VERSION 5.8 ;
BUSBITCHARS "[]" ;
DIVIDERCHAR "/" ;
UNITS
    DATABASE MICRONS 1000 ;
END UNITS

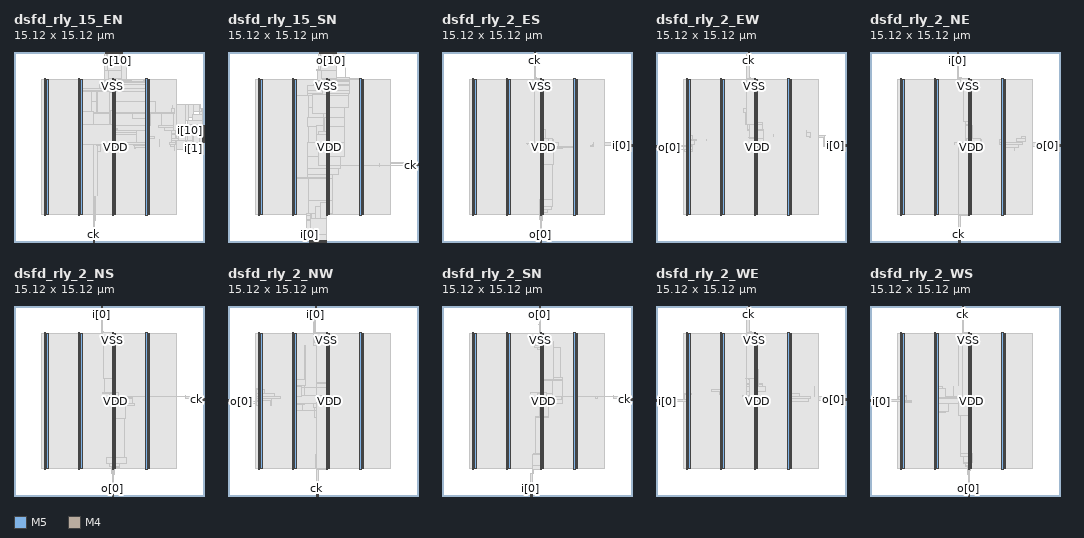
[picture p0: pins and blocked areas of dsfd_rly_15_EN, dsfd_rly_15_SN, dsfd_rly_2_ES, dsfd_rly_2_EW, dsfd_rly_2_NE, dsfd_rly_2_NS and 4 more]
MACRO dsfd_rly_15_EN
  FOREIGN dsfd_rly_15_EN 0 0 ;
  CLASS BLOCK ;
  SIZE 15.12 BY 15.12 ;
  PIN ck
    DIRECTION INPUT ;
    USE SIGNAL ;
    PORT
      LAYER M5 ;
        RECT  6.288 0 6.312 0.084 ;
    END
  END ck
  PIN i[0]
    DIRECTION INPUT ;
    USE SIGNAL ;
    PORT
      LAYER M4 ;
        RECT  15.036 7.92 15.12 7.944 ;
    END
  END i[0]
  PIN i[10]
    DIRECTION INPUT ;
    USE SIGNAL ;
    PORT
      LAYER M4 ;
        RECT  15.036 8.88 15.12 8.904 ;
    END
  END i[10]
  PIN i[11]
    DIRECTION INPUT ;
    USE SIGNAL ;
    PORT
      LAYER M4 ;
        RECT  15.036 8.976 15.12 9 ;
    END
  END i[11]
  PIN i[12]
    DIRECTION INPUT ;
    USE SIGNAL ;
    PORT
      LAYER M4 ;
        RECT  15.036 9.072 15.12 9.096 ;
    END
  END i[12]
  PIN i[13]
    DIRECTION INPUT ;
    USE SIGNAL ;
    PORT
      LAYER M4 ;
        RECT  15.036 9.168 15.12 9.192 ;
    END
  END i[13]
  PIN i[14]
    DIRECTION INPUT ;
    USE SIGNAL ;
    PORT
      LAYER M4 ;
        RECT  15.036 9.264 15.12 9.288 ;
    END
  END i[14]
  PIN i[1]
    DIRECTION INPUT ;
    USE SIGNAL ;
    PORT
      LAYER M4 ;
        RECT  15.036 8.016 15.12 8.04 ;
    END
  END i[1]
  PIN i[2]
    DIRECTION INPUT ;
    USE SIGNAL ;
    PORT
      LAYER M4 ;
        RECT  15.036 8.112 15.12 8.136 ;
    END
  END i[2]
  PIN i[3]
    DIRECTION INPUT ;
    USE SIGNAL ;
    PORT
      LAYER M4 ;
        RECT  15.036 8.208 15.12 8.232 ;
    END
  END i[3]
  PIN i[4]
    DIRECTION INPUT ;
    USE SIGNAL ;
    PORT
      LAYER M4 ;
        RECT  15.036 8.304 15.12 8.328 ;
    END
  END i[4]
  PIN i[5]
    DIRECTION INPUT ;
    USE SIGNAL ;
    PORT
      LAYER M4 ;
        RECT  15.036 8.4 15.12 8.424 ;
    END
  END i[5]
  PIN i[6]
    DIRECTION INPUT ;
    USE SIGNAL ;
    PORT
      LAYER M4 ;
        RECT  15.036 8.496 15.12 8.52 ;
    END
  END i[6]
  PIN i[7]
    DIRECTION INPUT ;
    USE SIGNAL ;
    PORT
      LAYER M4 ;
        RECT  15.036 8.592 15.12 8.616 ;
    END
  END i[7]
  PIN i[8]
    DIRECTION INPUT ;
    USE SIGNAL ;
    PORT
      LAYER M4 ;
        RECT  15.036 8.688 15.12 8.712 ;
    END
  END i[8]
  PIN i[9]
    DIRECTION INPUT ;
    USE SIGNAL ;
    PORT
      LAYER M4 ;
        RECT  15.036 8.784 15.12 8.808 ;
    END
  END i[9]
  PIN o[0]
    DIRECTION OUTPUT ;
    USE SIGNAL ;
    PORT
      LAYER M5 ;
        RECT  7.248 15.036 7.272 15.12 ;
    END
  END o[0]
  PIN o[10]
    DIRECTION OUTPUT ;
    USE SIGNAL ;
    PORT
      LAYER M5 ;
        RECT  8.208 15.036 8.232 15.12 ;
    END
  END o[10]
  PIN o[11]
    DIRECTION OUTPUT ;
    USE SIGNAL ;
    PORT
      LAYER M5 ;
        RECT  8.304 15.036 8.328 15.12 ;
    END
  END o[11]
  PIN o[12]
    DIRECTION OUTPUT ;
    USE SIGNAL ;
    PORT
      LAYER M5 ;
        RECT  8.4 15.036 8.424 15.12 ;
    END
  END o[12]
  PIN o[13]
    DIRECTION OUTPUT ;
    USE SIGNAL ;
    PORT
      LAYER M5 ;
        RECT  8.496 15.036 8.52 15.12 ;
    END
  END o[13]
  PIN o[14]
    DIRECTION OUTPUT ;
    USE SIGNAL ;
    PORT
      LAYER M5 ;
        RECT  8.592 15.036 8.616 15.12 ;
    END
  END o[14]
  PIN o[1]
    DIRECTION OUTPUT ;
    USE SIGNAL ;
    PORT
      LAYER M5 ;
        RECT  7.344 15.036 7.368 15.12 ;
    END
  END o[1]
  PIN o[2]
    DIRECTION OUTPUT ;
    USE SIGNAL ;
    PORT
      LAYER M5 ;
        RECT  7.44 15.036 7.464 15.12 ;
    END
  END o[2]
  PIN o[3]
    DIRECTION OUTPUT ;
    USE SIGNAL ;
    PORT
      LAYER M5 ;
        RECT  7.536 15.036 7.56 15.12 ;
    END
  END o[3]
  PIN o[4]
    DIRECTION OUTPUT ;
    USE SIGNAL ;
    PORT
      LAYER M5 ;
        RECT  7.632 15.036 7.656 15.12 ;
    END
  END o[4]
  PIN o[5]
    DIRECTION OUTPUT ;
    USE SIGNAL ;
    PORT
      LAYER M5 ;
        RECT  7.728 15.036 7.752 15.12 ;
    END
  END o[5]
  PIN o[6]
    DIRECTION OUTPUT ;
    USE SIGNAL ;
    PORT
      LAYER M5 ;
        RECT  7.824 15.036 7.848 15.12 ;
    END
  END o[6]
  PIN o[7]
    DIRECTION OUTPUT ;
    USE SIGNAL ;
    PORT
      LAYER M5 ;
        RECT  7.92 15.036 7.944 15.12 ;
    END
  END o[7]
  PIN o[8]
    DIRECTION OUTPUT ;
    USE SIGNAL ;
    PORT
      LAYER M5 ;
        RECT  8.016 15.036 8.04 15.12 ;
    END
  END o[8]
  PIN o[9]
    DIRECTION OUTPUT ;
    USE SIGNAL ;
    PORT
      LAYER M5 ;
        RECT  8.112 15.036 8.136 15.12 ;
    END
  END o[9]
  PIN rs
    DIRECTION INPUT ;
    USE SIGNAL ;
    PORT
      LAYER M5 ;
        RECT  6.384 0 6.408 0.084 ;
    END
  END rs
  PIN VDD
    DIRECTION INOUT ;
    USE POWER ;
    PORT
      LAYER M5 ;
        RECT  10.692 2.151 10.812 12.969 ;
        RECT  7.992 2.151 8.112 12.969 ;
        RECT  5.292 2.151 5.412 12.969 ;
        RECT  2.592 2.151 2.712 12.969 ;
    END
  END VDD
  PIN VSS
    DIRECTION INOUT ;
    USE GROUND ;
    PORT
      LAYER M5 ;
        RECT  10.5 2.137 10.62 12.983 ;
        RECT  7.8 2.137 7.92 12.983 ;
        RECT  5.1 2.137 5.22 12.983 ;
        RECT  2.4 2.137 2.52 12.983 ;
    END
  END VSS
  OBS
    LAYER RVTN ;
     RECT  2.16 2.16 12.96 2.295 ;
     RECT  2.16 2.565 12.96 2.835 ;
     RECT  2.16 3.105 12.96 3.375 ;
     RECT  2.16 3.645 12.96 3.915 ;
     RECT  2.16 4.185 12.96 4.455 ;
     RECT  2.16 4.725 12.96 4.995 ;
     RECT  2.16 5.265 12.96 5.535 ;
     RECT  2.16 5.805 12.96 6.075 ;
     RECT  2.16 6.345 12.96 6.615 ;
     RECT  2.16 6.885 12.96 7.155 ;
     RECT  2.16 7.425 12.96 7.695 ;
     RECT  2.16 7.965 12.96 8.235 ;
     RECT  2.16 8.505 12.96 8.775 ;
     RECT  2.16 9.045 12.96 9.315 ;
     RECT  2.16 9.585 12.96 9.855 ;
     RECT  2.16 10.125 12.96 10.395 ;
     RECT  2.16 10.665 12.96 10.935 ;
     RECT  2.16 11.205 12.96 11.475 ;
     RECT  2.16 11.745 12.96 12.015 ;
     RECT  2.16 12.285 12.96 12.555 ;
     RECT  2.16 12.825 12.96 12.96 ;
    LAYER RVTP ;
     RECT  2.16 2.295 12.96 2.565 ;
     RECT  2.16 2.835 12.96 3.105 ;
     RECT  2.16 3.375 12.96 3.645 ;
     RECT  2.16 3.915 12.96 4.185 ;
     RECT  2.16 4.455 12.96 4.725 ;
     RECT  2.16 4.995 12.96 5.265 ;
     RECT  2.16 5.535 12.96 5.805 ;
     RECT  2.16 6.075 12.96 6.345 ;
     RECT  2.16 6.615 12.96 6.885 ;
     RECT  2.16 7.155 12.96 7.425 ;
     RECT  2.16 7.695 12.96 7.965 ;
     RECT  2.16 8.235 12.96 8.505 ;
     RECT  2.16 8.775 12.96 9.045 ;
     RECT  2.16 9.315 12.96 9.585 ;
     RECT  2.16 9.855 12.96 10.125 ;
     RECT  2.16 10.395 12.96 10.665 ;
     RECT  2.16 10.935 12.96 11.205 ;
     RECT  2.16 11.475 12.96 11.745 ;
     RECT  2.16 12.015 12.96 12.285 ;
     RECT  2.16 12.555 12.96 12.825 ;
    LAYER M1 ;
     RECT  2.16 2.151 12.96 12.969 ;
    LAYER M2 ;
     RECT  2.16 2.151 12.96 12.969 ;
     RECT  12.96 7.398 13.667 10.926 ;
     RECT  13.667 9.63 13.847 10.926 ;
     RECT  13.667 7.398 14.243 8.802 ;
     RECT  14.243 7.398 14.279 7.956 ;
     RECT  13.847 9.9 14.279 10.926 ;
     RECT  14.279 7.938 14.315 7.956 ;
     RECT  14.279 10.368 14.819 10.926 ;
     RECT  14.819 10.368 14.963 10.656 ;
     RECT  14.963 10.368 15.035 10.386 ;
    LAYER M3 ;
     RECT  2.415 2.143 2.505 2.413 ;
     RECT  5.115 2.143 5.205 2.413 ;
     RECT  7.815 2.143 7.905 2.413 ;
     RECT  10.515 2.143 10.605 2.413 ;
     RECT  6.444 1.723 6.462 3.605 ;
     RECT  6.66 3.721 6.678 7.231 ;
     RECT  7.815 2.413 8.097 7.465 ;
     RECT  9.648 7.429 9.666 7.465 ;
     RECT  7.815 7.465 8.478 7.501 ;
     RECT  9.612 7.465 9.666 7.501 ;
     RECT  10.515 2.413 10.797 7.501 ;
     RECT  12.744 7.321 12.762 7.627 ;
     RECT  6.66 7.231 6.894 7.699 ;
     RECT  7.815 7.501 8.55 7.699 ;
     RECT  9.612 7.501 10.797 7.699 ;
     RECT  12.456 7.627 12.762 7.735 ;
     RECT  7.812 7.699 8.55 7.765 ;
     RECT  6.552 7.699 6.894 7.771 ;
     RECT  7.668 7.765 8.55 7.771 ;
     RECT  9.504 7.699 10.797 7.771 ;
     RECT  12.456 7.735 12.834 7.771 ;
     RECT  14.256 7.393 14.274 7.771 ;
     RECT  6.408 7.771 10.797 7.889 ;
     RECT  12.348 7.771 12.834 7.925 ;
     RECT  13.716 7.771 14.274 7.933 ;
     RECT  12.528 7.925 12.834 8.107 ;
     RECT  13.716 7.933 14.31 8.107 ;
     RECT  11.556 7.591 11.574 8.159 ;
     RECT  10.515 7.889 10.797 8.203 ;
     RECT  12.528 8.107 14.31 8.267 ;
     RECT  13.644 8.267 14.31 8.395 ;
     RECT  10.515 8.203 11.142 8.429 ;
     RECT  6.408 7.889 9.738 8.581 ;
     RECT  5.115 2.413 5.397 8.683 ;
     RECT  6.228 8.581 9.738 8.683 ;
     RECT  5.115 8.683 9.738 8.843 ;
     RECT  6.192 8.843 9.738 8.851 ;
     RECT  10.515 8.429 10.797 8.851 ;
     RECT  12.528 8.267 12.834 8.851 ;
     RECT  11.988 8.851 12.834 8.879 ;
     RECT  11.988 8.879 12.69 9.085 ;
     RECT  11.52 9.085 12.69 9.275 ;
     RECT  6.192 8.851 10.797 9.283 ;
     RECT  13.644 8.395 15.03 9.383 ;
     RECT  13.824 9.383 15.03 9.653 ;
     RECT  14.22 9.653 15.03 10.121 ;
     RECT  6.192 9.283 10.854 10.201 ;
     RECT  11.736 9.275 12.69 10.201 ;
     RECT  6.192 10.201 12.762 10.319 ;
     RECT  14.796 10.121 15.03 10.391 ;
     RECT  12.564 10.319 12.762 10.589 ;
     RECT  12.6 10.589 12.762 10.625 ;
     RECT  14.796 10.391 14.958 10.661 ;
     RECT  12.6 10.625 12.618 10.859 ;
     RECT  14.796 10.661 14.814 10.931 ;
     RECT  6.192 10.319 11.286 11.201 ;
     RECT  5.115 8.843 5.397 11.995 ;
     RECT  6.192 11.201 10.797 11.995 ;
     RECT  5.115 11.995 10.797 12.209 ;
     RECT  6.804 12.209 10.797 12.245 ;
     RECT  6.84 12.245 10.797 12.551 ;
     RECT  2.415 2.413 2.697 12.707 ;
     RECT  5.115 12.209 5.397 12.707 ;
     RECT  6.984 12.551 10.797 12.707 ;
     RECT  6.984 12.707 10.605 12.749 ;
     RECT  6.984 12.749 9.342 12.785 ;
     RECT  7.2 12.785 9.342 12.821 ;
     RECT  10.332 12.749 10.605 12.821 ;
     RECT  7.2 12.821 9.054 12.929 ;
     RECT  2.415 12.707 2.505 12.977 ;
     RECT  5.115 12.707 5.205 12.977 ;
     RECT  10.515 12.821 10.605 12.977 ;
     RECT  7.2 12.929 8.982 14.237 ;
     RECT  7.2 14.237 8.478 14.717 ;
     RECT  7.2 14.717 7.398 15.005 ;
     RECT  8.208 14.717 8.478 15.005 ;
    LAYER M4 ;
     RECT  2.408 2.148 2.512 12.972 ;
     RECT  2.512 2.418 2.704 12.702 ;
     RECT  5.108 2.148 5.212 12.972 ;
     RECT  5.212 2.418 5.404 12.702 ;
     RECT  5.404 8.688 6.397 8.712 ;
     RECT  6.373 1.728 6.473 1.752 ;
     RECT  5.404 10.32 6.565 10.344 ;
     RECT  5.404 12 6.565 12.024 ;
     RECT  6.565 10.32 6.611 12.024 ;
     RECT  6.397 7.776 6.853 8.712 ;
     RECT  7.297 13.632 7.475 13.656 ;
     RECT  6.853 7.776 7.585 9.336 ;
     RECT  6.611 10.32 7.585 11.976 ;
     RECT  7.189 14.976 7.765 15 ;
     RECT  7.585 7.776 7.808 11.976 ;
     RECT  7.685 13.056 7.808 13.128 ;
     RECT  7.808 2.148 7.912 13.128 ;
     RECT  7.912 2.418 7.985 13.128 ;
     RECT  7.985 2.418 8.104 13.08 ;
     RECT  8.104 11.184 8.165 11.208 ;
     RECT  8.104 8.976 8.237 9 ;
     RECT  8.104 12.288 8.317 13.08 ;
     RECT  8.317 13.008 8.453 13.08 ;
     RECT  7.765 14.688 8.489 15 ;
     RECT  8.453 13.008 8.561 13.032 ;
     RECT  8.104 7.92 8.597 7.944 ;
     RECT  8.581 14.208 8.993 14.232 ;
     RECT  9.133 10.224 9.421 10.248 ;
     RECT  9.421 9.792 10.508 10.248 ;
     RECT  10.508 2.148 10.612 12.972 ;
     RECT  10.612 2.418 10.804 12.702 ;
     RECT  12.589 8.592 13.057 8.616 ;
     RECT  13.057 8.112 13.633 8.616 ;
     RECT  13.633 8.112 13.813 9 ;
     RECT  13.813 8.112 14.209 9.096 ;
     RECT  14.209 8.016 14.245 9.192 ;
     RECT  14.245 7.92 14.785 9.192 ;
     RECT  14.785 7.92 15.084 9.288 ;
    LAYER M5 ;
     RECT  6.288 0.016 6.408 1.763 ;
     RECT  2.4 2.137 2.52 2.151 ;
     RECT  5.1 2.137 5.22 2.151 ;
     RECT  6.288 1.763 6.312 2.151 ;
     RECT  7.8 2.137 7.92 2.151 ;
     RECT  10.5 2.137 10.62 2.151 ;
     RECT  5.1 2.151 6.312 7.765 ;
     RECT  7.8 2.151 8.112 7.765 ;
     RECT  5.1 7.765 8.112 9.347 ;
     RECT  5.1 9.347 6.312 10.355 ;
     RECT  7.68 9.347 8.112 10.451 ;
     RECT  7.8 10.451 8.112 11.893 ;
     RECT  6.576 11.173 6.6 11.941 ;
     RECT  7.632 11.893 8.112 11.941 ;
     RECT  6.576 11.941 8.112 12.035 ;
     RECT  7.536 12.035 8.112 12.277 ;
     RECT  2.4 2.151 2.712 12.969 ;
     RECT  5.1 10.355 5.412 12.969 ;
     RECT  10.5 2.151 10.812 12.969 ;
     RECT  2.4 12.969 2.52 12.983 ;
     RECT  5.1 12.969 5.22 12.983 ;
     RECT  10.5 12.969 10.62 12.983 ;
     RECT  7.536 12.277 8.28 12.997 ;
     RECT  7.536 12.997 8.52 13.621 ;
     RECT  7.44 13.621 8.52 14.197 ;
     RECT  7.44 14.197 8.616 14.965 ;
     RECT  7.248 14.965 8.616 15.056 ;
  END
END dsfd_rly_15_EN

VERSION 5.8 ;
BUSBITCHARS "[]" ;
DIVIDERCHAR "/" ;
UNITS
    DATABASE MICRONS 1000 ;
END UNITS

MACRO dsfd_rly_15_SN
  FOREIGN dsfd_rly_15_SN 0 0 ;
  CLASS BLOCK ;
  SIZE 15.12 BY 15.12 ;
  PIN ck
    DIRECTION INPUT ;
    USE SIGNAL ;
    PORT
      LAYER M4 ;
        RECT  15.036 6.096 15.12 6.12 ;
    END
  END ck
  PIN i[0]
    DIRECTION INPUT ;
    USE SIGNAL ;
    PORT
      LAYER M5 ;
        RECT  6.48 0 6.504 0.084 ;
    END
  END i[0]
  PIN i[10]
    DIRECTION INPUT ;
    USE SIGNAL ;
    PORT
      LAYER M5 ;
        RECT  7.44 0 7.464 0.084 ;
    END
  END i[10]
  PIN i[11]
    DIRECTION INPUT ;
    USE SIGNAL ;
    PORT
      LAYER M5 ;
        RECT  7.536 0 7.56 0.084 ;
    END
  END i[11]
  PIN i[12]
    DIRECTION INPUT ;
    USE SIGNAL ;
    PORT
      LAYER M5 ;
        RECT  7.632 0 7.656 0.084 ;
    END
  END i[12]
  PIN i[13]
    DIRECTION INPUT ;
    USE SIGNAL ;
    PORT
      LAYER M5 ;
        RECT  7.728 0 7.752 0.084 ;
    END
  END i[13]
  PIN i[14]
    DIRECTION INPUT ;
    USE SIGNAL ;
    PORT
      LAYER M5 ;
        RECT  7.824 0 7.848 0.084 ;
    END
  END i[14]
  PIN i[1]
    DIRECTION INPUT ;
    USE SIGNAL ;
    PORT
      LAYER M5 ;
        RECT  6.576 0 6.6 0.084 ;
    END
  END i[1]
  PIN i[2]
    DIRECTION INPUT ;
    USE SIGNAL ;
    PORT
      LAYER M5 ;
        RECT  6.672 0 6.696 0.084 ;
    END
  END i[2]
  PIN i[3]
    DIRECTION INPUT ;
    USE SIGNAL ;
    PORT
      LAYER M5 ;
        RECT  6.768 0 6.792 0.084 ;
    END
  END i[3]
  PIN i[4]
    DIRECTION INPUT ;
    USE SIGNAL ;
    PORT
      LAYER M5 ;
        RECT  6.864 0 6.888 0.084 ;
    END
  END i[4]
  PIN i[5]
    DIRECTION INPUT ;
    USE SIGNAL ;
    PORT
      LAYER M5 ;
        RECT  6.96 0 6.984 0.084 ;
    END
  END i[5]
  PIN i[6]
    DIRECTION INPUT ;
    USE SIGNAL ;
    PORT
      LAYER M5 ;
        RECT  7.056 0 7.08 0.084 ;
    END
  END i[6]
  PIN i[7]
    DIRECTION INPUT ;
    USE SIGNAL ;
    PORT
      LAYER M5 ;
        RECT  7.152 0 7.176 0.084 ;
    END
  END i[7]
  PIN i[8]
    DIRECTION INPUT ;
    USE SIGNAL ;
    PORT
      LAYER M5 ;
        RECT  7.248 0 7.272 0.084 ;
    END
  END i[8]
  PIN i[9]
    DIRECTION INPUT ;
    USE SIGNAL ;
    PORT
      LAYER M5 ;
        RECT  7.344 0 7.368 0.084 ;
    END
  END i[9]
  PIN o[0]
    DIRECTION OUTPUT ;
    USE SIGNAL ;
    PORT
      LAYER M5 ;
        RECT  7.248 15.036 7.272 15.12 ;
    END
  END o[0]
  PIN o[10]
    DIRECTION OUTPUT ;
    USE SIGNAL ;
    PORT
      LAYER M5 ;
        RECT  8.208 15.036 8.232 15.12 ;
    END
  END o[10]
  PIN o[11]
    DIRECTION OUTPUT ;
    USE SIGNAL ;
    PORT
      LAYER M5 ;
        RECT  8.304 15.036 8.328 15.12 ;
    END
  END o[11]
  PIN o[12]
    DIRECTION OUTPUT ;
    USE SIGNAL ;
    PORT
      LAYER M5 ;
        RECT  8.4 15.036 8.424 15.12 ;
    END
  END o[12]
  PIN o[13]
    DIRECTION OUTPUT ;
    USE SIGNAL ;
    PORT
      LAYER M5 ;
        RECT  8.496 15.036 8.52 15.12 ;
    END
  END o[13]
  PIN o[14]
    DIRECTION OUTPUT ;
    USE SIGNAL ;
    PORT
      LAYER M5 ;
        RECT  8.592 15.036 8.616 15.12 ;
    END
  END o[14]
  PIN o[1]
    DIRECTION OUTPUT ;
    USE SIGNAL ;
    PORT
      LAYER M5 ;
        RECT  7.344 15.036 7.368 15.12 ;
    END
  END o[1]
  PIN o[2]
    DIRECTION OUTPUT ;
    USE SIGNAL ;
    PORT
      LAYER M5 ;
        RECT  7.44 15.036 7.464 15.12 ;
    END
  END o[2]
  PIN o[3]
    DIRECTION OUTPUT ;
    USE SIGNAL ;
    PORT
      LAYER M5 ;
        RECT  7.536 15.036 7.56 15.12 ;
    END
  END o[3]
  PIN o[4]
    DIRECTION OUTPUT ;
    USE SIGNAL ;
    PORT
      LAYER M5 ;
        RECT  7.632 15.036 7.656 15.12 ;
    END
  END o[4]
  PIN o[5]
    DIRECTION OUTPUT ;
    USE SIGNAL ;
    PORT
      LAYER M5 ;
        RECT  7.728 15.036 7.752 15.12 ;
    END
  END o[5]
  PIN o[6]
    DIRECTION OUTPUT ;
    USE SIGNAL ;
    PORT
      LAYER M5 ;
        RECT  7.824 15.036 7.848 15.12 ;
    END
  END o[6]
  PIN o[7]
    DIRECTION OUTPUT ;
    USE SIGNAL ;
    PORT
      LAYER M5 ;
        RECT  7.92 15.036 7.944 15.12 ;
    END
  END o[7]
  PIN o[8]
    DIRECTION OUTPUT ;
    USE SIGNAL ;
    PORT
      LAYER M5 ;
        RECT  8.016 15.036 8.04 15.12 ;
    END
  END o[8]
  PIN o[9]
    DIRECTION OUTPUT ;
    USE SIGNAL ;
    PORT
      LAYER M5 ;
        RECT  8.112 15.036 8.136 15.12 ;
    END
  END o[9]
  PIN rs
    DIRECTION INPUT ;
    USE SIGNAL ;
    PORT
      LAYER M4 ;
        RECT  15.036 6.192 15.12 6.216 ;
    END
  END rs
  PIN VDD
    DIRECTION INOUT ;
    USE POWER ;
    PORT
      LAYER M5 ;
        RECT  10.692 2.151 10.812 12.969 ;
        RECT  7.992 2.151 8.112 12.969 ;
        RECT  5.292 2.151 5.412 12.969 ;
        RECT  2.592 2.151 2.712 12.969 ;
    END
  END VDD
  PIN VSS
    DIRECTION INOUT ;
    USE GROUND ;
    PORT
      LAYER M5 ;
        RECT  10.5 2.137 10.62 12.983 ;
        RECT  7.8 2.137 7.92 12.983 ;
        RECT  5.1 2.137 5.22 12.983 ;
        RECT  2.4 2.137 2.52 12.983 ;
    END
  END VSS
  OBS
    LAYER RVTN ;
     RECT  2.16 2.16 12.96 2.295 ;
     RECT  2.16 2.565 12.96 2.835 ;
     RECT  2.16 3.105 12.96 3.375 ;
     RECT  2.16 3.645 12.96 3.915 ;
     RECT  2.16 4.185 12.96 4.455 ;
     RECT  2.16 4.725 12.96 4.995 ;
     RECT  2.16 5.265 12.96 5.535 ;
     RECT  2.16 5.805 12.96 6.075 ;
     RECT  2.16 6.345 12.96 6.615 ;
     RECT  2.16 6.885 12.96 7.155 ;
     RECT  2.16 7.425 12.96 7.695 ;
     RECT  2.16 7.965 12.96 8.235 ;
     RECT  2.16 8.505 12.96 8.775 ;
     RECT  2.16 9.045 12.96 9.315 ;
     RECT  2.16 9.585 12.96 9.855 ;
     RECT  2.16 10.125 12.96 10.395 ;
     RECT  2.16 10.665 12.96 10.935 ;
     RECT  2.16 11.205 12.96 11.475 ;
     RECT  2.16 11.745 12.96 12.015 ;
     RECT  2.16 12.285 12.96 12.555 ;
     RECT  2.16 12.825 12.96 12.96 ;
    LAYER RVTP ;
     RECT  2.16 2.295 12.96 2.565 ;
     RECT  2.16 2.835 12.96 3.105 ;
     RECT  2.16 3.375 12.96 3.645 ;
     RECT  2.16 3.915 12.96 4.185 ;
     RECT  2.16 4.455 12.96 4.725 ;
     RECT  2.16 4.995 12.96 5.265 ;
     RECT  2.16 5.535 12.96 5.805 ;
     RECT  2.16 6.075 12.96 6.345 ;
     RECT  2.16 6.615 12.96 6.885 ;
     RECT  2.16 7.155 12.96 7.425 ;
     RECT  2.16 7.695 12.96 7.965 ;
     RECT  2.16 8.235 12.96 8.505 ;
     RECT  2.16 8.775 12.96 9.045 ;
     RECT  2.16 9.315 12.96 9.585 ;
     RECT  2.16 9.855 12.96 10.125 ;
     RECT  2.16 10.395 12.96 10.665 ;
     RECT  2.16 10.935 12.96 11.205 ;
     RECT  2.16 11.475 12.96 11.745 ;
     RECT  2.16 12.015 12.96 12.285 ;
     RECT  2.16 12.555 12.96 12.825 ;
    LAYER M1 ;
     RECT  2.16 2.151 12.96 12.969 ;
    LAYER M2 ;
     RECT  2.16 2.151 12.96 12.969 ;
     RECT  12.96 6.282 14.243 6.3 ;
    LAYER M3 ;
     RECT  7.2 0.091 7.218 0.571 ;
     RECT  6.264 0.571 7.218 1.723 ;
     RECT  6.264 1.723 7.758 1.819 ;
     RECT  6.264 1.819 7.794 2.143 ;
     RECT  6.264 2.143 7.905 2.255 ;
     RECT  6.408 2.255 7.905 2.263 ;
     RECT  2.415 2.143 2.505 2.413 ;
     RECT  5.115 2.143 5.205 2.413 ;
     RECT  10.515 2.143 10.605 2.413 ;
     RECT  6.408 2.263 8.298 3.335 ;
     RECT  6.444 3.335 8.298 5.035 ;
     RECT  6.3 5.035 8.298 5.341 ;
     RECT  6.3 5.341 8.766 5.881 ;
     RECT  12.024 6.007 12.042 6.269 ;
     RECT  14.22 6.187 14.238 6.305 ;
     RECT  6.3 5.881 8.982 6.817 ;
     RECT  6.3 6.817 9.306 7.925 ;
     RECT  6.444 7.925 9.306 9.211 ;
     RECT  6.336 9.211 9.306 9.923 ;
     RECT  6.372 9.923 9.306 10.741 ;
     RECT  6.372 10.741 9.594 11.659 ;
     RECT  6.3 11.659 9.594 11.821 ;
     RECT  6.3 11.821 9.666 12.083 ;
     RECT  6.336 12.083 9.666 12.479 ;
     RECT  6.768 12.479 9.666 12.551 ;
     RECT  2.415 2.413 2.697 12.707 ;
     RECT  5.115 2.413 5.397 12.707 ;
     RECT  10.515 2.413 10.797 12.707 ;
     RECT  6.912 12.551 9.666 12.785 ;
     RECT  7.092 12.785 9.666 12.857 ;
     RECT  9.324 12.857 9.666 12.901 ;
     RECT  2.415 12.707 2.505 12.977 ;
     RECT  5.115 12.707 5.205 12.977 ;
     RECT  10.515 12.707 10.605 12.977 ;
     RECT  9.324 12.901 9.702 12.989 ;
     RECT  9.324 12.989 9.666 13.085 ;
     RECT  7.092 12.857 8.586 13.661 ;
     RECT  7.092 13.661 7.722 13.709 ;
     RECT  8.568 13.661 8.586 14.957 ;
     RECT  7.2 13.709 7.722 15.005 ;
     RECT  9.324 13.085 9.342 15.005 ;
    LAYER M4 ;
     RECT  2.408 2.148 2.512 12.972 ;
     RECT  2.512 2.418 2.704 12.702 ;
     RECT  5.108 2.148 5.212 12.972 ;
     RECT  5.212 2.418 5.404 12.702 ;
     RECT  6.397 2.256 6.649 2.28 ;
     RECT  5.404 11.664 6.755 11.688 ;
     RECT  6.709 10.224 6.797 10.248 ;
     RECT  6.649 1.728 6.973 2.28 ;
     RECT  6.253 0.576 6.995 0.6 ;
     RECT  7.009 9.216 7.045 9.24 ;
     RECT  7.189 6.096 7.225 6.12 ;
     RECT  7.004 7.344 7.225 7.368 ;
     RECT  6.973 1.728 7.333 2.856 ;
     RECT  7.081 13.68 7.379 13.704 ;
     RECT  7.189 0.096 7.475 0.12 ;
     RECT  7.189 14.976 7.525 15 ;
     RECT  7.045 8.544 7.621 9.24 ;
     RECT  7.333 1.728 7.804 3.144 ;
     RECT  7.804 1.824 7.808 3.144 ;
     RECT  5.404 5.088 7.808 5.112 ;
     RECT  7.225 6.096 7.808 7.368 ;
     RECT  7.621 8.544 7.808 9.912 ;
     RECT  7.525 11.232 7.808 11.448 ;
     RECT  7.405 13.056 7.808 13.656 ;
     RECT  7.808 1.824 7.859 13.656 ;
     RECT  7.859 2.148 7.912 13.656 ;
     RECT  7.525 14.736 7.955 15 ;
     RECT  7.912 2.418 8.104 13.656 ;
     RECT  8.104 12.816 8.345 13.656 ;
     RECT  8.345 12.816 8.489 13.608 ;
     RECT  8.489 12.816 8.561 13.08 ;
     RECT  7.955 14.928 8.597 15 ;
     RECT  8.597 14.976 9.353 15 ;
     RECT  8.561 12.96 9.677 13.08 ;
     RECT  9.677 12.96 9.713 12.984 ;
     RECT  8.104 6.096 10.508 6.12 ;
     RECT  9.713 12.96 10.508 12.972 ;
     RECT  10.508 2.148 10.612 12.972 ;
     RECT  10.612 2.418 10.804 12.702 ;
     RECT  10.804 6.096 14.209 6.12 ;
     RECT  14.209 6.096 15.084 6.216 ;
    LAYER M5 ;
     RECT  6.48 0.016 7.848 0.611 ;
     RECT  6.576 0.611 7.848 1.907 ;
     RECT  7.8 1.907 7.848 2.137 ;
     RECT  2.4 2.137 2.52 2.151 ;
     RECT  5.1 2.137 5.22 2.151 ;
     RECT  7.8 2.137 7.92 2.151 ;
     RECT  10.5 2.137 10.62 2.151 ;
     RECT  6.576 1.907 6.6 2.291 ;
     RECT  7.8 2.151 8.112 6.085 ;
     RECT  7.2 6.085 8.112 7.333 ;
     RECT  7.056 7.333 8.112 8.579 ;
     RECT  7.2 8.579 8.112 8.771 ;
     RECT  7.68 8.771 8.112 9.877 ;
     RECT  7.632 9.877 8.112 10.213 ;
     RECT  6.72 10.213 8.112 11.699 ;
     RECT  7.536 11.699 8.112 12.949 ;
     RECT  2.4 2.151 2.712 12.969 ;
     RECT  5.1 2.151 5.412 12.969 ;
     RECT  10.5 2.151 10.812 12.969 ;
     RECT  2.4 12.969 2.52 12.983 ;
     RECT  5.1 12.969 5.22 12.983 ;
     RECT  10.5 12.969 10.62 12.983 ;
     RECT  7.536 12.949 8.616 13.045 ;
     RECT  7.44 13.045 8.616 13.669 ;
     RECT  7.344 13.669 8.616 14.965 ;
     RECT  7.248 14.965 8.616 15.056 ;
  END
END dsfd_rly_15_SN

VERSION 5.8 ;
BUSBITCHARS "[]" ;
DIVIDERCHAR "/" ;
UNITS
    DATABASE MICRONS 1000 ;
END UNITS

MACRO dsfd_rly_2_ES
  FOREIGN dsfd_rly_2_ES 0 0 ;
  CLASS BLOCK ;
  SIZE 15.12 BY 15.12 ;
  PIN ck
    DIRECTION INPUT ;
    USE SIGNAL ;
    PORT
      LAYER M5 ;
        RECT  7.344 15.036 7.368 15.12 ;
    END
  END ck
  PIN i[0]
    DIRECTION INPUT ;
    USE SIGNAL ;
    PORT
      LAYER M4 ;
        RECT  15.036 7.632 15.12 7.656 ;
    END
  END i[0]
  PIN i[1]
    DIRECTION INPUT ;
    USE SIGNAL ;
    PORT
      LAYER M4 ;
        RECT  15.036 7.728 15.12 7.752 ;
    END
  END i[1]
  PIN o[0]
    DIRECTION OUTPUT ;
    USE SIGNAL ;
    PORT
      LAYER M5 ;
        RECT  7.824 0 7.848 0.084 ;
    END
  END o[0]
  PIN o[1]
    DIRECTION OUTPUT ;
    USE SIGNAL ;
    PORT
      LAYER M5 ;
        RECT  7.92 0 7.944 0.084 ;
    END
  END o[1]
  PIN rs
    DIRECTION INPUT ;
    USE SIGNAL ;
    PORT
      LAYER M5 ;
        RECT  7.44 15.036 7.464 15.12 ;
    END
  END rs
  PIN VDD
    DIRECTION INOUT ;
    USE POWER ;
    PORT
      LAYER M5 ;
        RECT  10.692 2.151 10.812 12.969 ;
        RECT  7.992 2.151 8.112 12.969 ;
        RECT  5.292 2.151 5.412 12.969 ;
        RECT  2.592 2.151 2.712 12.969 ;
    END
  END VDD
  PIN VSS
    DIRECTION INOUT ;
    USE GROUND ;
    PORT
      LAYER M5 ;
        RECT  10.5 2.137 10.62 12.983 ;
        RECT  7.8 2.137 7.92 12.983 ;
        RECT  5.1 2.137 5.22 12.983 ;
        RECT  2.4 2.137 2.52 12.983 ;
    END
  END VSS
  OBS
    LAYER RVTN ;
     RECT  2.16 2.16 12.96 2.295 ;
     RECT  2.16 2.565 12.96 2.835 ;
     RECT  2.16 3.105 12.96 3.375 ;
     RECT  2.16 3.645 12.96 3.915 ;
     RECT  2.16 4.185 12.96 4.455 ;
     RECT  2.16 4.725 12.96 4.995 ;
     RECT  2.16 5.265 12.96 5.535 ;
     RECT  2.16 5.805 12.96 6.075 ;
     RECT  2.16 6.345 12.96 6.615 ;
     RECT  2.16 6.885 12.96 7.155 ;
     RECT  2.16 7.425 12.96 7.695 ;
     RECT  2.16 7.965 12.96 8.235 ;
     RECT  2.16 8.505 12.96 8.775 ;
     RECT  2.16 9.045 12.96 9.315 ;
     RECT  2.16 9.585 12.96 9.855 ;
     RECT  2.16 10.125 12.96 10.395 ;
     RECT  2.16 10.665 12.96 10.935 ;
     RECT  2.16 11.205 12.96 11.475 ;
     RECT  2.16 11.745 12.96 12.015 ;
     RECT  2.16 12.285 12.96 12.555 ;
     RECT  2.16 12.825 12.96 12.96 ;
    LAYER RVTP ;
     RECT  2.16 2.295 12.96 2.565 ;
     RECT  2.16 2.835 12.96 3.105 ;
     RECT  2.16 3.375 12.96 3.645 ;
     RECT  2.16 3.915 12.96 4.185 ;
     RECT  2.16 4.455 12.96 4.725 ;
     RECT  2.16 4.995 12.96 5.265 ;
     RECT  2.16 5.535 12.96 5.805 ;
     RECT  2.16 6.075 12.96 6.345 ;
     RECT  2.16 6.615 12.96 6.885 ;
     RECT  2.16 7.155 12.96 7.425 ;
     RECT  2.16 7.695 12.96 7.965 ;
     RECT  2.16 8.235 12.96 8.505 ;
     RECT  2.16 8.775 12.96 9.045 ;
     RECT  2.16 9.315 12.96 9.585 ;
     RECT  2.16 9.855 12.96 10.125 ;
     RECT  2.16 10.395 12.96 10.665 ;
     RECT  2.16 10.935 12.96 11.205 ;
     RECT  2.16 11.475 12.96 11.745 ;
     RECT  2.16 12.015 12.96 12.285 ;
     RECT  2.16 12.555 12.96 12.825 ;
    LAYER M1 ;
     RECT  2.16 2.151 12.96 12.969 ;
    LAYER M2 ;
     RECT  2.16 2.151 12.96 12.969 ;
     RECT  12.96 7.668 13.667 7.956 ;
    LAYER M3 ;
     RECT  7.956 1.723 7.974 1.771 ;
     RECT  7.776 1.771 7.974 2.227 ;
     RECT  7.74 2.227 7.974 2.335 ;
     RECT  2.415 2.143 2.505 2.413 ;
     RECT  5.115 2.143 5.205 2.413 ;
     RECT  10.515 2.143 10.605 2.413 ;
     RECT  7.74 2.335 8.37 2.605 ;
     RECT  7.74 2.605 8.694 2.803 ;
     RECT  7.74 2.803 8.766 3.371 ;
     RECT  7.815 3.371 8.766 6.151 ;
     RECT  7.815 6.151 8.838 7.465 ;
     RECT  7.632 7.465 9.558 7.501 ;
     RECT  10.515 2.413 10.797 7.501 ;
     RECT  7.632 7.501 10.797 7.619 ;
     RECT  11.844 7.591 11.862 7.627 ;
     RECT  11.844 7.627 12.042 7.691 ;
     RECT  11.952 7.691 12.042 7.763 ;
     RECT  6.768 7.735 6.786 7.853 ;
     RECT  7.704 7.619 9.306 7.889 ;
     RECT  12.024 7.763 12.042 7.889 ;
     RECT  7.704 7.889 8.946 7.925 ;
     RECT  7.704 7.925 8.91 7.949 ;
     RECT  13.644 7.627 13.662 7.961 ;
     RECT  7.815 7.949 8.91 8.159 ;
     RECT  7.815 8.159 8.802 8.237 ;
     RECT  7.815 8.237 8.262 8.969 ;
     RECT  7.815 8.969 8.097 9.085 ;
     RECT  7.596 9.085 8.097 12.325 ;
     RECT  2.415 2.413 2.697 12.707 ;
     RECT  5.115 2.413 5.397 12.707 ;
     RECT  7.524 12.325 8.097 12.707 ;
     RECT  10.515 7.619 10.797 12.707 ;
     RECT  2.415 12.707 2.505 12.977 ;
     RECT  5.115 12.707 5.205 12.977 ;
     RECT  7.524 12.707 7.905 12.977 ;
     RECT  10.515 12.707 10.605 12.977 ;
     RECT  7.524 12.977 7.542 13.085 ;
    LAYER M4 ;
     RECT  2.408 2.148 2.512 12.972 ;
     RECT  2.512 2.418 2.704 12.702 ;
     RECT  5.108 2.148 5.212 12.972 ;
     RECT  5.212 2.418 5.404 12.702 ;
     RECT  6.757 7.824 7.333 7.848 ;
     RECT  7.429 13.056 7.553 13.08 ;
     RECT  7.333 7.824 7.669 7.944 ;
     RECT  7.765 1.776 7.808 1.8 ;
     RECT  7.669 7.824 7.808 8.232 ;
     RECT  7.808 1.776 7.813 12.972 ;
     RECT  7.813 1.728 7.912 12.972 ;
     RECT  7.912 1.728 7.985 12.702 ;
     RECT  7.985 2.418 8.104 12.702 ;
     RECT  8.104 7.728 8.453 8.232 ;
     RECT  8.453 7.92 8.813 8.232 ;
     RECT  8.813 7.92 8.921 7.944 ;
     RECT  10.508 2.148 10.612 12.972 ;
     RECT  10.612 2.418 10.804 12.702 ;
     RECT  13.633 7.632 15.084 7.752 ;
    LAYER M5 ;
     RECT  7.824 0.016 7.944 2.137 ;
     RECT  2.4 2.137 2.52 2.151 ;
     RECT  5.1 2.137 5.22 2.151 ;
     RECT  7.8 2.137 7.944 2.151 ;
     RECT  10.5 2.137 10.62 2.151 ;
     RECT  7.8 2.151 8.112 7.813 ;
     RECT  7.68 7.813 8.112 7.909 ;
     RECT  2.4 2.151 2.712 12.969 ;
     RECT  5.1 2.151 5.412 12.969 ;
     RECT  7.344 7.909 8.112 12.969 ;
     RECT  10.5 2.151 10.812 12.969 ;
     RECT  2.4 12.969 2.52 12.983 ;
     RECT  5.1 12.969 5.22 12.983 ;
     RECT  7.344 12.969 7.92 12.983 ;
     RECT  10.5 12.969 10.62 12.983 ;
     RECT  7.344 12.983 7.464 15.056 ;
  END
END dsfd_rly_2_ES

VERSION 5.8 ;
BUSBITCHARS "[]" ;
DIVIDERCHAR "/" ;
UNITS
    DATABASE MICRONS 1000 ;
END UNITS

MACRO dsfd_rly_2_EW
  FOREIGN dsfd_rly_2_EW 0 0 ;
  CLASS BLOCK ;
  SIZE 15.12 BY 15.12 ;
  PIN ck
    DIRECTION INPUT ;
    USE SIGNAL ;
    PORT
      LAYER M5 ;
        RECT  7.344 15.036 7.368 15.12 ;
    END
  END ck
  PIN i[0]
    DIRECTION INPUT ;
    USE SIGNAL ;
    PORT
      LAYER M4 ;
        RECT  15.036 7.632 15.12 7.656 ;
    END
  END i[0]
  PIN i[1]
    DIRECTION INPUT ;
    USE SIGNAL ;
    PORT
      LAYER M4 ;
        RECT  15.036 7.728 15.12 7.752 ;
    END
  END i[1]
  PIN o[0]
    DIRECTION OUTPUT ;
    USE SIGNAL ;
    PORT
      LAYER M4 ;
        RECT  0 7.536 0.084 7.56 ;
    END
  END o[0]
  PIN o[1]
    DIRECTION OUTPUT ;
    USE SIGNAL ;
    PORT
      LAYER M4 ;
        RECT  0 7.632 0.084 7.656 ;
    END
  END o[1]
  PIN rs
    DIRECTION INPUT ;
    USE SIGNAL ;
    PORT
      LAYER M5 ;
        RECT  7.44 15.036 7.464 15.12 ;
    END
  END rs
  PIN VDD
    DIRECTION INOUT ;
    USE POWER ;
    PORT
      LAYER M5 ;
        RECT  10.692 2.151 10.812 12.969 ;
        RECT  7.992 2.151 8.112 12.969 ;
        RECT  5.292 2.151 5.412 12.969 ;
        RECT  2.592 2.151 2.712 12.969 ;
    END
  END VDD
  PIN VSS
    DIRECTION INOUT ;
    USE GROUND ;
    PORT
      LAYER M5 ;
        RECT  10.5 2.137 10.62 12.983 ;
        RECT  7.8 2.137 7.92 12.983 ;
        RECT  5.1 2.137 5.22 12.983 ;
        RECT  2.4 2.137 2.52 12.983 ;
    END
  END VSS
  OBS
    LAYER RVTN ;
     RECT  2.16 2.16 12.96 2.295 ;
     RECT  2.16 2.565 12.96 2.835 ;
     RECT  2.16 3.105 12.96 3.375 ;
     RECT  2.16 3.645 12.96 3.915 ;
     RECT  2.16 4.185 12.96 4.455 ;
     RECT  2.16 4.725 12.96 4.995 ;
     RECT  2.16 5.265 12.96 5.535 ;
     RECT  2.16 5.805 12.96 6.075 ;
     RECT  2.16 6.345 12.96 6.615 ;
     RECT  2.16 6.885 12.96 7.155 ;
     RECT  2.16 7.425 12.96 7.695 ;
     RECT  2.16 7.965 12.96 8.235 ;
     RECT  2.16 8.505 12.96 8.775 ;
     RECT  2.16 9.045 12.96 9.315 ;
     RECT  2.16 9.585 12.96 9.855 ;
     RECT  2.16 10.125 12.96 10.395 ;
     RECT  2.16 10.665 12.96 10.935 ;
     RECT  2.16 11.205 12.96 11.475 ;
     RECT  2.16 11.745 12.96 12.015 ;
     RECT  2.16 12.285 12.96 12.555 ;
     RECT  2.16 12.825 12.96 12.96 ;
    LAYER RVTP ;
     RECT  2.16 2.295 12.96 2.565 ;
     RECT  2.16 2.835 12.96 3.105 ;
     RECT  2.16 3.375 12.96 3.645 ;
     RECT  2.16 3.915 12.96 4.185 ;
     RECT  2.16 4.455 12.96 4.725 ;
     RECT  2.16 4.995 12.96 5.265 ;
     RECT  2.16 5.535 12.96 5.805 ;
     RECT  2.16 6.075 12.96 6.345 ;
     RECT  2.16 6.615 12.96 6.885 ;
     RECT  2.16 7.155 12.96 7.425 ;
     RECT  2.16 7.695 12.96 7.965 ;
     RECT  2.16 8.235 12.96 8.505 ;
     RECT  2.16 8.775 12.96 9.045 ;
     RECT  2.16 9.315 12.96 9.585 ;
     RECT  2.16 9.855 12.96 10.125 ;
     RECT  2.16 10.395 12.96 10.665 ;
     RECT  2.16 10.935 12.96 11.205 ;
     RECT  2.16 11.475 12.96 11.745 ;
     RECT  2.16 12.015 12.96 12.285 ;
     RECT  2.16 12.555 12.96 12.825 ;
    LAYER M1 ;
     RECT  2.16 2.151 12.96 12.969 ;
    LAYER M2 ;
     RECT  0.103 7.326 2.16 7.344 ;
     RECT  2.16 2.151 12.96 12.969 ;
     RECT  12.96 8.28 13.379 8.496 ;
     RECT  13.379 8.478 13.451 8.496 ;
    LAYER M3 ;
     RECT  2.415 2.143 2.505 2.413 ;
     RECT  5.115 2.143 5.205 2.413 ;
     RECT  7.815 2.143 7.905 2.413 ;
     RECT  10.515 2.143 10.605 2.413 ;
     RECT  2.415 2.413 2.697 7.195 ;
     RECT  2.415 7.195 2.898 7.231 ;
     RECT  2.304 7.231 2.898 7.385 ;
     RECT  0.108 7.321 0.126 7.531 ;
     RECT  0.108 7.531 0.342 7.661 ;
     RECT  13.356 7.627 13.374 7.723 ;
     RECT  2.415 7.385 2.898 7.735 ;
     RECT  2.415 7.735 2.934 7.771 ;
     RECT  7.815 2.413 8.097 7.897 ;
     RECT  2.415 7.771 3.042 8.041 ;
     RECT  2.415 8.041 3.186 8.159 ;
     RECT  3.996 8.041 4.014 8.159 ;
     RECT  7.815 7.897 8.55 8.275 ;
     RECT  13.356 7.723 13.446 8.303 ;
     RECT  12.24 8.311 12.258 8.401 ;
     RECT  2.415 8.159 2.934 8.501 ;
     RECT  13.428 8.303 13.446 8.501 ;
     RECT  9.324 8.401 9.342 8.537 ;
     RECT  11.952 8.401 12.258 8.735 ;
     RECT  11.952 8.735 11.97 8.843 ;
     RECT  7.416 8.275 8.55 8.851 ;
     RECT  7.272 8.851 8.55 8.969 ;
     RECT  7.272 8.969 8.442 9.349 ;
     RECT  7.2 9.349 8.442 9.509 ;
     RECT  7.2 9.509 8.097 9.517 ;
     RECT  7.164 9.517 8.097 10.267 ;
     RECT  6.984 10.267 8.097 10.625 ;
     RECT  2.415 8.501 2.697 12.707 ;
     RECT  5.115 2.413 5.397 12.707 ;
     RECT  7.632 10.625 8.097 12.707 ;
     RECT  10.515 2.413 10.797 12.707 ;
     RECT  7.632 12.707 7.905 12.865 ;
     RECT  2.415 12.707 2.505 12.977 ;
     RECT  5.115 12.707 5.205 12.977 ;
     RECT  7.524 12.865 7.905 12.977 ;
     RECT  10.515 12.707 10.605 12.977 ;
     RECT  7.524 12.977 7.542 13.085 ;
    LAYER M4 ;
     RECT  0.06 7.536 0.353 7.656 ;
     RECT  0.353 7.632 2.408 7.656 ;
     RECT  2.408 2.148 2.512 12.972 ;
     RECT  2.512 2.418 2.704 12.702 ;
     RECT  2.704 7.632 2.873 7.656 ;
     RECT  5.108 2.148 5.212 12.972 ;
     RECT  5.212 2.418 5.404 12.702 ;
     RECT  6.973 10.272 7.148 10.296 ;
     RECT  7.189 14.976 7.379 15 ;
     RECT  7.429 13.056 7.553 13.08 ;
     RECT  7.388 8.304 7.808 8.328 ;
     RECT  7.148 9.36 7.808 10.296 ;
     RECT  7.808 2.148 7.912 12.972 ;
     RECT  7.912 2.418 8.104 12.702 ;
     RECT  10.508 2.148 10.612 12.972 ;
     RECT  10.612 2.418 10.804 12.702 ;
     RECT  13.345 7.632 13.417 7.656 ;
     RECT  13.417 7.632 15.084 7.752 ;
    LAYER M5 ;
     RECT  2.4 2.137 2.52 2.151 ;
     RECT  5.1 2.137 5.22 2.151 ;
     RECT  7.8 2.137 7.92 2.151 ;
     RECT  10.5 2.137 10.62 2.151 ;
     RECT  7.8 2.151 8.112 8.293 ;
     RECT  7.44 8.293 8.112 9.349 ;
     RECT  2.4 2.151 2.712 12.969 ;
     RECT  5.1 2.151 5.412 12.969 ;
     RECT  7.2 9.349 8.112 12.969 ;
     RECT  10.5 2.151 10.812 12.969 ;
     RECT  2.4 12.969 2.52 12.983 ;
     RECT  5.1 12.969 5.22 12.983 ;
     RECT  7.2 12.969 7.92 12.983 ;
     RECT  10.5 12.969 10.62 12.983 ;
     RECT  7.2 12.983 7.464 15.011 ;
     RECT  7.344 15.011 7.464 15.056 ;
  END
END dsfd_rly_2_EW

VERSION 5.8 ;
BUSBITCHARS "[]" ;
DIVIDERCHAR "/" ;
UNITS
    DATABASE MICRONS 1000 ;
END UNITS

MACRO dsfd_rly_2_NE
  FOREIGN dsfd_rly_2_NE 0 0 ;
  CLASS BLOCK ;
  SIZE 15.12 BY 15.12 ;
  PIN ck
    DIRECTION INPUT ;
    USE SIGNAL ;
    PORT
      LAYER M5 ;
        RECT  7.056 0 7.08 0.084 ;
    END
  END ck
  PIN i[0]
    DIRECTION INPUT ;
    USE SIGNAL ;
    PORT
      LAYER M5 ;
        RECT  6.96 15.036 6.984 15.12 ;
    END
  END i[0]
  PIN i[1]
    DIRECTION INPUT ;
    USE SIGNAL ;
    PORT
      LAYER M5 ;
        RECT  7.056 15.036 7.08 15.12 ;
    END
  END i[1]
  PIN o[0]
    DIRECTION OUTPUT ;
    USE SIGNAL ;
    PORT
      LAYER M4 ;
        RECT  15.036 7.632 15.12 7.656 ;
    END
  END o[0]
  PIN o[1]
    DIRECTION OUTPUT ;
    USE SIGNAL ;
    PORT
      LAYER M4 ;
        RECT  15.036 7.728 15.12 7.752 ;
    END
  END o[1]
  PIN rs
    DIRECTION INPUT ;
    USE SIGNAL ;
    PORT
      LAYER M5 ;
        RECT  7.152 0 7.176 0.084 ;
    END
  END rs
  PIN VDD
    DIRECTION INOUT ;
    USE POWER ;
    PORT
      LAYER M5 ;
        RECT  10.692 2.151 10.812 12.969 ;
        RECT  7.992 2.151 8.112 12.969 ;
        RECT  5.292 2.151 5.412 12.969 ;
        RECT  2.592 2.151 2.712 12.969 ;
    END
  END VDD
  PIN VSS
    DIRECTION INOUT ;
    USE GROUND ;
    PORT
      LAYER M5 ;
        RECT  10.5 2.137 10.62 12.983 ;
        RECT  7.8 2.137 7.92 12.983 ;
        RECT  5.1 2.137 5.22 12.983 ;
        RECT  2.4 2.137 2.52 12.983 ;
    END
  END VSS
  OBS
    LAYER RVTN ;
     RECT  2.16 2.16 12.96 2.295 ;
     RECT  2.16 2.565 12.96 2.835 ;
     RECT  2.16 3.105 12.96 3.375 ;
     RECT  2.16 3.645 12.96 3.915 ;
     RECT  2.16 4.185 12.96 4.455 ;
     RECT  2.16 4.725 12.96 4.995 ;
     RECT  2.16 5.265 12.96 5.535 ;
     RECT  2.16 5.805 12.96 6.075 ;
     RECT  2.16 6.345 12.96 6.615 ;
     RECT  2.16 6.885 12.96 7.155 ;
     RECT  2.16 7.425 12.96 7.695 ;
     RECT  2.16 7.965 12.96 8.235 ;
     RECT  2.16 8.505 12.96 8.775 ;
     RECT  2.16 9.045 12.96 9.315 ;
     RECT  2.16 9.585 12.96 9.855 ;
     RECT  2.16 10.125 12.96 10.395 ;
     RECT  2.16 10.665 12.96 10.935 ;
     RECT  2.16 11.205 12.96 11.475 ;
     RECT  2.16 11.745 12.96 12.015 ;
     RECT  2.16 12.285 12.96 12.555 ;
     RECT  2.16 12.825 12.96 12.96 ;
    LAYER RVTP ;
     RECT  2.16 2.295 12.96 2.565 ;
     RECT  2.16 2.835 12.96 3.105 ;
     RECT  2.16 3.375 12.96 3.645 ;
     RECT  2.16 3.915 12.96 4.185 ;
     RECT  2.16 4.455 12.96 4.725 ;
     RECT  2.16 4.995 12.96 5.265 ;
     RECT  2.16 5.535 12.96 5.805 ;
     RECT  2.16 6.075 12.96 6.345 ;
     RECT  2.16 6.615 12.96 6.885 ;
     RECT  2.16 7.155 12.96 7.425 ;
     RECT  2.16 7.695 12.96 7.965 ;
     RECT  2.16 8.235 12.96 8.505 ;
     RECT  2.16 8.775 12.96 9.045 ;
     RECT  2.16 9.315 12.96 9.585 ;
     RECT  2.16 9.855 12.96 10.125 ;
     RECT  2.16 10.395 12.96 10.665 ;
     RECT  2.16 10.935 12.96 11.205 ;
     RECT  2.16 11.475 12.96 11.745 ;
     RECT  2.16 12.015 12.96 12.285 ;
     RECT  2.16 12.555 12.96 12.825 ;
    LAYER M1 ;
     RECT  2.16 2.151 12.96 12.969 ;
    LAYER M2 ;
     RECT  2.16 2.151 12.96 12.969 ;
     RECT  12.96 7.596 13.667 7.884 ;
    LAYER M3 ;
     RECT  7.164 1.723 7.182 2.143 ;
     RECT  2.415 2.143 2.505 2.413 ;
     RECT  5.115 2.143 5.205 2.413 ;
     RECT  7.164 2.143 7.905 2.413 ;
     RECT  10.515 2.143 10.605 2.413 ;
     RECT  7.164 2.413 8.097 3.335 ;
     RECT  7.236 3.335 8.097 6.305 ;
     RECT  7.344 6.305 8.097 7.321 ;
     RECT  7.344 7.321 8.37 7.385 ;
     RECT  7.632 7.385 8.37 7.465 ;
     RECT  10.515 2.413 10.797 7.501 ;
     RECT  11.52 7.321 11.538 7.501 ;
     RECT  7.632 7.465 8.406 7.627 ;
     RECT  10.515 7.501 11.826 7.735 ;
     RECT  10.515 7.735 12.15 7.771 ;
     RECT  10.296 7.771 12.15 7.889 ;
     RECT  13.644 7.591 13.662 7.889 ;
     RECT  7.632 7.627 8.838 7.915 ;
     RECT  6.732 7.735 6.75 7.949 ;
     RECT  11.628 7.889 12.15 8.005 ;
     RECT  7.632 7.915 8.91 8.159 ;
     RECT  10.296 7.889 10.797 8.159 ;
     RECT  11.628 8.005 12.366 8.231 ;
     RECT  7.632 8.159 8.802 8.237 ;
     RECT  12.024 8.231 12.366 8.429 ;
     RECT  7.632 8.237 8.19 9.239 ;
     RECT  7.632 9.239 8.097 9.355 ;
     RECT  7.596 9.355 8.097 9.625 ;
     RECT  7.416 9.625 8.097 12.325 ;
     RECT  7.272 12.325 8.097 12.523 ;
     RECT  2.415 2.413 2.697 12.707 ;
     RECT  5.115 2.413 5.397 12.707 ;
     RECT  7.2 12.523 8.097 12.707 ;
     RECT  10.515 8.159 10.797 12.707 ;
     RECT  2.415 12.707 2.505 12.977 ;
     RECT  5.115 12.707 5.205 12.977 ;
     RECT  7.2 12.707 7.905 12.977 ;
     RECT  10.515 12.707 10.605 12.977 ;
     RECT  7.2 12.977 7.29 13.037 ;
     RECT  7.272 13.037 7.29 13.085 ;
    LAYER M4 ;
     RECT  2.408 2.148 2.512 12.972 ;
     RECT  2.512 2.418 2.704 12.702 ;
     RECT  5.108 2.148 5.212 12.972 ;
     RECT  5.212 2.418 5.404 12.702 ;
     RECT  6.721 7.92 7.045 7.944 ;
     RECT  6.949 13.056 7.045 13.08 ;
     RECT  7.109 1.728 7.193 1.752 ;
     RECT  7.045 13.008 7.301 13.08 ;
     RECT  7.045 7.44 7.669 7.944 ;
     RECT  7.669 7.44 7.808 8.232 ;
     RECT  7.808 2.148 7.912 12.972 ;
     RECT  7.912 2.418 8.104 12.702 ;
     RECT  8.104 7.92 8.813 8.232 ;
     RECT  8.813 7.92 8.921 7.944 ;
     RECT  10.508 2.148 10.612 12.972 ;
     RECT  10.612 2.418 10.804 12.702 ;
     RECT  13.633 7.632 15.084 7.752 ;
    LAYER M5 ;
     RECT  7.056 0.016 7.176 2.137 ;
     RECT  2.4 2.137 2.52 2.151 ;
     RECT  5.1 2.137 5.22 2.151 ;
     RECT  7.056 2.137 7.92 2.151 ;
     RECT  10.5 2.137 10.62 2.151 ;
     RECT  7.056 2.151 8.112 7.475 ;
     RECT  7.68 7.475 8.112 8.243 ;
     RECT  2.4 2.151 2.712 12.969 ;
     RECT  5.1 2.151 5.412 12.969 ;
     RECT  7.8 8.243 8.112 12.969 ;
     RECT  10.5 2.151 10.812 12.969 ;
     RECT  2.4 12.969 2.52 12.983 ;
     RECT  5.1 12.969 5.22 12.983 ;
     RECT  7.8 12.969 7.92 12.983 ;
     RECT  10.5 12.969 10.62 12.983 ;
     RECT  7.056 12.997 7.08 13.045 ;
     RECT  6.96 13.045 7.08 15.056 ;
  END
END dsfd_rly_2_NE

VERSION 5.8 ;
BUSBITCHARS "[]" ;
DIVIDERCHAR "/" ;
UNITS
    DATABASE MICRONS 1000 ;
END UNITS

MACRO dsfd_rly_2_NS
  FOREIGN dsfd_rly_2_NS 0 0 ;
  CLASS BLOCK ;
  SIZE 15.12 BY 15.12 ;
  PIN ck
    DIRECTION INPUT ;
    USE SIGNAL ;
    PORT
      LAYER M4 ;
        RECT  15.036 7.632 15.12 7.656 ;
    END
  END ck
  PIN i[0]
    DIRECTION INPUT ;
    USE SIGNAL ;
    PORT
      LAYER M5 ;
        RECT  6.96 15.036 6.984 15.12 ;
    END
  END i[0]
  PIN i[1]
    DIRECTION INPUT ;
    USE SIGNAL ;
    PORT
      LAYER M5 ;
        RECT  7.056 15.036 7.08 15.12 ;
    END
  END i[1]
  PIN o[0]
    DIRECTION OUTPUT ;
    USE SIGNAL ;
    PORT
      LAYER M5 ;
        RECT  7.824 0 7.848 0.084 ;
    END
  END o[0]
  PIN o[1]
    DIRECTION OUTPUT ;
    USE SIGNAL ;
    PORT
      LAYER M5 ;
        RECT  7.92 0 7.944 0.084 ;
    END
  END o[1]
  PIN rs
    DIRECTION INPUT ;
    USE SIGNAL ;
    PORT
      LAYER M4 ;
        RECT  15.036 7.728 15.12 7.752 ;
    END
  END rs
  PIN VDD
    DIRECTION INOUT ;
    USE POWER ;
    PORT
      LAYER M5 ;
        RECT  10.692 2.151 10.812 12.969 ;
        RECT  7.992 2.151 8.112 12.969 ;
        RECT  5.292 2.151 5.412 12.969 ;
        RECT  2.592 2.151 2.712 12.969 ;
    END
  END VDD
  PIN VSS
    DIRECTION INOUT ;
    USE GROUND ;
    PORT
      LAYER M5 ;
        RECT  10.5 2.137 10.62 12.983 ;
        RECT  7.8 2.137 7.92 12.983 ;
        RECT  5.1 2.137 5.22 12.983 ;
        RECT  2.4 2.137 2.52 12.983 ;
    END
  END VSS
  OBS
    LAYER RVTN ;
     RECT  2.16 2.16 12.96 2.295 ;
     RECT  2.16 2.565 12.96 2.835 ;
     RECT  2.16 3.105 12.96 3.375 ;
     RECT  2.16 3.645 12.96 3.915 ;
     RECT  2.16 4.185 12.96 4.455 ;
     RECT  2.16 4.725 12.96 4.995 ;
     RECT  2.16 5.265 12.96 5.535 ;
     RECT  2.16 5.805 12.96 6.075 ;
     RECT  2.16 6.345 12.96 6.615 ;
     RECT  2.16 6.885 12.96 7.155 ;
     RECT  2.16 7.425 12.96 7.695 ;
     RECT  2.16 7.965 12.96 8.235 ;
     RECT  2.16 8.505 12.96 8.775 ;
     RECT  2.16 9.045 12.96 9.315 ;
     RECT  2.16 9.585 12.96 9.855 ;
     RECT  2.16 10.125 12.96 10.395 ;
     RECT  2.16 10.665 12.96 10.935 ;
     RECT  2.16 11.205 12.96 11.475 ;
     RECT  2.16 11.745 12.96 12.015 ;
     RECT  2.16 12.285 12.96 12.555 ;
     RECT  2.16 12.825 12.96 12.96 ;
    LAYER RVTP ;
     RECT  2.16 2.295 12.96 2.565 ;
     RECT  2.16 2.835 12.96 3.105 ;
     RECT  2.16 3.375 12.96 3.645 ;
     RECT  2.16 3.915 12.96 4.185 ;
     RECT  2.16 4.455 12.96 4.725 ;
     RECT  2.16 4.995 12.96 5.265 ;
     RECT  2.16 5.535 12.96 5.805 ;
     RECT  2.16 6.075 12.96 6.345 ;
     RECT  2.16 6.615 12.96 6.885 ;
     RECT  2.16 7.155 12.96 7.425 ;
     RECT  2.16 7.695 12.96 7.965 ;
     RECT  2.16 8.235 12.96 8.505 ;
     RECT  2.16 8.775 12.96 9.045 ;
     RECT  2.16 9.315 12.96 9.585 ;
     RECT  2.16 9.855 12.96 10.125 ;
     RECT  2.16 10.395 12.96 10.665 ;
     RECT  2.16 10.935 12.96 11.205 ;
     RECT  2.16 11.475 12.96 11.745 ;
     RECT  2.16 12.015 12.96 12.285 ;
     RECT  2.16 12.555 12.96 12.825 ;
    LAYER M1 ;
     RECT  2.16 2.151 12.96 12.969 ;
    LAYER M2 ;
     RECT  2.16 2.151 12.96 12.969 ;
     RECT  12.96 7.938 13.667 7.956 ;
    LAYER M3 ;
     RECT  7.956 1.723 7.974 1.771 ;
     RECT  7.776 1.771 7.974 2.263 ;
     RECT  7.776 2.263 8.37 2.335 ;
     RECT  2.415 2.143 2.505 2.413 ;
     RECT  5.115 2.143 5.205 2.413 ;
     RECT  10.515 2.143 10.605 2.413 ;
     RECT  7.632 2.335 8.37 2.605 ;
     RECT  7.38 2.605 8.982 3.029 ;
     RECT  7.815 3.029 8.802 6.151 ;
     RECT  7.815 6.151 8.91 7.231 ;
     RECT  7.815 7.231 9.594 7.349 ;
     RECT  7.815 7.349 9.45 7.357 ;
     RECT  7.668 7.357 9.45 7.735 ;
     RECT  7.596 7.735 9.45 7.799 ;
     RECT  9.432 7.799 9.45 7.889 ;
     RECT  15.012 7.627 15.03 7.949 ;
     RECT  7.596 7.799 8.55 7.961 ;
     RECT  13.644 7.723 13.662 7.961 ;
     RECT  7.596 7.961 8.097 8.167 ;
     RECT  7.056 8.167 8.097 8.237 ;
     RECT  7.236 8.237 8.097 9.355 ;
     RECT  7.092 9.355 8.097 12.325 ;
     RECT  2.415 2.413 2.697 12.707 ;
     RECT  5.115 2.413 5.397 12.707 ;
     RECT  7.056 12.325 8.097 12.707 ;
     RECT  10.515 2.413 10.797 12.707 ;
     RECT  2.415 12.707 2.505 12.977 ;
     RECT  5.115 12.707 5.205 12.977 ;
     RECT  7.056 12.707 7.905 12.977 ;
     RECT  10.515 12.707 10.605 12.977 ;
     RECT  7.056 12.977 7.146 13.037 ;
     RECT  7.056 13.037 7.074 13.085 ;
    LAYER M4 ;
     RECT  2.408 2.148 2.512 12.972 ;
     RECT  2.512 2.418 2.704 12.702 ;
     RECT  5.108 2.148 5.212 12.972 ;
     RECT  5.212 2.418 5.404 12.702 ;
     RECT  6.949 13.056 7.045 13.08 ;
     RECT  7.045 13.008 7.085 13.08 ;
     RECT  7.085 13.008 7.157 13.032 ;
     RECT  7.765 1.776 7.808 1.8 ;
     RECT  7.045 8.208 7.808 8.232 ;
     RECT  7.808 1.776 7.901 12.972 ;
     RECT  7.901 1.728 7.912 12.972 ;
     RECT  7.912 1.728 7.985 12.702 ;
     RECT  7.985 2.418 8.104 12.702 ;
     RECT  8.104 7.824 8.291 8.232 ;
     RECT  8.291 7.824 8.317 7.944 ;
     RECT  8.317 7.92 10.508 7.944 ;
     RECT  10.508 2.148 10.612 12.972 ;
     RECT  10.612 2.418 10.804 12.702 ;
     RECT  10.804 7.92 13.633 7.944 ;
     RECT  13.633 7.728 15.001 7.944 ;
     RECT  15.001 7.632 15.041 7.944 ;
     RECT  15.041 7.632 15.084 7.752 ;
    LAYER M5 ;
     RECT  7.824 0.016 7.944 2.137 ;
     RECT  2.4 2.137 2.52 2.151 ;
     RECT  5.1 2.137 5.22 2.151 ;
     RECT  7.8 2.137 7.944 2.151 ;
     RECT  10.5 2.137 10.62 2.151 ;
     RECT  7.8 2.151 8.112 7.813 ;
     RECT  7.8 7.813 8.28 8.243 ;
     RECT  2.4 2.151 2.712 12.969 ;
     RECT  5.1 2.151 5.412 12.969 ;
     RECT  7.8 8.243 8.112 12.969 ;
     RECT  10.5 2.151 10.812 12.969 ;
     RECT  2.4 12.969 2.52 12.983 ;
     RECT  5.1 12.969 5.22 12.983 ;
     RECT  7.8 12.969 7.92 12.983 ;
     RECT  10.5 12.969 10.62 12.983 ;
     RECT  7.056 12.997 7.08 13.045 ;
     RECT  6.96 13.045 7.08 15.056 ;
  END
END dsfd_rly_2_NS

VERSION 5.8 ;
BUSBITCHARS "[]" ;
DIVIDERCHAR "/" ;
UNITS
    DATABASE MICRONS 1000 ;
END UNITS

MACRO dsfd_rly_2_NW
  FOREIGN dsfd_rly_2_NW 0 0 ;
  CLASS BLOCK ;
  SIZE 15.12 BY 15.12 ;
  PIN ck
    DIRECTION INPUT ;
    USE SIGNAL ;
    PORT
      LAYER M5 ;
        RECT  7.056 0 7.08 0.084 ;
    END
  END ck
  PIN i[0]
    DIRECTION INPUT ;
    USE SIGNAL ;
    PORT
      LAYER M5 ;
        RECT  6.96 15.036 6.984 15.12 ;
    END
  END i[0]
  PIN i[1]
    DIRECTION INPUT ;
    USE SIGNAL ;
    PORT
      LAYER M5 ;
        RECT  7.056 15.036 7.08 15.12 ;
    END
  END i[1]
  PIN o[0]
    DIRECTION OUTPUT ;
    USE SIGNAL ;
    PORT
      LAYER M4 ;
        RECT  0 7.536 0.084 7.56 ;
    END
  END o[0]
  PIN o[1]
    DIRECTION OUTPUT ;
    USE SIGNAL ;
    PORT
      LAYER M4 ;
        RECT  0 7.632 0.084 7.656 ;
    END
  END o[1]
  PIN rs
    DIRECTION INPUT ;
    USE SIGNAL ;
    PORT
      LAYER M5 ;
        RECT  7.152 0 7.176 0.084 ;
    END
  END rs
  PIN VDD
    DIRECTION INOUT ;
    USE POWER ;
    PORT
      LAYER M5 ;
        RECT  10.692 2.151 10.812 12.969 ;
        RECT  7.992 2.151 8.112 12.969 ;
        RECT  5.292 2.151 5.412 12.969 ;
        RECT  2.592 2.151 2.712 12.969 ;
    END
  END VDD
  PIN VSS
    DIRECTION INOUT ;
    USE GROUND ;
    PORT
      LAYER M5 ;
        RECT  10.5 2.137 10.62 12.983 ;
        RECT  7.8 2.137 7.92 12.983 ;
        RECT  5.1 2.137 5.22 12.983 ;
        RECT  2.4 2.137 2.52 12.983 ;
    END
  END VSS
  OBS
    LAYER RVTN ;
     RECT  2.16 2.16 12.96 2.295 ;
     RECT  2.16 2.565 12.96 2.835 ;
     RECT  2.16 3.105 12.96 3.375 ;
     RECT  2.16 3.645 12.96 3.915 ;
     RECT  2.16 4.185 12.96 4.455 ;
     RECT  2.16 4.725 12.96 4.995 ;
     RECT  2.16 5.265 12.96 5.535 ;
     RECT  2.16 5.805 12.96 6.075 ;
     RECT  2.16 6.345 12.96 6.615 ;
     RECT  2.16 6.885 12.96 7.155 ;
     RECT  2.16 7.425 12.96 7.695 ;
     RECT  2.16 7.965 12.96 8.235 ;
     RECT  2.16 8.505 12.96 8.775 ;
     RECT  2.16 9.045 12.96 9.315 ;
     RECT  2.16 9.585 12.96 9.855 ;
     RECT  2.16 10.125 12.96 10.395 ;
     RECT  2.16 10.665 12.96 10.935 ;
     RECT  2.16 11.205 12.96 11.475 ;
     RECT  2.16 11.745 12.96 12.015 ;
     RECT  2.16 12.285 12.96 12.555 ;
     RECT  2.16 12.825 12.96 12.96 ;
    LAYER RVTP ;
     RECT  2.16 2.295 12.96 2.565 ;
     RECT  2.16 2.835 12.96 3.105 ;
     RECT  2.16 3.375 12.96 3.645 ;
     RECT  2.16 3.915 12.96 4.185 ;
     RECT  2.16 4.455 12.96 4.725 ;
     RECT  2.16 4.995 12.96 5.265 ;
     RECT  2.16 5.535 12.96 5.805 ;
     RECT  2.16 6.075 12.96 6.345 ;
     RECT  2.16 6.615 12.96 6.885 ;
     RECT  2.16 7.155 12.96 7.425 ;
     RECT  2.16 7.695 12.96 7.965 ;
     RECT  2.16 8.235 12.96 8.505 ;
     RECT  2.16 8.775 12.96 9.045 ;
     RECT  2.16 9.315 12.96 9.585 ;
     RECT  2.16 9.855 12.96 10.125 ;
     RECT  2.16 10.395 12.96 10.665 ;
     RECT  2.16 10.935 12.96 11.205 ;
     RECT  2.16 11.475 12.96 11.745 ;
     RECT  2.16 12.015 12.96 12.285 ;
     RECT  2.16 12.555 12.96 12.825 ;
    LAYER M1 ;
     RECT  2.16 2.151 12.96 12.969 ;
    LAYER M2 ;
     RECT  0.103 7.326 2.16 7.344 ;
     RECT  2.16 2.151 12.96 12.969 ;
    LAYER M3 ;
     RECT  2.415 2.143 2.505 2.413 ;
     RECT  5.115 2.143 5.205 2.413 ;
     RECT  7.815 2.143 7.905 2.413 ;
     RECT  10.515 2.143 10.605 2.413 ;
     RECT  6.984 2.251 7.002 3.335 ;
     RECT  7.815 2.413 8.097 3.451 ;
     RECT  7.128 3.451 8.097 6.241 ;
     RECT  5.115 2.413 5.397 6.811 ;
     RECT  6.912 6.241 8.097 7.051 ;
     RECT  2.415 2.413 2.697 7.231 ;
     RECT  5.115 6.811 5.958 7.321 ;
     RECT  5.115 7.321 6.102 7.357 ;
     RECT  6.84 7.051 8.097 7.357 ;
     RECT  2.304 7.231 2.697 7.591 ;
     RECT  3.42 7.195 3.438 7.591 ;
     RECT  0.108 7.321 0.126 7.661 ;
     RECT  2.304 7.591 3.438 7.771 ;
     RECT  2.304 7.771 4.158 7.889 ;
     RECT  5.115 7.357 8.097 7.961 ;
     RECT  2.304 7.889 3.69 8.159 ;
     RECT  2.304 8.159 2.898 8.501 ;
     RECT  2.304 8.501 2.697 8.537 ;
     RECT  5.115 7.961 6.102 8.806 ;
     RECT  7.02 7.961 8.097 8.969 ;
     RECT  7.056 8.969 8.097 9.041 ;
     RECT  5.115 8.806 6.138 9.239 ;
     RECT  6.12 9.239 6.138 11.939 ;
     RECT  7.056 9.041 7.074 11.947 ;
     RECT  6.84 11.947 7.074 12.209 ;
     RECT  6.84 12.209 6.894 12.557 ;
     RECT  2.415 8.537 2.697 12.707 ;
     RECT  5.115 9.239 5.397 12.707 ;
     RECT  7.815 9.041 8.097 12.707 ;
     RECT  10.515 2.413 10.797 12.707 ;
     RECT  2.415 12.707 2.505 12.977 ;
     RECT  5.115 12.707 5.205 12.977 ;
     RECT  7.815 12.707 7.905 12.977 ;
     RECT  10.515 12.707 10.605 12.977 ;
     RECT  6.84 12.557 6.858 14.285 ;
    LAYER M4 ;
     RECT  0.06 7.536 0.137 7.656 ;
     RECT  0.137 7.536 2.408 7.56 ;
     RECT  2.408 2.148 2.512 12.972 ;
     RECT  2.512 2.418 2.704 12.702 ;
     RECT  5.108 2.148 5.212 12.972 ;
     RECT  5.212 2.418 5.404 12.702 ;
     RECT  5.404 7.968 5.843 8.664 ;
     RECT  5.404 6.816 7.037 6.84 ;
     RECT  6.829 14.256 7.091 14.28 ;
     RECT  7.037 6.816 7.333 7.464 ;
     RECT  6.973 2.256 7.808 2.28 ;
     RECT  7.333 6.576 7.808 7.464 ;
     RECT  5.843 8.64 7.808 8.664 ;
     RECT  6.865 12.528 7.808 12.552 ;
     RECT  7.808 2.148 7.912 12.972 ;
     RECT  7.912 2.418 8.104 12.702 ;
     RECT  10.508 2.148 10.612 12.972 ;
     RECT  10.612 2.418 10.804 12.702 ;
    LAYER M5 ;
     RECT  7.056 0.016 7.176 2.137 ;
     RECT  2.4 2.137 2.52 2.151 ;
     RECT  5.1 2.137 5.22 2.151 ;
     RECT  7.056 2.137 7.92 2.151 ;
     RECT  10.5 2.137 10.62 2.151 ;
     RECT  7.056 2.151 8.112 7.475 ;
     RECT  5.1 2.151 5.412 7.957 ;
     RECT  5.1 7.957 5.832 8.675 ;
     RECT  7.8 7.475 8.112 12.517 ;
     RECT  2.4 2.151 2.712 12.969 ;
     RECT  5.1 8.675 5.412 12.969 ;
     RECT  6.96 12.517 8.112 12.969 ;
     RECT  10.5 2.151 10.812 12.969 ;
     RECT  2.4 12.969 2.52 12.983 ;
     RECT  5.1 12.969 5.22 12.983 ;
     RECT  6.96 12.969 7.92 12.983 ;
     RECT  10.5 12.969 10.62 12.983 ;
     RECT  6.96 12.983 6.984 14.245 ;
     RECT  6.96 14.245 7.08 15.056 ;
  END
END dsfd_rly_2_NW

VERSION 5.8 ;
BUSBITCHARS "[]" ;
DIVIDERCHAR "/" ;
UNITS
    DATABASE MICRONS 1000 ;
END UNITS

MACRO dsfd_rly_2_SN
  FOREIGN dsfd_rly_2_SN 0 0 ;
  CLASS BLOCK ;
  SIZE 15.12 BY 15.12 ;
  PIN ck
    DIRECTION INPUT ;
    USE SIGNAL ;
    PORT
      LAYER M4 ;
        RECT  15.036 7.632 15.12 7.656 ;
    END
  END ck
  PIN i[0]
    DIRECTION INPUT ;
    USE SIGNAL ;
    PORT
      LAYER M5 ;
        RECT  7.056 0 7.08 0.084 ;
    END
  END i[0]
  PIN i[1]
    DIRECTION INPUT ;
    USE SIGNAL ;
    PORT
      LAYER M5 ;
        RECT  7.152 0 7.176 0.084 ;
    END
  END i[1]
  PIN o[0]
    DIRECTION OUTPUT ;
    USE SIGNAL ;
    PORT
      LAYER M5 ;
        RECT  7.728 15.036 7.752 15.12 ;
    END
  END o[0]
  PIN o[1]
    DIRECTION OUTPUT ;
    USE SIGNAL ;
    PORT
      LAYER M5 ;
        RECT  7.824 15.036 7.848 15.12 ;
    END
  END o[1]
  PIN rs
    DIRECTION INPUT ;
    USE SIGNAL ;
    PORT
      LAYER M4 ;
        RECT  15.036 7.728 15.12 7.752 ;
    END
  END rs
  PIN VDD
    DIRECTION INOUT ;
    USE POWER ;
    PORT
      LAYER M5 ;
        RECT  10.692 2.151 10.812 12.969 ;
        RECT  7.992 2.151 8.112 12.969 ;
        RECT  5.292 2.151 5.412 12.969 ;
        RECT  2.592 2.151 2.712 12.969 ;
    END
  END VDD
  PIN VSS
    DIRECTION INOUT ;
    USE GROUND ;
    PORT
      LAYER M5 ;
        RECT  10.5 2.137 10.62 12.983 ;
        RECT  7.8 2.137 7.92 12.983 ;
        RECT  5.1 2.137 5.22 12.983 ;
        RECT  2.4 2.137 2.52 12.983 ;
    END
  END VSS
  OBS
    LAYER RVTN ;
     RECT  2.16 2.16 12.96 2.295 ;
     RECT  2.16 2.565 12.96 2.835 ;
     RECT  2.16 3.105 12.96 3.375 ;
     RECT  2.16 3.645 12.96 3.915 ;
     RECT  2.16 4.185 12.96 4.455 ;
     RECT  2.16 4.725 12.96 4.995 ;
     RECT  2.16 5.265 12.96 5.535 ;
     RECT  2.16 5.805 12.96 6.075 ;
     RECT  2.16 6.345 12.96 6.615 ;
     RECT  2.16 6.885 12.96 7.155 ;
     RECT  2.16 7.425 12.96 7.695 ;
     RECT  2.16 7.965 12.96 8.235 ;
     RECT  2.16 8.505 12.96 8.775 ;
     RECT  2.16 9.045 12.96 9.315 ;
     RECT  2.16 9.585 12.96 9.855 ;
     RECT  2.16 10.125 12.96 10.395 ;
     RECT  2.16 10.665 12.96 10.935 ;
     RECT  2.16 11.205 12.96 11.475 ;
     RECT  2.16 11.745 12.96 12.015 ;
     RECT  2.16 12.285 12.96 12.555 ;
     RECT  2.16 12.825 12.96 12.96 ;
    LAYER RVTP ;
     RECT  2.16 2.295 12.96 2.565 ;
     RECT  2.16 2.835 12.96 3.105 ;
     RECT  2.16 3.375 12.96 3.645 ;
     RECT  2.16 3.915 12.96 4.185 ;
     RECT  2.16 4.455 12.96 4.725 ;
     RECT  2.16 4.995 12.96 5.265 ;
     RECT  2.16 5.535 12.96 5.805 ;
     RECT  2.16 6.075 12.96 6.345 ;
     RECT  2.16 6.615 12.96 6.885 ;
     RECT  2.16 7.155 12.96 7.425 ;
     RECT  2.16 7.695 12.96 7.965 ;
     RECT  2.16 8.235 12.96 8.505 ;
     RECT  2.16 8.775 12.96 9.045 ;
     RECT  2.16 9.315 12.96 9.585 ;
     RECT  2.16 9.855 12.96 10.125 ;
     RECT  2.16 10.395 12.96 10.665 ;
     RECT  2.16 10.935 12.96 11.205 ;
     RECT  2.16 11.475 12.96 11.745 ;
     RECT  2.16 12.015 12.96 12.285 ;
     RECT  2.16 12.555 12.96 12.825 ;
    LAYER M1 ;
     RECT  2.16 2.151 12.96 12.969 ;
    LAYER M2 ;
     RECT  2.16 2.151 12.96 12.969 ;
     RECT  12.96 7.938 13.667 7.956 ;
    LAYER M3 ;
     RECT  7.2 1.723 7.218 1.771 ;
     RECT  7.2 1.771 7.29 2.143 ;
     RECT  2.415 2.143 2.505 2.413 ;
     RECT  5.115 2.143 5.205 2.413 ;
     RECT  7.2 2.143 7.905 2.413 ;
     RECT  10.515 2.143 10.605 2.413 ;
     RECT  7.2 2.413 8.097 3.335 ;
     RECT  7.272 3.335 8.097 3.371 ;
     RECT  7.416 3.371 8.097 6.241 ;
     RECT  7.416 6.241 8.478 6.305 ;
     RECT  7.74 6.305 8.478 7.195 ;
     RECT  7.74 7.195 8.55 7.357 ;
     RECT  7.74 7.357 9.594 7.655 ;
     RECT  7.74 7.655 8.802 7.735 ;
     RECT  9.54 7.655 9.594 7.889 ;
     RECT  12.204 7.771 12.366 7.889 ;
     RECT  12.204 7.889 12.222 7.925 ;
     RECT  15.012 7.627 15.03 7.949 ;
     RECT  13.644 7.723 13.662 7.961 ;
     RECT  7.596 7.735 8.802 8.159 ;
     RECT  7.056 8.167 7.074 8.237 ;
     RECT  7.815 8.159 8.802 9.211 ;
     RECT  9.576 7.889 9.594 9.211 ;
     RECT  7.815 9.211 9.594 9.239 ;
     RECT  8.856 9.239 9.594 9.419 ;
     RECT  7.815 9.239 8.097 11.641 ;
     RECT  7.596 11.641 8.097 11.785 ;
     RECT  7.416 11.785 8.097 11.821 ;
     RECT  8.856 9.419 9.414 11.849 ;
     RECT  7.38 11.821 8.097 11.939 ;
     RECT  8.856 11.849 8.874 12.281 ;
     RECT  7.416 11.939 8.097 12.361 ;
     RECT  7.416 12.361 8.37 12.479 ;
     RECT  7.488 12.479 8.37 12.515 ;
     RECT  7.596 12.515 8.37 12.551 ;
     RECT  2.415 2.413 2.697 12.707 ;
     RECT  5.115 2.413 5.397 12.707 ;
     RECT  7.596 12.551 8.097 12.707 ;
     RECT  10.515 2.413 10.797 12.707 ;
     RECT  7.596 12.707 7.905 12.785 ;
     RECT  2.415 12.707 2.505 12.977 ;
     RECT  5.115 12.707 5.205 12.977 ;
     RECT  7.74 12.785 7.905 12.977 ;
     RECT  10.515 12.707 10.605 12.977 ;
     RECT  7.74 12.977 7.794 13.661 ;
     RECT  7.74 13.661 7.758 13.757 ;
    LAYER M4 ;
     RECT  2.408 2.148 2.512 12.972 ;
     RECT  2.512 2.418 2.704 12.702 ;
     RECT  5.108 2.148 5.212 12.972 ;
     RECT  5.212 2.418 5.404 12.702 ;
     RECT  7.045 1.728 7.141 1.752 ;
     RECT  7.141 1.728 7.229 1.8 ;
     RECT  7.229 1.776 7.301 1.8 ;
     RECT  7.717 13.632 7.729 13.656 ;
     RECT  7.045 8.208 7.808 8.232 ;
     RECT  7.729 13.632 7.808 13.752 ;
     RECT  7.808 2.148 7.859 13.752 ;
     RECT  7.859 2.148 7.912 12.972 ;
     RECT  7.912 2.418 8.104 12.702 ;
     RECT  8.104 7.824 8.291 8.232 ;
     RECT  8.291 7.824 8.317 7.944 ;
     RECT  8.317 7.92 10.508 7.944 ;
     RECT  10.508 2.148 10.612 12.972 ;
     RECT  10.612 2.418 10.804 12.702 ;
     RECT  10.804 7.92 13.633 7.944 ;
     RECT  13.633 7.728 15.001 7.944 ;
     RECT  15.001 7.632 15.041 7.944 ;
     RECT  15.041 7.632 15.084 7.752 ;
    LAYER M5 ;
     RECT  7.056 0.016 7.176 1.763 ;
     RECT  7.152 1.763 7.176 1.811 ;
     RECT  2.4 2.137 2.52 2.151 ;
     RECT  5.1 2.137 5.22 2.151 ;
     RECT  7.8 2.137 7.92 2.151 ;
     RECT  10.5 2.137 10.62 2.151 ;
     RECT  7.8 2.151 8.112 7.813 ;
     RECT  7.8 7.813 8.28 8.243 ;
     RECT  2.4 2.151 2.712 12.969 ;
     RECT  5.1 2.151 5.412 12.969 ;
     RECT  7.8 8.243 8.112 12.969 ;
     RECT  10.5 2.151 10.812 12.969 ;
     RECT  2.4 12.969 2.52 12.983 ;
     RECT  5.1 12.969 5.22 12.983 ;
     RECT  7.8 12.969 7.92 12.983 ;
     RECT  10.5 12.969 10.62 12.983 ;
     RECT  7.8 12.983 7.848 13.621 ;
     RECT  7.728 13.621 7.848 15.056 ;
  END
END dsfd_rly_2_SN

VERSION 5.8 ;
BUSBITCHARS "[]" ;
DIVIDERCHAR "/" ;
UNITS
    DATABASE MICRONS 1000 ;
END UNITS

MACRO dsfd_rly_2_WE
  FOREIGN dsfd_rly_2_WE 0 0 ;
  CLASS BLOCK ;
  SIZE 15.12 BY 15.12 ;
  PIN ck
    DIRECTION INPUT ;
    USE SIGNAL ;
    PORT
      LAYER M5 ;
        RECT  7.344 15.036 7.368 15.12 ;
    END
  END ck
  PIN i[0]
    DIRECTION INPUT ;
    USE SIGNAL ;
    PORT
      LAYER M4 ;
        RECT  0 7.536 0.084 7.56 ;
    END
  END i[0]
  PIN i[1]
    DIRECTION INPUT ;
    USE SIGNAL ;
    PORT
      LAYER M4 ;
        RECT  0 7.632 0.084 7.656 ;
    END
  END i[1]
  PIN o[0]
    DIRECTION OUTPUT ;
    USE SIGNAL ;
    PORT
      LAYER M4 ;
        RECT  15.036 7.632 15.12 7.656 ;
    END
  END o[0]
  PIN o[1]
    DIRECTION OUTPUT ;
    USE SIGNAL ;
    PORT
      LAYER M4 ;
        RECT  15.036 7.728 15.12 7.752 ;
    END
  END o[1]
  PIN rs
    DIRECTION INPUT ;
    USE SIGNAL ;
    PORT
      LAYER M5 ;
        RECT  7.44 15.036 7.464 15.12 ;
    END
  END rs
  PIN VDD
    DIRECTION INOUT ;
    USE POWER ;
    PORT
      LAYER M5 ;
        RECT  10.692 2.151 10.812 12.969 ;
        RECT  7.992 2.151 8.112 12.969 ;
        RECT  5.292 2.151 5.412 12.969 ;
        RECT  2.592 2.151 2.712 12.969 ;
    END
  END VDD
  PIN VSS
    DIRECTION INOUT ;
    USE GROUND ;
    PORT
      LAYER M5 ;
        RECT  10.5 2.137 10.62 12.983 ;
        RECT  7.8 2.137 7.92 12.983 ;
        RECT  5.1 2.137 5.22 12.983 ;
        RECT  2.4 2.137 2.52 12.983 ;
    END
  END VSS
  OBS
    LAYER RVTN ;
     RECT  2.16 2.16 12.96 2.295 ;
     RECT  2.16 2.565 12.96 2.835 ;
     RECT  2.16 3.105 12.96 3.375 ;
     RECT  2.16 3.645 12.96 3.915 ;
     RECT  2.16 4.185 12.96 4.455 ;
     RECT  2.16 4.725 12.96 4.995 ;
     RECT  2.16 5.265 12.96 5.535 ;
     RECT  2.16 5.805 12.96 6.075 ;
     RECT  2.16 6.345 12.96 6.615 ;
     RECT  2.16 6.885 12.96 7.155 ;
     RECT  2.16 7.425 12.96 7.695 ;
     RECT  2.16 7.965 12.96 8.235 ;
     RECT  2.16 8.505 12.96 8.775 ;
     RECT  2.16 9.045 12.96 9.315 ;
     RECT  2.16 9.585 12.96 9.855 ;
     RECT  2.16 10.125 12.96 10.395 ;
     RECT  2.16 10.665 12.96 10.935 ;
     RECT  2.16 11.205 12.96 11.475 ;
     RECT  2.16 11.745 12.96 12.015 ;
     RECT  2.16 12.285 12.96 12.555 ;
     RECT  2.16 12.825 12.96 12.96 ;
    LAYER RVTP ;
     RECT  2.16 2.295 12.96 2.565 ;
     RECT  2.16 2.835 12.96 3.105 ;
     RECT  2.16 3.375 12.96 3.645 ;
     RECT  2.16 3.915 12.96 4.185 ;
     RECT  2.16 4.455 12.96 4.725 ;
     RECT  2.16 4.995 12.96 5.265 ;
     RECT  2.16 5.535 12.96 5.805 ;
     RECT  2.16 6.075 12.96 6.345 ;
     RECT  2.16 6.615 12.96 6.885 ;
     RECT  2.16 7.155 12.96 7.425 ;
     RECT  2.16 7.695 12.96 7.965 ;
     RECT  2.16 8.235 12.96 8.505 ;
     RECT  2.16 8.775 12.96 9.045 ;
     RECT  2.16 9.315 12.96 9.585 ;
     RECT  2.16 9.855 12.96 10.125 ;
     RECT  2.16 10.395 12.96 10.665 ;
     RECT  2.16 10.935 12.96 11.205 ;
     RECT  2.16 11.475 12.96 11.745 ;
     RECT  2.16 12.015 12.96 12.285 ;
     RECT  2.16 12.555 12.96 12.825 ;
    LAYER M1 ;
     RECT  2.16 2.151 12.96 12.969 ;
    LAYER M2 ;
     RECT  2.16 2.151 12.96 12.969 ;
     RECT  12.96 7.596 13.667 7.884 ;
     RECT  13.667 7.866 14.243 7.884 ;
    LAYER M3 ;
     RECT  2.415 2.143 2.505 2.413 ;
     RECT  5.115 2.143 5.205 2.413 ;
     RECT  7.815 2.143 7.905 2.413 ;
     RECT  10.515 2.143 10.605 2.413 ;
     RECT  10.515 2.413 10.797 7.501 ;
     RECT  2.415 2.413 2.697 7.531 ;
     RECT  13.644 7.591 13.662 7.661 ;
     RECT  10.515 7.501 12.114 7.735 ;
     RECT  10.515 7.735 12.258 7.889 ;
     RECT  14.22 7.723 14.238 7.889 ;
     RECT  6.876 7.915 6.894 7.933 ;
     RECT  7.815 2.413 8.097 7.933 ;
     RECT  6.876 7.933 8.097 7.961 ;
     RECT  2.304 7.531 2.697 8.041 ;
     RECT  5.115 2.413 5.397 8.041 ;
     RECT  2.304 8.041 2.79 8.159 ;
     RECT  10.515 7.889 11.394 8.159 ;
     RECT  2.304 8.159 2.697 8.195 ;
     RECT  5.04 8.041 5.397 8.311 ;
     RECT  7.164 7.961 8.097 8.311 ;
     RECT  4.392 8.311 5.397 8.465 ;
     RECT  7.164 8.311 8.694 8.699 ;
     RECT  12.6 7.933 12.618 8.699 ;
     RECT  7.164 8.699 8.514 8.843 ;
     RECT  7.2 8.843 8.514 8.969 ;
     RECT  7.2 8.969 8.154 9.389 ;
     RECT  7.272 9.389 8.154 10.049 ;
     RECT  7.272 10.049 8.097 10.229 ;
     RECT  7.815 10.229 8.097 10.975 ;
     RECT  2.415 8.195 2.697 12.707 ;
     RECT  5.115 8.465 5.397 12.707 ;
     RECT  7.704 10.975 8.097 12.707 ;
     RECT  10.515 8.159 10.797 12.707 ;
     RECT  7.704 12.707 7.905 12.865 ;
     RECT  2.415 12.707 2.505 12.977 ;
     RECT  5.115 12.707 5.205 12.977 ;
     RECT  7.596 12.865 7.905 12.977 ;
     RECT  10.515 12.707 10.605 12.977 ;
     RECT  7.596 12.977 7.614 13.085 ;
    LAYER M4 ;
     RECT  0.06 7.536 2.408 7.656 ;
     RECT  2.408 2.148 2.512 12.972 ;
     RECT  2.512 2.418 2.704 12.702 ;
     RECT  5.108 2.148 5.212 12.972 ;
     RECT  5.212 2.418 5.404 12.702 ;
     RECT  7.189 14.976 7.379 15 ;
     RECT  7.148 9.36 7.388 9.384 ;
     RECT  7.429 13.056 7.625 13.08 ;
     RECT  6.865 7.92 7.808 7.944 ;
     RECT  7.388 9.264 7.808 9.384 ;
     RECT  7.808 2.148 7.912 12.972 ;
     RECT  7.912 2.418 8.104 12.702 ;
     RECT  8.104 8.784 8.165 8.808 ;
     RECT  10.508 2.148 10.612 12.972 ;
     RECT  10.612 2.418 10.804 12.702 ;
     RECT  13.633 7.632 14.209 7.656 ;
     RECT  14.209 7.632 15.084 7.752 ;
    LAYER M5 ;
     RECT  2.4 2.137 2.52 2.151 ;
     RECT  5.1 2.137 5.22 2.151 ;
     RECT  7.8 2.137 7.92 2.151 ;
     RECT  10.5 2.137 10.62 2.151 ;
     RECT  7.8 2.151 8.112 7.909 ;
     RECT  7.44 7.909 8.112 9.349 ;
     RECT  2.4 2.151 2.712 12.969 ;
     RECT  5.1 2.151 5.412 12.969 ;
     RECT  7.2 9.349 8.112 12.969 ;
     RECT  10.5 2.151 10.812 12.969 ;
     RECT  2.4 12.969 2.52 12.983 ;
     RECT  5.1 12.969 5.22 12.983 ;
     RECT  7.2 12.969 7.92 12.983 ;
     RECT  10.5 12.969 10.62 12.983 ;
     RECT  7.2 12.983 7.464 15.011 ;
     RECT  7.344 15.011 7.464 15.056 ;
  END
END dsfd_rly_2_WE

VERSION 5.8 ;
BUSBITCHARS "[]" ;
DIVIDERCHAR "/" ;
UNITS
    DATABASE MICRONS 1000 ;
END UNITS

MACRO dsfd_rly_2_WS
  FOREIGN dsfd_rly_2_WS 0 0 ;
  CLASS BLOCK ;
  SIZE 15.12 BY 15.12 ;
  PIN ck
    DIRECTION INPUT ;
    USE SIGNAL ;
    PORT
      LAYER M5 ;
        RECT  7.344 15.036 7.368 15.12 ;
    END
  END ck
  PIN i[0]
    DIRECTION INPUT ;
    USE SIGNAL ;
    PORT
      LAYER M4 ;
        RECT  0 7.536 0.084 7.56 ;
    END
  END i[0]
  PIN i[1]
    DIRECTION INPUT ;
    USE SIGNAL ;
    PORT
      LAYER M4 ;
        RECT  0 7.632 0.084 7.656 ;
    END
  END i[1]
  PIN o[0]
    DIRECTION OUTPUT ;
    USE SIGNAL ;
    PORT
      LAYER M5 ;
        RECT  7.824 0 7.848 0.084 ;
    END
  END o[0]
  PIN o[1]
    DIRECTION OUTPUT ;
    USE SIGNAL ;
    PORT
      LAYER M5 ;
        RECT  7.92 0 7.944 0.084 ;
    END
  END o[1]
  PIN rs
    DIRECTION INPUT ;
    USE SIGNAL ;
    PORT
      LAYER M5 ;
        RECT  7.44 15.036 7.464 15.12 ;
    END
  END rs
  PIN VDD
    DIRECTION INOUT ;
    USE POWER ;
    PORT
      LAYER M5 ;
        RECT  10.692 2.151 10.812 12.969 ;
        RECT  7.992 2.151 8.112 12.969 ;
        RECT  5.292 2.151 5.412 12.969 ;
        RECT  2.592 2.151 2.712 12.969 ;
    END
  END VDD
  PIN VSS
    DIRECTION INOUT ;
    USE GROUND ;
    PORT
      LAYER M5 ;
        RECT  10.5 2.137 10.62 12.983 ;
        RECT  7.8 2.137 7.92 12.983 ;
        RECT  5.1 2.137 5.22 12.983 ;
        RECT  2.4 2.137 2.52 12.983 ;
    END
  END VSS
  OBS
    LAYER RVTN ;
     RECT  2.16 2.16 12.96 2.295 ;
     RECT  2.16 2.565 12.96 2.835 ;
     RECT  2.16 3.105 12.96 3.375 ;
     RECT  2.16 3.645 12.96 3.915 ;
     RECT  2.16 4.185 12.96 4.455 ;
     RECT  2.16 4.725 12.96 4.995 ;
     RECT  2.16 5.265 12.96 5.535 ;
     RECT  2.16 5.805 12.96 6.075 ;
     RECT  2.16 6.345 12.96 6.615 ;
     RECT  2.16 6.885 12.96 7.155 ;
     RECT  2.16 7.425 12.96 7.695 ;
     RECT  2.16 7.965 12.96 8.235 ;
     RECT  2.16 8.505 12.96 8.775 ;
     RECT  2.16 9.045 12.96 9.315 ;
     RECT  2.16 9.585 12.96 9.855 ;
     RECT  2.16 10.125 12.96 10.395 ;
     RECT  2.16 10.665 12.96 10.935 ;
     RECT  2.16 11.205 12.96 11.475 ;
     RECT  2.16 11.745 12.96 12.015 ;
     RECT  2.16 12.285 12.96 12.555 ;
     RECT  2.16 12.825 12.96 12.96 ;
    LAYER RVTP ;
     RECT  2.16 2.295 12.96 2.565 ;
     RECT  2.16 2.835 12.96 3.105 ;
     RECT  2.16 3.375 12.96 3.645 ;
     RECT  2.16 3.915 12.96 4.185 ;
     RECT  2.16 4.455 12.96 4.725 ;
     RECT  2.16 4.995 12.96 5.265 ;
     RECT  2.16 5.535 12.96 5.805 ;
     RECT  2.16 6.075 12.96 6.345 ;
     RECT  2.16 6.615 12.96 6.885 ;
     RECT  2.16 7.155 12.96 7.425 ;
     RECT  2.16 7.695 12.96 7.965 ;
     RECT  2.16 8.235 12.96 8.505 ;
     RECT  2.16 8.775 12.96 9.045 ;
     RECT  2.16 9.315 12.96 9.585 ;
     RECT  2.16 9.855 12.96 10.125 ;
     RECT  2.16 10.395 12.96 10.665 ;
     RECT  2.16 10.935 12.96 11.205 ;
     RECT  2.16 11.475 12.96 11.745 ;
     RECT  2.16 12.015 12.96 12.285 ;
     RECT  2.16 12.555 12.96 12.825 ;
    LAYER M1 ;
     RECT  2.16 2.151 12.96 12.969 ;
    LAYER M2 ;
     RECT  2.16 2.151 12.96 12.969 ;
    LAYER M3 ;
     RECT  7.776 1.723 7.794 2.011 ;
     RECT  7.776 2.011 8.01 2.335 ;
     RECT  2.415 2.143 2.505 2.413 ;
     RECT  5.115 2.143 5.205 2.413 ;
     RECT  7.632 2.335 8.01 2.413 ;
     RECT  10.515 2.143 10.605 2.413 ;
     RECT  7.632 2.413 8.097 2.605 ;
     RECT  7.416 2.605 8.097 2.641 ;
     RECT  7.416 2.641 8.154 3.181 ;
     RECT  7.164 3.181 8.154 3.371 ;
     RECT  7.164 3.371 8.097 6.421 ;
     RECT  5.115 2.413 5.397 6.655 ;
     RECT  5.115 6.655 6.03 6.691 ;
     RECT  7.056 6.421 8.097 7.349 ;
     RECT  5.115 6.691 6.282 7.357 ;
     RECT  7.056 7.349 7.074 7.357 ;
     RECT  2.415 2.413 2.697 7.465 ;
     RECT  2.415 7.465 3.33 7.531 ;
     RECT  2.304 7.531 3.33 7.619 ;
     RECT  5.115 7.357 7.074 7.889 ;
     RECT  5.115 7.889 6.678 7.901 ;
     RECT  2.304 7.619 2.934 7.925 ;
     RECT  6.48 7.901 6.678 7.925 ;
     RECT  2.415 7.925 2.934 7.961 ;
     RECT  5.115 7.901 5.742 8.699 ;
     RECT  6.624 7.925 6.678 8.699 ;
     RECT  5.115 8.699 5.49 8.735 ;
     RECT  7.056 8.815 7.074 11.939 ;
     RECT  7.815 7.349 8.097 12.055 ;
     RECT  2.415 7.961 2.697 12.707 ;
     RECT  5.115 8.735 5.397 12.707 ;
     RECT  7.416 12.055 8.097 12.707 ;
     RECT  10.515 2.413 10.797 12.707 ;
     RECT  2.415 12.707 2.505 12.977 ;
     RECT  5.115 12.707 5.205 12.977 ;
     RECT  7.416 12.707 7.905 12.977 ;
     RECT  10.515 12.707 10.605 12.977 ;
     RECT  7.416 12.977 7.434 15.005 ;
    LAYER M4 ;
     RECT  0.06 7.536 2.408 7.656 ;
     RECT  2.408 2.148 2.512 12.972 ;
     RECT  2.512 2.418 2.704 12.702 ;
     RECT  5.108 2.148 5.212 12.972 ;
     RECT  5.212 2.418 5.404 12.702 ;
     RECT  5.404 7.776 6.035 8.568 ;
     RECT  6.035 7.776 6.076 7.896 ;
     RECT  7.405 14.976 7.489 15 ;
     RECT  7.765 1.728 7.808 1.752 ;
     RECT  6.076 7.776 7.808 7.8 ;
     RECT  7.808 1.728 7.859 12.972 ;
     RECT  7.859 2.016 7.912 12.972 ;
     RECT  7.912 2.016 8.021 12.702 ;
     RECT  8.021 2.418 8.104 12.702 ;
     RECT  10.508 2.148 10.612 12.972 ;
     RECT  10.612 2.418 10.804 12.702 ;
    LAYER M5 ;
     RECT  7.824 0.016 7.944 2.137 ;
     RECT  2.4 2.137 2.52 2.151 ;
     RECT  5.1 2.137 5.22 2.151 ;
     RECT  7.8 2.137 7.944 2.151 ;
     RECT  10.5 2.137 10.62 2.151 ;
     RECT  7.8 2.151 8.112 7.765 ;
     RECT  5.1 2.151 5.412 7.861 ;
     RECT  5.1 7.861 6.024 8.579 ;
     RECT  2.4 2.151 2.712 12.969 ;
     RECT  5.1 8.579 5.412 12.969 ;
     RECT  7.344 7.765 8.112 12.969 ;
     RECT  10.5 2.151 10.812 12.969 ;
     RECT  2.4 12.969 2.52 12.983 ;
     RECT  5.1 12.969 5.22 12.983 ;
     RECT  7.344 12.969 7.92 12.983 ;
     RECT  10.5 12.969 10.62 12.983 ;
     RECT  7.344 12.983 7.368 14.965 ;
     RECT  7.344 14.965 7.464 15.056 ;
  END
END dsfd_rly_2_WS

VERSION 5.8 ;
BUSBITCHARS "[]" ;
DIVIDERCHAR "/" ;
UNITS
    DATABASE MICRONS 1000 ;
END UNITS

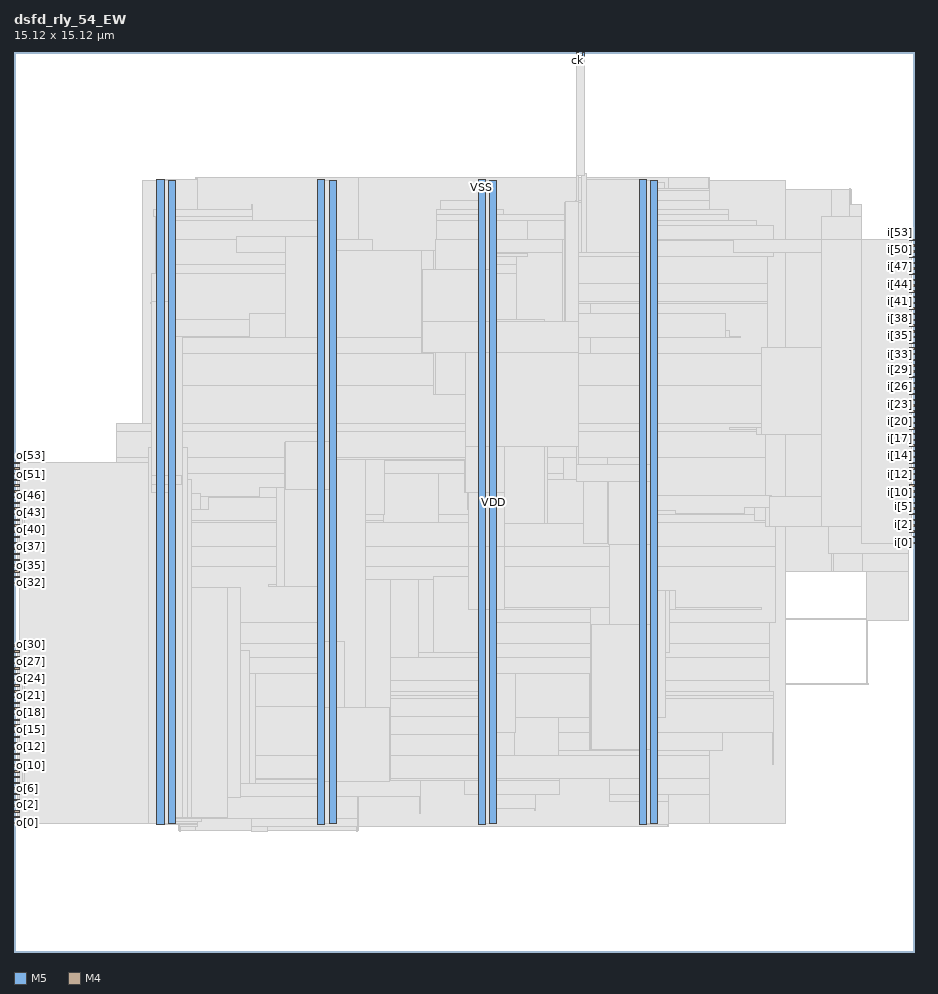
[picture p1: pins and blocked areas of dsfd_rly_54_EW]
MACRO dsfd_rly_54_EW
  FOREIGN dsfd_rly_54_EW 0 0 ;
  CLASS BLOCK ;
  SIZE 15.12 BY 15.12 ;
  PIN ck
    DIRECTION INPUT ;
    USE SIGNAL ;
    PORT
      LAYER M5 ;
        RECT  9.456 15.036 9.48 15.12 ;
    END
  END ck
  PIN i[0]
    DIRECTION INPUT ;
    USE SIGNAL ;
    PORT
      LAYER M4 ;
        RECT  15.036 6.864 15.12 6.888 ;
    END
  END i[0]
  PIN i[10]
    DIRECTION INPUT ;
    USE SIGNAL ;
    PORT
      LAYER M4 ;
        RECT  15.036 7.824 15.12 7.848 ;
    END
  END i[10]
  PIN i[11]
    DIRECTION INPUT ;
    USE SIGNAL ;
    PORT
      LAYER M4 ;
        RECT  15.036 7.92 15.12 7.944 ;
    END
  END i[11]
  PIN i[12]
    DIRECTION INPUT ;
    USE SIGNAL ;
    PORT
      LAYER M4 ;
        RECT  15.036 8.016 15.12 8.04 ;
    END
  END i[12]
  PIN i[13]
    DIRECTION INPUT ;
    USE SIGNAL ;
    PORT
      LAYER M4 ;
        RECT  15.036 8.112 15.12 8.136 ;
    END
  END i[13]
  PIN i[14]
    DIRECTION INPUT ;
    USE SIGNAL ;
    PORT
      LAYER M4 ;
        RECT  15.036 8.208 15.12 8.232 ;
    END
  END i[14]
  PIN i[15]
    DIRECTION INPUT ;
    USE SIGNAL ;
    PORT
      LAYER M4 ;
        RECT  15.036 8.304 15.12 8.328 ;
    END
  END i[15]
  PIN i[16]
    DIRECTION INPUT ;
    USE SIGNAL ;
    PORT
      LAYER M4 ;
        RECT  15.036 8.4 15.12 8.424 ;
    END
  END i[16]
  PIN i[17]
    DIRECTION INPUT ;
    USE SIGNAL ;
    PORT
      LAYER M4 ;
        RECT  15.036 8.496 15.12 8.52 ;
    END
  END i[17]
  PIN i[18]
    DIRECTION INPUT ;
    USE SIGNAL ;
    PORT
      LAYER M4 ;
        RECT  15.036 8.592 15.12 8.616 ;
    END
  END i[18]
  PIN i[19]
    DIRECTION INPUT ;
    USE SIGNAL ;
    PORT
      LAYER M4 ;
        RECT  15.036 8.688 15.12 8.712 ;
    END
  END i[19]
  PIN i[1]
    DIRECTION INPUT ;
    USE SIGNAL ;
    PORT
      LAYER M4 ;
        RECT  15.036 6.96 15.12 6.984 ;
    END
  END i[1]
  PIN i[20]
    DIRECTION INPUT ;
    USE SIGNAL ;
    PORT
      LAYER M4 ;
        RECT  15.036 8.784 15.12 8.808 ;
    END
  END i[20]
  PIN i[21]
    DIRECTION INPUT ;
    USE SIGNAL ;
    PORT
      LAYER M4 ;
        RECT  15.036 8.88 15.12 8.904 ;
    END
  END i[21]
  PIN i[22]
    DIRECTION INPUT ;
    USE SIGNAL ;
    PORT
      LAYER M4 ;
        RECT  15.036 8.976 15.12 9 ;
    END
  END i[22]
  PIN i[23]
    DIRECTION INPUT ;
    USE SIGNAL ;
    PORT
      LAYER M4 ;
        RECT  15.036 9.072 15.12 9.096 ;
    END
  END i[23]
  PIN i[24]
    DIRECTION INPUT ;
    USE SIGNAL ;
    PORT
      LAYER M4 ;
        RECT  15.036 9.168 15.12 9.192 ;
    END
  END i[24]
  PIN i[25]
    DIRECTION INPUT ;
    USE SIGNAL ;
    PORT
      LAYER M4 ;
        RECT  15.036 9.264 15.12 9.288 ;
    END
  END i[25]
  PIN i[26]
    DIRECTION INPUT ;
    USE SIGNAL ;
    PORT
      LAYER M4 ;
        RECT  15.036 9.36 15.12 9.384 ;
    END
  END i[26]
  PIN i[27]
    DIRECTION INPUT ;
    USE SIGNAL ;
    PORT
      LAYER M4 ;
        RECT  15.036 9.456 15.12 9.48 ;
    END
  END i[27]
  PIN i[28]
    DIRECTION INPUT ;
    USE SIGNAL ;
    PORT
      LAYER M4 ;
        RECT  15.036 9.552 15.12 9.576 ;
    END
  END i[28]
  PIN i[29]
    DIRECTION INPUT ;
    USE SIGNAL ;
    PORT
      LAYER M4 ;
        RECT  15.036 9.648 15.12 9.672 ;
    END
  END i[29]
  PIN i[2]
    DIRECTION INPUT ;
    USE SIGNAL ;
    PORT
      LAYER M4 ;
        RECT  15.036 7.056 15.12 7.08 ;
    END
  END i[2]
  PIN i[30]
    DIRECTION INPUT ;
    USE SIGNAL ;
    PORT
      LAYER M4 ;
        RECT  15.036 9.744 15.12 9.768 ;
    END
  END i[30]
  PIN i[31]
    DIRECTION INPUT ;
    USE SIGNAL ;
    PORT
      LAYER M4 ;
        RECT  15.036 9.84 15.12 9.864 ;
    END
  END i[31]
  PIN i[32]
    DIRECTION INPUT ;
    USE SIGNAL ;
    PORT
      LAYER M4 ;
        RECT  15.036 9.936 15.12 9.96 ;
    END
  END i[32]
  PIN i[33]
    DIRECTION INPUT ;
    USE SIGNAL ;
    PORT
      LAYER M4 ;
        RECT  15.036 10.032 15.12 10.056 ;
    END
  END i[33]
  PIN i[34]
    DIRECTION INPUT ;
    USE SIGNAL ;
    PORT
      LAYER M4 ;
        RECT  15.036 10.128 15.12 10.152 ;
    END
  END i[34]
  PIN i[35]
    DIRECTION INPUT ;
    USE SIGNAL ;
    PORT
      LAYER M4 ;
        RECT  15.036 10.224 15.12 10.248 ;
    END
  END i[35]
  PIN i[36]
    DIRECTION INPUT ;
    USE SIGNAL ;
    PORT
      LAYER M4 ;
        RECT  15.036 10.32 15.12 10.344 ;
    END
  END i[36]
  PIN i[37]
    DIRECTION INPUT ;
    USE SIGNAL ;
    PORT
      LAYER M4 ;
        RECT  15.036 10.416 15.12 10.44 ;
    END
  END i[37]
  PIN i[38]
    DIRECTION INPUT ;
    USE SIGNAL ;
    PORT
      LAYER M4 ;
        RECT  15.036 10.512 15.12 10.536 ;
    END
  END i[38]
  PIN i[39]
    DIRECTION INPUT ;
    USE SIGNAL ;
    PORT
      LAYER M4 ;
        RECT  15.036 10.608 15.12 10.632 ;
    END
  END i[39]
  PIN i[3]
    DIRECTION INPUT ;
    USE SIGNAL ;
    PORT
      LAYER M4 ;
        RECT  15.036 7.152 15.12 7.176 ;
    END
  END i[3]
  PIN i[40]
    DIRECTION INPUT ;
    USE SIGNAL ;
    PORT
      LAYER M4 ;
        RECT  15.036 10.704 15.12 10.728 ;
    END
  END i[40]
  PIN i[41]
    DIRECTION INPUT ;
    USE SIGNAL ;
    PORT
      LAYER M4 ;
        RECT  15.036 10.8 15.12 10.824 ;
    END
  END i[41]
  PIN i[42]
    DIRECTION INPUT ;
    USE SIGNAL ;
    PORT
      LAYER M4 ;
        RECT  15.036 10.896 15.12 10.92 ;
    END
  END i[42]
  PIN i[43]
    DIRECTION INPUT ;
    USE SIGNAL ;
    PORT
      LAYER M4 ;
        RECT  15.036 10.992 15.12 11.016 ;
    END
  END i[43]
  PIN i[44]
    DIRECTION INPUT ;
    USE SIGNAL ;
    PORT
      LAYER M4 ;
        RECT  15.036 11.088 15.12 11.112 ;
    END
  END i[44]
  PIN i[45]
    DIRECTION INPUT ;
    USE SIGNAL ;
    PORT
      LAYER M4 ;
        RECT  15.036 11.184 15.12 11.208 ;
    END
  END i[45]
  PIN i[46]
    DIRECTION INPUT ;
    USE SIGNAL ;
    PORT
      LAYER M4 ;
        RECT  15.036 11.28 15.12 11.304 ;
    END
  END i[46]
  PIN i[47]
    DIRECTION INPUT ;
    USE SIGNAL ;
    PORT
      LAYER M4 ;
        RECT  15.036 11.376 15.12 11.4 ;
    END
  END i[47]
  PIN i[48]
    DIRECTION INPUT ;
    USE SIGNAL ;
    PORT
      LAYER M4 ;
        RECT  15.036 11.472 15.12 11.496 ;
    END
  END i[48]
  PIN i[49]
    DIRECTION INPUT ;
    USE SIGNAL ;
    PORT
      LAYER M4 ;
        RECT  15.036 11.568 15.12 11.592 ;
    END
  END i[49]
  PIN i[4]
    DIRECTION INPUT ;
    USE SIGNAL ;
    PORT
      LAYER M4 ;
        RECT  15.036 7.248 15.12 7.272 ;
    END
  END i[4]
  PIN i[50]
    DIRECTION INPUT ;
    USE SIGNAL ;
    PORT
      LAYER M4 ;
        RECT  15.036 11.664 15.12 11.688 ;
    END
  END i[50]
  PIN i[51]
    DIRECTION INPUT ;
    USE SIGNAL ;
    PORT
      LAYER M4 ;
        RECT  15.036 11.76 15.12 11.784 ;
    END
  END i[51]
  PIN i[52]
    DIRECTION INPUT ;
    USE SIGNAL ;
    PORT
      LAYER M4 ;
        RECT  15.036 11.856 15.12 11.88 ;
    END
  END i[52]
  PIN i[53]
    DIRECTION INPUT ;
    USE SIGNAL ;
    PORT
      LAYER M4 ;
        RECT  15.036 11.952 15.12 11.976 ;
    END
  END i[53]
  PIN i[5]
    DIRECTION INPUT ;
    USE SIGNAL ;
    PORT
      LAYER M4 ;
        RECT  15.036 7.344 15.12 7.368 ;
    END
  END i[5]
  PIN i[6]
    DIRECTION INPUT ;
    USE SIGNAL ;
    PORT
      LAYER M4 ;
        RECT  15.036 7.44 15.12 7.464 ;
    END
  END i[6]
  PIN i[7]
    DIRECTION INPUT ;
    USE SIGNAL ;
    PORT
      LAYER M4 ;
        RECT  15.036 7.536 15.12 7.56 ;
    END
  END i[7]
  PIN i[8]
    DIRECTION INPUT ;
    USE SIGNAL ;
    PORT
      LAYER M4 ;
        RECT  15.036 7.632 15.12 7.656 ;
    END
  END i[8]
  PIN i[9]
    DIRECTION INPUT ;
    USE SIGNAL ;
    PORT
      LAYER M4 ;
        RECT  15.036 7.728 15.12 7.752 ;
    END
  END i[9]
  PIN o[0]
    DIRECTION OUTPUT ;
    USE SIGNAL ;
    PORT
      LAYER M4 ;
        RECT  0 2.16 0.084 2.184 ;
    END
  END o[0]
  PIN o[10]
    DIRECTION OUTPUT ;
    USE SIGNAL ;
    PORT
      LAYER M4 ;
        RECT  0 3.12 0.084 3.144 ;
    END
  END o[10]
  PIN o[11]
    DIRECTION OUTPUT ;
    USE SIGNAL ;
    PORT
      LAYER M4 ;
        RECT  0 3.216 0.084 3.24 ;
    END
  END o[11]
  PIN o[12]
    DIRECTION OUTPUT ;
    USE SIGNAL ;
    PORT
      LAYER M4 ;
        RECT  0 3.312 0.084 3.336 ;
    END
  END o[12]
  PIN o[13]
    DIRECTION OUTPUT ;
    USE SIGNAL ;
    PORT
      LAYER M4 ;
        RECT  0 3.408 0.084 3.432 ;
    END
  END o[13]
  PIN o[14]
    DIRECTION OUTPUT ;
    USE SIGNAL ;
    PORT
      LAYER M4 ;
        RECT  0 3.504 0.084 3.528 ;
    END
  END o[14]
  PIN o[15]
    DIRECTION OUTPUT ;
    USE SIGNAL ;
    PORT
      LAYER M4 ;
        RECT  0 3.6 0.084 3.624 ;
    END
  END o[15]
  PIN o[16]
    DIRECTION OUTPUT ;
    USE SIGNAL ;
    PORT
      LAYER M4 ;
        RECT  0 3.696 0.084 3.72 ;
    END
  END o[16]
  PIN o[17]
    DIRECTION OUTPUT ;
    USE SIGNAL ;
    PORT
      LAYER M4 ;
        RECT  0 3.792 0.084 3.816 ;
    END
  END o[17]
  PIN o[18]
    DIRECTION OUTPUT ;
    USE SIGNAL ;
    PORT
      LAYER M4 ;
        RECT  0 3.888 0.084 3.912 ;
    END
  END o[18]
  PIN o[19]
    DIRECTION OUTPUT ;
    USE SIGNAL ;
    PORT
      LAYER M4 ;
        RECT  0 3.984 0.084 4.008 ;
    END
  END o[19]
  PIN o[1]
    DIRECTION OUTPUT ;
    USE SIGNAL ;
    PORT
      LAYER M4 ;
        RECT  0 2.256 0.084 2.28 ;
    END
  END o[1]
  PIN o[20]
    DIRECTION OUTPUT ;
    USE SIGNAL ;
    PORT
      LAYER M4 ;
        RECT  0 4.08 0.084 4.104 ;
    END
  END o[20]
  PIN o[21]
    DIRECTION OUTPUT ;
    USE SIGNAL ;
    PORT
      LAYER M4 ;
        RECT  0 4.176 0.084 4.2 ;
    END
  END o[21]
  PIN o[22]
    DIRECTION OUTPUT ;
    USE SIGNAL ;
    PORT
      LAYER M4 ;
        RECT  0 4.272 0.084 4.296 ;
    END
  END o[22]
  PIN o[23]
    DIRECTION OUTPUT ;
    USE SIGNAL ;
    PORT
      LAYER M4 ;
        RECT  0 4.368 0.084 4.392 ;
    END
  END o[23]
  PIN o[24]
    DIRECTION OUTPUT ;
    USE SIGNAL ;
    PORT
      LAYER M4 ;
        RECT  0 4.464 0.084 4.488 ;
    END
  END o[24]
  PIN o[25]
    DIRECTION OUTPUT ;
    USE SIGNAL ;
    PORT
      LAYER M4 ;
        RECT  0 4.56 0.084 4.584 ;
    END
  END o[25]
  PIN o[26]
    DIRECTION OUTPUT ;
    USE SIGNAL ;
    PORT
      LAYER M4 ;
        RECT  0 4.656 0.084 4.68 ;
    END
  END o[26]
  PIN o[27]
    DIRECTION OUTPUT ;
    USE SIGNAL ;
    PORT
      LAYER M4 ;
        RECT  0 4.752 0.084 4.776 ;
    END
  END o[27]
  PIN o[28]
    DIRECTION OUTPUT ;
    USE SIGNAL ;
    PORT
      LAYER M4 ;
        RECT  0 4.848 0.084 4.872 ;
    END
  END o[28]
  PIN o[29]
    DIRECTION OUTPUT ;
    USE SIGNAL ;
    PORT
      LAYER M4 ;
        RECT  0 4.944 0.084 4.968 ;
    END
  END o[29]
  PIN o[2]
    DIRECTION OUTPUT ;
    USE SIGNAL ;
    PORT
      LAYER M4 ;
        RECT  0 2.352 0.084 2.376 ;
    END
  END o[2]
  PIN o[30]
    DIRECTION OUTPUT ;
    USE SIGNAL ;
    PORT
      LAYER M4 ;
        RECT  0 5.04 0.084 5.064 ;
    END
  END o[30]
  PIN o[31]
    DIRECTION OUTPUT ;
    USE SIGNAL ;
    PORT
      LAYER M4 ;
        RECT  0 5.136 0.084 5.16 ;
    END
  END o[31]
  PIN o[32]
    DIRECTION OUTPUT ;
    USE SIGNAL ;
    PORT
      LAYER M4 ;
        RECT  0 6.192 0.084 6.216 ;
    END
  END o[32]
  PIN o[33]
    DIRECTION OUTPUT ;
    USE SIGNAL ;
    PORT
      LAYER M4 ;
        RECT  0 6.288 0.084 6.312 ;
    END
  END o[33]
  PIN o[34]
    DIRECTION OUTPUT ;
    USE SIGNAL ;
    PORT
      LAYER M4 ;
        RECT  0 6.384 0.084 6.408 ;
    END
  END o[34]
  PIN o[35]
    DIRECTION OUTPUT ;
    USE SIGNAL ;
    PORT
      LAYER M4 ;
        RECT  0 6.48 0.084 6.504 ;
    END
  END o[35]
  PIN o[36]
    DIRECTION OUTPUT ;
    USE SIGNAL ;
    PORT
      LAYER M4 ;
        RECT  0 6.576 0.084 6.6 ;
    END
  END o[36]
  PIN o[37]
    DIRECTION OUTPUT ;
    USE SIGNAL ;
    PORT
      LAYER M4 ;
        RECT  0 6.672 0.084 6.696 ;
    END
  END o[37]
  PIN o[38]
    DIRECTION OUTPUT ;
    USE SIGNAL ;
    PORT
      LAYER M4 ;
        RECT  0 6.768 0.084 6.792 ;
    END
  END o[38]
  PIN o[39]
    DIRECTION OUTPUT ;
    USE SIGNAL ;
    PORT
      LAYER M4 ;
        RECT  0 6.864 0.084 6.888 ;
    END
  END o[39]
  PIN o[3]
    DIRECTION OUTPUT ;
    USE SIGNAL ;
    PORT
      LAYER M4 ;
        RECT  0 2.448 0.084 2.472 ;
    END
  END o[3]
  PIN o[40]
    DIRECTION OUTPUT ;
    USE SIGNAL ;
    PORT
      LAYER M4 ;
        RECT  0 6.96 0.084 6.984 ;
    END
  END o[40]
  PIN o[41]
    DIRECTION OUTPUT ;
    USE SIGNAL ;
    PORT
      LAYER M4 ;
        RECT  0 7.056 0.084 7.08 ;
    END
  END o[41]
  PIN o[42]
    DIRECTION OUTPUT ;
    USE SIGNAL ;
    PORT
      LAYER M4 ;
        RECT  0 7.152 0.084 7.176 ;
    END
  END o[42]
  PIN o[43]
    DIRECTION OUTPUT ;
    USE SIGNAL ;
    PORT
      LAYER M4 ;
        RECT  0 7.248 0.084 7.272 ;
    END
  END o[43]
  PIN o[44]
    DIRECTION OUTPUT ;
    USE SIGNAL ;
    PORT
      LAYER M4 ;
        RECT  0 7.344 0.084 7.368 ;
    END
  END o[44]
  PIN o[45]
    DIRECTION OUTPUT ;
    USE SIGNAL ;
    PORT
      LAYER M4 ;
        RECT  0 7.44 0.084 7.464 ;
    END
  END o[45]
  PIN o[46]
    DIRECTION OUTPUT ;
    USE SIGNAL ;
    PORT
      LAYER M4 ;
        RECT  0 7.536 0.084 7.56 ;
    END
  END o[46]
  PIN o[47]
    DIRECTION OUTPUT ;
    USE SIGNAL ;
    PORT
      LAYER M4 ;
        RECT  0 7.632 0.084 7.656 ;
    END
  END o[47]
  PIN o[48]
    DIRECTION OUTPUT ;
    USE SIGNAL ;
    PORT
      LAYER M4 ;
        RECT  0 7.728 0.084 7.752 ;
    END
  END o[48]
  PIN o[49]
    DIRECTION OUTPUT ;
    USE SIGNAL ;
    PORT
      LAYER M4 ;
        RECT  0 7.824 0.084 7.848 ;
    END
  END o[49]
  PIN o[4]
    DIRECTION OUTPUT ;
    USE SIGNAL ;
    PORT
      LAYER M4 ;
        RECT  0 2.544 0.084 2.568 ;
    END
  END o[4]
  PIN o[50]
    DIRECTION OUTPUT ;
    USE SIGNAL ;
    PORT
      LAYER M4 ;
        RECT  0 7.92 0.084 7.944 ;
    END
  END o[50]
  PIN o[51]
    DIRECTION OUTPUT ;
    USE SIGNAL ;
    PORT
      LAYER M4 ;
        RECT  0 8.016 0.084 8.04 ;
    END
  END o[51]
  PIN o[52]
    DIRECTION OUTPUT ;
    USE SIGNAL ;
    PORT
      LAYER M4 ;
        RECT  0 8.112 0.084 8.136 ;
    END
  END o[52]
  PIN o[53]
    DIRECTION OUTPUT ;
    USE SIGNAL ;
    PORT
      LAYER M4 ;
        RECT  0 8.208 0.084 8.232 ;
    END
  END o[53]
  PIN o[5]
    DIRECTION OUTPUT ;
    USE SIGNAL ;
    PORT
      LAYER M4 ;
        RECT  0 2.64 0.084 2.664 ;
    END
  END o[5]
  PIN o[6]
    DIRECTION OUTPUT ;
    USE SIGNAL ;
    PORT
      LAYER M4 ;
        RECT  0 2.736 0.084 2.76 ;
    END
  END o[6]
  PIN o[7]
    DIRECTION OUTPUT ;
    USE SIGNAL ;
    PORT
      LAYER M4 ;
        RECT  0 2.832 0.084 2.856 ;
    END
  END o[7]
  PIN o[8]
    DIRECTION OUTPUT ;
    USE SIGNAL ;
    PORT
      LAYER M4 ;
        RECT  0 2.928 0.084 2.952 ;
    END
  END o[8]
  PIN o[9]
    DIRECTION OUTPUT ;
    USE SIGNAL ;
    PORT
      LAYER M4 ;
        RECT  0 3.024 0.084 3.048 ;
    END
  END o[9]
  PIN rs
    DIRECTION INPUT ;
    USE SIGNAL ;
    PORT
      LAYER M5 ;
        RECT  9.552 15.036 9.576 15.12 ;
    END
  END rs
  PIN VDD
    DIRECTION INOUT ;
    USE POWER ;
    PORT
      LAYER M5 ;
        RECT  10.692 2.151 10.812 12.969 ;
        RECT  7.992 2.151 8.112 12.969 ;
        RECT  5.292 2.151 5.412 12.969 ;
        RECT  2.592 2.151 2.712 12.969 ;
    END
  END VDD
  PIN VSS
    DIRECTION INOUT ;
    USE GROUND ;
    PORT
      LAYER M5 ;
        RECT  10.5 2.137 10.62 12.983 ;
        RECT  7.8 2.137 7.92 12.983 ;
        RECT  5.1 2.137 5.22 12.983 ;
        RECT  2.4 2.137 2.52 12.983 ;
    END
  END VSS
  OBS
    LAYER RVTN ;
     RECT  2.16 2.16 12.96 2.295 ;
     RECT  2.16 2.565 12.96 2.835 ;
     RECT  2.16 3.105 12.96 3.375 ;
     RECT  2.16 3.645 12.96 3.915 ;
     RECT  2.16 4.185 12.96 4.455 ;
     RECT  2.16 4.725 12.96 4.995 ;
     RECT  2.16 5.265 12.96 5.535 ;
     RECT  2.16 5.805 12.96 6.075 ;
     RECT  2.16 6.345 12.96 6.615 ;
     RECT  2.16 6.885 12.96 7.155 ;
     RECT  2.16 7.425 12.96 7.695 ;
     RECT  2.16 7.965 12.96 8.235 ;
     RECT  2.16 8.505 12.96 8.775 ;
     RECT  2.16 9.045 12.96 9.315 ;
     RECT  2.16 9.585 12.96 9.855 ;
     RECT  2.16 10.125 12.96 10.395 ;
     RECT  2.16 10.665 12.96 10.935 ;
     RECT  2.16 11.205 12.96 11.475 ;
     RECT  2.16 11.745 12.96 12.015 ;
     RECT  2.16 12.285 12.96 12.555 ;
     RECT  2.16 12.825 12.96 12.96 ;
    LAYER RVTP ;
     RECT  2.16 2.295 12.96 2.565 ;
     RECT  2.16 2.835 12.96 3.105 ;
     RECT  2.16 3.375 12.96 3.645 ;
     RECT  2.16 3.915 12.96 4.185 ;
     RECT  2.16 4.455 12.96 4.725 ;
     RECT  2.16 4.995 12.96 5.265 ;
     RECT  2.16 5.535 12.96 5.805 ;
     RECT  2.16 6.075 12.96 6.345 ;
     RECT  2.16 6.615 12.96 6.885 ;
     RECT  2.16 7.155 12.96 7.425 ;
     RECT  2.16 7.695 12.96 7.965 ;
     RECT  2.16 8.235 12.96 8.505 ;
     RECT  2.16 8.775 12.96 9.045 ;
     RECT  2.16 9.315 12.96 9.585 ;
     RECT  2.16 9.855 12.96 10.125 ;
     RECT  2.16 10.395 12.96 10.665 ;
     RECT  2.16 10.935 12.96 11.205 ;
     RECT  2.16 11.475 12.96 11.745 ;
     RECT  2.16 12.015 12.96 12.285 ;
     RECT  2.16 12.555 12.96 12.825 ;
    LAYER M1 ;
     RECT  2.16 2.151 12.96 12.969 ;
    LAYER M2 ;
     RECT  0.103 3.888 0.203 3.906 ;
     RECT  0.211 5.04 0.347 5.058 ;
     RECT  0.103 7.866 2.16 7.884 ;
     RECT  1.723 8.856 2.16 8.874 ;
     RECT  2.16 2.151 2.767 12.969 ;
     RECT  2.767 2.034 3.055 12.969 ;
     RECT  3.055 2.034 5.783 13.014 ;
     RECT  5.783 2.106 11.003 13.014 ;
     RECT  11.003 2.151 11.687 13.014 ;
     RECT  11.687 2.151 12.96 12.969 ;
     RECT  12.96 6.39 13.739 12.816 ;
     RECT  13.739 6.39 13.775 7.794 ;
     RECT  13.739 9.09 14.063 12.816 ;
     RECT  14.063 9.09 14.171 12.546 ;
     RECT  14.171 9.09 14.243 10.998 ;
     RECT  14.171 11.79 14.243 12.546 ;
     RECT  13.775 6.39 14.279 7.722 ;
     RECT  14.243 9.09 14.279 9.108 ;
     RECT  14.243 10.98 14.279 10.998 ;
     RECT  14.243 11.79 14.279 11.808 ;
     RECT  14.279 6.822 14.315 6.984 ;
     RECT  12.96 4.5 14.351 4.518 ;
     RECT  14.315 6.966 14.387 6.984 ;
     RECT  12.96 5.58 15.035 5.598 ;
     RECT  14.243 9.936 15.035 9.954 ;
    LAYER M3 ;
     RECT  2.772 2.029 2.79 2.101 ;
     RECT  3.996 2.029 4.266 2.101 ;
     RECT  5.76 2.029 5.778 2.101 ;
     RECT  2.772 2.101 3.078 2.143 ;
     RECT  10.98 2.101 10.998 2.143 ;
     RECT  2.415 2.143 3.078 2.155 ;
     RECT  2.304 2.155 3.078 2.191 ;
     RECT  2.304 2.191 3.15 2.251 ;
     RECT  3.996 2.101 5.778 2.251 ;
     RECT  7.815 2.143 7.905 2.413 ;
     RECT  8.748 2.371 8.766 2.413 ;
     RECT  10.515 2.143 10.998 2.533 ;
     RECT  2.304 2.251 5.778 2.605 ;
     RECT  6.804 2.335 6.822 2.605 ;
     RECT  7.815 2.413 8.766 2.641 ;
     RECT  10.008 2.533 10.998 2.641 ;
     RECT  2.304 2.605 6.822 2.875 ;
     RECT  7.56 2.641 9.162 2.875 ;
     RECT  2.304 2.875 9.162 2.911 ;
     RECT  10.008 2.641 11.682 2.911 ;
     RECT  0.144 2.587 0.162 2.923 ;
     RECT  2.304 2.911 11.682 3.299 ;
     RECT  9.144 3.299 11.682 3.379 ;
     RECT  0.144 2.923 0.342 3.629 ;
     RECT  9.144 3.379 11.898 3.685 ;
     RECT  12.744 3.145 12.762 3.685 ;
     RECT  0.144 3.629 0.198 3.868 ;
     RECT  0.108 3.868 0.198 4.109 ;
     RECT  2.304 3.299 8.406 4.261 ;
     RECT  9.144 3.685 12.762 4.261 ;
     RECT  2.268 4.261 12.762 4.301 ;
     RECT  0.144 4.109 0.198 4.363 ;
     RECT  2.304 4.301 12.762 4.379 ;
     RECT  2.304 4.379 12.69 4.559 ;
     RECT  2.34 4.559 12.69 4.955 ;
     RECT  0.144 4.363 0.342 5.069 ;
     RECT  2.376 4.955 12.69 5.189 ;
     RECT  0.108 5.131 0.126 5.261 ;
     RECT  2.415 5.189 12.69 5.539 ;
     RECT  14.328 4.495 14.346 5.575 ;
     RECT  0.108 6.091 0.126 6.221 ;
     RECT  14.328 5.575 15.03 6.385 ;
     RECT  2.415 5.539 12.798 6.475 ;
     RECT  14.256 6.385 15.03 6.691 ;
     RECT  0.144 6.619 0.162 6.797 ;
     RECT  2.304 6.475 12.798 6.817 ;
     RECT  0.324 7.051 0.342 7.181 ;
     RECT  2.232 6.817 12.798 7.223 ;
     RECT  2.232 7.223 6.21 7.243 ;
     RECT  7.128 7.223 12.798 7.349 ;
     RECT  13.68 6.691 15.03 7.565 ;
     RECT  9.972 7.349 12.726 7.661 ;
     RECT  13.68 7.565 14.382 7.757 ;
     RECT  13.68 7.757 14.274 7.915 ;
     RECT  1.728 7.243 6.21 8.041 ;
     RECT  7.128 7.349 9.234 8.041 ;
     RECT  0.108 7.861 0.126 8.141 ;
     RECT  13.608 7.915 14.274 8.203 ;
     RECT  13.572 8.203 14.274 8.303 ;
     RECT  1.728 8.041 9.234 8.311 ;
     RECT  9.972 7.661 12.618 8.311 ;
     RECT  1.728 8.311 12.618 8.743 ;
     RECT  1.728 8.743 12.762 8.879 ;
     RECT  13.644 8.303 14.274 9.197 ;
     RECT  13.644 9.197 14.238 9.259 ;
     RECT  2.304 8.879 12.762 9.509 ;
     RECT  15.012 9.931 15.03 9.968 ;
     RECT  2.304 9.509 12.654 10.049 ;
     RECT  2.304 10.049 8.91 10.625 ;
     RECT  13.608 9.259 14.238 10.699 ;
     RECT  13.572 10.699 14.238 10.795 ;
     RECT  9.684 10.049 12.654 10.891 ;
     RECT  9.252 10.891 12.654 10.931 ;
     RECT  13.572 10.795 14.274 11.003 ;
     RECT  9.396 10.931 12.654 11.237 ;
     RECT  2.304 10.625 8.442 11.399 ;
     RECT  2.376 11.399 8.442 11.543 ;
     RECT  6.984 11.543 8.442 11.677 ;
     RECT  9.432 11.237 12.654 11.677 ;
     RECT  6.984 11.677 8.622 11.741 ;
     RECT  13.572 11.003 14.238 11.785 ;
     RECT  13.572 11.785 14.274 11.885 ;
     RECT  2.376 11.543 6.03 11.975 ;
     RECT  9.432 11.677 12.762 12.209 ;
     RECT  2.376 11.975 5.397 12.281 ;
     RECT  9.432 12.209 12.474 12.281 ;
     RECT  7.092 11.741 8.622 12.289 ;
     RECT  9.432 12.281 12.006 12.289 ;
     RECT  13.572 11.885 14.238 12.353 ;
     RECT  2.376 12.281 4.014 12.361 ;
     RECT  7.092 12.289 12.006 12.389 ;
     RECT  2.34 12.361 4.014 12.479 ;
     RECT  7.092 12.389 8.226 12.479 ;
     RECT  9.432 12.389 12.006 12.479 ;
     RECT  3.996 12.479 4.014 12.551 ;
     RECT  14.04 12.353 14.238 12.551 ;
     RECT  7.164 12.479 8.097 12.623 ;
     RECT  9.432 12.479 11.682 12.623 ;
     RECT  5.115 12.281 5.397 12.707 ;
     RECT  7.815 12.623 8.097 12.707 ;
     RECT  9.54 12.623 9.666 12.749 ;
     RECT  10.404 12.623 11.682 12.785 ;
     RECT  10.515 12.785 11.682 12.821 ;
     RECT  14.04 12.551 14.058 12.821 ;
     RECT  10.515 12.821 10.926 12.929 ;
     RECT  2.415 12.479 3.078 12.977 ;
     RECT  5.115 12.707 5.205 12.977 ;
     RECT  7.815 12.707 7.905 12.977 ;
     RECT  10.515 12.929 10.605 12.977 ;
     RECT  3.06 12.977 3.078 13.019 ;
     RECT  11.664 12.821 11.682 13.019 ;
     RECT  9.54 12.749 9.558 13.085 ;
    LAYER M4 ;
     RECT  0.06 2.16 0.097 5.16 ;
     RECT  0.06 6.192 0.097 8.232 ;
     RECT  0.097 2.16 2.257 8.232 ;
     RECT  2.257 2.16 2.408 8.472 ;
     RECT  2.293 10.896 2.408 10.92 ;
     RECT  2.408 2.148 2.512 12.972 ;
     RECT  2.512 2.256 2.704 12.702 ;
     RECT  2.704 2.256 2.837 10.344 ;
     RECT  2.837 2.256 2.909 8.472 ;
     RECT  2.909 2.256 2.981 7.944 ;
     RECT  2.981 7.44 3.125 7.704 ;
     RECT  3.125 7.44 3.269 7.656 ;
     RECT  2.981 2.256 3.593 6.12 ;
     RECT  3.593 2.592 3.809 6.12 ;
     RECT  2.837 10.32 3.949 10.344 ;
     RECT  3.809 2.832 3.953 5.064 ;
     RECT  3.953 2.832 4.061 4.68 ;
     RECT  3.269 7.632 4.129 7.656 ;
     RECT  4.273 6.144 4.417 6.168 ;
     RECT  4.129 7.632 4.417 7.8 ;
     RECT  4.417 6.144 4.549 7.8 ;
     RECT  3.949 10.32 4.561 10.728 ;
     RECT  3.733 11.76 4.561 12.024 ;
     RECT  4.061 2.832 5.108 2.904 ;
     RECT  4.061 4.128 5.108 4.68 ;
     RECT  4.549 6.144 5.108 8.568 ;
     RECT  4.561 10.32 5.108 12.024 ;
     RECT  5.108 2.148 5.212 12.972 ;
     RECT  5.212 2.418 5.404 12.702 ;
     RECT  5.404 2.88 5.897 8.28 ;
     RECT  5.897 7.344 6.221 8.28 ;
     RECT  5.897 2.88 6.323 6.264 ;
     RECT  6.323 2.88 6.329 3.96 ;
     RECT  6.323 4.944 6.797 6.264 ;
     RECT  5.404 10.32 6.853 11.784 ;
     RECT  6.797 5.04 7.045 6.264 ;
     RECT  6.853 10.08 7.045 11.784 ;
     RECT  7.045 9.36 7.081 11.784 ;
     RECT  6.221 8.256 7.573 8.28 ;
     RECT  7.573 7.728 7.621 8.28 ;
     RECT  6.329 3.648 7.808 3.96 ;
     RECT  7.045 5.04 7.808 6.312 ;
     RECT  7.621 7.44 7.808 8.28 ;
     RECT  7.081 9.36 7.808 11.976 ;
     RECT  7.808 2.148 7.912 12.972 ;
     RECT  7.912 2.418 8.104 12.702 ;
     RECT  8.104 5.76 8.237 10.584 ;
     RECT  8.237 6.816 8.243 10.584 ;
     RECT  8.104 3.696 8.417 4.68 ;
     RECT  8.243 7.2 8.915 10.584 ;
     RECT  8.915 7.2 8.957 8.52 ;
     RECT  8.915 9.648 8.993 10.584 ;
     RECT  8.993 9.888 9.212 10.584 ;
     RECT  8.104 11.76 9.212 11.976 ;
     RECT  9.212 9.888 9.253 11.976 ;
     RECT  9.253 9.888 9.281 12.6 ;
     RECT  9.281 10.32 9.299 12.6 ;
     RECT  9.299 11.76 9.529 12.6 ;
     RECT  8.957 7.2 9.565 7.944 ;
     RECT  9.529 11.76 9.613 13.08 ;
     RECT  8.417 3.936 9.673 4.68 ;
     RECT  9.673 3.408 9.685 4.68 ;
     RECT  8.237 5.76 9.685 5.784 ;
     RECT  9.565 6.864 9.973 7.944 ;
     RECT  9.685 3.408 9.997 5.784 ;
     RECT  9.973 6.864 9.997 8.184 ;
     RECT  9.997 3.408 10.508 8.184 ;
     RECT  9.299 10.32 10.508 10.728 ;
     RECT  9.613 11.76 10.508 12.972 ;
     RECT  10.508 2.148 10.612 12.972 ;
     RECT  10.612 2.418 10.804 12.702 ;
     RECT  10.804 3.936 10.937 6.072 ;
     RECT  10.937 5.04 11.009 6.072 ;
     RECT  11.009 5.76 11.117 6.072 ;
     RECT  10.804 7.344 11.117 7.416 ;
     RECT  10.804 10.32 11.945 10.728 ;
     RECT  11.945 10.32 12.017 10.44 ;
     RECT  10.804 11.952 12.085 11.976 ;
     RECT  12.017 10.32 12.197 10.344 ;
     RECT  11.117 7.344 12.265 7.368 ;
     RECT  12.265 7.344 12.445 7.464 ;
     RECT  12.013 8.784 12.481 8.808 ;
     RECT  12.481 8.688 12.553 8.808 ;
     RECT  11.117 5.76 12.557 5.784 ;
     RECT  12.445 7.248 12.625 7.464 ;
     RECT  12.625 7.152 12.697 7.464 ;
     RECT  12.697 7.152 13.561 7.656 ;
     RECT  12.553 8.688 13.561 10.152 ;
     RECT  12.085 11.76 13.561 11.976 ;
     RECT  13.561 7.152 14.245 11.976 ;
     RECT  14.245 6.864 15.084 11.976 ;
    LAYER M5 ;
     RECT  2.4 2.137 2.52 2.151 ;
     RECT  5.1 2.137 5.22 2.151 ;
     RECT  7.8 2.137 7.92 2.151 ;
     RECT  10.5 2.137 10.62 2.151 ;
     RECT  5.1 2.151 5.412 2.869 ;
     RECT  0.144 2.869 0.168 3.059 ;
     RECT  10.5 2.151 10.812 3.397 ;
     RECT  5.1 2.869 6.312 4.115 ;
     RECT  0.144 4.213 0.168 4.499 ;
     RECT  5.1 4.115 5.544 5.219 ;
     RECT  9.696 3.397 10.812 5.507 ;
     RECT  7.8 2.151 8.112 5.749 ;
     RECT  7.632 5.749 8.112 6.805 ;
     RECT  10.5 5.507 10.812 6.853 ;
     RECT  0.144 7.141 0.168 7.427 ;
     RECT  2.4 2.151 2.712 7.717 ;
     RECT  7.632 6.805 8.232 7.717 ;
     RECT  5.1 5.219 5.412 7.765 ;
     RECT  2.304 7.717 2.712 7.861 ;
     RECT  9.984 6.853 10.812 7.909 ;
     RECT  2.304 7.861 2.808 8.003 ;
     RECT  9.456 7.909 10.812 8.195 ;
     RECT  7.584 7.717 8.232 8.485 ;
     RECT  9.456 8.195 9.48 8.485 ;
     RECT  4.56 7.765 5.412 8.579 ;
     RECT  7.584 8.485 9.48 10.069 ;
     RECT  6.864 10.069 9.48 10.595 ;
     RECT  2.304 8.003 2.712 10.931 ;
     RECT  6.864 10.595 8.112 11.459 ;
     RECT  9.264 10.595 9.48 12.611 ;
     RECT  2.4 10.931 2.712 12.969 ;
     RECT  5.1 8.579 5.412 12.969 ;
     RECT  7.8 11.459 8.112 12.969 ;
     RECT  10.5 8.195 10.812 12.969 ;
     RECT  2.4 12.969 2.52 12.983 ;
     RECT  5.1 12.969 5.22 12.983 ;
     RECT  7.8 12.969 7.92 12.983 ;
     RECT  10.5 12.969 10.62 12.983 ;
     RECT  9.456 12.611 9.48 13.045 ;
     RECT  9.456 13.045 9.576 15.056 ;
  END
END dsfd_rly_54_EW

VERSION 5.8 ;
BUSBITCHARS "[]" ;
DIVIDERCHAR "/" ;
UNITS
    DATABASE MICRONS 1000 ;
END UNITS

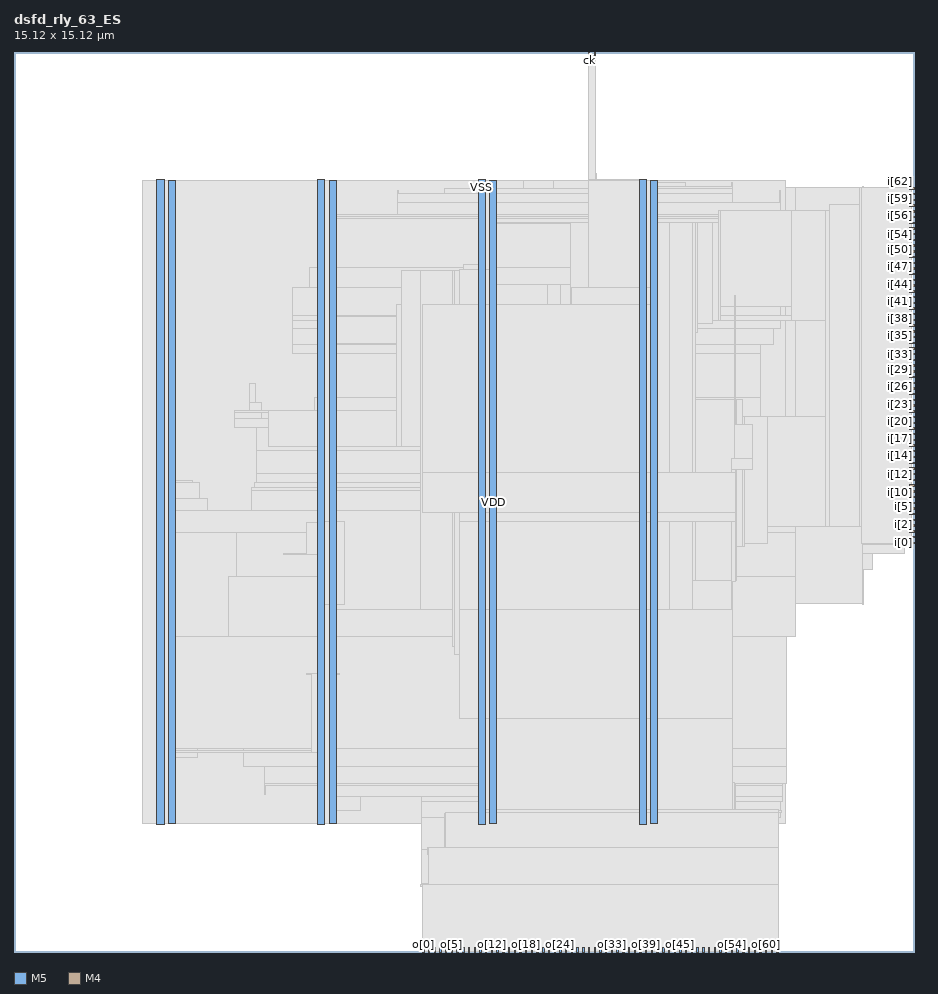
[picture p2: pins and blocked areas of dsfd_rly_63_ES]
MACRO dsfd_rly_63_ES
  FOREIGN dsfd_rly_63_ES 0 0 ;
  CLASS BLOCK ;
  SIZE 15.12 BY 15.12 ;
  PIN ck
    DIRECTION INPUT ;
    USE SIGNAL ;
    PORT
      LAYER M5 ;
        RECT  9.648 15.036 9.672 15.12 ;
    END
  END ck
  PIN i[0]
    DIRECTION INPUT ;
    USE SIGNAL ;
    PORT
      LAYER M4 ;
        RECT  15.036 6.864 15.12 6.888 ;
    END
  END i[0]
  PIN i[10]
    DIRECTION INPUT ;
    USE SIGNAL ;
    PORT
      LAYER M4 ;
        RECT  15.036 7.824 15.12 7.848 ;
    END
  END i[10]
  PIN i[11]
    DIRECTION INPUT ;
    USE SIGNAL ;
    PORT
      LAYER M4 ;
        RECT  15.036 7.92 15.12 7.944 ;
    END
  END i[11]
  PIN i[12]
    DIRECTION INPUT ;
    USE SIGNAL ;
    PORT
      LAYER M4 ;
        RECT  15.036 8.016 15.12 8.04 ;
    END
  END i[12]
  PIN i[13]
    DIRECTION INPUT ;
    USE SIGNAL ;
    PORT
      LAYER M4 ;
        RECT  15.036 8.112 15.12 8.136 ;
    END
  END i[13]
  PIN i[14]
    DIRECTION INPUT ;
    USE SIGNAL ;
    PORT
      LAYER M4 ;
        RECT  15.036 8.208 15.12 8.232 ;
    END
  END i[14]
  PIN i[15]
    DIRECTION INPUT ;
    USE SIGNAL ;
    PORT
      LAYER M4 ;
        RECT  15.036 8.304 15.12 8.328 ;
    END
  END i[15]
  PIN i[16]
    DIRECTION INPUT ;
    USE SIGNAL ;
    PORT
      LAYER M4 ;
        RECT  15.036 8.4 15.12 8.424 ;
    END
  END i[16]
  PIN i[17]
    DIRECTION INPUT ;
    USE SIGNAL ;
    PORT
      LAYER M4 ;
        RECT  15.036 8.496 15.12 8.52 ;
    END
  END i[17]
  PIN i[18]
    DIRECTION INPUT ;
    USE SIGNAL ;
    PORT
      LAYER M4 ;
        RECT  15.036 8.592 15.12 8.616 ;
    END
  END i[18]
  PIN i[19]
    DIRECTION INPUT ;
    USE SIGNAL ;
    PORT
      LAYER M4 ;
        RECT  15.036 8.688 15.12 8.712 ;
    END
  END i[19]
  PIN i[1]
    DIRECTION INPUT ;
    USE SIGNAL ;
    PORT
      LAYER M4 ;
        RECT  15.036 6.96 15.12 6.984 ;
    END
  END i[1]
  PIN i[20]
    DIRECTION INPUT ;
    USE SIGNAL ;
    PORT
      LAYER M4 ;
        RECT  15.036 8.784 15.12 8.808 ;
    END
  END i[20]
  PIN i[21]
    DIRECTION INPUT ;
    USE SIGNAL ;
    PORT
      LAYER M4 ;
        RECT  15.036 8.88 15.12 8.904 ;
    END
  END i[21]
  PIN i[22]
    DIRECTION INPUT ;
    USE SIGNAL ;
    PORT
      LAYER M4 ;
        RECT  15.036 8.976 15.12 9 ;
    END
  END i[22]
  PIN i[23]
    DIRECTION INPUT ;
    USE SIGNAL ;
    PORT
      LAYER M4 ;
        RECT  15.036 9.072 15.12 9.096 ;
    END
  END i[23]
  PIN i[24]
    DIRECTION INPUT ;
    USE SIGNAL ;
    PORT
      LAYER M4 ;
        RECT  15.036 9.168 15.12 9.192 ;
    END
  END i[24]
  PIN i[25]
    DIRECTION INPUT ;
    USE SIGNAL ;
    PORT
      LAYER M4 ;
        RECT  15.036 9.264 15.12 9.288 ;
    END
  END i[25]
  PIN i[26]
    DIRECTION INPUT ;
    USE SIGNAL ;
    PORT
      LAYER M4 ;
        RECT  15.036 9.36 15.12 9.384 ;
    END
  END i[26]
  PIN i[27]
    DIRECTION INPUT ;
    USE SIGNAL ;
    PORT
      LAYER M4 ;
        RECT  15.036 9.456 15.12 9.48 ;
    END
  END i[27]
  PIN i[28]
    DIRECTION INPUT ;
    USE SIGNAL ;
    PORT
      LAYER M4 ;
        RECT  15.036 9.552 15.12 9.576 ;
    END
  END i[28]
  PIN i[29]
    DIRECTION INPUT ;
    USE SIGNAL ;
    PORT
      LAYER M4 ;
        RECT  15.036 9.648 15.12 9.672 ;
    END
  END i[29]
  PIN i[2]
    DIRECTION INPUT ;
    USE SIGNAL ;
    PORT
      LAYER M4 ;
        RECT  15.036 7.056 15.12 7.08 ;
    END
  END i[2]
  PIN i[30]
    DIRECTION INPUT ;
    USE SIGNAL ;
    PORT
      LAYER M4 ;
        RECT  15.036 9.744 15.12 9.768 ;
    END
  END i[30]
  PIN i[31]
    DIRECTION INPUT ;
    USE SIGNAL ;
    PORT
      LAYER M4 ;
        RECT  15.036 9.84 15.12 9.864 ;
    END
  END i[31]
  PIN i[32]
    DIRECTION INPUT ;
    USE SIGNAL ;
    PORT
      LAYER M4 ;
        RECT  15.036 9.936 15.12 9.96 ;
    END
  END i[32]
  PIN i[33]
    DIRECTION INPUT ;
    USE SIGNAL ;
    PORT
      LAYER M4 ;
        RECT  15.036 10.032 15.12 10.056 ;
    END
  END i[33]
  PIN i[34]
    DIRECTION INPUT ;
    USE SIGNAL ;
    PORT
      LAYER M4 ;
        RECT  15.036 10.128 15.12 10.152 ;
    END
  END i[34]
  PIN i[35]
    DIRECTION INPUT ;
    USE SIGNAL ;
    PORT
      LAYER M4 ;
        RECT  15.036 10.224 15.12 10.248 ;
    END
  END i[35]
  PIN i[36]
    DIRECTION INPUT ;
    USE SIGNAL ;
    PORT
      LAYER M4 ;
        RECT  15.036 10.32 15.12 10.344 ;
    END
  END i[36]
  PIN i[37]
    DIRECTION INPUT ;
    USE SIGNAL ;
    PORT
      LAYER M4 ;
        RECT  15.036 10.416 15.12 10.44 ;
    END
  END i[37]
  PIN i[38]
    DIRECTION INPUT ;
    USE SIGNAL ;
    PORT
      LAYER M4 ;
        RECT  15.036 10.512 15.12 10.536 ;
    END
  END i[38]
  PIN i[39]
    DIRECTION INPUT ;
    USE SIGNAL ;
    PORT
      LAYER M4 ;
        RECT  15.036 10.608 15.12 10.632 ;
    END
  END i[39]
  PIN i[3]
    DIRECTION INPUT ;
    USE SIGNAL ;
    PORT
      LAYER M4 ;
        RECT  15.036 7.152 15.12 7.176 ;
    END
  END i[3]
  PIN i[40]
    DIRECTION INPUT ;
    USE SIGNAL ;
    PORT
      LAYER M4 ;
        RECT  15.036 10.704 15.12 10.728 ;
    END
  END i[40]
  PIN i[41]
    DIRECTION INPUT ;
    USE SIGNAL ;
    PORT
      LAYER M4 ;
        RECT  15.036 10.8 15.12 10.824 ;
    END
  END i[41]
  PIN i[42]
    DIRECTION INPUT ;
    USE SIGNAL ;
    PORT
      LAYER M4 ;
        RECT  15.036 10.896 15.12 10.92 ;
    END
  END i[42]
  PIN i[43]
    DIRECTION INPUT ;
    USE SIGNAL ;
    PORT
      LAYER M4 ;
        RECT  15.036 10.992 15.12 11.016 ;
    END
  END i[43]
  PIN i[44]
    DIRECTION INPUT ;
    USE SIGNAL ;
    PORT
      LAYER M4 ;
        RECT  15.036 11.088 15.12 11.112 ;
    END
  END i[44]
  PIN i[45]
    DIRECTION INPUT ;
    USE SIGNAL ;
    PORT
      LAYER M4 ;
        RECT  15.036 11.184 15.12 11.208 ;
    END
  END i[45]
  PIN i[46]
    DIRECTION INPUT ;
    USE SIGNAL ;
    PORT
      LAYER M4 ;
        RECT  15.036 11.28 15.12 11.304 ;
    END
  END i[46]
  PIN i[47]
    DIRECTION INPUT ;
    USE SIGNAL ;
    PORT
      LAYER M4 ;
        RECT  15.036 11.376 15.12 11.4 ;
    END
  END i[47]
  PIN i[48]
    DIRECTION INPUT ;
    USE SIGNAL ;
    PORT
      LAYER M4 ;
        RECT  15.036 11.472 15.12 11.496 ;
    END
  END i[48]
  PIN i[49]
    DIRECTION INPUT ;
    USE SIGNAL ;
    PORT
      LAYER M4 ;
        RECT  15.036 11.568 15.12 11.592 ;
    END
  END i[49]
  PIN i[4]
    DIRECTION INPUT ;
    USE SIGNAL ;
    PORT
      LAYER M4 ;
        RECT  15.036 7.248 15.12 7.272 ;
    END
  END i[4]
  PIN i[50]
    DIRECTION INPUT ;
    USE SIGNAL ;
    PORT
      LAYER M4 ;
        RECT  15.036 11.664 15.12 11.688 ;
    END
  END i[50]
  PIN i[51]
    DIRECTION INPUT ;
    USE SIGNAL ;
    PORT
      LAYER M4 ;
        RECT  15.036 11.76 15.12 11.784 ;
    END
  END i[51]
  PIN i[52]
    DIRECTION INPUT ;
    USE SIGNAL ;
    PORT
      LAYER M4 ;
        RECT  15.036 11.856 15.12 11.88 ;
    END
  END i[52]
  PIN i[53]
    DIRECTION INPUT ;
    USE SIGNAL ;
    PORT
      LAYER M4 ;
        RECT  15.036 11.952 15.12 11.976 ;
    END
  END i[53]
  PIN i[54]
    DIRECTION INPUT ;
    USE SIGNAL ;
    PORT
      LAYER M4 ;
        RECT  15.036 12.048 15.12 12.072 ;
    END
  END i[54]
  PIN i[55]
    DIRECTION INPUT ;
    USE SIGNAL ;
    PORT
      LAYER M4 ;
        RECT  15.036 12.144 15.12 12.168 ;
    END
  END i[55]
  PIN i[56]
    DIRECTION INPUT ;
    USE SIGNAL ;
    PORT
      LAYER M4 ;
        RECT  15.036 12.24 15.12 12.264 ;
    END
  END i[56]
  PIN i[57]
    DIRECTION INPUT ;
    USE SIGNAL ;
    PORT
      LAYER M4 ;
        RECT  15.036 12.336 15.12 12.36 ;
    END
  END i[57]
  PIN i[58]
    DIRECTION INPUT ;
    USE SIGNAL ;
    PORT
      LAYER M4 ;
        RECT  15.036 12.432 15.12 12.456 ;
    END
  END i[58]
  PIN i[59]
    DIRECTION INPUT ;
    USE SIGNAL ;
    PORT
      LAYER M4 ;
        RECT  15.036 12.528 15.12 12.552 ;
    END
  END i[59]
  PIN i[5]
    DIRECTION INPUT ;
    USE SIGNAL ;
    PORT
      LAYER M4 ;
        RECT  15.036 7.344 15.12 7.368 ;
    END
  END i[5]
  PIN i[60]
    DIRECTION INPUT ;
    USE SIGNAL ;
    PORT
      LAYER M4 ;
        RECT  15.036 12.624 15.12 12.648 ;
    END
  END i[60]
  PIN i[61]
    DIRECTION INPUT ;
    USE SIGNAL ;
    PORT
      LAYER M4 ;
        RECT  15.036 12.72 15.12 12.744 ;
    END
  END i[61]
  PIN i[62]
    DIRECTION INPUT ;
    USE SIGNAL ;
    PORT
      LAYER M4 ;
        RECT  15.036 12.816 15.12 12.84 ;
    END
  END i[62]
  PIN i[6]
    DIRECTION INPUT ;
    USE SIGNAL ;
    PORT
      LAYER M4 ;
        RECT  15.036 7.44 15.12 7.464 ;
    END
  END i[6]
  PIN i[7]
    DIRECTION INPUT ;
    USE SIGNAL ;
    PORT
      LAYER M4 ;
        RECT  15.036 7.536 15.12 7.56 ;
    END
  END i[7]
  PIN i[8]
    DIRECTION INPUT ;
    USE SIGNAL ;
    PORT
      LAYER M4 ;
        RECT  15.036 7.632 15.12 7.656 ;
    END
  END i[8]
  PIN i[9]
    DIRECTION INPUT ;
    USE SIGNAL ;
    PORT
      LAYER M4 ;
        RECT  15.036 7.728 15.12 7.752 ;
    END
  END i[9]
  PIN o[0]
    DIRECTION OUTPUT ;
    USE SIGNAL ;
    PORT
      LAYER M5 ;
        RECT  6.864 0 6.888 0.084 ;
    END
  END o[0]
  PIN o[10]
    DIRECTION OUTPUT ;
    USE SIGNAL ;
    PORT
      LAYER M5 ;
        RECT  7.824 0 7.848 0.084 ;
    END
  END o[10]
  PIN o[11]
    DIRECTION OUTPUT ;
    USE SIGNAL ;
    PORT
      LAYER M5 ;
        RECT  7.92 0 7.944 0.084 ;
    END
  END o[11]
  PIN o[12]
    DIRECTION OUTPUT ;
    USE SIGNAL ;
    PORT
      LAYER M5 ;
        RECT  8.016 0 8.04 0.084 ;
    END
  END o[12]
  PIN o[13]
    DIRECTION OUTPUT ;
    USE SIGNAL ;
    PORT
      LAYER M5 ;
        RECT  8.112 0 8.136 0.084 ;
    END
  END o[13]
  PIN o[14]
    DIRECTION OUTPUT ;
    USE SIGNAL ;
    PORT
      LAYER M5 ;
        RECT  8.208 0 8.232 0.084 ;
    END
  END o[14]
  PIN o[15]
    DIRECTION OUTPUT ;
    USE SIGNAL ;
    PORT
      LAYER M5 ;
        RECT  8.304 0 8.328 0.084 ;
    END
  END o[15]
  PIN o[16]
    DIRECTION OUTPUT ;
    USE SIGNAL ;
    PORT
      LAYER M5 ;
        RECT  8.4 0 8.424 0.084 ;
    END
  END o[16]
  PIN o[17]
    DIRECTION OUTPUT ;
    USE SIGNAL ;
    PORT
      LAYER M5 ;
        RECT  8.496 0 8.52 0.084 ;
    END
  END o[17]
  PIN o[18]
    DIRECTION OUTPUT ;
    USE SIGNAL ;
    PORT
      LAYER M5 ;
        RECT  8.592 0 8.616 0.084 ;
    END
  END o[18]
  PIN o[19]
    DIRECTION OUTPUT ;
    USE SIGNAL ;
    PORT
      LAYER M5 ;
        RECT  8.688 0 8.712 0.084 ;
    END
  END o[19]
  PIN o[1]
    DIRECTION OUTPUT ;
    USE SIGNAL ;
    PORT
      LAYER M5 ;
        RECT  6.96 0 6.984 0.084 ;
    END
  END o[1]
  PIN o[20]
    DIRECTION OUTPUT ;
    USE SIGNAL ;
    PORT
      LAYER M5 ;
        RECT  8.784 0 8.808 0.084 ;
    END
  END o[20]
  PIN o[21]
    DIRECTION OUTPUT ;
    USE SIGNAL ;
    PORT
      LAYER M5 ;
        RECT  8.88 0 8.904 0.084 ;
    END
  END o[21]
  PIN o[22]
    DIRECTION OUTPUT ;
    USE SIGNAL ;
    PORT
      LAYER M5 ;
        RECT  8.976 0 9 0.084 ;
    END
  END o[22]
  PIN o[23]
    DIRECTION OUTPUT ;
    USE SIGNAL ;
    PORT
      LAYER M5 ;
        RECT  9.072 0 9.096 0.084 ;
    END
  END o[23]
  PIN o[24]
    DIRECTION OUTPUT ;
    USE SIGNAL ;
    PORT
      LAYER M5 ;
        RECT  9.168 0 9.192 0.084 ;
    END
  END o[24]
  PIN o[25]
    DIRECTION OUTPUT ;
    USE SIGNAL ;
    PORT
      LAYER M5 ;
        RECT  9.264 0 9.288 0.084 ;
    END
  END o[25]
  PIN o[26]
    DIRECTION OUTPUT ;
    USE SIGNAL ;
    PORT
      LAYER M5 ;
        RECT  9.36 0 9.384 0.084 ;
    END
  END o[26]
  PIN o[27]
    DIRECTION OUTPUT ;
    USE SIGNAL ;
    PORT
      LAYER M5 ;
        RECT  9.456 0 9.48 0.084 ;
    END
  END o[27]
  PIN o[28]
    DIRECTION OUTPUT ;
    USE SIGNAL ;
    PORT
      LAYER M5 ;
        RECT  9.552 0 9.576 0.084 ;
    END
  END o[28]
  PIN o[29]
    DIRECTION OUTPUT ;
    USE SIGNAL ;
    PORT
      LAYER M5 ;
        RECT  9.648 0 9.672 0.084 ;
    END
  END o[29]
  PIN o[2]
    DIRECTION OUTPUT ;
    USE SIGNAL ;
    PORT
      LAYER M5 ;
        RECT  7.056 0 7.08 0.084 ;
    END
  END o[2]
  PIN o[30]
    DIRECTION OUTPUT ;
    USE SIGNAL ;
    PORT
      LAYER M5 ;
        RECT  9.744 0 9.768 0.084 ;
    END
  END o[30]
  PIN o[31]
    DIRECTION OUTPUT ;
    USE SIGNAL ;
    PORT
      LAYER M5 ;
        RECT  9.84 0 9.864 0.084 ;
    END
  END o[31]
  PIN o[32]
    DIRECTION OUTPUT ;
    USE SIGNAL ;
    PORT
      LAYER M5 ;
        RECT  9.936 0 9.96 0.084 ;
    END
  END o[32]
  PIN o[33]
    DIRECTION OUTPUT ;
    USE SIGNAL ;
    PORT
      LAYER M5 ;
        RECT  10.032 0 10.056 0.084 ;
    END
  END o[33]
  PIN o[34]
    DIRECTION OUTPUT ;
    USE SIGNAL ;
    PORT
      LAYER M5 ;
        RECT  10.128 0 10.152 0.084 ;
    END
  END o[34]
  PIN o[35]
    DIRECTION OUTPUT ;
    USE SIGNAL ;
    PORT
      LAYER M5 ;
        RECT  10.224 0 10.248 0.084 ;
    END
  END o[35]
  PIN o[36]
    DIRECTION OUTPUT ;
    USE SIGNAL ;
    PORT
      LAYER M5 ;
        RECT  10.32 0 10.344 0.084 ;
    END
  END o[36]
  PIN o[37]
    DIRECTION OUTPUT ;
    USE SIGNAL ;
    PORT
      LAYER M5 ;
        RECT  10.416 0 10.44 0.084 ;
    END
  END o[37]
  PIN o[38]
    DIRECTION OUTPUT ;
    USE SIGNAL ;
    PORT
      LAYER M5 ;
        RECT  10.512 0 10.536 0.084 ;
    END
  END o[38]
  PIN o[39]
    DIRECTION OUTPUT ;
    USE SIGNAL ;
    PORT
      LAYER M5 ;
        RECT  10.608 0 10.632 0.084 ;
    END
  END o[39]
  PIN o[3]
    DIRECTION OUTPUT ;
    USE SIGNAL ;
    PORT
      LAYER M5 ;
        RECT  7.152 0 7.176 0.084 ;
    END
  END o[3]
  PIN o[40]
    DIRECTION OUTPUT ;
    USE SIGNAL ;
    PORT
      LAYER M5 ;
        RECT  10.704 0 10.728 0.084 ;
    END
  END o[40]
  PIN o[41]
    DIRECTION OUTPUT ;
    USE SIGNAL ;
    PORT
      LAYER M5 ;
        RECT  10.8 0 10.824 0.084 ;
    END
  END o[41]
  PIN o[42]
    DIRECTION OUTPUT ;
    USE SIGNAL ;
    PORT
      LAYER M5 ;
        RECT  10.896 0 10.92 0.084 ;
    END
  END o[42]
  PIN o[43]
    DIRECTION OUTPUT ;
    USE SIGNAL ;
    PORT
      LAYER M5 ;
        RECT  10.992 0 11.016 0.084 ;
    END
  END o[43]
  PIN o[44]
    DIRECTION OUTPUT ;
    USE SIGNAL ;
    PORT
      LAYER M5 ;
        RECT  11.088 0 11.112 0.084 ;
    END
  END o[44]
  PIN o[45]
    DIRECTION OUTPUT ;
    USE SIGNAL ;
    PORT
      LAYER M5 ;
        RECT  11.184 0 11.208 0.084 ;
    END
  END o[45]
  PIN o[46]
    DIRECTION OUTPUT ;
    USE SIGNAL ;
    PORT
      LAYER M5 ;
        RECT  11.28 0 11.304 0.084 ;
    END
  END o[46]
  PIN o[47]
    DIRECTION OUTPUT ;
    USE SIGNAL ;
    PORT
      LAYER M5 ;
        RECT  11.376 0 11.4 0.084 ;
    END
  END o[47]
  PIN o[48]
    DIRECTION OUTPUT ;
    USE SIGNAL ;
    PORT
      LAYER M5 ;
        RECT  11.472 0 11.496 0.084 ;
    END
  END o[48]
  PIN o[49]
    DIRECTION OUTPUT ;
    USE SIGNAL ;
    PORT
      LAYER M5 ;
        RECT  11.568 0 11.592 0.084 ;
    END
  END o[49]
  PIN o[4]
    DIRECTION OUTPUT ;
    USE SIGNAL ;
    PORT
      LAYER M5 ;
        RECT  7.248 0 7.272 0.084 ;
    END
  END o[4]
  PIN o[50]
    DIRECTION OUTPUT ;
    USE SIGNAL ;
    PORT
      LAYER M5 ;
        RECT  11.664 0 11.688 0.084 ;
    END
  END o[50]
  PIN o[51]
    DIRECTION OUTPUT ;
    USE SIGNAL ;
    PORT
      LAYER M5 ;
        RECT  11.76 0 11.784 0.084 ;
    END
  END o[51]
  PIN o[52]
    DIRECTION OUTPUT ;
    USE SIGNAL ;
    PORT
      LAYER M5 ;
        RECT  11.856 0 11.88 0.084 ;
    END
  END o[52]
  PIN o[53]
    DIRECTION OUTPUT ;
    USE SIGNAL ;
    PORT
      LAYER M5 ;
        RECT  11.952 0 11.976 0.084 ;
    END
  END o[53]
  PIN o[54]
    DIRECTION OUTPUT ;
    USE SIGNAL ;
    PORT
      LAYER M5 ;
        RECT  12.048 0 12.072 0.084 ;
    END
  END o[54]
  PIN o[55]
    DIRECTION OUTPUT ;
    USE SIGNAL ;
    PORT
      LAYER M5 ;
        RECT  12.144 0 12.168 0.084 ;
    END
  END o[55]
  PIN o[56]
    DIRECTION OUTPUT ;
    USE SIGNAL ;
    PORT
      LAYER M5 ;
        RECT  12.24 0 12.264 0.084 ;
    END
  END o[56]
  PIN o[57]
    DIRECTION OUTPUT ;
    USE SIGNAL ;
    PORT
      LAYER M5 ;
        RECT  12.336 0 12.36 0.084 ;
    END
  END o[57]
  PIN o[58]
    DIRECTION OUTPUT ;
    USE SIGNAL ;
    PORT
      LAYER M5 ;
        RECT  12.432 0 12.456 0.084 ;
    END
  END o[58]
  PIN o[59]
    DIRECTION OUTPUT ;
    USE SIGNAL ;
    PORT
      LAYER M5 ;
        RECT  12.528 0 12.552 0.084 ;
    END
  END o[59]
  PIN o[5]
    DIRECTION OUTPUT ;
    USE SIGNAL ;
    PORT
      LAYER M5 ;
        RECT  7.344 0 7.368 0.084 ;
    END
  END o[5]
  PIN o[60]
    DIRECTION OUTPUT ;
    USE SIGNAL ;
    PORT
      LAYER M5 ;
        RECT  12.624 0 12.648 0.084 ;
    END
  END o[60]
  PIN o[61]
    DIRECTION OUTPUT ;
    USE SIGNAL ;
    PORT
      LAYER M5 ;
        RECT  12.72 0 12.744 0.084 ;
    END
  END o[61]
  PIN o[62]
    DIRECTION OUTPUT ;
    USE SIGNAL ;
    PORT
      LAYER M5 ;
        RECT  12.816 0 12.84 0.084 ;
    END
  END o[62]
  PIN o[6]
    DIRECTION OUTPUT ;
    USE SIGNAL ;
    PORT
      LAYER M5 ;
        RECT  7.44 0 7.464 0.084 ;
    END
  END o[6]
  PIN o[7]
    DIRECTION OUTPUT ;
    USE SIGNAL ;
    PORT
      LAYER M5 ;
        RECT  7.536 0 7.56 0.084 ;
    END
  END o[7]
  PIN o[8]
    DIRECTION OUTPUT ;
    USE SIGNAL ;
    PORT
      LAYER M5 ;
        RECT  7.632 0 7.656 0.084 ;
    END
  END o[8]
  PIN o[9]
    DIRECTION OUTPUT ;
    USE SIGNAL ;
    PORT
      LAYER M5 ;
        RECT  7.728 0 7.752 0.084 ;
    END
  END o[9]
  PIN rs
    DIRECTION INPUT ;
    USE SIGNAL ;
    PORT
      LAYER M5 ;
        RECT  9.744 15.036 9.768 15.12 ;
    END
  END rs
  PIN VDD
    DIRECTION INOUT ;
    USE POWER ;
    PORT
      LAYER M5 ;
        RECT  10.692 2.151 10.812 12.969 ;
        RECT  7.992 2.151 8.112 12.969 ;
        RECT  5.292 2.151 5.412 12.969 ;
        RECT  2.592 2.151 2.712 12.969 ;
    END
  END VDD
  PIN VSS
    DIRECTION INOUT ;
    USE GROUND ;
    PORT
      LAYER M5 ;
        RECT  10.5 2.137 10.62 12.983 ;
        RECT  7.8 2.137 7.92 12.983 ;
        RECT  5.1 2.137 5.22 12.983 ;
        RECT  2.4 2.137 2.52 12.983 ;
    END
  END VSS
  OBS
    LAYER RVTN ;
     RECT  2.16 2.16 12.96 2.295 ;
     RECT  2.16 2.565 12.96 2.835 ;
     RECT  2.16 3.105 12.96 3.375 ;
     RECT  2.16 3.645 12.96 3.915 ;
     RECT  2.16 4.185 12.96 4.455 ;
     RECT  2.16 4.725 12.96 4.995 ;
     RECT  2.16 5.265 12.96 5.535 ;
     RECT  2.16 5.805 12.96 6.075 ;
     RECT  2.16 6.345 12.96 6.615 ;
     RECT  2.16 6.885 12.96 7.155 ;
     RECT  2.16 7.425 12.96 7.695 ;
     RECT  2.16 7.965 12.96 8.235 ;
     RECT  2.16 8.505 12.96 8.775 ;
     RECT  2.16 9.045 12.96 9.315 ;
     RECT  2.16 9.585 12.96 9.855 ;
     RECT  2.16 10.125 12.96 10.395 ;
     RECT  2.16 10.665 12.96 10.935 ;
     RECT  2.16 11.205 12.96 11.475 ;
     RECT  2.16 11.745 12.96 12.015 ;
     RECT  2.16 12.285 12.96 12.555 ;
     RECT  2.16 12.825 12.96 12.96 ;
    LAYER RVTP ;
     RECT  2.16 2.295 12.96 2.565 ;
     RECT  2.16 2.835 12.96 3.105 ;
     RECT  2.16 3.375 12.96 3.645 ;
     RECT  2.16 3.915 12.96 4.185 ;
     RECT  2.16 4.455 12.96 4.725 ;
     RECT  2.16 4.995 12.96 5.265 ;
     RECT  2.16 5.535 12.96 5.805 ;
     RECT  2.16 6.075 12.96 6.345 ;
     RECT  2.16 6.615 12.96 6.885 ;
     RECT  2.16 7.155 12.96 7.425 ;
     RECT  2.16 7.695 12.96 7.965 ;
     RECT  2.16 8.235 12.96 8.505 ;
     RECT  2.16 8.775 12.96 9.045 ;
     RECT  2.16 9.315 12.96 9.585 ;
     RECT  2.16 9.855 12.96 10.125 ;
     RECT  2.16 10.395 12.96 10.665 ;
     RECT  2.16 10.935 12.96 11.205 ;
     RECT  2.16 11.475 12.96 11.745 ;
     RECT  2.16 12.015 12.96 12.285 ;
     RECT  2.16 12.555 12.96 12.825 ;
    LAYER M1 ;
     RECT  2.16 2.151 12.96 12.969 ;
    LAYER M2 ;
     RECT  2.16 2.151 8.563 12.969 ;
     RECT  8.563 2.106 9.059 12.969 ;
     RECT  9.059 2.151 12.96 12.969 ;
     RECT  12.96 2.844 12.983 2.862 ;
     RECT  12.96 5.31 13.127 12.852 ;
     RECT  13.127 5.85 14.279 12.852 ;
     RECT  14.279 6.426 14.315 12.546 ;
     RECT  14.315 6.426 14.351 8.874 ;
     RECT  14.315 9.63 14.351 12.348 ;
     RECT  14.351 9.63 14.387 9.918 ;
     RECT  14.351 6.426 14.423 8.838 ;
     RECT  14.423 6.696 14.459 8.838 ;
     RECT  14.459 6.696 14.963 6.876 ;
     RECT  14.387 9.864 14.963 9.918 ;
     RECT  14.459 8.046 14.999 8.064 ;
     RECT  14.963 9.864 14.999 9.882 ;
     RECT  14.351 10.98 14.999 12.348 ;
     RECT  14.963 6.858 15.035 6.876 ;
     RECT  14.459 8.82 15.035 8.838 ;
     RECT  14.999 10.98 15.035 10.998 ;
     RECT  14.999 12.33 15.035 12.348 ;
    LAYER M3 ;
     RECT  8.82 0.091 8.838 0.139 ;
     RECT  12.168 0.091 12.654 0.187 ;
     RECT  7.668 0.091 7.686 0.523 ;
     RECT  7.128 0.523 7.686 1.099 ;
     RECT  6.84 1.099 7.686 1.147 ;
     RECT  8.82 0.139 8.91 1.147 ;
     RECT  12.132 0.187 12.654 1.675 ;
     RECT  6.84 1.147 8.91 1.723 ;
     RECT  10.656 0.091 11.106 1.723 ;
     RECT  12.06 1.675 12.654 1.723 ;
     RECT  6.84 1.723 12.654 2.263 ;
     RECT  5.115 2.143 5.205 2.371 ;
     RECT  2.415 2.143 2.505 2.413 ;
     RECT  6.84 2.263 12.87 2.533 ;
     RECT  5.115 2.371 5.814 2.605 ;
     RECT  6.84 2.533 12.906 2.605 ;
     RECT  4.212 2.641 4.23 2.803 ;
     RECT  5.115 2.605 12.906 2.803 ;
     RECT  4.212 2.803 12.906 2.839 ;
     RECT  4.212 2.839 12.978 3.109 ;
     RECT  2.415 2.413 2.697 3.271 ;
     RECT  2.415 3.271 3.078 3.415 ;
     RECT  3.852 3.109 12.978 3.415 ;
     RECT  2.415 3.415 12.978 5.297 ;
     RECT  3.6 5.297 12.978 5.305 ;
     RECT  3.6 5.305 13.122 6.305 ;
     RECT  14.256 5.845 14.274 6.421 ;
     RECT  14.256 6.421 14.418 6.691 ;
     RECT  14.256 6.691 14.958 6.853 ;
     RECT  2.415 5.297 2.697 7.051 ;
     RECT  3.744 6.305 13.122 7.051 ;
     RECT  2.415 7.051 13.122 7.421 ;
     RECT  2.415 7.421 3.258 7.619 ;
     RECT  3.996 7.421 13.122 7.757 ;
     RECT  3.996 7.757 12.762 7.799 ;
     RECT  2.415 7.619 3.114 7.889 ;
     RECT  4.032 7.799 12.762 7.889 ;
     RECT  2.415 7.889 3.006 7.925 ;
     RECT  4.068 7.889 12.762 8.033 ;
     RECT  14.256 6.853 15.03 8.239 ;
     RECT  4.068 8.033 12.618 8.429 ;
     RECT  4.068 8.429 12.582 8.815 ;
     RECT  14.184 8.239 15.03 8.843 ;
     RECT  3.708 8.815 12.582 8.969 ;
     RECT  3.708 8.969 4.158 9.101 ;
     RECT  3.96 9.101 4.158 9.239 ;
     RECT  5.04 8.969 12.546 9.311 ;
     RECT  14.184 8.843 14.994 9.355 ;
     RECT  3.96 9.239 4.05 9.545 ;
     RECT  13.68 9.355 14.994 9.835 ;
     RECT  13.644 9.835 14.994 9.931 ;
     RECT  5.115 9.311 12.546 10.057 ;
     RECT  4.68 10.057 12.546 10.201 ;
     RECT  4.68 10.201 12.762 10.471 ;
     RECT  4.68 10.471 12.87 10.603 ;
     RECT  13.644 9.931 15.03 10.603 ;
     RECT  4.68 10.603 15.03 10.697 ;
     RECT  4.68 10.697 12.87 11.165 ;
     RECT  4.968 11.165 12.87 11.507 ;
     RECT  13.644 10.697 15.03 11.515 ;
     RECT  5.115 11.507 12.87 12.331 ;
     RECT  13.608 11.515 15.03 12.331 ;
     RECT  5.115 12.331 15.03 12.353 ;
     RECT  5.115 12.353 14.994 12.389 ;
     RECT  13.716 12.389 14.994 12.557 ;
     RECT  6.444 12.389 12.87 12.587 ;
     RECT  14.22 12.557 14.994 12.653 ;
     RECT  2.415 7.925 2.697 12.707 ;
     RECT  5.115 12.389 5.397 12.707 ;
     RECT  6.444 12.587 12.078 12.749 ;
     RECT  14.22 12.653 14.31 12.749 ;
     RECT  6.444 12.749 6.462 12.785 ;
     RECT  12.852 12.587 12.87 12.785 ;
     RECT  7.236 12.749 12.078 12.821 ;
     RECT  14.22 12.749 14.274 12.845 ;
     RECT  9.648 12.821 12.078 12.857 ;
     RECT  14.256 12.845 14.274 12.857 ;
     RECT  9.648 12.857 9.774 12.893 ;
     RECT  10.515 12.857 11.286 12.929 ;
     RECT  12.06 12.857 12.078 12.929 ;
     RECT  2.415 12.707 2.505 12.977 ;
     RECT  5.115 12.707 5.205 12.977 ;
     RECT  7.815 12.821 7.905 12.977 ;
     RECT  10.515 12.929 10.605 12.977 ;
     RECT  9.756 12.893 9.774 13.085 ;
    LAYER M4 ;
     RECT  2.408 2.148 2.512 12.972 ;
     RECT  2.512 2.418 2.704 12.702 ;
     RECT  3.697 9.072 4.273 9.096 ;
     RECT  4.525 6.672 4.921 6.696 ;
     RECT  2.704 3.36 4.993 3.384 ;
     RECT  4.921 4.656 4.993 4.68 ;
     RECT  4.993 3.36 5.108 4.68 ;
     RECT  4.921 6.672 5.108 7.224 ;
     RECT  4.273 8.496 5.108 9.096 ;
     RECT  5.108 2.148 5.212 12.972 ;
     RECT  5.212 2.418 5.404 12.702 ;
     RECT  5.404 4.656 5.465 4.68 ;
     RECT  5.404 8.496 6.433 9.096 ;
     RECT  5.404 10.224 6.433 10.68 ;
     RECT  6.433 8.496 6.505 10.872 ;
     RECT  5.404 5.76 6.829 7.416 ;
     RECT  6.505 8.496 6.829 11.448 ;
     RECT  6.829 1.104 6.913 1.128 ;
     RECT  6.949 1.632 7.091 1.752 ;
     RECT  7.1 0.528 7.187 0.552 ;
     RECT  7.091 1.68 7.225 1.752 ;
     RECT  6.829 5.76 7.369 11.448 ;
     RECT  7.369 5.136 7.405 11.448 ;
     RECT  7.405 4.992 7.549 11.448 ;
     RECT  7.225 1.68 7.808 2.328 ;
     RECT  7.477 3.936 7.808 3.96 ;
     RECT  7.549 4.992 7.808 11.544 ;
     RECT  7.808 1.68 7.912 12.972 ;
     RECT  7.912 1.68 8.104 12.702 ;
     RECT  8.104 1.68 8.189 2.856 ;
     RECT  8.189 1.152 8.273 2.856 ;
     RECT  7.429 0.096 8.849 0.168 ;
     RECT  8.849 0.144 8.921 0.168 ;
     RECT  8.104 5.328 8.957 11.208 ;
     RECT  8.104 3.936 9.097 4.296 ;
     RECT  8.273 1.728 9.157 2.856 ;
     RECT  8.957 5.424 9.173 11.208 ;
     RECT  9.173 5.52 9.349 11.208 ;
     RECT  8.104 12.24 9.349 12.264 ;
     RECT  9.349 5.52 9.701 12.264 ;
     RECT  9.701 5.52 9.785 13.08 ;
     RECT  9.097 3.888 10.249 4.296 ;
     RECT  9.785 5.52 10.249 12.972 ;
     RECT  10.213 0.096 10.309 0.12 ;
     RECT  9.157 1.728 10.309 2.904 ;
     RECT  10.249 3.888 10.309 12.972 ;
     RECT  10.309 1.728 10.612 12.972 ;
     RECT  10.612 1.728 10.804 12.702 ;
     RECT  10.804 5.568 11.009 12.264 ;
     RECT  10.804 3.408 11.333 4.296 ;
     RECT  11.009 5.712 11.405 12.264 ;
     RECT  11.405 6.24 11.441 12.264 ;
     RECT  11.441 10.416 11.477 12.264 ;
     RECT  11.333 3.408 11.729 3.432 ;
     RECT  11.477 10.56 11.729 12.264 ;
     RECT  11.729 10.608 11.833 12.264 ;
     RECT  11.833 10.608 11.873 12.456 ;
     RECT  10.804 1.728 11.941 2.328 ;
     RECT  10.309 0.096 12.037 0.168 ;
     RECT  11.941 1.728 12.049 2.856 ;
     RECT  12.049 1.68 12.097 2.856 ;
     RECT  12.097 1.68 12.125 2.808 ;
     RECT  11.441 6.24 12.131 9.288 ;
     RECT  12.037 0.096 12.161 0.216 ;
     RECT  12.125 1.68 12.188 2.376 ;
     RECT  12.131 6.816 12.233 9.288 ;
     RECT  12.233 6.816 12.269 9 ;
     RECT  12.188 1.104 12.275 2.376 ;
     RECT  12.275 1.152 12.377 2.376 ;
     RECT  12.377 1.344 12.629 2.376 ;
     RECT  12.161 0.096 12.665 0.12 ;
     RECT  12.269 6.864 12.665 9 ;
     RECT  12.629 2.304 12.773 2.376 ;
     RECT  12.773 2.352 12.889 2.376 ;
     RECT  11.873 10.848 13.057 12.456 ;
     RECT  12.665 7.152 13.633 9 ;
     RECT  13.057 10.608 13.633 12.456 ;
     RECT  13.633 7.152 13.705 12.456 ;
     RECT  13.705 7.152 14.209 12.552 ;
     RECT  14.209 7.152 14.245 12.84 ;
     RECT  14.245 6.864 15.084 12.84 ;
    LAYER M5 ;
     RECT  6.864 0.016 12.84 1.139 ;
     RECT  6.96 1.139 12.84 1.763 ;
     RECT  2.4 2.137 2.52 2.151 ;
     RECT  5.1 2.137 5.22 2.151 ;
     RECT  7.248 1.763 12.84 2.339 ;
     RECT  7.8 2.339 12.84 2.387 ;
     RECT  7.8 2.387 12.072 3.925 ;
     RECT  7.488 3.925 12.072 5.747 ;
     RECT  5.1 2.151 5.412 5.845 ;
     RECT  12.048 5.747 12.072 6.229 ;
     RECT  5.1 5.845 5.544 7.235 ;
     RECT  7.488 5.747 10.812 7.237 ;
     RECT  12.048 6.229 12.12 7.237 ;
     RECT  7.488 7.237 12.12 7.381 ;
     RECT  6.864 7.381 12.12 8.051 ;
     RECT  12.048 8.051 12.12 8.101 ;
     RECT  12.048 8.101 12.408 8.291 ;
     RECT  12.096 8.291 12.408 8.867 ;
     RECT  6.864 8.051 10.812 10.883 ;
     RECT  12.096 8.867 12.12 11.027 ;
     RECT  9.36 10.883 10.812 11.171 ;
     RECT  7.488 10.883 8.112 11.459 ;
     RECT  2.4 2.151 2.712 12.969 ;
     RECT  5.1 7.235 5.412 12.969 ;
     RECT  7.8 11.459 8.112 12.969 ;
     RECT  9.648 11.171 10.812 12.969 ;
     RECT  2.4 12.969 2.52 12.983 ;
     RECT  5.1 12.969 5.22 12.983 ;
     RECT  7.8 12.969 7.92 12.983 ;
     RECT  9.648 12.969 10.62 12.983 ;
     RECT  9.648 12.983 9.768 15.056 ;
  END
END dsfd_rly_63_ES

VERSION 5.8 ;
BUSBITCHARS "[]" ;
DIVIDERCHAR "/" ;
UNITS
    DATABASE MICRONS 1000 ;
END UNITS

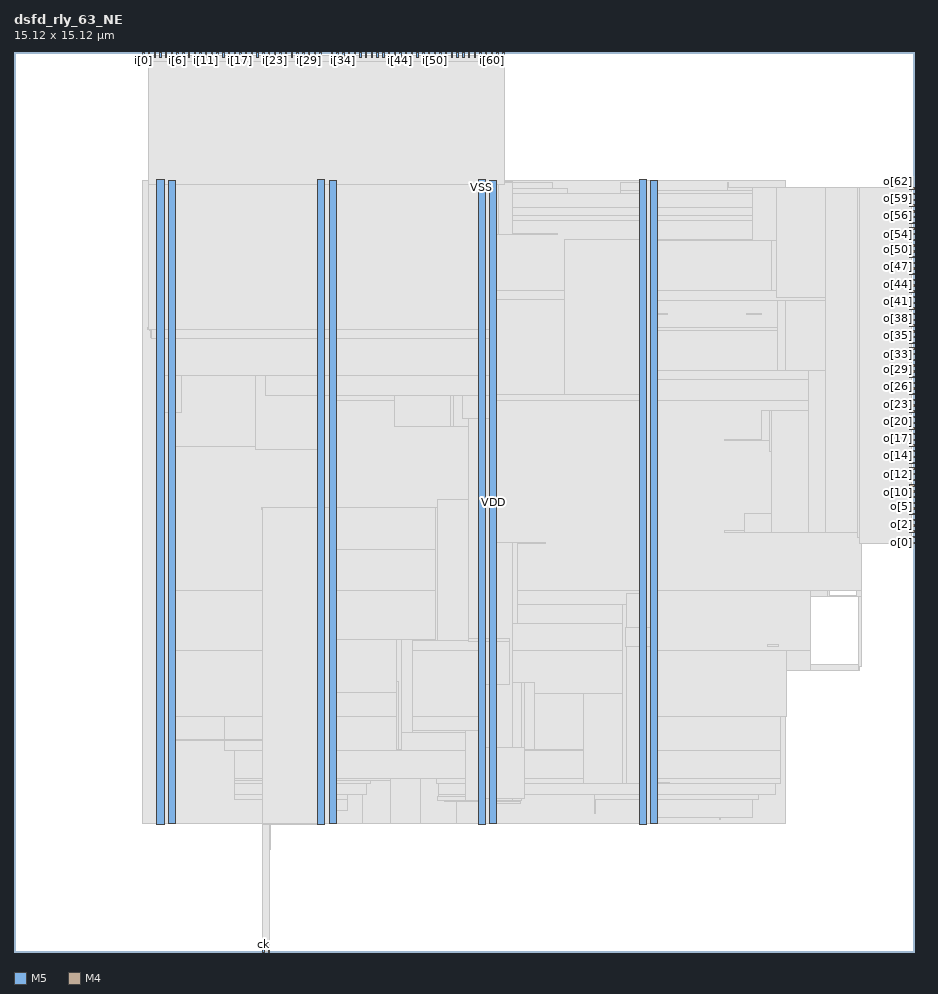
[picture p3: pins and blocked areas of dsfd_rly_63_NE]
MACRO dsfd_rly_63_NE
  FOREIGN dsfd_rly_63_NE 0 0 ;
  CLASS BLOCK ;
  SIZE 15.12 BY 15.12 ;
  PIN ck
    DIRECTION INPUT ;
    USE SIGNAL ;
    PORT
      LAYER M5 ;
        RECT  4.176 0 4.2 0.084 ;
    END
  END ck
  PIN i[0]
    DIRECTION INPUT ;
    USE SIGNAL ;
    PORT
      LAYER M5 ;
        RECT  2.16 15.036 2.184 15.12 ;
    END
  END i[0]
  PIN i[10]
    DIRECTION INPUT ;
    USE SIGNAL ;
    PORT
      LAYER M5 ;
        RECT  3.12 15.036 3.144 15.12 ;
    END
  END i[10]
  PIN i[11]
    DIRECTION INPUT ;
    USE SIGNAL ;
    PORT
      LAYER M5 ;
        RECT  3.216 15.036 3.24 15.12 ;
    END
  END i[11]
  PIN i[12]
    DIRECTION INPUT ;
    USE SIGNAL ;
    PORT
      LAYER M5 ;
        RECT  3.312 15.036 3.336 15.12 ;
    END
  END i[12]
  PIN i[13]
    DIRECTION INPUT ;
    USE SIGNAL ;
    PORT
      LAYER M5 ;
        RECT  3.408 15.036 3.432 15.12 ;
    END
  END i[13]
  PIN i[14]
    DIRECTION INPUT ;
    USE SIGNAL ;
    PORT
      LAYER M5 ;
        RECT  3.504 15.036 3.528 15.12 ;
    END
  END i[14]
  PIN i[15]
    DIRECTION INPUT ;
    USE SIGNAL ;
    PORT
      LAYER M5 ;
        RECT  3.6 15.036 3.624 15.12 ;
    END
  END i[15]
  PIN i[16]
    DIRECTION INPUT ;
    USE SIGNAL ;
    PORT
      LAYER M5 ;
        RECT  3.696 15.036 3.72 15.12 ;
    END
  END i[16]
  PIN i[17]
    DIRECTION INPUT ;
    USE SIGNAL ;
    PORT
      LAYER M5 ;
        RECT  3.792 15.036 3.816 15.12 ;
    END
  END i[17]
  PIN i[18]
    DIRECTION INPUT ;
    USE SIGNAL ;
    PORT
      LAYER M5 ;
        RECT  3.888 15.036 3.912 15.12 ;
    END
  END i[18]
  PIN i[19]
    DIRECTION INPUT ;
    USE SIGNAL ;
    PORT
      LAYER M5 ;
        RECT  3.984 15.036 4.008 15.12 ;
    END
  END i[19]
  PIN i[1]
    DIRECTION INPUT ;
    USE SIGNAL ;
    PORT
      LAYER M5 ;
        RECT  2.256 15.036 2.28 15.12 ;
    END
  END i[1]
  PIN i[20]
    DIRECTION INPUT ;
    USE SIGNAL ;
    PORT
      LAYER M5 ;
        RECT  4.08 15.036 4.104 15.12 ;
    END
  END i[20]
  PIN i[21]
    DIRECTION INPUT ;
    USE SIGNAL ;
    PORT
      LAYER M5 ;
        RECT  4.176 15.036 4.2 15.12 ;
    END
  END i[21]
  PIN i[22]
    DIRECTION INPUT ;
    USE SIGNAL ;
    PORT
      LAYER M5 ;
        RECT  4.272 15.036 4.296 15.12 ;
    END
  END i[22]
  PIN i[23]
    DIRECTION INPUT ;
    USE SIGNAL ;
    PORT
      LAYER M5 ;
        RECT  4.368 15.036 4.392 15.12 ;
    END
  END i[23]
  PIN i[24]
    DIRECTION INPUT ;
    USE SIGNAL ;
    PORT
      LAYER M5 ;
        RECT  4.464 15.036 4.488 15.12 ;
    END
  END i[24]
  PIN i[25]
    DIRECTION INPUT ;
    USE SIGNAL ;
    PORT
      LAYER M5 ;
        RECT  4.56 15.036 4.584 15.12 ;
    END
  END i[25]
  PIN i[26]
    DIRECTION INPUT ;
    USE SIGNAL ;
    PORT
      LAYER M5 ;
        RECT  4.656 15.036 4.68 15.12 ;
    END
  END i[26]
  PIN i[27]
    DIRECTION INPUT ;
    USE SIGNAL ;
    PORT
      LAYER M5 ;
        RECT  4.752 15.036 4.776 15.12 ;
    END
  END i[27]
  PIN i[28]
    DIRECTION INPUT ;
    USE SIGNAL ;
    PORT
      LAYER M5 ;
        RECT  4.848 15.036 4.872 15.12 ;
    END
  END i[28]
  PIN i[29]
    DIRECTION INPUT ;
    USE SIGNAL ;
    PORT
      LAYER M5 ;
        RECT  4.944 15.036 4.968 15.12 ;
    END
  END i[29]
  PIN i[2]
    DIRECTION INPUT ;
    USE SIGNAL ;
    PORT
      LAYER M5 ;
        RECT  2.352 15.036 2.376 15.12 ;
    END
  END i[2]
  PIN i[30]
    DIRECTION INPUT ;
    USE SIGNAL ;
    PORT
      LAYER M5 ;
        RECT  5.04 15.036 5.064 15.12 ;
    END
  END i[30]
  PIN i[31]
    DIRECTION INPUT ;
    USE SIGNAL ;
    PORT
      LAYER M5 ;
        RECT  5.136 15.036 5.16 15.12 ;
    END
  END i[31]
  PIN i[32]
    DIRECTION INPUT ;
    USE SIGNAL ;
    PORT
      LAYER M5 ;
        RECT  5.328 15.036 5.352 15.12 ;
    END
  END i[32]
  PIN i[33]
    DIRECTION INPUT ;
    USE SIGNAL ;
    PORT
      LAYER M5 ;
        RECT  5.424 15.036 5.448 15.12 ;
    END
  END i[33]
  PIN i[34]
    DIRECTION INPUT ;
    USE SIGNAL ;
    PORT
      LAYER M5 ;
        RECT  5.52 15.036 5.544 15.12 ;
    END
  END i[34]
  PIN i[35]
    DIRECTION INPUT ;
    USE SIGNAL ;
    PORT
      LAYER M5 ;
        RECT  5.616 15.036 5.64 15.12 ;
    END
  END i[35]
  PIN i[36]
    DIRECTION INPUT ;
    USE SIGNAL ;
    PORT
      LAYER M5 ;
        RECT  5.712 15.036 5.736 15.12 ;
    END
  END i[36]
  PIN i[37]
    DIRECTION INPUT ;
    USE SIGNAL ;
    PORT
      LAYER M5 ;
        RECT  5.808 15.036 5.832 15.12 ;
    END
  END i[37]
  PIN i[38]
    DIRECTION INPUT ;
    USE SIGNAL ;
    PORT
      LAYER M5 ;
        RECT  5.904 15.036 5.928 15.12 ;
    END
  END i[38]
  PIN i[39]
    DIRECTION INPUT ;
    USE SIGNAL ;
    PORT
      LAYER M5 ;
        RECT  6 15.036 6.024 15.12 ;
    END
  END i[39]
  PIN i[3]
    DIRECTION INPUT ;
    USE SIGNAL ;
    PORT
      LAYER M5 ;
        RECT  2.448 15.036 2.472 15.12 ;
    END
  END i[3]
  PIN i[40]
    DIRECTION INPUT ;
    USE SIGNAL ;
    PORT
      LAYER M5 ;
        RECT  6.096 15.036 6.12 15.12 ;
    END
  END i[40]
  PIN i[41]
    DIRECTION INPUT ;
    USE SIGNAL ;
    PORT
      LAYER M5 ;
        RECT  6.192 15.036 6.216 15.12 ;
    END
  END i[41]
  PIN i[42]
    DIRECTION INPUT ;
    USE SIGNAL ;
    PORT
      LAYER M5 ;
        RECT  6.288 15.036 6.312 15.12 ;
    END
  END i[42]
  PIN i[43]
    DIRECTION INPUT ;
    USE SIGNAL ;
    PORT
      LAYER M5 ;
        RECT  6.384 15.036 6.408 15.12 ;
    END
  END i[43]
  PIN i[44]
    DIRECTION INPUT ;
    USE SIGNAL ;
    PORT
      LAYER M5 ;
        RECT  6.48 15.036 6.504 15.12 ;
    END
  END i[44]
  PIN i[45]
    DIRECTION INPUT ;
    USE SIGNAL ;
    PORT
      LAYER M5 ;
        RECT  6.576 15.036 6.6 15.12 ;
    END
  END i[45]
  PIN i[46]
    DIRECTION INPUT ;
    USE SIGNAL ;
    PORT
      LAYER M5 ;
        RECT  6.672 15.036 6.696 15.12 ;
    END
  END i[46]
  PIN i[47]
    DIRECTION INPUT ;
    USE SIGNAL ;
    PORT
      LAYER M5 ;
        RECT  6.768 15.036 6.792 15.12 ;
    END
  END i[47]
  PIN i[48]
    DIRECTION INPUT ;
    USE SIGNAL ;
    PORT
      LAYER M5 ;
        RECT  6.864 15.036 6.888 15.12 ;
    END
  END i[48]
  PIN i[49]
    DIRECTION INPUT ;
    USE SIGNAL ;
    PORT
      LAYER M5 ;
        RECT  6.96 15.036 6.984 15.12 ;
    END
  END i[49]
  PIN i[4]
    DIRECTION INPUT ;
    USE SIGNAL ;
    PORT
      LAYER M5 ;
        RECT  2.544 15.036 2.568 15.12 ;
    END
  END i[4]
  PIN i[50]
    DIRECTION INPUT ;
    USE SIGNAL ;
    PORT
      LAYER M5 ;
        RECT  7.056 15.036 7.08 15.12 ;
    END
  END i[50]
  PIN i[51]
    DIRECTION INPUT ;
    USE SIGNAL ;
    PORT
      LAYER M5 ;
        RECT  7.152 15.036 7.176 15.12 ;
    END
  END i[51]
  PIN i[52]
    DIRECTION INPUT ;
    USE SIGNAL ;
    PORT
      LAYER M5 ;
        RECT  7.248 15.036 7.272 15.12 ;
    END
  END i[52]
  PIN i[53]
    DIRECTION INPUT ;
    USE SIGNAL ;
    PORT
      LAYER M5 ;
        RECT  7.344 15.036 7.368 15.12 ;
    END
  END i[53]
  PIN i[54]
    DIRECTION INPUT ;
    USE SIGNAL ;
    PORT
      LAYER M5 ;
        RECT  7.44 15.036 7.464 15.12 ;
    END
  END i[54]
  PIN i[55]
    DIRECTION INPUT ;
    USE SIGNAL ;
    PORT
      LAYER M5 ;
        RECT  7.536 15.036 7.56 15.12 ;
    END
  END i[55]
  PIN i[56]
    DIRECTION INPUT ;
    USE SIGNAL ;
    PORT
      LAYER M5 ;
        RECT  7.632 15.036 7.656 15.12 ;
    END
  END i[56]
  PIN i[57]
    DIRECTION INPUT ;
    USE SIGNAL ;
    PORT
      LAYER M5 ;
        RECT  7.728 15.036 7.752 15.12 ;
    END
  END i[57]
  PIN i[58]
    DIRECTION INPUT ;
    USE SIGNAL ;
    PORT
      LAYER M5 ;
        RECT  7.824 15.036 7.848 15.12 ;
    END
  END i[58]
  PIN i[59]
    DIRECTION INPUT ;
    USE SIGNAL ;
    PORT
      LAYER M5 ;
        RECT  7.92 15.036 7.944 15.12 ;
    END
  END i[59]
  PIN i[5]
    DIRECTION INPUT ;
    USE SIGNAL ;
    PORT
      LAYER M5 ;
        RECT  2.64 15.036 2.664 15.12 ;
    END
  END i[5]
  PIN i[60]
    DIRECTION INPUT ;
    USE SIGNAL ;
    PORT
      LAYER M5 ;
        RECT  8.016 15.036 8.04 15.12 ;
    END
  END i[60]
  PIN i[61]
    DIRECTION INPUT ;
    USE SIGNAL ;
    PORT
      LAYER M5 ;
        RECT  8.112 15.036 8.136 15.12 ;
    END
  END i[61]
  PIN i[62]
    DIRECTION INPUT ;
    USE SIGNAL ;
    PORT
      LAYER M5 ;
        RECT  8.208 15.036 8.232 15.12 ;
    END
  END i[62]
  PIN i[6]
    DIRECTION INPUT ;
    USE SIGNAL ;
    PORT
      LAYER M5 ;
        RECT  2.736 15.036 2.76 15.12 ;
    END
  END i[6]
  PIN i[7]
    DIRECTION INPUT ;
    USE SIGNAL ;
    PORT
      LAYER M5 ;
        RECT  2.832 15.036 2.856 15.12 ;
    END
  END i[7]
  PIN i[8]
    DIRECTION INPUT ;
    USE SIGNAL ;
    PORT
      LAYER M5 ;
        RECT  2.928 15.036 2.952 15.12 ;
    END
  END i[8]
  PIN i[9]
    DIRECTION INPUT ;
    USE SIGNAL ;
    PORT
      LAYER M5 ;
        RECT  3.024 15.036 3.048 15.12 ;
    END
  END i[9]
  PIN o[0]
    DIRECTION OUTPUT ;
    USE SIGNAL ;
    PORT
      LAYER M4 ;
        RECT  15.036 6.864 15.12 6.888 ;
    END
  END o[0]
  PIN o[10]
    DIRECTION OUTPUT ;
    USE SIGNAL ;
    PORT
      LAYER M4 ;
        RECT  15.036 7.824 15.12 7.848 ;
    END
  END o[10]
  PIN o[11]
    DIRECTION OUTPUT ;
    USE SIGNAL ;
    PORT
      LAYER M4 ;
        RECT  15.036 7.92 15.12 7.944 ;
    END
  END o[11]
  PIN o[12]
    DIRECTION OUTPUT ;
    USE SIGNAL ;
    PORT
      LAYER M4 ;
        RECT  15.036 8.016 15.12 8.04 ;
    END
  END o[12]
  PIN o[13]
    DIRECTION OUTPUT ;
    USE SIGNAL ;
    PORT
      LAYER M4 ;
        RECT  15.036 8.112 15.12 8.136 ;
    END
  END o[13]
  PIN o[14]
    DIRECTION OUTPUT ;
    USE SIGNAL ;
    PORT
      LAYER M4 ;
        RECT  15.036 8.208 15.12 8.232 ;
    END
  END o[14]
  PIN o[15]
    DIRECTION OUTPUT ;
    USE SIGNAL ;
    PORT
      LAYER M4 ;
        RECT  15.036 8.304 15.12 8.328 ;
    END
  END o[15]
  PIN o[16]
    DIRECTION OUTPUT ;
    USE SIGNAL ;
    PORT
      LAYER M4 ;
        RECT  15.036 8.4 15.12 8.424 ;
    END
  END o[16]
  PIN o[17]
    DIRECTION OUTPUT ;
    USE SIGNAL ;
    PORT
      LAYER M4 ;
        RECT  15.036 8.496 15.12 8.52 ;
    END
  END o[17]
  PIN o[18]
    DIRECTION OUTPUT ;
    USE SIGNAL ;
    PORT
      LAYER M4 ;
        RECT  15.036 8.592 15.12 8.616 ;
    END
  END o[18]
  PIN o[19]
    DIRECTION OUTPUT ;
    USE SIGNAL ;
    PORT
      LAYER M4 ;
        RECT  15.036 8.688 15.12 8.712 ;
    END
  END o[19]
  PIN o[1]
    DIRECTION OUTPUT ;
    USE SIGNAL ;
    PORT
      LAYER M4 ;
        RECT  15.036 6.96 15.12 6.984 ;
    END
  END o[1]
  PIN o[20]
    DIRECTION OUTPUT ;
    USE SIGNAL ;
    PORT
      LAYER M4 ;
        RECT  15.036 8.784 15.12 8.808 ;
    END
  END o[20]
  PIN o[21]
    DIRECTION OUTPUT ;
    USE SIGNAL ;
    PORT
      LAYER M4 ;
        RECT  15.036 8.88 15.12 8.904 ;
    END
  END o[21]
  PIN o[22]
    DIRECTION OUTPUT ;
    USE SIGNAL ;
    PORT
      LAYER M4 ;
        RECT  15.036 8.976 15.12 9 ;
    END
  END o[22]
  PIN o[23]
    DIRECTION OUTPUT ;
    USE SIGNAL ;
    PORT
      LAYER M4 ;
        RECT  15.036 9.072 15.12 9.096 ;
    END
  END o[23]
  PIN o[24]
    DIRECTION OUTPUT ;
    USE SIGNAL ;
    PORT
      LAYER M4 ;
        RECT  15.036 9.168 15.12 9.192 ;
    END
  END o[24]
  PIN o[25]
    DIRECTION OUTPUT ;
    USE SIGNAL ;
    PORT
      LAYER M4 ;
        RECT  15.036 9.264 15.12 9.288 ;
    END
  END o[25]
  PIN o[26]
    DIRECTION OUTPUT ;
    USE SIGNAL ;
    PORT
      LAYER M4 ;
        RECT  15.036 9.36 15.12 9.384 ;
    END
  END o[26]
  PIN o[27]
    DIRECTION OUTPUT ;
    USE SIGNAL ;
    PORT
      LAYER M4 ;
        RECT  15.036 9.456 15.12 9.48 ;
    END
  END o[27]
  PIN o[28]
    DIRECTION OUTPUT ;
    USE SIGNAL ;
    PORT
      LAYER M4 ;
        RECT  15.036 9.552 15.12 9.576 ;
    END
  END o[28]
  PIN o[29]
    DIRECTION OUTPUT ;
    USE SIGNAL ;
    PORT
      LAYER M4 ;
        RECT  15.036 9.648 15.12 9.672 ;
    END
  END o[29]
  PIN o[2]
    DIRECTION OUTPUT ;
    USE SIGNAL ;
    PORT
      LAYER M4 ;
        RECT  15.036 7.056 15.12 7.08 ;
    END
  END o[2]
  PIN o[30]
    DIRECTION OUTPUT ;
    USE SIGNAL ;
    PORT
      LAYER M4 ;
        RECT  15.036 9.744 15.12 9.768 ;
    END
  END o[30]
  PIN o[31]
    DIRECTION OUTPUT ;
    USE SIGNAL ;
    PORT
      LAYER M4 ;
        RECT  15.036 9.84 15.12 9.864 ;
    END
  END o[31]
  PIN o[32]
    DIRECTION OUTPUT ;
    USE SIGNAL ;
    PORT
      LAYER M4 ;
        RECT  15.036 9.936 15.12 9.96 ;
    END
  END o[32]
  PIN o[33]
    DIRECTION OUTPUT ;
    USE SIGNAL ;
    PORT
      LAYER M4 ;
        RECT  15.036 10.032 15.12 10.056 ;
    END
  END o[33]
  PIN o[34]
    DIRECTION OUTPUT ;
    USE SIGNAL ;
    PORT
      LAYER M4 ;
        RECT  15.036 10.128 15.12 10.152 ;
    END
  END o[34]
  PIN o[35]
    DIRECTION OUTPUT ;
    USE SIGNAL ;
    PORT
      LAYER M4 ;
        RECT  15.036 10.224 15.12 10.248 ;
    END
  END o[35]
  PIN o[36]
    DIRECTION OUTPUT ;
    USE SIGNAL ;
    PORT
      LAYER M4 ;
        RECT  15.036 10.32 15.12 10.344 ;
    END
  END o[36]
  PIN o[37]
    DIRECTION OUTPUT ;
    USE SIGNAL ;
    PORT
      LAYER M4 ;
        RECT  15.036 10.416 15.12 10.44 ;
    END
  END o[37]
  PIN o[38]
    DIRECTION OUTPUT ;
    USE SIGNAL ;
    PORT
      LAYER M4 ;
        RECT  15.036 10.512 15.12 10.536 ;
    END
  END o[38]
  PIN o[39]
    DIRECTION OUTPUT ;
    USE SIGNAL ;
    PORT
      LAYER M4 ;
        RECT  15.036 10.608 15.12 10.632 ;
    END
  END o[39]
  PIN o[3]
    DIRECTION OUTPUT ;
    USE SIGNAL ;
    PORT
      LAYER M4 ;
        RECT  15.036 7.152 15.12 7.176 ;
    END
  END o[3]
  PIN o[40]
    DIRECTION OUTPUT ;
    USE SIGNAL ;
    PORT
      LAYER M4 ;
        RECT  15.036 10.704 15.12 10.728 ;
    END
  END o[40]
  PIN o[41]
    DIRECTION OUTPUT ;
    USE SIGNAL ;
    PORT
      LAYER M4 ;
        RECT  15.036 10.8 15.12 10.824 ;
    END
  END o[41]
  PIN o[42]
    DIRECTION OUTPUT ;
    USE SIGNAL ;
    PORT
      LAYER M4 ;
        RECT  15.036 10.896 15.12 10.92 ;
    END
  END o[42]
  PIN o[43]
    DIRECTION OUTPUT ;
    USE SIGNAL ;
    PORT
      LAYER M4 ;
        RECT  15.036 10.992 15.12 11.016 ;
    END
  END o[43]
  PIN o[44]
    DIRECTION OUTPUT ;
    USE SIGNAL ;
    PORT
      LAYER M4 ;
        RECT  15.036 11.088 15.12 11.112 ;
    END
  END o[44]
  PIN o[45]
    DIRECTION OUTPUT ;
    USE SIGNAL ;
    PORT
      LAYER M4 ;
        RECT  15.036 11.184 15.12 11.208 ;
    END
  END o[45]
  PIN o[46]
    DIRECTION OUTPUT ;
    USE SIGNAL ;
    PORT
      LAYER M4 ;
        RECT  15.036 11.28 15.12 11.304 ;
    END
  END o[46]
  PIN o[47]
    DIRECTION OUTPUT ;
    USE SIGNAL ;
    PORT
      LAYER M4 ;
        RECT  15.036 11.376 15.12 11.4 ;
    END
  END o[47]
  PIN o[48]
    DIRECTION OUTPUT ;
    USE SIGNAL ;
    PORT
      LAYER M4 ;
        RECT  15.036 11.472 15.12 11.496 ;
    END
  END o[48]
  PIN o[49]
    DIRECTION OUTPUT ;
    USE SIGNAL ;
    PORT
      LAYER M4 ;
        RECT  15.036 11.568 15.12 11.592 ;
    END
  END o[49]
  PIN o[4]
    DIRECTION OUTPUT ;
    USE SIGNAL ;
    PORT
      LAYER M4 ;
        RECT  15.036 7.248 15.12 7.272 ;
    END
  END o[4]
  PIN o[50]
    DIRECTION OUTPUT ;
    USE SIGNAL ;
    PORT
      LAYER M4 ;
        RECT  15.036 11.664 15.12 11.688 ;
    END
  END o[50]
  PIN o[51]
    DIRECTION OUTPUT ;
    USE SIGNAL ;
    PORT
      LAYER M4 ;
        RECT  15.036 11.76 15.12 11.784 ;
    END
  END o[51]
  PIN o[52]
    DIRECTION OUTPUT ;
    USE SIGNAL ;
    PORT
      LAYER M4 ;
        RECT  15.036 11.856 15.12 11.88 ;
    END
  END o[52]
  PIN o[53]
    DIRECTION OUTPUT ;
    USE SIGNAL ;
    PORT
      LAYER M4 ;
        RECT  15.036 11.952 15.12 11.976 ;
    END
  END o[53]
  PIN o[54]
    DIRECTION OUTPUT ;
    USE SIGNAL ;
    PORT
      LAYER M4 ;
        RECT  15.036 12.048 15.12 12.072 ;
    END
  END o[54]
  PIN o[55]
    DIRECTION OUTPUT ;
    USE SIGNAL ;
    PORT
      LAYER M4 ;
        RECT  15.036 12.144 15.12 12.168 ;
    END
  END o[55]
  PIN o[56]
    DIRECTION OUTPUT ;
    USE SIGNAL ;
    PORT
      LAYER M4 ;
        RECT  15.036 12.24 15.12 12.264 ;
    END
  END o[56]
  PIN o[57]
    DIRECTION OUTPUT ;
    USE SIGNAL ;
    PORT
      LAYER M4 ;
        RECT  15.036 12.336 15.12 12.36 ;
    END
  END o[57]
  PIN o[58]
    DIRECTION OUTPUT ;
    USE SIGNAL ;
    PORT
      LAYER M4 ;
        RECT  15.036 12.432 15.12 12.456 ;
    END
  END o[58]
  PIN o[59]
    DIRECTION OUTPUT ;
    USE SIGNAL ;
    PORT
      LAYER M4 ;
        RECT  15.036 12.528 15.12 12.552 ;
    END
  END o[59]
  PIN o[5]
    DIRECTION OUTPUT ;
    USE SIGNAL ;
    PORT
      LAYER M4 ;
        RECT  15.036 7.344 15.12 7.368 ;
    END
  END o[5]
  PIN o[60]
    DIRECTION OUTPUT ;
    USE SIGNAL ;
    PORT
      LAYER M4 ;
        RECT  15.036 12.624 15.12 12.648 ;
    END
  END o[60]
  PIN o[61]
    DIRECTION OUTPUT ;
    USE SIGNAL ;
    PORT
      LAYER M4 ;
        RECT  15.036 12.72 15.12 12.744 ;
    END
  END o[61]
  PIN o[62]
    DIRECTION OUTPUT ;
    USE SIGNAL ;
    PORT
      LAYER M4 ;
        RECT  15.036 12.816 15.12 12.84 ;
    END
  END o[62]
  PIN o[6]
    DIRECTION OUTPUT ;
    USE SIGNAL ;
    PORT
      LAYER M4 ;
        RECT  15.036 7.44 15.12 7.464 ;
    END
  END o[6]
  PIN o[7]
    DIRECTION OUTPUT ;
    USE SIGNAL ;
    PORT
      LAYER M4 ;
        RECT  15.036 7.536 15.12 7.56 ;
    END
  END o[7]
  PIN o[8]
    DIRECTION OUTPUT ;
    USE SIGNAL ;
    PORT
      LAYER M4 ;
        RECT  15.036 7.632 15.12 7.656 ;
    END
  END o[8]
  PIN o[9]
    DIRECTION OUTPUT ;
    USE SIGNAL ;
    PORT
      LAYER M4 ;
        RECT  15.036 7.728 15.12 7.752 ;
    END
  END o[9]
  PIN rs
    DIRECTION INPUT ;
    USE SIGNAL ;
    PORT
      LAYER M5 ;
        RECT  4.272 0 4.296 0.084 ;
    END
  END rs
  PIN VDD
    DIRECTION INOUT ;
    USE POWER ;
    PORT
      LAYER M5 ;
        RECT  10.692 2.151 10.812 12.969 ;
        RECT  7.992 2.151 8.112 12.969 ;
        RECT  5.292 2.151 5.412 12.969 ;
        RECT  2.592 2.151 2.712 12.969 ;
    END
  END VDD
  PIN VSS
    DIRECTION INOUT ;
    USE GROUND ;
    PORT
      LAYER M5 ;
        RECT  10.5 2.137 10.62 12.983 ;
        RECT  7.8 2.137 7.92 12.983 ;
        RECT  5.1 2.137 5.22 12.983 ;
        RECT  2.4 2.137 2.52 12.983 ;
    END
  END VSS
  OBS
    LAYER RVTN ;
     RECT  2.16 2.16 12.96 2.295 ;
     RECT  2.16 2.565 12.96 2.835 ;
     RECT  2.16 3.105 12.96 3.375 ;
     RECT  2.16 3.645 12.96 3.915 ;
     RECT  2.16 4.185 12.96 4.455 ;
     RECT  2.16 4.725 12.96 4.995 ;
     RECT  2.16 5.265 12.96 5.535 ;
     RECT  2.16 5.805 12.96 6.075 ;
     RECT  2.16 6.345 12.96 6.615 ;
     RECT  2.16 6.885 12.96 7.155 ;
     RECT  2.16 7.425 12.96 7.695 ;
     RECT  2.16 7.965 12.96 8.235 ;
     RECT  2.16 8.505 12.96 8.775 ;
     RECT  2.16 9.045 12.96 9.315 ;
     RECT  2.16 9.585 12.96 9.855 ;
     RECT  2.16 10.125 12.96 10.395 ;
     RECT  2.16 10.665 12.96 10.935 ;
     RECT  2.16 11.205 12.96 11.475 ;
     RECT  2.16 11.745 12.96 12.015 ;
     RECT  2.16 12.285 12.96 12.555 ;
     RECT  2.16 12.825 12.96 12.96 ;
    LAYER RVTP ;
     RECT  2.16 2.295 12.96 2.565 ;
     RECT  2.16 2.835 12.96 3.105 ;
     RECT  2.16 3.375 12.96 3.645 ;
     RECT  2.16 3.915 12.96 4.185 ;
     RECT  2.16 4.455 12.96 4.725 ;
     RECT  2.16 4.995 12.96 5.265 ;
     RECT  2.16 5.535 12.96 5.805 ;
     RECT  2.16 6.075 12.96 6.345 ;
     RECT  2.16 6.615 12.96 6.885 ;
     RECT  2.16 7.155 12.96 7.425 ;
     RECT  2.16 7.695 12.96 7.965 ;
     RECT  2.16 8.235 12.96 8.505 ;
     RECT  2.16 8.775 12.96 9.045 ;
     RECT  2.16 9.315 12.96 9.585 ;
     RECT  2.16 9.855 12.96 10.125 ;
     RECT  2.16 10.395 12.96 10.665 ;
     RECT  2.16 10.935 12.96 11.205 ;
     RECT  2.16 11.475 12.96 11.745 ;
     RECT  2.16 12.015 12.96 12.285 ;
     RECT  2.16 12.555 12.96 12.825 ;
    LAYER M1 ;
     RECT  2.16 2.151 12.96 12.969 ;
    LAYER M2 ;
     RECT  2.16 2.151 5.863 12.969 ;
     RECT  5.863 2.151 6.331 13.014 ;
     RECT  6.331 2.151 6.827 13.05 ;
     RECT  6.827 2.151 7.439 13.014 ;
     RECT  7.439 2.151 12.96 12.969 ;
     RECT  12.96 3.96 12.983 3.978 ;
     RECT  12.96 4.734 13.379 5.094 ;
     RECT  12.96 5.976 13.667 12.744 ;
     RECT  13.667 5.976 13.703 6.102 ;
     RECT  13.703 5.976 14.171 5.994 ;
     RECT  13.379 4.734 14.207 4.824 ;
     RECT  13.667 7.281 14.207 12.744 ;
     RECT  14.207 4.806 14.243 4.824 ;
     RECT  14.207 7.281 14.243 9.882 ;
     RECT  14.207 10.791 14.243 12.744 ;
     RECT  14.243 9.09 14.279 9.882 ;
     RECT  14.243 7.398 15.035 7.416 ;
     RECT  14.279 9.09 15.035 9.684 ;
     RECT  14.243 10.872 15.035 10.89 ;
     RECT  14.243 12.456 15.035 12.474 ;
    LAYER M3 ;
     RECT  10.515 2.143 10.605 2.263 ;
     RECT  11.844 2.227 11.862 2.263 ;
     RECT  4.284 1.723 4.302 2.299 ;
     RECT  4.284 2.299 4.338 2.335 ;
     RECT  5.115 2.143 5.205 2.335 ;
     RECT  4.284 2.335 5.205 2.371 ;
     RECT  2.415 2.143 2.505 2.413 ;
     RECT  7.815 2.143 7.905 2.413 ;
     RECT  7.815 2.413 8.097 2.497 ;
     RECT  7.815 2.497 8.514 2.533 ;
     RECT  7.236 2.533 8.514 2.539 ;
     RECT  4.284 2.371 5.598 2.569 ;
     RECT  9.756 2.335 9.774 2.569 ;
     RECT  10.515 2.263 12.402 2.569 ;
     RECT  3.708 2.569 5.598 2.641 ;
     RECT  7.128 2.539 8.514 2.641 ;
     RECT  9.756 2.569 12.51 2.641 ;
     RECT  3.708 2.641 5.922 2.839 ;
     RECT  7.128 2.641 12.798 2.839 ;
     RECT  3.708 2.839 5.994 2.875 ;
     RECT  3.708 2.875 6.318 2.911 ;
     RECT  7.092 2.839 12.87 2.911 ;
     RECT  3.708 2.911 12.87 3.379 ;
     RECT  2.415 2.413 2.697 3.955 ;
     RECT  3.528 3.379 12.87 3.955 ;
     RECT  14.184 4.729 14.202 4.801 ;
     RECT  2.415 3.955 12.978 5.071 ;
     RECT  14.184 4.801 14.238 5.971 ;
     RECT  2.415 5.071 13.374 6.079 ;
     RECT  14.148 5.971 14.238 6.079 ;
     RECT  15.012 7.393 15.03 8.045 ;
     RECT  2.415 6.079 14.238 9.259 ;
     RECT  2.415 9.259 14.274 9.625 ;
     RECT  15.012 9.085 15.03 9.625 ;
     RECT  2.415 9.625 15.03 9.773 ;
     RECT  2.415 9.773 12.834 10.435 ;
     RECT  2.268 10.435 12.834 10.493 ;
     RECT  2.415 10.493 12.834 10.939 ;
     RECT  13.644 9.773 15.03 10.939 ;
     RECT  2.415 10.939 15.03 11.117 ;
     RECT  13.536 11.117 15.03 11.405 ;
     RECT  13.608 11.405 15.03 11.501 ;
     RECT  2.415 11.117 12.726 12.289 ;
     RECT  13.608 11.501 14.238 12.289 ;
     RECT  2.415 12.289 14.238 12.365 ;
     RECT  13.644 12.365 14.238 12.389 ;
     RECT  2.415 12.365 12.618 12.515 ;
     RECT  2.415 12.515 12.438 12.749 ;
     RECT  14.22 12.389 14.238 12.749 ;
     RECT  15.012 11.501 15.03 12.749 ;
     RECT  10.188 12.749 12.438 12.785 ;
     RECT  2.415 12.749 9.306 12.821 ;
     RECT  11.988 12.785 12.438 12.845 ;
     RECT  2.415 12.821 9.054 12.929 ;
     RECT  10.188 12.785 10.71 12.929 ;
     RECT  11.988 12.845 12.006 12.929 ;
     RECT  2.415 12.929 8.37 12.941 ;
     RECT  2.415 12.941 8.082 12.977 ;
     RECT  10.515 12.929 10.605 12.977 ;
     RECT  2.844 12.977 8.082 13.055 ;
     RECT  2.844 13.055 6.318 13.085 ;
     RECT  7.416 13.055 8.082 13.085 ;
     RECT  2.844 13.085 3.474 13.133 ;
     RECT  7.416 13.085 7.974 13.133 ;
     RECT  4.464 13.085 6.318 13.181 ;
     RECT  7.416 13.133 7.794 13.181 ;
     RECT  7.776 13.181 7.794 13.709 ;
     RECT  6.12 13.181 6.318 14.285 ;
     RECT  6.3 14.285 6.318 14.333 ;
     RECT  2.916 13.133 3.438 14.731 ;
     RECT  2.736 14.731 3.438 14.909 ;
     RECT  2.916 14.909 3.15 14.957 ;
     RECT  3.132 14.957 3.15 15.005 ;
     RECT  4.464 13.181 4.482 15.005 ;
    LAYER M4 ;
     RECT  2.245 10.464 2.293 10.488 ;
     RECT  2.149 14.976 2.293 15 ;
     RECT  2.293 10.32 2.408 10.488 ;
     RECT  2.408 2.148 2.512 12.972 ;
     RECT  2.512 2.418 2.533 12.972 ;
     RECT  2.293 14.832 2.629 15 ;
     RECT  2.533 2.418 2.704 13.128 ;
     RECT  2.629 14.64 2.867 15 ;
     RECT  2.867 14.88 3.161 15 ;
     RECT  3.161 14.88 3.449 14.952 ;
     RECT  2.704 12.528 3.485 13.128 ;
     RECT  3.485 12.528 3.949 13.08 ;
     RECT  2.704 8.496 4.057 10.824 ;
     RECT  3.449 14.928 4.259 14.952 ;
     RECT  4.229 1.728 4.313 1.752 ;
     RECT  4.453 14.976 4.595 15 ;
     RECT  3.949 12.336 4.705 13.08 ;
     RECT  4.705 12.288 5.029 13.08 ;
     RECT  5.029 12.24 5.093 13.128 ;
     RECT  2.704 3.552 5.108 3.576 ;
     RECT  4.417 6.144 5.108 6.168 ;
     RECT  4.165 7.44 5.108 7.464 ;
     RECT  4.057 8.448 5.108 10.824 ;
     RECT  5.093 12.24 5.108 13.176 ;
     RECT  5.108 2.148 5.212 13.176 ;
     RECT  5.212 2.418 5.404 13.176 ;
     RECT  5.404 9.36 5.557 13.176 ;
     RECT  5.557 9.36 5.795 13.224 ;
     RECT  5.795 9.36 6.149 12.936 ;
     RECT  6.109 14.256 6.289 14.28 ;
     RECT  6.149 9.36 6.397 10.824 ;
     RECT  5.404 4.368 6.421 5.256 ;
     RECT  6.289 14.256 6.469 14.328 ;
     RECT  6.421 3.408 6.508 5.256 ;
     RECT  6.469 14.16 6.611 14.328 ;
     RECT  6.508 3.696 6.689 5.256 ;
     RECT  6.689 5.232 7.081 5.256 ;
     RECT  5.404 6.768 7.081 7.464 ;
     RECT  7.081 5.232 7.117 7.464 ;
     RECT  6.397 8.832 7.333 10.824 ;
     RECT  7.333 8.832 7.388 10.968 ;
     RECT  6.149 12.48 7.388 12.936 ;
     RECT  6.611 14.304 7.571 14.328 ;
     RECT  7.117 2.544 7.585 2.616 ;
     RECT  6.689 3.696 7.585 3.72 ;
     RECT  7.388 12.48 7.765 13.176 ;
     RECT  7.585 2.544 7.808 3.72 ;
     RECT  7.117 5.232 7.808 7.608 ;
     RECT  7.388 8.832 7.808 11.16 ;
     RECT  7.765 12.48 7.808 13.704 ;
     RECT  7.808 2.148 7.912 13.704 ;
     RECT  7.912 2.418 8.051 13.704 ;
     RECT  8.051 2.418 8.104 13.08 ;
     RECT  8.104 12.048 8.147 13.08 ;
     RECT  8.104 2.544 8.381 6.888 ;
     RECT  8.147 12.048 8.381 12.936 ;
     RECT  8.381 5.52 8.453 6.888 ;
     RECT  8.381 2.544 8.525 4.536 ;
     RECT  8.525 2.592 8.579 4.536 ;
     RECT  8.579 3.408 8.741 4.536 ;
     RECT  8.453 6.864 8.921 6.888 ;
     RECT  8.381 12.048 9.137 12.072 ;
     RECT  8.104 9.36 9.241 10.968 ;
     RECT  8.741 3.408 9.565 4.344 ;
     RECT  9.565 2.832 10.22 4.344 ;
     RECT  8.453 5.52 10.22 5.832 ;
     RECT  10.22 2.832 10.285 5.832 ;
     RECT  10.285 2.832 10.508 6.024 ;
     RECT  9.241 9.36 10.508 11.976 ;
     RECT  10.508 2.148 10.612 12.972 ;
     RECT  10.612 2.418 10.804 12.702 ;
     RECT  10.804 10.704 10.973 10.728 ;
     RECT  10.804 2.832 11.009 2.856 ;
     RECT  11.941 7.056 12.265 7.08 ;
     RECT  10.804 11.952 12.409 11.976 ;
     RECT  11.941 8.592 12.553 8.616 ;
     RECT  12.301 10.704 12.557 10.728 ;
     RECT  12.553 8.592 12.697 9.096 ;
     RECT  12.265 7.056 12.733 7.368 ;
     RECT  12.697 8.4 12.733 9.096 ;
     RECT  12.409 11.952 12.805 12.84 ;
     RECT  12.661 5.136 12.845 5.16 ;
     RECT  12.733 7.056 13.345 9.096 ;
     RECT  13.345 7.056 13.633 9.768 ;
     RECT  12.805 10.992 13.633 12.84 ;
     RECT  13.633 7.056 14.173 12.84 ;
     RECT  14.173 6.96 14.209 12.84 ;
     RECT  14.209 6.864 15.084 12.84 ;
    LAYER M5 ;
     RECT  4.176 0.016 4.296 2.137 ;
     RECT  2.4 2.137 2.52 2.151 ;
     RECT  4.176 2.137 5.22 2.151 ;
     RECT  7.8 2.137 7.92 2.151 ;
     RECT  10.5 2.137 10.62 2.151 ;
     RECT  7.8 2.151 8.112 2.581 ;
     RECT  7.8 2.581 8.568 3.443 ;
     RECT  7.8 3.443 8.112 4.501 ;
     RECT  6.432 3.397 6.456 4.547 ;
     RECT  10.5 2.151 10.812 5.125 ;
     RECT  7.8 4.501 8.328 5.221 ;
     RECT  7.632 5.221 8.328 5.267 ;
     RECT  10.272 5.125 10.812 5.459 ;
     RECT  4.176 2.151 5.412 7.475 ;
     RECT  7.632 5.267 8.112 8.965 ;
     RECT  2.4 2.151 2.712 9.061 ;
     RECT  5.1 7.475 5.412 9.349 ;
     RECT  7.536 8.965 8.112 9.349 ;
     RECT  2.4 9.061 2.808 9.685 ;
     RECT  4.224 9.349 8.112 9.685 ;
     RECT  2.4 9.685 8.112 10.309 ;
     RECT  2.304 10.309 8.112 10.453 ;
     RECT  2.256 10.453 8.112 12.901 ;
     RECT  10.5 5.459 10.812 12.969 ;
     RECT  10.5 12.969 10.62 12.983 ;
     RECT  2.256 12.901 8.232 14.965 ;
     RECT  2.16 14.965 8.232 15.056 ;
  END
END dsfd_rly_63_NE

VERSION 5.8 ;
BUSBITCHARS "[]" ;
DIVIDERCHAR "/" ;
UNITS
    DATABASE MICRONS 1000 ;
END UNITS

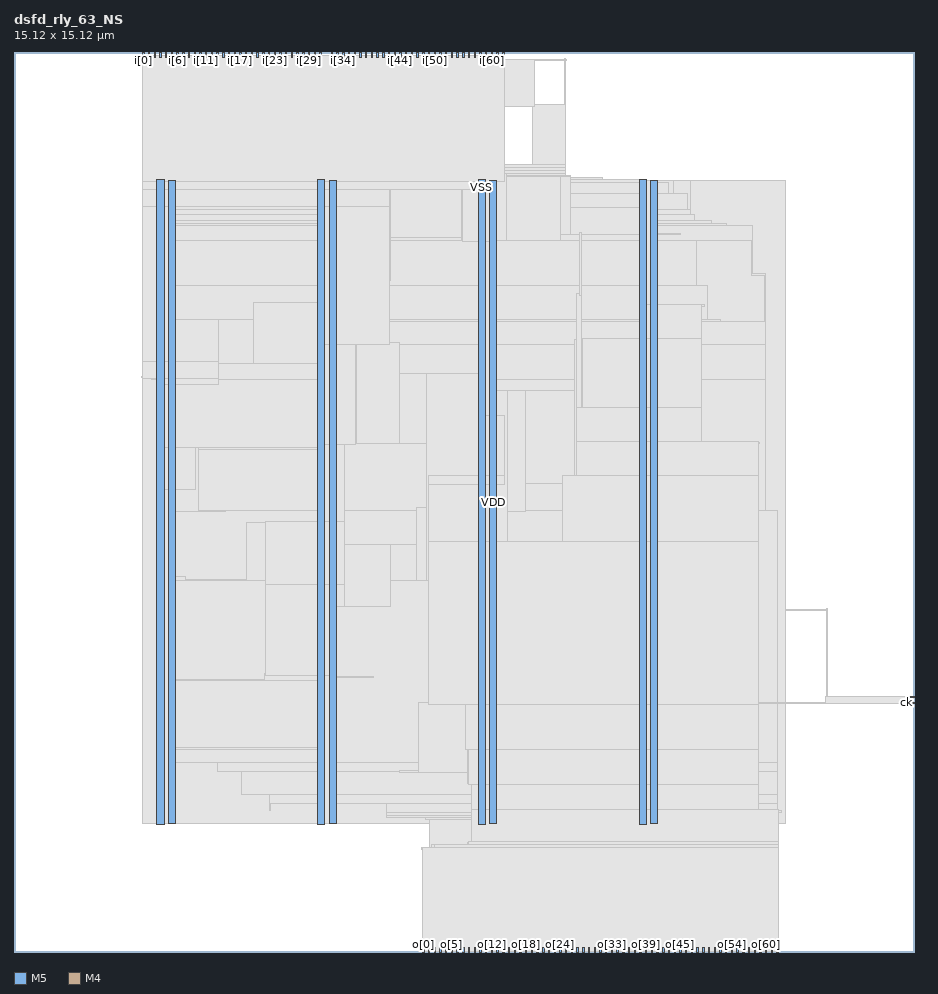
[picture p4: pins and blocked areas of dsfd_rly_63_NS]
MACRO dsfd_rly_63_NS
  FOREIGN dsfd_rly_63_NS 0 0 ;
  CLASS BLOCK ;
  SIZE 15.12 BY 15.12 ;
  PIN ck
    DIRECTION INPUT ;
    USE SIGNAL ;
    PORT
      LAYER M4 ;
        RECT  15.036 4.176 15.12 4.2 ;
    END
  END ck
  PIN i[0]
    DIRECTION INPUT ;
    USE SIGNAL ;
    PORT
      LAYER M5 ;
        RECT  2.16 15.036 2.184 15.12 ;
    END
  END i[0]
  PIN i[10]
    DIRECTION INPUT ;
    USE SIGNAL ;
    PORT
      LAYER M5 ;
        RECT  3.12 15.036 3.144 15.12 ;
    END
  END i[10]
  PIN i[11]
    DIRECTION INPUT ;
    USE SIGNAL ;
    PORT
      LAYER M5 ;
        RECT  3.216 15.036 3.24 15.12 ;
    END
  END i[11]
  PIN i[12]
    DIRECTION INPUT ;
    USE SIGNAL ;
    PORT
      LAYER M5 ;
        RECT  3.312 15.036 3.336 15.12 ;
    END
  END i[12]
  PIN i[13]
    DIRECTION INPUT ;
    USE SIGNAL ;
    PORT
      LAYER M5 ;
        RECT  3.408 15.036 3.432 15.12 ;
    END
  END i[13]
  PIN i[14]
    DIRECTION INPUT ;
    USE SIGNAL ;
    PORT
      LAYER M5 ;
        RECT  3.504 15.036 3.528 15.12 ;
    END
  END i[14]
  PIN i[15]
    DIRECTION INPUT ;
    USE SIGNAL ;
    PORT
      LAYER M5 ;
        RECT  3.6 15.036 3.624 15.12 ;
    END
  END i[15]
  PIN i[16]
    DIRECTION INPUT ;
    USE SIGNAL ;
    PORT
      LAYER M5 ;
        RECT  3.696 15.036 3.72 15.12 ;
    END
  END i[16]
  PIN i[17]
    DIRECTION INPUT ;
    USE SIGNAL ;
    PORT
      LAYER M5 ;
        RECT  3.792 15.036 3.816 15.12 ;
    END
  END i[17]
  PIN i[18]
    DIRECTION INPUT ;
    USE SIGNAL ;
    PORT
      LAYER M5 ;
        RECT  3.888 15.036 3.912 15.12 ;
    END
  END i[18]
  PIN i[19]
    DIRECTION INPUT ;
    USE SIGNAL ;
    PORT
      LAYER M5 ;
        RECT  3.984 15.036 4.008 15.12 ;
    END
  END i[19]
  PIN i[1]
    DIRECTION INPUT ;
    USE SIGNAL ;
    PORT
      LAYER M5 ;
        RECT  2.256 15.036 2.28 15.12 ;
    END
  END i[1]
  PIN i[20]
    DIRECTION INPUT ;
    USE SIGNAL ;
    PORT
      LAYER M5 ;
        RECT  4.08 15.036 4.104 15.12 ;
    END
  END i[20]
  PIN i[21]
    DIRECTION INPUT ;
    USE SIGNAL ;
    PORT
      LAYER M5 ;
        RECT  4.176 15.036 4.2 15.12 ;
    END
  END i[21]
  PIN i[22]
    DIRECTION INPUT ;
    USE SIGNAL ;
    PORT
      LAYER M5 ;
        RECT  4.272 15.036 4.296 15.12 ;
    END
  END i[22]
  PIN i[23]
    DIRECTION INPUT ;
    USE SIGNAL ;
    PORT
      LAYER M5 ;
        RECT  4.368 15.036 4.392 15.12 ;
    END
  END i[23]
  PIN i[24]
    DIRECTION INPUT ;
    USE SIGNAL ;
    PORT
      LAYER M5 ;
        RECT  4.464 15.036 4.488 15.12 ;
    END
  END i[24]
  PIN i[25]
    DIRECTION INPUT ;
    USE SIGNAL ;
    PORT
      LAYER M5 ;
        RECT  4.56 15.036 4.584 15.12 ;
    END
  END i[25]
  PIN i[26]
    DIRECTION INPUT ;
    USE SIGNAL ;
    PORT
      LAYER M5 ;
        RECT  4.656 15.036 4.68 15.12 ;
    END
  END i[26]
  PIN i[27]
    DIRECTION INPUT ;
    USE SIGNAL ;
    PORT
      LAYER M5 ;
        RECT  4.752 15.036 4.776 15.12 ;
    END
  END i[27]
  PIN i[28]
    DIRECTION INPUT ;
    USE SIGNAL ;
    PORT
      LAYER M5 ;
        RECT  4.848 15.036 4.872 15.12 ;
    END
  END i[28]
  PIN i[29]
    DIRECTION INPUT ;
    USE SIGNAL ;
    PORT
      LAYER M5 ;
        RECT  4.944 15.036 4.968 15.12 ;
    END
  END i[29]
  PIN i[2]
    DIRECTION INPUT ;
    USE SIGNAL ;
    PORT
      LAYER M5 ;
        RECT  2.352 15.036 2.376 15.12 ;
    END
  END i[2]
  PIN i[30]
    DIRECTION INPUT ;
    USE SIGNAL ;
    PORT
      LAYER M5 ;
        RECT  5.04 15.036 5.064 15.12 ;
    END
  END i[30]
  PIN i[31]
    DIRECTION INPUT ;
    USE SIGNAL ;
    PORT
      LAYER M5 ;
        RECT  5.136 15.036 5.16 15.12 ;
    END
  END i[31]
  PIN i[32]
    DIRECTION INPUT ;
    USE SIGNAL ;
    PORT
      LAYER M5 ;
        RECT  5.328 15.036 5.352 15.12 ;
    END
  END i[32]
  PIN i[33]
    DIRECTION INPUT ;
    USE SIGNAL ;
    PORT
      LAYER M5 ;
        RECT  5.424 15.036 5.448 15.12 ;
    END
  END i[33]
  PIN i[34]
    DIRECTION INPUT ;
    USE SIGNAL ;
    PORT
      LAYER M5 ;
        RECT  5.52 15.036 5.544 15.12 ;
    END
  END i[34]
  PIN i[35]
    DIRECTION INPUT ;
    USE SIGNAL ;
    PORT
      LAYER M5 ;
        RECT  5.616 15.036 5.64 15.12 ;
    END
  END i[35]
  PIN i[36]
    DIRECTION INPUT ;
    USE SIGNAL ;
    PORT
      LAYER M5 ;
        RECT  5.712 15.036 5.736 15.12 ;
    END
  END i[36]
  PIN i[37]
    DIRECTION INPUT ;
    USE SIGNAL ;
    PORT
      LAYER M5 ;
        RECT  5.808 15.036 5.832 15.12 ;
    END
  END i[37]
  PIN i[38]
    DIRECTION INPUT ;
    USE SIGNAL ;
    PORT
      LAYER M5 ;
        RECT  5.904 15.036 5.928 15.12 ;
    END
  END i[38]
  PIN i[39]
    DIRECTION INPUT ;
    USE SIGNAL ;
    PORT
      LAYER M5 ;
        RECT  6 15.036 6.024 15.12 ;
    END
  END i[39]
  PIN i[3]
    DIRECTION INPUT ;
    USE SIGNAL ;
    PORT
      LAYER M5 ;
        RECT  2.448 15.036 2.472 15.12 ;
    END
  END i[3]
  PIN i[40]
    DIRECTION INPUT ;
    USE SIGNAL ;
    PORT
      LAYER M5 ;
        RECT  6.096 15.036 6.12 15.12 ;
    END
  END i[40]
  PIN i[41]
    DIRECTION INPUT ;
    USE SIGNAL ;
    PORT
      LAYER M5 ;
        RECT  6.192 15.036 6.216 15.12 ;
    END
  END i[41]
  PIN i[42]
    DIRECTION INPUT ;
    USE SIGNAL ;
    PORT
      LAYER M5 ;
        RECT  6.288 15.036 6.312 15.12 ;
    END
  END i[42]
  PIN i[43]
    DIRECTION INPUT ;
    USE SIGNAL ;
    PORT
      LAYER M5 ;
        RECT  6.384 15.036 6.408 15.12 ;
    END
  END i[43]
  PIN i[44]
    DIRECTION INPUT ;
    USE SIGNAL ;
    PORT
      LAYER M5 ;
        RECT  6.48 15.036 6.504 15.12 ;
    END
  END i[44]
  PIN i[45]
    DIRECTION INPUT ;
    USE SIGNAL ;
    PORT
      LAYER M5 ;
        RECT  6.576 15.036 6.6 15.12 ;
    END
  END i[45]
  PIN i[46]
    DIRECTION INPUT ;
    USE SIGNAL ;
    PORT
      LAYER M5 ;
        RECT  6.672 15.036 6.696 15.12 ;
    END
  END i[46]
  PIN i[47]
    DIRECTION INPUT ;
    USE SIGNAL ;
    PORT
      LAYER M5 ;
        RECT  6.768 15.036 6.792 15.12 ;
    END
  END i[47]
  PIN i[48]
    DIRECTION INPUT ;
    USE SIGNAL ;
    PORT
      LAYER M5 ;
        RECT  6.864 15.036 6.888 15.12 ;
    END
  END i[48]
  PIN i[49]
    DIRECTION INPUT ;
    USE SIGNAL ;
    PORT
      LAYER M5 ;
        RECT  6.96 15.036 6.984 15.12 ;
    END
  END i[49]
  PIN i[4]
    DIRECTION INPUT ;
    USE SIGNAL ;
    PORT
      LAYER M5 ;
        RECT  2.544 15.036 2.568 15.12 ;
    END
  END i[4]
  PIN i[50]
    DIRECTION INPUT ;
    USE SIGNAL ;
    PORT
      LAYER M5 ;
        RECT  7.056 15.036 7.08 15.12 ;
    END
  END i[50]
  PIN i[51]
    DIRECTION INPUT ;
    USE SIGNAL ;
    PORT
      LAYER M5 ;
        RECT  7.152 15.036 7.176 15.12 ;
    END
  END i[51]
  PIN i[52]
    DIRECTION INPUT ;
    USE SIGNAL ;
    PORT
      LAYER M5 ;
        RECT  7.248 15.036 7.272 15.12 ;
    END
  END i[52]
  PIN i[53]
    DIRECTION INPUT ;
    USE SIGNAL ;
    PORT
      LAYER M5 ;
        RECT  7.344 15.036 7.368 15.12 ;
    END
  END i[53]
  PIN i[54]
    DIRECTION INPUT ;
    USE SIGNAL ;
    PORT
      LAYER M5 ;
        RECT  7.44 15.036 7.464 15.12 ;
    END
  END i[54]
  PIN i[55]
    DIRECTION INPUT ;
    USE SIGNAL ;
    PORT
      LAYER M5 ;
        RECT  7.536 15.036 7.56 15.12 ;
    END
  END i[55]
  PIN i[56]
    DIRECTION INPUT ;
    USE SIGNAL ;
    PORT
      LAYER M5 ;
        RECT  7.632 15.036 7.656 15.12 ;
    END
  END i[56]
  PIN i[57]
    DIRECTION INPUT ;
    USE SIGNAL ;
    PORT
      LAYER M5 ;
        RECT  7.728 15.036 7.752 15.12 ;
    END
  END i[57]
  PIN i[58]
    DIRECTION INPUT ;
    USE SIGNAL ;
    PORT
      LAYER M5 ;
        RECT  7.824 15.036 7.848 15.12 ;
    END
  END i[58]
  PIN i[59]
    DIRECTION INPUT ;
    USE SIGNAL ;
    PORT
      LAYER M5 ;
        RECT  7.92 15.036 7.944 15.12 ;
    END
  END i[59]
  PIN i[5]
    DIRECTION INPUT ;
    USE SIGNAL ;
    PORT
      LAYER M5 ;
        RECT  2.64 15.036 2.664 15.12 ;
    END
  END i[5]
  PIN i[60]
    DIRECTION INPUT ;
    USE SIGNAL ;
    PORT
      LAYER M5 ;
        RECT  8.016 15.036 8.04 15.12 ;
    END
  END i[60]
  PIN i[61]
    DIRECTION INPUT ;
    USE SIGNAL ;
    PORT
      LAYER M5 ;
        RECT  8.112 15.036 8.136 15.12 ;
    END
  END i[61]
  PIN i[62]
    DIRECTION INPUT ;
    USE SIGNAL ;
    PORT
      LAYER M5 ;
        RECT  8.208 15.036 8.232 15.12 ;
    END
  END i[62]
  PIN i[6]
    DIRECTION INPUT ;
    USE SIGNAL ;
    PORT
      LAYER M5 ;
        RECT  2.736 15.036 2.76 15.12 ;
    END
  END i[6]
  PIN i[7]
    DIRECTION INPUT ;
    USE SIGNAL ;
    PORT
      LAYER M5 ;
        RECT  2.832 15.036 2.856 15.12 ;
    END
  END i[7]
  PIN i[8]
    DIRECTION INPUT ;
    USE SIGNAL ;
    PORT
      LAYER M5 ;
        RECT  2.928 15.036 2.952 15.12 ;
    END
  END i[8]
  PIN i[9]
    DIRECTION INPUT ;
    USE SIGNAL ;
    PORT
      LAYER M5 ;
        RECT  3.024 15.036 3.048 15.12 ;
    END
  END i[9]
  PIN o[0]
    DIRECTION OUTPUT ;
    USE SIGNAL ;
    PORT
      LAYER M5 ;
        RECT  6.864 0 6.888 0.084 ;
    END
  END o[0]
  PIN o[10]
    DIRECTION OUTPUT ;
    USE SIGNAL ;
    PORT
      LAYER M5 ;
        RECT  7.824 0 7.848 0.084 ;
    END
  END o[10]
  PIN o[11]
    DIRECTION OUTPUT ;
    USE SIGNAL ;
    PORT
      LAYER M5 ;
        RECT  7.92 0 7.944 0.084 ;
    END
  END o[11]
  PIN o[12]
    DIRECTION OUTPUT ;
    USE SIGNAL ;
    PORT
      LAYER M5 ;
        RECT  8.016 0 8.04 0.084 ;
    END
  END o[12]
  PIN o[13]
    DIRECTION OUTPUT ;
    USE SIGNAL ;
    PORT
      LAYER M5 ;
        RECT  8.112 0 8.136 0.084 ;
    END
  END o[13]
  PIN o[14]
    DIRECTION OUTPUT ;
    USE SIGNAL ;
    PORT
      LAYER M5 ;
        RECT  8.208 0 8.232 0.084 ;
    END
  END o[14]
  PIN o[15]
    DIRECTION OUTPUT ;
    USE SIGNAL ;
    PORT
      LAYER M5 ;
        RECT  8.304 0 8.328 0.084 ;
    END
  END o[15]
  PIN o[16]
    DIRECTION OUTPUT ;
    USE SIGNAL ;
    PORT
      LAYER M5 ;
        RECT  8.4 0 8.424 0.084 ;
    END
  END o[16]
  PIN o[17]
    DIRECTION OUTPUT ;
    USE SIGNAL ;
    PORT
      LAYER M5 ;
        RECT  8.496 0 8.52 0.084 ;
    END
  END o[17]
  PIN o[18]
    DIRECTION OUTPUT ;
    USE SIGNAL ;
    PORT
      LAYER M5 ;
        RECT  8.592 0 8.616 0.084 ;
    END
  END o[18]
  PIN o[19]
    DIRECTION OUTPUT ;
    USE SIGNAL ;
    PORT
      LAYER M5 ;
        RECT  8.688 0 8.712 0.084 ;
    END
  END o[19]
  PIN o[1]
    DIRECTION OUTPUT ;
    USE SIGNAL ;
    PORT
      LAYER M5 ;
        RECT  6.96 0 6.984 0.084 ;
    END
  END o[1]
  PIN o[20]
    DIRECTION OUTPUT ;
    USE SIGNAL ;
    PORT
      LAYER M5 ;
        RECT  8.784 0 8.808 0.084 ;
    END
  END o[20]
  PIN o[21]
    DIRECTION OUTPUT ;
    USE SIGNAL ;
    PORT
      LAYER M5 ;
        RECT  8.88 0 8.904 0.084 ;
    END
  END o[21]
  PIN o[22]
    DIRECTION OUTPUT ;
    USE SIGNAL ;
    PORT
      LAYER M5 ;
        RECT  8.976 0 9 0.084 ;
    END
  END o[22]
  PIN o[23]
    DIRECTION OUTPUT ;
    USE SIGNAL ;
    PORT
      LAYER M5 ;
        RECT  9.072 0 9.096 0.084 ;
    END
  END o[23]
  PIN o[24]
    DIRECTION OUTPUT ;
    USE SIGNAL ;
    PORT
      LAYER M5 ;
        RECT  9.168 0 9.192 0.084 ;
    END
  END o[24]
  PIN o[25]
    DIRECTION OUTPUT ;
    USE SIGNAL ;
    PORT
      LAYER M5 ;
        RECT  9.264 0 9.288 0.084 ;
    END
  END o[25]
  PIN o[26]
    DIRECTION OUTPUT ;
    USE SIGNAL ;
    PORT
      LAYER M5 ;
        RECT  9.36 0 9.384 0.084 ;
    END
  END o[26]
  PIN o[27]
    DIRECTION OUTPUT ;
    USE SIGNAL ;
    PORT
      LAYER M5 ;
        RECT  9.456 0 9.48 0.084 ;
    END
  END o[27]
  PIN o[28]
    DIRECTION OUTPUT ;
    USE SIGNAL ;
    PORT
      LAYER M5 ;
        RECT  9.552 0 9.576 0.084 ;
    END
  END o[28]
  PIN o[29]
    DIRECTION OUTPUT ;
    USE SIGNAL ;
    PORT
      LAYER M5 ;
        RECT  9.648 0 9.672 0.084 ;
    END
  END o[29]
  PIN o[2]
    DIRECTION OUTPUT ;
    USE SIGNAL ;
    PORT
      LAYER M5 ;
        RECT  7.056 0 7.08 0.084 ;
    END
  END o[2]
  PIN o[30]
    DIRECTION OUTPUT ;
    USE SIGNAL ;
    PORT
      LAYER M5 ;
        RECT  9.744 0 9.768 0.084 ;
    END
  END o[30]
  PIN o[31]
    DIRECTION OUTPUT ;
    USE SIGNAL ;
    PORT
      LAYER M5 ;
        RECT  9.84 0 9.864 0.084 ;
    END
  END o[31]
  PIN o[32]
    DIRECTION OUTPUT ;
    USE SIGNAL ;
    PORT
      LAYER M5 ;
        RECT  9.936 0 9.96 0.084 ;
    END
  END o[32]
  PIN o[33]
    DIRECTION OUTPUT ;
    USE SIGNAL ;
    PORT
      LAYER M5 ;
        RECT  10.032 0 10.056 0.084 ;
    END
  END o[33]
  PIN o[34]
    DIRECTION OUTPUT ;
    USE SIGNAL ;
    PORT
      LAYER M5 ;
        RECT  10.128 0 10.152 0.084 ;
    END
  END o[34]
  PIN o[35]
    DIRECTION OUTPUT ;
    USE SIGNAL ;
    PORT
      LAYER M5 ;
        RECT  10.224 0 10.248 0.084 ;
    END
  END o[35]
  PIN o[36]
    DIRECTION OUTPUT ;
    USE SIGNAL ;
    PORT
      LAYER M5 ;
        RECT  10.32 0 10.344 0.084 ;
    END
  END o[36]
  PIN o[37]
    DIRECTION OUTPUT ;
    USE SIGNAL ;
    PORT
      LAYER M5 ;
        RECT  10.416 0 10.44 0.084 ;
    END
  END o[37]
  PIN o[38]
    DIRECTION OUTPUT ;
    USE SIGNAL ;
    PORT
      LAYER M5 ;
        RECT  10.512 0 10.536 0.084 ;
    END
  END o[38]
  PIN o[39]
    DIRECTION OUTPUT ;
    USE SIGNAL ;
    PORT
      LAYER M5 ;
        RECT  10.608 0 10.632 0.084 ;
    END
  END o[39]
  PIN o[3]
    DIRECTION OUTPUT ;
    USE SIGNAL ;
    PORT
      LAYER M5 ;
        RECT  7.152 0 7.176 0.084 ;
    END
  END o[3]
  PIN o[40]
    DIRECTION OUTPUT ;
    USE SIGNAL ;
    PORT
      LAYER M5 ;
        RECT  10.704 0 10.728 0.084 ;
    END
  END o[40]
  PIN o[41]
    DIRECTION OUTPUT ;
    USE SIGNAL ;
    PORT
      LAYER M5 ;
        RECT  10.8 0 10.824 0.084 ;
    END
  END o[41]
  PIN o[42]
    DIRECTION OUTPUT ;
    USE SIGNAL ;
    PORT
      LAYER M5 ;
        RECT  10.896 0 10.92 0.084 ;
    END
  END o[42]
  PIN o[43]
    DIRECTION OUTPUT ;
    USE SIGNAL ;
    PORT
      LAYER M5 ;
        RECT  10.992 0 11.016 0.084 ;
    END
  END o[43]
  PIN o[44]
    DIRECTION OUTPUT ;
    USE SIGNAL ;
    PORT
      LAYER M5 ;
        RECT  11.088 0 11.112 0.084 ;
    END
  END o[44]
  PIN o[45]
    DIRECTION OUTPUT ;
    USE SIGNAL ;
    PORT
      LAYER M5 ;
        RECT  11.184 0 11.208 0.084 ;
    END
  END o[45]
  PIN o[46]
    DIRECTION OUTPUT ;
    USE SIGNAL ;
    PORT
      LAYER M5 ;
        RECT  11.28 0 11.304 0.084 ;
    END
  END o[46]
  PIN o[47]
    DIRECTION OUTPUT ;
    USE SIGNAL ;
    PORT
      LAYER M5 ;
        RECT  11.376 0 11.4 0.084 ;
    END
  END o[47]
  PIN o[48]
    DIRECTION OUTPUT ;
    USE SIGNAL ;
    PORT
      LAYER M5 ;
        RECT  11.472 0 11.496 0.084 ;
    END
  END o[48]
  PIN o[49]
    DIRECTION OUTPUT ;
    USE SIGNAL ;
    PORT
      LAYER M5 ;
        RECT  11.568 0 11.592 0.084 ;
    END
  END o[49]
  PIN o[4]
    DIRECTION OUTPUT ;
    USE SIGNAL ;
    PORT
      LAYER M5 ;
        RECT  7.248 0 7.272 0.084 ;
    END
  END o[4]
  PIN o[50]
    DIRECTION OUTPUT ;
    USE SIGNAL ;
    PORT
      LAYER M5 ;
        RECT  11.664 0 11.688 0.084 ;
    END
  END o[50]
  PIN o[51]
    DIRECTION OUTPUT ;
    USE SIGNAL ;
    PORT
      LAYER M5 ;
        RECT  11.76 0 11.784 0.084 ;
    END
  END o[51]
  PIN o[52]
    DIRECTION OUTPUT ;
    USE SIGNAL ;
    PORT
      LAYER M5 ;
        RECT  11.856 0 11.88 0.084 ;
    END
  END o[52]
  PIN o[53]
    DIRECTION OUTPUT ;
    USE SIGNAL ;
    PORT
      LAYER M5 ;
        RECT  11.952 0 11.976 0.084 ;
    END
  END o[53]
  PIN o[54]
    DIRECTION OUTPUT ;
    USE SIGNAL ;
    PORT
      LAYER M5 ;
        RECT  12.048 0 12.072 0.084 ;
    END
  END o[54]
  PIN o[55]
    DIRECTION OUTPUT ;
    USE SIGNAL ;
    PORT
      LAYER M5 ;
        RECT  12.144 0 12.168 0.084 ;
    END
  END o[55]
  PIN o[56]
    DIRECTION OUTPUT ;
    USE SIGNAL ;
    PORT
      LAYER M5 ;
        RECT  12.24 0 12.264 0.084 ;
    END
  END o[56]
  PIN o[57]
    DIRECTION OUTPUT ;
    USE SIGNAL ;
    PORT
      LAYER M5 ;
        RECT  12.336 0 12.36 0.084 ;
    END
  END o[57]
  PIN o[58]
    DIRECTION OUTPUT ;
    USE SIGNAL ;
    PORT
      LAYER M5 ;
        RECT  12.432 0 12.456 0.084 ;
    END
  END o[58]
  PIN o[59]
    DIRECTION OUTPUT ;
    USE SIGNAL ;
    PORT
      LAYER M5 ;
        RECT  12.528 0 12.552 0.084 ;
    END
  END o[59]
  PIN o[5]
    DIRECTION OUTPUT ;
    USE SIGNAL ;
    PORT
      LAYER M5 ;
        RECT  7.344 0 7.368 0.084 ;
    END
  END o[5]
  PIN o[60]
    DIRECTION OUTPUT ;
    USE SIGNAL ;
    PORT
      LAYER M5 ;
        RECT  12.624 0 12.648 0.084 ;
    END
  END o[60]
  PIN o[61]
    DIRECTION OUTPUT ;
    USE SIGNAL ;
    PORT
      LAYER M5 ;
        RECT  12.72 0 12.744 0.084 ;
    END
  END o[61]
  PIN o[62]
    DIRECTION OUTPUT ;
    USE SIGNAL ;
    PORT
      LAYER M5 ;
        RECT  12.816 0 12.84 0.084 ;
    END
  END o[62]
  PIN o[6]
    DIRECTION OUTPUT ;
    USE SIGNAL ;
    PORT
      LAYER M5 ;
        RECT  7.44 0 7.464 0.084 ;
    END
  END o[6]
  PIN o[7]
    DIRECTION OUTPUT ;
    USE SIGNAL ;
    PORT
      LAYER M5 ;
        RECT  7.536 0 7.56 0.084 ;
    END
  END o[7]
  PIN o[8]
    DIRECTION OUTPUT ;
    USE SIGNAL ;
    PORT
      LAYER M5 ;
        RECT  7.632 0 7.656 0.084 ;
    END
  END o[8]
  PIN o[9]
    DIRECTION OUTPUT ;
    USE SIGNAL ;
    PORT
      LAYER M5 ;
        RECT  7.728 0 7.752 0.084 ;
    END
  END o[9]
  PIN rs
    DIRECTION INPUT ;
    USE SIGNAL ;
    PORT
      LAYER M4 ;
        RECT  15.036 4.272 15.12 4.296 ;
    END
  END rs
  PIN VDD
    DIRECTION INOUT ;
    USE POWER ;
    PORT
      LAYER M5 ;
        RECT  10.692 2.151 10.812 12.969 ;
        RECT  7.992 2.151 8.112 12.969 ;
        RECT  5.292 2.151 5.412 12.969 ;
        RECT  2.592 2.151 2.712 12.969 ;
    END
  END VDD
  PIN VSS
    DIRECTION INOUT ;
    USE GROUND ;
    PORT
      LAYER M5 ;
        RECT  10.5 2.137 10.62 12.983 ;
        RECT  7.8 2.137 7.92 12.983 ;
        RECT  5.1 2.137 5.22 12.983 ;
        RECT  2.4 2.137 2.52 12.983 ;
    END
  END VSS
  OBS
    LAYER RVTN ;
     RECT  2.16 2.16 12.96 2.295 ;
     RECT  2.16 2.565 12.96 2.835 ;
     RECT  2.16 3.105 12.96 3.375 ;
     RECT  2.16 3.645 12.96 3.915 ;
     RECT  2.16 4.185 12.96 4.455 ;
     RECT  2.16 4.725 12.96 4.995 ;
     RECT  2.16 5.265 12.96 5.535 ;
     RECT  2.16 5.805 12.96 6.075 ;
     RECT  2.16 6.345 12.96 6.615 ;
     RECT  2.16 6.885 12.96 7.155 ;
     RECT  2.16 7.425 12.96 7.695 ;
     RECT  2.16 7.965 12.96 8.235 ;
     RECT  2.16 8.505 12.96 8.775 ;
     RECT  2.16 9.045 12.96 9.315 ;
     RECT  2.16 9.585 12.96 9.855 ;
     RECT  2.16 10.125 12.96 10.395 ;
     RECT  2.16 10.665 12.96 10.935 ;
     RECT  2.16 11.205 12.96 11.475 ;
     RECT  2.16 11.745 12.96 12.015 ;
     RECT  2.16 12.285 12.96 12.555 ;
     RECT  2.16 12.825 12.96 12.96 ;
    LAYER RVTP ;
     RECT  2.16 2.295 12.96 2.565 ;
     RECT  2.16 2.835 12.96 3.105 ;
     RECT  2.16 3.375 12.96 3.645 ;
     RECT  2.16 3.915 12.96 4.185 ;
     RECT  2.16 4.455 12.96 4.725 ;
     RECT  2.16 4.995 12.96 5.265 ;
     RECT  2.16 5.535 12.96 5.805 ;
     RECT  2.16 6.075 12.96 6.345 ;
     RECT  2.16 6.615 12.96 6.885 ;
     RECT  2.16 7.155 12.96 7.425 ;
     RECT  2.16 7.695 12.96 7.965 ;
     RECT  2.16 8.235 12.96 8.505 ;
     RECT  2.16 8.775 12.96 9.045 ;
     RECT  2.16 9.315 12.96 9.585 ;
     RECT  2.16 9.855 12.96 10.125 ;
     RECT  2.16 10.395 12.96 10.665 ;
     RECT  2.16 10.935 12.96 11.205 ;
     RECT  2.16 11.475 12.96 11.745 ;
     RECT  2.16 12.015 12.96 12.285 ;
     RECT  2.16 12.555 12.96 12.825 ;
    LAYER M1 ;
     RECT  2.16 2.151 12.96 12.969 ;
    LAYER M2 ;
     RECT  2.16 2.151 8.959 12.969 ;
     RECT  8.959 2.151 9.887 13.014 ;
     RECT  9.887 2.151 11.083 12.969 ;
     RECT  11.083 2.106 11.363 12.969 ;
     RECT  11.363 2.151 12.96 12.969 ;
     RECT  12.96 5.742 13.667 5.76 ;
    LAYER M3 ;
     RECT  8.136 0.091 8.154 0.139 ;
     RECT  9.144 0.091 9.162 0.139 ;
     RECT  12.06 0.091 12.474 0.139 ;
     RECT  8.136 0.139 9.162 0.235 ;
     RECT  6.984 0.091 7.002 0.475 ;
     RECT  7.74 0.235 9.162 0.475 ;
     RECT  6.984 0.475 9.162 0.523 ;
     RECT  10.332 0.427 10.35 0.523 ;
     RECT  10.332 0.523 10.494 0.571 ;
     RECT  10.332 0.571 10.962 0.619 ;
     RECT  10.332 0.619 11.07 1.099 ;
     RECT  12.06 0.139 12.726 1.099 ;
     RECT  6.984 0.523 9.45 1.147 ;
     RECT  10.332 1.099 12.726 1.147 ;
     RECT  6.984 1.147 12.726 2.227 ;
     RECT  6.912 2.227 12.726 2.263 ;
     RECT  6.264 2.263 12.726 2.299 ;
     RECT  6.264 2.299 12.762 2.347 ;
     RECT  2.415 2.143 2.505 2.413 ;
     RECT  5.115 2.143 5.205 2.413 ;
     RECT  4.284 2.371 4.302 2.497 ;
     RECT  5.115 2.413 5.397 2.497 ;
     RECT  6.264 2.347 12.834 2.497 ;
     RECT  4.284 2.497 12.834 2.641 ;
     RECT  3.816 2.641 12.834 3.037 ;
     RECT  2.415 2.413 2.697 3.181 ;
     RECT  3.42 3.037 12.834 3.181 ;
     RECT  13.644 4.267 13.662 5.765 ;
     RECT  2.415 3.181 12.834 7.421 ;
     RECT  2.415 7.421 12.618 9.625 ;
     RECT  2.304 9.625 12.618 10.205 ;
     RECT  2.34 10.205 12.618 10.589 ;
     RECT  2.34 10.589 11.862 10.625 ;
     RECT  2.34 10.625 11.646 11.201 ;
     RECT  12.6 10.589 12.618 11.371 ;
     RECT  12.384 11.371 12.618 11.399 ;
     RECT  2.34 11.201 11.466 11.947 ;
     RECT  12.384 11.399 12.402 11.947 ;
     RECT  2.34 11.947 12.402 12.209 ;
     RECT  2.34 12.209 11.97 12.245 ;
     RECT  2.34 12.245 11.718 12.281 ;
     RECT  2.34 12.281 11.43 12.389 ;
     RECT  2.34 12.389 11.358 12.479 ;
     RECT  2.34 12.479 11.322 12.749 ;
     RECT  2.34 12.749 10.998 12.929 ;
     RECT  2.34 12.929 10.605 12.977 ;
     RECT  2.34 12.977 9.882 13.019 ;
     RECT  2.34 13.019 9.342 13.037 ;
     RECT  2.34 13.037 9.27 13.085 ;
     RECT  2.34 13.085 3.078 13.133 ;
     RECT  5.076 13.085 5.454 13.133 ;
     RECT  7.74 13.085 9.27 13.133 ;
     RECT  5.256 13.133 5.274 13.181 ;
     RECT  7.956 13.133 9.27 13.181 ;
     RECT  2.376 13.133 3.078 13.229 ;
     RECT  8.064 13.181 9.27 13.229 ;
     RECT  8.712 13.229 9.27 14.237 ;
     RECT  3.06 13.229 3.078 15.005 ;
     RECT  9.252 14.237 9.27 15.005 ;
    LAYER M4 ;
     RECT  2.149 9.648 2.245 9.672 ;
     RECT  2.3 13.104 2.365 13.128 ;
     RECT  2.245 9.648 2.408 10.2 ;
     RECT  2.365 13.104 2.408 13.224 ;
     RECT  2.408 2.148 2.512 13.224 ;
     RECT  2.512 2.418 2.579 13.224 ;
     RECT  2.579 2.418 2.585 13.128 ;
     RECT  2.585 2.418 2.704 13.08 ;
     RECT  2.704 6.24 2.873 6.312 ;
     RECT  2.629 14.976 3.089 15 ;
     RECT  2.704 7.392 3.1 8.472 ;
     RECT  2.704 9.552 3.443 10.632 ;
     RECT  3.1 7.392 3.557 7.416 ;
     RECT  2.873 6.24 3.913 6.264 ;
     RECT  3.443 9.888 4.021 10.632 ;
     RECT  2.704 4.56 4.213 4.584 ;
     RECT  2.704 12.528 5.021 13.08 ;
     RECT  5.021 12.528 5.104 13.128 ;
     RECT  2.704 3.408 5.108 3.432 ;
     RECT  4.213 4.56 5.108 4.68 ;
     RECT  3.913 6.24 5.108 7.224 ;
     RECT  3.1 8.448 5.108 8.472 ;
     RECT  4.021 9.888 5.108 10.92 ;
     RECT  5.104 12.528 5.108 13.176 ;
     RECT  5.108 2.148 5.212 13.176 ;
     RECT  5.212 2.418 5.285 13.176 ;
     RECT  5.285 2.418 5.404 13.128 ;
     RECT  5.404 8.544 5.465 13.128 ;
     RECT  5.404 5.808 5.555 7.224 ;
     RECT  5.465 8.544 5.753 13.08 ;
     RECT  5.404 4.608 6.041 4.632 ;
     RECT  5.753 11.28 6.323 13.08 ;
     RECT  5.555 5.808 6.329 6.84 ;
     RECT  5.753 8.544 6.473 10.248 ;
     RECT  6.329 6.24 6.757 6.84 ;
     RECT  6.469 3.024 6.793 3.048 ;
     RECT  6.757 6.24 6.937 7.464 ;
     RECT  6.473 8.544 6.937 9.72 ;
     RECT  6.853 1.728 7.009 1.752 ;
     RECT  6.929 0.096 7.013 0.12 ;
     RECT  7.081 0.144 7.379 0.552 ;
     RECT  6.323 12 7.525 13.08 ;
     RECT  7.009 1.728 7.621 1.8 ;
     RECT  6.793 3.024 7.621 4.2 ;
     RECT  7.525 11.952 7.685 13.08 ;
     RECT  7.621 1.728 7.765 1.848 ;
     RECT  7.379 0.144 7.769 0.264 ;
     RECT  7.765 1.68 7.808 1.848 ;
     RECT  7.621 2.832 7.808 4.2 ;
     RECT  6.937 6.24 7.808 9.72 ;
     RECT  7.685 11.952 7.808 13.128 ;
     RECT  7.808 1.68 7.813 13.128 ;
     RECT  7.813 1.68 7.859 13.176 ;
     RECT  7.859 1.728 7.984 13.176 ;
     RECT  7.769 0.144 8.005 0.168 ;
     RECT  7.984 1.728 8.093 13.224 ;
     RECT  7.237 14.208 8.101 14.232 ;
     RECT  8.093 1.728 8.104 13.08 ;
     RECT  8.104 11.952 8.273 13.08 ;
     RECT  8.104 6.096 8.291 9.432 ;
     RECT  8.291 7.392 8.597 9.432 ;
     RECT  8.101 14.208 8.741 15 ;
     RECT  8.005 0.096 9.173 0.168 ;
     RECT  8.273 11.952 9.173 13.032 ;
     RECT  8.104 1.728 9.233 3.048 ;
     RECT  8.104 4.176 9.233 4.2 ;
     RECT  8.741 14.976 9.281 15 ;
     RECT  9.173 12.048 9.353 13.032 ;
     RECT  8.597 7.872 9.421 9.432 ;
     RECT  9.421 7.872 9.452 10.296 ;
     RECT  9.452 7.872 9.539 11.064 ;
     RECT  9.421 0.528 9.829 0.552 ;
     RECT  9.233 1.728 9.829 4.2 ;
     RECT  8.291 6.096 9.925 6.408 ;
     RECT  9.925 6.096 10.021 6.888 ;
     RECT  9.539 7.872 10.021 10.296 ;
     RECT  10.021 6.096 10.268 10.296 ;
     RECT  9.829 0.528 10.277 4.2 ;
     RECT  10.277 0.432 10.309 4.2 ;
     RECT  10.268 6.048 10.309 10.296 ;
     RECT  10.309 0.432 10.361 10.296 ;
     RECT  10.361 0.528 10.508 10.296 ;
     RECT  9.353 12.048 10.508 12.504 ;
     RECT  10.508 0.528 10.612 12.972 ;
     RECT  10.612 0.528 10.643 12.702 ;
     RECT  10.643 0.576 10.804 12.702 ;
     RECT  10.804 0.576 11.081 1.8 ;
     RECT  10.804 10.32 11.081 10.872 ;
     RECT  10.804 6.864 11.117 8.184 ;
     RECT  11.117 7.728 11.189 8.184 ;
     RECT  10.804 12.048 11.189 12.072 ;
     RECT  10.804 5.664 11.557 5.688 ;
     RECT  11.081 10.848 11.593 10.872 ;
     RECT  10.804 2.784 11.665 4.2 ;
     RECT  11.081 1.104 11.699 1.8 ;
     RECT  11.189 7.728 11.765 7.992 ;
     RECT  11.765 7.968 11.801 7.992 ;
     RECT  11.699 1.68 11.941 1.8 ;
     RECT  11.845 0.096 12.133 0.12 ;
     RECT  11.665 2.88 12.269 4.2 ;
     RECT  12.133 0.096 12.485 0.168 ;
     RECT  12.269 2.88 12.515 3.192 ;
     RECT  12.437 8.544 12.521 8.568 ;
     RECT  11.941 1.68 12.629 1.848 ;
     RECT  12.629 1.728 12.689 1.848 ;
     RECT  12.689 1.728 12.701 2.376 ;
     RECT  12.485 0.144 12.737 0.168 ;
     RECT  12.701 2.304 12.773 2.376 ;
     RECT  12.773 2.352 12.889 2.376 ;
     RECT  12.269 4.176 13.633 4.2 ;
     RECT  13.633 4.176 15.084 4.296 ;
    LAYER M5 ;
     RECT  6.864 0.016 12.84 1.763 ;
     RECT  7.056 1.763 12.84 1.811 ;
     RECT  7.632 1.811 12.84 1.859 ;
     RECT  2.4 2.137 2.52 2.151 ;
     RECT  5.1 2.137 5.22 2.151 ;
     RECT  7.68 1.859 12.84 2.387 ;
     RECT  7.68 2.387 12.504 2.821 ;
     RECT  7.632 2.821 12.504 3.397 ;
     RECT  7.584 3.397 12.504 4.165 ;
     RECT  5.1 2.151 5.412 4.645 ;
     RECT  4.224 4.645 5.412 6.181 ;
     RECT  6.96 4.165 12.504 6.899 ;
     RECT  4.224 6.181 5.544 7.235 ;
     RECT  2.4 2.151 2.712 7.765 ;
     RECT  6.96 6.899 8.112 7.861 ;
     RECT  6.96 7.861 8.232 8.003 ;
     RECT  9.216 6.899 12.504 8.003 ;
     RECT  2.4 7.765 3.048 8.483 ;
     RECT  5.1 7.235 5.544 8.533 ;
     RECT  9.456 8.003 12.504 8.579 ;
     RECT  7.8 8.003 8.232 9.011 ;
     RECT  9.456 8.579 11.544 9.155 ;
     RECT  2.4 8.483 2.712 9.541 ;
     RECT  2.4 9.541 3.432 9.637 ;
     RECT  2.16 9.637 3.432 9.923 ;
     RECT  5.1 8.533 5.736 10.213 ;
     RECT  9.552 9.155 11.544 10.307 ;
     RECT  10.5 10.307 11.544 10.883 ;
     RECT  7.8 9.011 8.112 11.941 ;
     RECT  9.504 11.029 9.528 12.083 ;
     RECT  2.16 9.923 2.712 12.517 ;
     RECT  5.1 10.213 6.312 12.517 ;
     RECT  2.16 12.517 6.312 12.805 ;
     RECT  7.536 11.941 8.112 12.805 ;
     RECT  2.16 12.805 8.112 12.949 ;
     RECT  10.5 10.883 10.812 12.969 ;
     RECT  10.5 12.969 10.62 12.983 ;
     RECT  2.16 12.949 8.232 15.056 ;
  END
END dsfd_rly_63_NS

VERSION 5.8 ;
BUSBITCHARS "[]" ;
DIVIDERCHAR "/" ;
UNITS
    DATABASE MICRONS 1000 ;
END UNITS

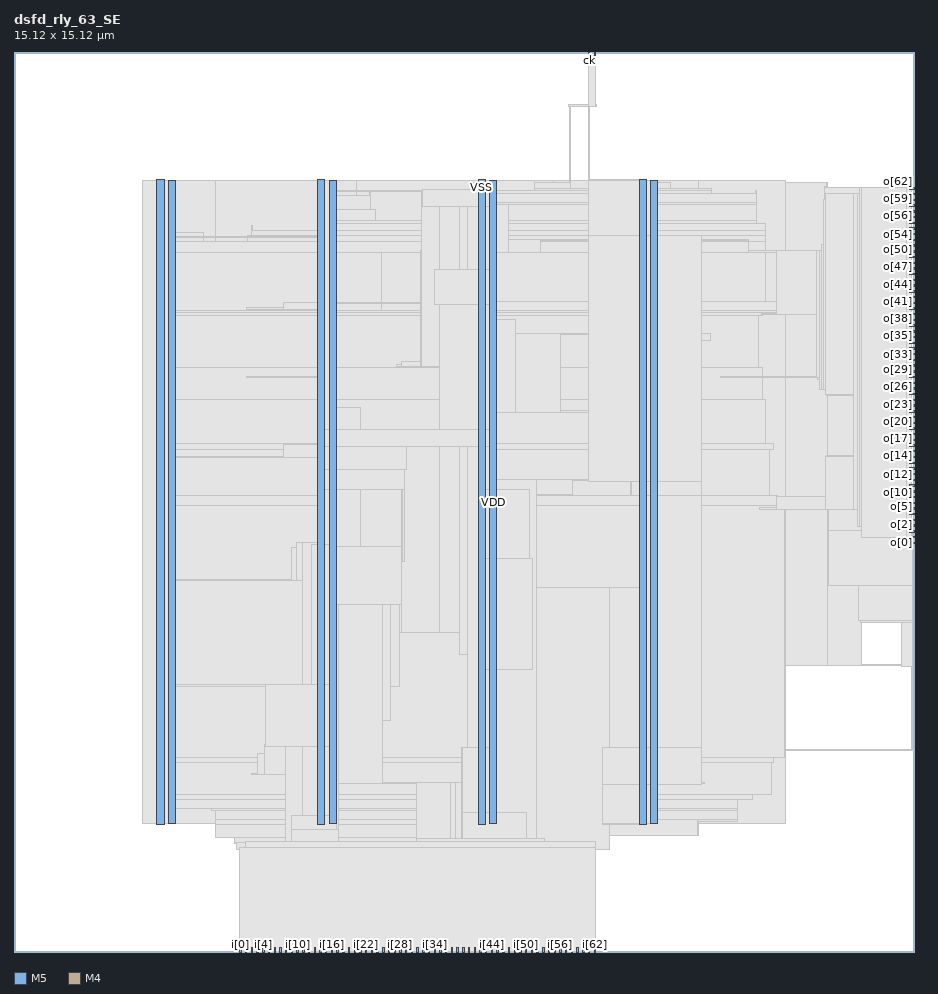
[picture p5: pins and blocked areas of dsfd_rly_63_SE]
MACRO dsfd_rly_63_SE
  FOREIGN dsfd_rly_63_SE 0 0 ;
  CLASS BLOCK ;
  SIZE 15.12 BY 15.12 ;
  PIN ck
    DIRECTION INPUT ;
    USE SIGNAL ;
    PORT
      LAYER M5 ;
        RECT  9.648 15.036 9.672 15.12 ;
    END
  END ck
  PIN i[0]
    DIRECTION INPUT ;
    USE SIGNAL ;
    PORT
      LAYER M5 ;
        RECT  3.792 0 3.816 0.084 ;
    END
  END i[0]
  PIN i[10]
    DIRECTION INPUT ;
    USE SIGNAL ;
    PORT
      LAYER M5 ;
        RECT  4.752 0 4.776 0.084 ;
    END
  END i[10]
  PIN i[11]
    DIRECTION INPUT ;
    USE SIGNAL ;
    PORT
      LAYER M5 ;
        RECT  4.848 0 4.872 0.084 ;
    END
  END i[11]
  PIN i[12]
    DIRECTION INPUT ;
    USE SIGNAL ;
    PORT
      LAYER M5 ;
        RECT  4.944 0 4.968 0.084 ;
    END
  END i[12]
  PIN i[13]
    DIRECTION INPUT ;
    USE SIGNAL ;
    PORT
      LAYER M5 ;
        RECT  5.04 0 5.064 0.084 ;
    END
  END i[13]
  PIN i[14]
    DIRECTION INPUT ;
    USE SIGNAL ;
    PORT
      LAYER M5 ;
        RECT  5.136 0 5.16 0.084 ;
    END
  END i[14]
  PIN i[15]
    DIRECTION INPUT ;
    USE SIGNAL ;
    PORT
      LAYER M5 ;
        RECT  5.232 0 5.256 0.084 ;
    END
  END i[15]
  PIN i[16]
    DIRECTION INPUT ;
    USE SIGNAL ;
    PORT
      LAYER M5 ;
        RECT  5.328 0 5.352 0.084 ;
    END
  END i[16]
  PIN i[17]
    DIRECTION INPUT ;
    USE SIGNAL ;
    PORT
      LAYER M5 ;
        RECT  5.424 0 5.448 0.084 ;
    END
  END i[17]
  PIN i[18]
    DIRECTION INPUT ;
    USE SIGNAL ;
    PORT
      LAYER M5 ;
        RECT  5.52 0 5.544 0.084 ;
    END
  END i[18]
  PIN i[19]
    DIRECTION INPUT ;
    USE SIGNAL ;
    PORT
      LAYER M5 ;
        RECT  5.616 0 5.64 0.084 ;
    END
  END i[19]
  PIN i[1]
    DIRECTION INPUT ;
    USE SIGNAL ;
    PORT
      LAYER M5 ;
        RECT  3.888 0 3.912 0.084 ;
    END
  END i[1]
  PIN i[20]
    DIRECTION INPUT ;
    USE SIGNAL ;
    PORT
      LAYER M5 ;
        RECT  5.712 0 5.736 0.084 ;
    END
  END i[20]
  PIN i[21]
    DIRECTION INPUT ;
    USE SIGNAL ;
    PORT
      LAYER M5 ;
        RECT  5.808 0 5.832 0.084 ;
    END
  END i[21]
  PIN i[22]
    DIRECTION INPUT ;
    USE SIGNAL ;
    PORT
      LAYER M5 ;
        RECT  5.904 0 5.928 0.084 ;
    END
  END i[22]
  PIN i[23]
    DIRECTION INPUT ;
    USE SIGNAL ;
    PORT
      LAYER M5 ;
        RECT  6 0 6.024 0.084 ;
    END
  END i[23]
  PIN i[24]
    DIRECTION INPUT ;
    USE SIGNAL ;
    PORT
      LAYER M5 ;
        RECT  6.096 0 6.12 0.084 ;
    END
  END i[24]
  PIN i[25]
    DIRECTION INPUT ;
    USE SIGNAL ;
    PORT
      LAYER M5 ;
        RECT  6.192 0 6.216 0.084 ;
    END
  END i[25]
  PIN i[26]
    DIRECTION INPUT ;
    USE SIGNAL ;
    PORT
      LAYER M5 ;
        RECT  6.288 0 6.312 0.084 ;
    END
  END i[26]
  PIN i[27]
    DIRECTION INPUT ;
    USE SIGNAL ;
    PORT
      LAYER M5 ;
        RECT  6.384 0 6.408 0.084 ;
    END
  END i[27]
  PIN i[28]
    DIRECTION INPUT ;
    USE SIGNAL ;
    PORT
      LAYER M5 ;
        RECT  6.48 0 6.504 0.084 ;
    END
  END i[28]
  PIN i[29]
    DIRECTION INPUT ;
    USE SIGNAL ;
    PORT
      LAYER M5 ;
        RECT  6.576 0 6.6 0.084 ;
    END
  END i[29]
  PIN i[2]
    DIRECTION INPUT ;
    USE SIGNAL ;
    PORT
      LAYER M5 ;
        RECT  3.984 0 4.008 0.084 ;
    END
  END i[2]
  PIN i[30]
    DIRECTION INPUT ;
    USE SIGNAL ;
    PORT
      LAYER M5 ;
        RECT  6.672 0 6.696 0.084 ;
    END
  END i[30]
  PIN i[31]
    DIRECTION INPUT ;
    USE SIGNAL ;
    PORT
      LAYER M5 ;
        RECT  6.768 0 6.792 0.084 ;
    END
  END i[31]
  PIN i[32]
    DIRECTION INPUT ;
    USE SIGNAL ;
    PORT
      LAYER M5 ;
        RECT  6.864 0 6.888 0.084 ;
    END
  END i[32]
  PIN i[33]
    DIRECTION INPUT ;
    USE SIGNAL ;
    PORT
      LAYER M5 ;
        RECT  6.96 0 6.984 0.084 ;
    END
  END i[33]
  PIN i[34]
    DIRECTION INPUT ;
    USE SIGNAL ;
    PORT
      LAYER M5 ;
        RECT  7.056 0 7.08 0.084 ;
    END
  END i[34]
  PIN i[35]
    DIRECTION INPUT ;
    USE SIGNAL ;
    PORT
      LAYER M5 ;
        RECT  7.152 0 7.176 0.084 ;
    END
  END i[35]
  PIN i[36]
    DIRECTION INPUT ;
    USE SIGNAL ;
    PORT
      LAYER M5 ;
        RECT  7.248 0 7.272 0.084 ;
    END
  END i[36]
  PIN i[37]
    DIRECTION INPUT ;
    USE SIGNAL ;
    PORT
      LAYER M5 ;
        RECT  7.344 0 7.368 0.084 ;
    END
  END i[37]
  PIN i[38]
    DIRECTION INPUT ;
    USE SIGNAL ;
    PORT
      LAYER M5 ;
        RECT  7.44 0 7.464 0.084 ;
    END
  END i[38]
  PIN i[39]
    DIRECTION INPUT ;
    USE SIGNAL ;
    PORT
      LAYER M5 ;
        RECT  7.536 0 7.56 0.084 ;
    END
  END i[39]
  PIN i[3]
    DIRECTION INPUT ;
    USE SIGNAL ;
    PORT
      LAYER M5 ;
        RECT  4.08 0 4.104 0.084 ;
    END
  END i[3]
  PIN i[40]
    DIRECTION INPUT ;
    USE SIGNAL ;
    PORT
      LAYER M5 ;
        RECT  7.632 0 7.656 0.084 ;
    END
  END i[40]
  PIN i[41]
    DIRECTION INPUT ;
    USE SIGNAL ;
    PORT
      LAYER M5 ;
        RECT  7.728 0 7.752 0.084 ;
    END
  END i[41]
  PIN i[42]
    DIRECTION INPUT ;
    USE SIGNAL ;
    PORT
      LAYER M5 ;
        RECT  7.824 0 7.848 0.084 ;
    END
  END i[42]
  PIN i[43]
    DIRECTION INPUT ;
    USE SIGNAL ;
    PORT
      LAYER M5 ;
        RECT  7.92 0 7.944 0.084 ;
    END
  END i[43]
  PIN i[44]
    DIRECTION INPUT ;
    USE SIGNAL ;
    PORT
      LAYER M5 ;
        RECT  8.016 0 8.04 0.084 ;
    END
  END i[44]
  PIN i[45]
    DIRECTION INPUT ;
    USE SIGNAL ;
    PORT
      LAYER M5 ;
        RECT  8.112 0 8.136 0.084 ;
    END
  END i[45]
  PIN i[46]
    DIRECTION INPUT ;
    USE SIGNAL ;
    PORT
      LAYER M5 ;
        RECT  8.208 0 8.232 0.084 ;
    END
  END i[46]
  PIN i[47]
    DIRECTION INPUT ;
    USE SIGNAL ;
    PORT
      LAYER M5 ;
        RECT  8.304 0 8.328 0.084 ;
    END
  END i[47]
  PIN i[48]
    DIRECTION INPUT ;
    USE SIGNAL ;
    PORT
      LAYER M5 ;
        RECT  8.4 0 8.424 0.084 ;
    END
  END i[48]
  PIN i[49]
    DIRECTION INPUT ;
    USE SIGNAL ;
    PORT
      LAYER M5 ;
        RECT  8.496 0 8.52 0.084 ;
    END
  END i[49]
  PIN i[4]
    DIRECTION INPUT ;
    USE SIGNAL ;
    PORT
      LAYER M5 ;
        RECT  4.176 0 4.2 0.084 ;
    END
  END i[4]
  PIN i[50]
    DIRECTION INPUT ;
    USE SIGNAL ;
    PORT
      LAYER M5 ;
        RECT  8.592 0 8.616 0.084 ;
    END
  END i[50]
  PIN i[51]
    DIRECTION INPUT ;
    USE SIGNAL ;
    PORT
      LAYER M5 ;
        RECT  8.688 0 8.712 0.084 ;
    END
  END i[51]
  PIN i[52]
    DIRECTION INPUT ;
    USE SIGNAL ;
    PORT
      LAYER M5 ;
        RECT  8.784 0 8.808 0.084 ;
    END
  END i[52]
  PIN i[53]
    DIRECTION INPUT ;
    USE SIGNAL ;
    PORT
      LAYER M5 ;
        RECT  8.88 0 8.904 0.084 ;
    END
  END i[53]
  PIN i[54]
    DIRECTION INPUT ;
    USE SIGNAL ;
    PORT
      LAYER M5 ;
        RECT  8.976 0 9 0.084 ;
    END
  END i[54]
  PIN i[55]
    DIRECTION INPUT ;
    USE SIGNAL ;
    PORT
      LAYER M5 ;
        RECT  9.072 0 9.096 0.084 ;
    END
  END i[55]
  PIN i[56]
    DIRECTION INPUT ;
    USE SIGNAL ;
    PORT
      LAYER M5 ;
        RECT  9.168 0 9.192 0.084 ;
    END
  END i[56]
  PIN i[57]
    DIRECTION INPUT ;
    USE SIGNAL ;
    PORT
      LAYER M5 ;
        RECT  9.264 0 9.288 0.084 ;
    END
  END i[57]
  PIN i[58]
    DIRECTION INPUT ;
    USE SIGNAL ;
    PORT
      LAYER M5 ;
        RECT  9.36 0 9.384 0.084 ;
    END
  END i[58]
  PIN i[59]
    DIRECTION INPUT ;
    USE SIGNAL ;
    PORT
      LAYER M5 ;
        RECT  9.456 0 9.48 0.084 ;
    END
  END i[59]
  PIN i[5]
    DIRECTION INPUT ;
    USE SIGNAL ;
    PORT
      LAYER M5 ;
        RECT  4.272 0 4.296 0.084 ;
    END
  END i[5]
  PIN i[60]
    DIRECTION INPUT ;
    USE SIGNAL ;
    PORT
      LAYER M5 ;
        RECT  9.552 0 9.576 0.084 ;
    END
  END i[60]
  PIN i[61]
    DIRECTION INPUT ;
    USE SIGNAL ;
    PORT
      LAYER M5 ;
        RECT  9.648 0 9.672 0.084 ;
    END
  END i[61]
  PIN i[62]
    DIRECTION INPUT ;
    USE SIGNAL ;
    PORT
      LAYER M5 ;
        RECT  9.744 0 9.768 0.084 ;
    END
  END i[62]
  PIN i[6]
    DIRECTION INPUT ;
    USE SIGNAL ;
    PORT
      LAYER M5 ;
        RECT  4.368 0 4.392 0.084 ;
    END
  END i[6]
  PIN i[7]
    DIRECTION INPUT ;
    USE SIGNAL ;
    PORT
      LAYER M5 ;
        RECT  4.464 0 4.488 0.084 ;
    END
  END i[7]
  PIN i[8]
    DIRECTION INPUT ;
    USE SIGNAL ;
    PORT
      LAYER M5 ;
        RECT  4.56 0 4.584 0.084 ;
    END
  END i[8]
  PIN i[9]
    DIRECTION INPUT ;
    USE SIGNAL ;
    PORT
      LAYER M5 ;
        RECT  4.656 0 4.68 0.084 ;
    END
  END i[9]
  PIN o[0]
    DIRECTION OUTPUT ;
    USE SIGNAL ;
    PORT
      LAYER M4 ;
        RECT  15.036 6.864 15.12 6.888 ;
    END
  END o[0]
  PIN o[10]
    DIRECTION OUTPUT ;
    USE SIGNAL ;
    PORT
      LAYER M4 ;
        RECT  15.036 7.824 15.12 7.848 ;
    END
  END o[10]
  PIN o[11]
    DIRECTION OUTPUT ;
    USE SIGNAL ;
    PORT
      LAYER M4 ;
        RECT  15.036 7.92 15.12 7.944 ;
    END
  END o[11]
  PIN o[12]
    DIRECTION OUTPUT ;
    USE SIGNAL ;
    PORT
      LAYER M4 ;
        RECT  15.036 8.016 15.12 8.04 ;
    END
  END o[12]
  PIN o[13]
    DIRECTION OUTPUT ;
    USE SIGNAL ;
    PORT
      LAYER M4 ;
        RECT  15.036 8.112 15.12 8.136 ;
    END
  END o[13]
  PIN o[14]
    DIRECTION OUTPUT ;
    USE SIGNAL ;
    PORT
      LAYER M4 ;
        RECT  15.036 8.208 15.12 8.232 ;
    END
  END o[14]
  PIN o[15]
    DIRECTION OUTPUT ;
    USE SIGNAL ;
    PORT
      LAYER M4 ;
        RECT  15.036 8.304 15.12 8.328 ;
    END
  END o[15]
  PIN o[16]
    DIRECTION OUTPUT ;
    USE SIGNAL ;
    PORT
      LAYER M4 ;
        RECT  15.036 8.4 15.12 8.424 ;
    END
  END o[16]
  PIN o[17]
    DIRECTION OUTPUT ;
    USE SIGNAL ;
    PORT
      LAYER M4 ;
        RECT  15.036 8.496 15.12 8.52 ;
    END
  END o[17]
  PIN o[18]
    DIRECTION OUTPUT ;
    USE SIGNAL ;
    PORT
      LAYER M4 ;
        RECT  15.036 8.592 15.12 8.616 ;
    END
  END o[18]
  PIN o[19]
    DIRECTION OUTPUT ;
    USE SIGNAL ;
    PORT
      LAYER M4 ;
        RECT  15.036 8.688 15.12 8.712 ;
    END
  END o[19]
  PIN o[1]
    DIRECTION OUTPUT ;
    USE SIGNAL ;
    PORT
      LAYER M4 ;
        RECT  15.036 6.96 15.12 6.984 ;
    END
  END o[1]
  PIN o[20]
    DIRECTION OUTPUT ;
    USE SIGNAL ;
    PORT
      LAYER M4 ;
        RECT  15.036 8.784 15.12 8.808 ;
    END
  END o[20]
  PIN o[21]
    DIRECTION OUTPUT ;
    USE SIGNAL ;
    PORT
      LAYER M4 ;
        RECT  15.036 8.88 15.12 8.904 ;
    END
  END o[21]
  PIN o[22]
    DIRECTION OUTPUT ;
    USE SIGNAL ;
    PORT
      LAYER M4 ;
        RECT  15.036 8.976 15.12 9 ;
    END
  END o[22]
  PIN o[23]
    DIRECTION OUTPUT ;
    USE SIGNAL ;
    PORT
      LAYER M4 ;
        RECT  15.036 9.072 15.12 9.096 ;
    END
  END o[23]
  PIN o[24]
    DIRECTION OUTPUT ;
    USE SIGNAL ;
    PORT
      LAYER M4 ;
        RECT  15.036 9.168 15.12 9.192 ;
    END
  END o[24]
  PIN o[25]
    DIRECTION OUTPUT ;
    USE SIGNAL ;
    PORT
      LAYER M4 ;
        RECT  15.036 9.264 15.12 9.288 ;
    END
  END o[25]
  PIN o[26]
    DIRECTION OUTPUT ;
    USE SIGNAL ;
    PORT
      LAYER M4 ;
        RECT  15.036 9.36 15.12 9.384 ;
    END
  END o[26]
  PIN o[27]
    DIRECTION OUTPUT ;
    USE SIGNAL ;
    PORT
      LAYER M4 ;
        RECT  15.036 9.456 15.12 9.48 ;
    END
  END o[27]
  PIN o[28]
    DIRECTION OUTPUT ;
    USE SIGNAL ;
    PORT
      LAYER M4 ;
        RECT  15.036 9.552 15.12 9.576 ;
    END
  END o[28]
  PIN o[29]
    DIRECTION OUTPUT ;
    USE SIGNAL ;
    PORT
      LAYER M4 ;
        RECT  15.036 9.648 15.12 9.672 ;
    END
  END o[29]
  PIN o[2]
    DIRECTION OUTPUT ;
    USE SIGNAL ;
    PORT
      LAYER M4 ;
        RECT  15.036 7.056 15.12 7.08 ;
    END
  END o[2]
  PIN o[30]
    DIRECTION OUTPUT ;
    USE SIGNAL ;
    PORT
      LAYER M4 ;
        RECT  15.036 9.744 15.12 9.768 ;
    END
  END o[30]
  PIN o[31]
    DIRECTION OUTPUT ;
    USE SIGNAL ;
    PORT
      LAYER M4 ;
        RECT  15.036 9.84 15.12 9.864 ;
    END
  END o[31]
  PIN o[32]
    DIRECTION OUTPUT ;
    USE SIGNAL ;
    PORT
      LAYER M4 ;
        RECT  15.036 9.936 15.12 9.96 ;
    END
  END o[32]
  PIN o[33]
    DIRECTION OUTPUT ;
    USE SIGNAL ;
    PORT
      LAYER M4 ;
        RECT  15.036 10.032 15.12 10.056 ;
    END
  END o[33]
  PIN o[34]
    DIRECTION OUTPUT ;
    USE SIGNAL ;
    PORT
      LAYER M4 ;
        RECT  15.036 10.128 15.12 10.152 ;
    END
  END o[34]
  PIN o[35]
    DIRECTION OUTPUT ;
    USE SIGNAL ;
    PORT
      LAYER M4 ;
        RECT  15.036 10.224 15.12 10.248 ;
    END
  END o[35]
  PIN o[36]
    DIRECTION OUTPUT ;
    USE SIGNAL ;
    PORT
      LAYER M4 ;
        RECT  15.036 10.32 15.12 10.344 ;
    END
  END o[36]
  PIN o[37]
    DIRECTION OUTPUT ;
    USE SIGNAL ;
    PORT
      LAYER M4 ;
        RECT  15.036 10.416 15.12 10.44 ;
    END
  END o[37]
  PIN o[38]
    DIRECTION OUTPUT ;
    USE SIGNAL ;
    PORT
      LAYER M4 ;
        RECT  15.036 10.512 15.12 10.536 ;
    END
  END o[38]
  PIN o[39]
    DIRECTION OUTPUT ;
    USE SIGNAL ;
    PORT
      LAYER M4 ;
        RECT  15.036 10.608 15.12 10.632 ;
    END
  END o[39]
  PIN o[3]
    DIRECTION OUTPUT ;
    USE SIGNAL ;
    PORT
      LAYER M4 ;
        RECT  15.036 7.152 15.12 7.176 ;
    END
  END o[3]
  PIN o[40]
    DIRECTION OUTPUT ;
    USE SIGNAL ;
    PORT
      LAYER M4 ;
        RECT  15.036 10.704 15.12 10.728 ;
    END
  END o[40]
  PIN o[41]
    DIRECTION OUTPUT ;
    USE SIGNAL ;
    PORT
      LAYER M4 ;
        RECT  15.036 10.8 15.12 10.824 ;
    END
  END o[41]
  PIN o[42]
    DIRECTION OUTPUT ;
    USE SIGNAL ;
    PORT
      LAYER M4 ;
        RECT  15.036 10.896 15.12 10.92 ;
    END
  END o[42]
  PIN o[43]
    DIRECTION OUTPUT ;
    USE SIGNAL ;
    PORT
      LAYER M4 ;
        RECT  15.036 10.992 15.12 11.016 ;
    END
  END o[43]
  PIN o[44]
    DIRECTION OUTPUT ;
    USE SIGNAL ;
    PORT
      LAYER M4 ;
        RECT  15.036 11.088 15.12 11.112 ;
    END
  END o[44]
  PIN o[45]
    DIRECTION OUTPUT ;
    USE SIGNAL ;
    PORT
      LAYER M4 ;
        RECT  15.036 11.184 15.12 11.208 ;
    END
  END o[45]
  PIN o[46]
    DIRECTION OUTPUT ;
    USE SIGNAL ;
    PORT
      LAYER M4 ;
        RECT  15.036 11.28 15.12 11.304 ;
    END
  END o[46]
  PIN o[47]
    DIRECTION OUTPUT ;
    USE SIGNAL ;
    PORT
      LAYER M4 ;
        RECT  15.036 11.376 15.12 11.4 ;
    END
  END o[47]
  PIN o[48]
    DIRECTION OUTPUT ;
    USE SIGNAL ;
    PORT
      LAYER M4 ;
        RECT  15.036 11.472 15.12 11.496 ;
    END
  END o[48]
  PIN o[49]
    DIRECTION OUTPUT ;
    USE SIGNAL ;
    PORT
      LAYER M4 ;
        RECT  15.036 11.568 15.12 11.592 ;
    END
  END o[49]
  PIN o[4]
    DIRECTION OUTPUT ;
    USE SIGNAL ;
    PORT
      LAYER M4 ;
        RECT  15.036 7.248 15.12 7.272 ;
    END
  END o[4]
  PIN o[50]
    DIRECTION OUTPUT ;
    USE SIGNAL ;
    PORT
      LAYER M4 ;
        RECT  15.036 11.664 15.12 11.688 ;
    END
  END o[50]
  PIN o[51]
    DIRECTION OUTPUT ;
    USE SIGNAL ;
    PORT
      LAYER M4 ;
        RECT  15.036 11.76 15.12 11.784 ;
    END
  END o[51]
  PIN o[52]
    DIRECTION OUTPUT ;
    USE SIGNAL ;
    PORT
      LAYER M4 ;
        RECT  15.036 11.856 15.12 11.88 ;
    END
  END o[52]
  PIN o[53]
    DIRECTION OUTPUT ;
    USE SIGNAL ;
    PORT
      LAYER M4 ;
        RECT  15.036 11.952 15.12 11.976 ;
    END
  END o[53]
  PIN o[54]
    DIRECTION OUTPUT ;
    USE SIGNAL ;
    PORT
      LAYER M4 ;
        RECT  15.036 12.048 15.12 12.072 ;
    END
  END o[54]
  PIN o[55]
    DIRECTION OUTPUT ;
    USE SIGNAL ;
    PORT
      LAYER M4 ;
        RECT  15.036 12.144 15.12 12.168 ;
    END
  END o[55]
  PIN o[56]
    DIRECTION OUTPUT ;
    USE SIGNAL ;
    PORT
      LAYER M4 ;
        RECT  15.036 12.24 15.12 12.264 ;
    END
  END o[56]
  PIN o[57]
    DIRECTION OUTPUT ;
    USE SIGNAL ;
    PORT
      LAYER M4 ;
        RECT  15.036 12.336 15.12 12.36 ;
    END
  END o[57]
  PIN o[58]
    DIRECTION OUTPUT ;
    USE SIGNAL ;
    PORT
      LAYER M4 ;
        RECT  15.036 12.432 15.12 12.456 ;
    END
  END o[58]
  PIN o[59]
    DIRECTION OUTPUT ;
    USE SIGNAL ;
    PORT
      LAYER M4 ;
        RECT  15.036 12.528 15.12 12.552 ;
    END
  END o[59]
  PIN o[5]
    DIRECTION OUTPUT ;
    USE SIGNAL ;
    PORT
      LAYER M4 ;
        RECT  15.036 7.344 15.12 7.368 ;
    END
  END o[5]
  PIN o[60]
    DIRECTION OUTPUT ;
    USE SIGNAL ;
    PORT
      LAYER M4 ;
        RECT  15.036 12.624 15.12 12.648 ;
    END
  END o[60]
  PIN o[61]
    DIRECTION OUTPUT ;
    USE SIGNAL ;
    PORT
      LAYER M4 ;
        RECT  15.036 12.72 15.12 12.744 ;
    END
  END o[61]
  PIN o[62]
    DIRECTION OUTPUT ;
    USE SIGNAL ;
    PORT
      LAYER M4 ;
        RECT  15.036 12.816 15.12 12.84 ;
    END
  END o[62]
  PIN o[6]
    DIRECTION OUTPUT ;
    USE SIGNAL ;
    PORT
      LAYER M4 ;
        RECT  15.036 7.44 15.12 7.464 ;
    END
  END o[6]
  PIN o[7]
    DIRECTION OUTPUT ;
    USE SIGNAL ;
    PORT
      LAYER M4 ;
        RECT  15.036 7.536 15.12 7.56 ;
    END
  END o[7]
  PIN o[8]
    DIRECTION OUTPUT ;
    USE SIGNAL ;
    PORT
      LAYER M4 ;
        RECT  15.036 7.632 15.12 7.656 ;
    END
  END o[8]
  PIN o[9]
    DIRECTION OUTPUT ;
    USE SIGNAL ;
    PORT
      LAYER M4 ;
        RECT  15.036 7.728 15.12 7.752 ;
    END
  END o[9]
  PIN rs
    DIRECTION INPUT ;
    USE SIGNAL ;
    PORT
      LAYER M5 ;
        RECT  9.744 15.036 9.768 15.12 ;
    END
  END rs
  PIN VDD
    DIRECTION INOUT ;
    USE POWER ;
    PORT
      LAYER M5 ;
        RECT  10.692 2.151 10.812 12.969 ;
        RECT  7.992 2.151 8.112 12.969 ;
        RECT  5.292 2.151 5.412 12.969 ;
        RECT  2.592 2.151 2.712 12.969 ;
    END
  END VDD
  PIN VSS
    DIRECTION INOUT ;
    USE GROUND ;
    PORT
      LAYER M5 ;
        RECT  10.5 2.137 10.62 12.983 ;
        RECT  7.8 2.137 7.92 12.983 ;
        RECT  5.1 2.137 5.22 12.983 ;
        RECT  2.4 2.137 2.52 12.983 ;
    END
  END VSS
  OBS
    LAYER RVTN ;
     RECT  2.16 2.16 12.96 2.295 ;
     RECT  2.16 2.565 12.96 2.835 ;
     RECT  2.16 3.105 12.96 3.375 ;
     RECT  2.16 3.645 12.96 3.915 ;
     RECT  2.16 4.185 12.96 4.455 ;
     RECT  2.16 4.725 12.96 4.995 ;
     RECT  2.16 5.265 12.96 5.535 ;
     RECT  2.16 5.805 12.96 6.075 ;
     RECT  2.16 6.345 12.96 6.615 ;
     RECT  2.16 6.885 12.96 7.155 ;
     RECT  2.16 7.425 12.96 7.695 ;
     RECT  2.16 7.965 12.96 8.235 ;
     RECT  2.16 8.505 12.96 8.775 ;
     RECT  2.16 9.045 12.96 9.315 ;
     RECT  2.16 9.585 12.96 9.855 ;
     RECT  2.16 10.125 12.96 10.395 ;
     RECT  2.16 10.665 12.96 10.935 ;
     RECT  2.16 11.205 12.96 11.475 ;
     RECT  2.16 11.745 12.96 12.015 ;
     RECT  2.16 12.285 12.96 12.555 ;
     RECT  2.16 12.825 12.96 12.96 ;
    LAYER RVTP ;
     RECT  2.16 2.295 12.96 2.565 ;
     RECT  2.16 2.835 12.96 3.105 ;
     RECT  2.16 3.375 12.96 3.645 ;
     RECT  2.16 3.915 12.96 4.185 ;
     RECT  2.16 4.455 12.96 4.725 ;
     RECT  2.16 4.995 12.96 5.265 ;
     RECT  2.16 5.535 12.96 5.805 ;
     RECT  2.16 6.075 12.96 6.345 ;
     RECT  2.16 6.615 12.96 6.885 ;
     RECT  2.16 7.155 12.96 7.425 ;
     RECT  2.16 7.695 12.96 7.965 ;
     RECT  2.16 8.235 12.96 8.505 ;
     RECT  2.16 8.775 12.96 9.045 ;
     RECT  2.16 9.315 12.96 9.585 ;
     RECT  2.16 9.855 12.96 10.125 ;
     RECT  2.16 10.395 12.96 10.665 ;
     RECT  2.16 10.935 12.96 11.205 ;
     RECT  2.16 11.475 12.96 11.745 ;
     RECT  2.16 12.015 12.96 12.285 ;
     RECT  2.16 12.555 12.96 12.825 ;
    LAYER M1 ;
     RECT  2.16 2.151 12.96 12.969 ;
    LAYER M2 ;
     RECT  2.16 2.151 3.379 12.969 ;
     RECT  3.379 1.926 5.323 12.969 ;
     RECT  5.323 1.881 5.755 12.969 ;
     RECT  5.755 1.836 9.059 12.969 ;
     RECT  9.059 1.962 11.507 12.969 ;
     RECT  11.507 2.151 12.96 12.969 ;
     RECT  12.96 4.806 13.667 12.924 ;
     RECT  13.667 4.806 14.243 12.78 ;
     RECT  14.243 10.944 14.279 10.962 ;
     RECT  14.243 5.616 14.315 8.262 ;
     RECT  14.243 4.806 14.927 4.824 ;
     RECT  14.315 6.66 14.963 8.262 ;
     RECT  14.963 6.696 14.971 8.262 ;
     RECT  14.315 5.616 15.035 5.634 ;
     RECT  14.971 6.696 15.035 8.334 ;
     RECT  14.243 11.952 15.035 12.654 ;
     RECT  15.035 6.696 15.071 7.074 ;
     RECT  15.035 8.316 15.071 8.334 ;
     RECT  12.96 3.384 15.107 3.402 ;
     RECT  15.071 7.056 15.107 7.074 ;
    LAYER M3 ;
     RECT  8.352 0.091 8.37 0.139 ;
     RECT  4.356 0.091 4.374 0.523 ;
     RECT  3.96 0.523 4.374 0.571 ;
     RECT  7.416 0.091 7.434 0.571 ;
     RECT  8.208 0.139 8.37 0.571 ;
     RECT  8.208 0.571 9.45 0.619 ;
     RECT  5.724 0.571 5.742 1.675 ;
     RECT  3.96 0.571 4.662 1.723 ;
     RECT  5.436 1.675 5.742 1.723 ;
     RECT  7.236 0.571 7.434 1.723 ;
     RECT  8.208 0.619 9.558 1.723 ;
     RECT  3.744 1.723 9.99 1.819 ;
     RECT  3.708 1.819 9.99 1.921 ;
     RECT  3.384 1.921 9.99 2.143 ;
     RECT  11.484 1.957 11.502 2.191 ;
     RECT  3.384 2.143 10.605 2.227 ;
     RECT  11.484 2.191 12.15 2.227 ;
     RECT  3.384 2.227 12.15 2.371 ;
     RECT  2.415 2.143 2.505 2.413 ;
     RECT  3.312 2.371 12.15 2.413 ;
     RECT  2.415 2.413 12.15 2.569 ;
     RECT  2.415 2.569 12.402 2.641 ;
     RECT  2.415 2.641 12.726 3.181 ;
     RECT  2.415 3.181 12.762 3.271 ;
     RECT  15.084 3.379 15.102 4.801 ;
     RECT  14.904 4.801 15.102 5.539 ;
     RECT  14.22 5.539 15.102 5.575 ;
     RECT  14.184 5.575 15.102 6.151 ;
     RECT  13.68 6.151 15.102 7.079 ;
     RECT  2.415 3.271 12.942 7.493 ;
     RECT  2.415 7.493 12.834 7.661 ;
     RECT  13.68 7.079 15.066 8.299 ;
     RECT  13.644 8.299 15.066 8.339 ;
     RECT  2.415 7.661 12.69 8.437 ;
     RECT  2.415 8.437 12.762 8.537 ;
     RECT  14.112 8.339 15.03 9.005 ;
     RECT  2.415 8.537 12.618 9.275 ;
     RECT  14.112 9.005 14.994 9.355 ;
     RECT  13.644 9.355 14.994 9.451 ;
     RECT  13.536 9.451 14.994 9.625 ;
     RECT  13.5 9.625 14.994 9.773 ;
     RECT  2.415 9.275 12.582 9.815 ;
     RECT  13.5 9.773 14.31 9.965 ;
     RECT  13.5 9.965 14.238 10.541 ;
     RECT  2.415 9.815 12.51 10.699 ;
     RECT  2.415 10.699 12.582 10.741 ;
     RECT  2.415 10.741 12.834 10.769 ;
     RECT  6.912 10.769 12.834 10.925 ;
     RECT  13.608 10.541 14.238 10.939 ;
     RECT  2.415 10.769 6.174 11.755 ;
     RECT  6.912 10.925 12.618 11.755 ;
     RECT  13.608 10.939 14.274 11.776 ;
     RECT  13.572 11.776 14.274 11.885 ;
     RECT  2.415 11.755 12.618 11.939 ;
     RECT  3.924 11.939 12.618 12.029 ;
     RECT  2.415 11.939 3.186 12.083 ;
     RECT  3.996 12.029 12.618 12.119 ;
     RECT  3.996 12.119 4.014 12.209 ;
     RECT  5.115 12.119 12.618 12.245 ;
     RECT  5.115 12.245 12.474 12.281 ;
     RECT  13.608 11.885 14.274 12.365 ;
     RECT  5.115 12.281 6.066 12.479 ;
     RECT  6.876 12.281 12.474 12.557 ;
     RECT  7.668 12.557 12.474 12.587 ;
     RECT  15.012 11.947 15.03 12.659 ;
     RECT  2.415 12.083 2.697 12.707 ;
     RECT  5.115 12.479 5.994 12.707 ;
     RECT  6.876 12.557 6.894 12.749 ;
     RECT  7.704 12.587 12.474 12.749 ;
     RECT  7.704 12.749 11.718 12.785 ;
     RECT  12.456 12.749 12.474 12.785 ;
     RECT  5.976 12.707 5.994 12.797 ;
     RECT  8.748 12.785 11.718 12.821 ;
     RECT  13.608 12.365 14.238 12.845 ;
     RECT  13.608 12.845 13.662 12.857 ;
     RECT  7.704 12.785 7.905 12.929 ;
     RECT  8.748 12.821 9.342 12.929 ;
     RECT  10.515 12.821 11.034 12.929 ;
     RECT  13.644 12.857 13.662 12.929 ;
     RECT  2.415 12.707 2.505 12.977 ;
     RECT  5.115 12.707 5.205 12.977 ;
     RECT  7.815 12.929 7.905 12.977 ;
     RECT  10.515 12.929 10.605 12.977 ;
     RECT  9.324 12.929 9.342 14.237 ;
    LAYER M4 ;
     RECT  2.408 2.148 2.512 12.972 ;
     RECT  2.512 2.418 2.704 12.702 ;
     RECT  3.697 1.824 3.733 1.848 ;
     RECT  3.949 0.528 4.057 0.552 ;
     RECT  3.985 2.976 4.093 3 ;
     RECT  4.093 2.976 4.213 3.336 ;
     RECT  4.057 0.528 4.345 0.6 ;
     RECT  2.704 8.304 4.525 8.328 ;
     RECT  3.913 10.8 4.525 10.824 ;
     RECT  3.733 1.728 4.561 1.848 ;
     RECT  4.213 2.976 4.561 3.48 ;
     RECT  2.704 6.24 4.669 6.264 ;
     RECT  4.669 6.24 4.741 6.792 ;
     RECT  4.561 1.728 4.849 3.48 ;
     RECT  2.704 4.464 4.849 4.488 ;
     RECT  4.741 6.24 4.849 6.888 ;
     RECT  4.345 0.096 4.883 0.6 ;
     RECT  4.849 1.728 5.108 6.888 ;
     RECT  4.525 8.304 5.108 8.52 ;
     RECT  3.913 9.648 5.108 9.672 ;
     RECT  4.525 10.8 5.108 10.92 ;
     RECT  2.704 12 5.108 12.024 ;
     RECT  5.108 1.728 5.212 12.972 ;
     RECT  5.212 1.728 5.317 12.792 ;
     RECT  5.317 1.68 5.404 12.792 ;
     RECT  5.404 1.68 5.459 5.832 ;
     RECT  5.459 1.68 5.465 1.848 ;
     RECT  4.883 0.576 5.753 0.6 ;
     RECT  5.404 6.816 5.825 9.144 ;
     RECT  5.459 2.832 6.185 5.832 ;
     RECT  6.185 3.888 6.329 5.832 ;
     RECT  6.329 4.464 6.473 5.832 ;
     RECT  6.433 9.84 6.505 9.864 ;
     RECT  6.473 5.376 6.517 5.832 ;
     RECT  5.825 6.816 6.517 8.76 ;
     RECT  5.465 1.728 6.757 1.848 ;
     RECT  6.185 2.832 6.757 2.856 ;
     RECT  6.505 9.84 6.829 9.912 ;
     RECT  5.404 10.896 6.829 10.92 ;
     RECT  6.829 9.84 6.853 11.784 ;
     RECT  5.404 12.768 6.853 12.792 ;
     RECT  6.517 5.376 7.141 8.76 ;
     RECT  6.853 9.84 7.141 12.792 ;
     RECT  7.225 0.576 7.309 0.6 ;
     RECT  6.757 1.728 7.333 2.856 ;
     RECT  7.333 1.152 7.417 2.856 ;
     RECT  7.141 5.376 7.477 12.792 ;
     RECT  7.417 1.728 7.525 2.856 ;
     RECT  7.525 1.728 7.621 3.432 ;
     RECT  7.477 4.992 7.621 12.792 ;
     RECT  7.621 1.728 7.808 12.792 ;
     RECT  7.808 1.728 7.912 12.972 ;
     RECT  7.912 1.728 8.104 12.702 ;
     RECT  8.104 11.76 8.309 12.552 ;
     RECT  7.405 0.096 8.381 0.168 ;
     RECT  8.104 9.072 8.417 10.632 ;
     RECT  8.104 1.728 8.777 7.944 ;
     RECT  8.309 11.76 8.849 11.976 ;
     RECT  8.417 9.072 9.173 10.392 ;
     RECT  8.777 7.68 9.389 7.944 ;
     RECT  8.485 0.576 9.505 0.648 ;
     RECT  9.505 0.624 9.613 0.648 ;
     RECT  9.313 14.208 9.779 14.232 ;
     RECT  8.777 1.728 10.001 6.12 ;
     RECT  9.173 10.368 10.22 10.392 ;
     RECT  10.22 10.128 10.261 10.392 ;
     RECT  9.389 7.92 10.357 7.944 ;
     RECT  9.173 9.072 10.357 9.096 ;
     RECT  10.001 2.148 10.508 6.12 ;
     RECT  10.357 7.68 10.508 7.944 ;
     RECT  10.357 9.024 10.508 9.096 ;
     RECT  10.261 10.128 10.508 10.728 ;
     RECT  8.849 11.952 10.508 11.976 ;
     RECT  10.508 2.148 10.612 12.972 ;
     RECT  10.612 2.418 10.804 12.702 ;
     RECT  10.804 9.024 10.829 10.392 ;
     RECT  10.829 9.792 10.901 10.392 ;
     RECT  10.804 2.832 10.937 2.904 ;
     RECT  10.804 11.952 11.555 12.024 ;
     RECT  10.937 2.832 11.593 2.856 ;
     RECT  10.901 10.272 11.693 10.392 ;
     RECT  11.555 11.952 12.337 11.976 ;
     RECT  12.337 11.76 12.341 11.976 ;
     RECT  12.517 7.44 12.805 7.464 ;
     RECT  12.553 10.704 12.805 10.728 ;
     RECT  12.341 11.76 12.805 11.784 ;
     RECT  11.869 9.648 13.489 9.672 ;
     RECT  12.805 10.704 13.489 11.784 ;
     RECT  13.489 9.648 13.525 11.784 ;
     RECT  13.525 9.456 13.561 11.784 ;
     RECT  13.561 9.456 13.597 11.88 ;
     RECT  12.805 7.44 13.633 7.656 ;
     RECT  13.597 9.456 13.633 12.648 ;
     RECT  13.633 7.44 14.101 8.328 ;
     RECT  13.633 9.36 14.101 12.744 ;
     RECT  14.101 7.44 14.173 12.744 ;
     RECT  14.173 7.152 14.209 12.744 ;
     RECT  14.209 7.152 14.245 12.84 ;
     RECT  14.245 6.96 15.001 12.84 ;
     RECT  15.001 6.864 15.084 12.84 ;
    LAYER M5 ;
     RECT  3.792 0.016 9.768 1.763 ;
     RECT  3.888 1.763 9.768 1.859 ;
     RECT  6.768 1.859 8.904 1.907 ;
     RECT  4.656 1.859 5.448 2.051 ;
     RECT  2.4 2.137 2.52 2.151 ;
     RECT  9.888 2.137 10.62 2.151 ;
     RECT  4.656 2.051 5.412 2.291 ;
     RECT  7.536 1.907 8.616 2.339 ;
     RECT  9.888 2.151 10.812 2.821 ;
     RECT  7.536 2.339 8.112 3.443 ;
     RECT  9.888 2.821 11.544 3.443 ;
     RECT  5.1 2.291 5.412 3.445 ;
     RECT  4.224 3.445 5.412 4.499 ;
     RECT  7.8 3.443 8.112 4.741 ;
     RECT  7.8 4.741 8.712 6.611 ;
     RECT  4.992 4.499 5.412 6.851 ;
     RECT  10.5 3.443 11.544 7.669 ;
     RECT  7.8 6.611 8.664 7.763 ;
     RECT  5.1 6.851 5.412 7.765 ;
     RECT  6.528 6.565 6.552 7.765 ;
     RECT  10.368 7.669 11.544 7.909 ;
     RECT  5.1 7.765 6.552 8.101 ;
     RECT  5.1 8.101 6.6 8.485 ;
     RECT  7.8 7.763 8.112 8.485 ;
     RECT  5.1 8.485 8.112 8.771 ;
     RECT  7.152 8.771 8.112 10.885 ;
     RECT  7.056 10.885 8.112 11.459 ;
     RECT  9.648 7.909 11.544 12.035 ;
     RECT  7.8 11.459 8.112 12.517 ;
     RECT  6.864 12.517 8.112 12.803 ;
     RECT  2.4 2.151 2.712 12.969 ;
     RECT  5.1 8.771 5.412 12.969 ;
     RECT  7.8 12.803 8.112 12.969 ;
     RECT  9.648 12.035 10.812 12.969 ;
     RECT  2.4 12.969 2.52 12.983 ;
     RECT  5.1 12.969 5.22 12.983 ;
     RECT  7.8 12.969 7.92 12.983 ;
     RECT  9.648 12.969 10.62 12.983 ;
     RECT  9.648 12.983 9.672 14.197 ;
     RECT  9.648 14.197 9.768 15.056 ;
  END
END dsfd_rly_63_SE

VERSION 5.8 ;
BUSBITCHARS "[]" ;
DIVIDERCHAR "/" ;
UNITS
    DATABASE MICRONS 1000 ;
END UNITS

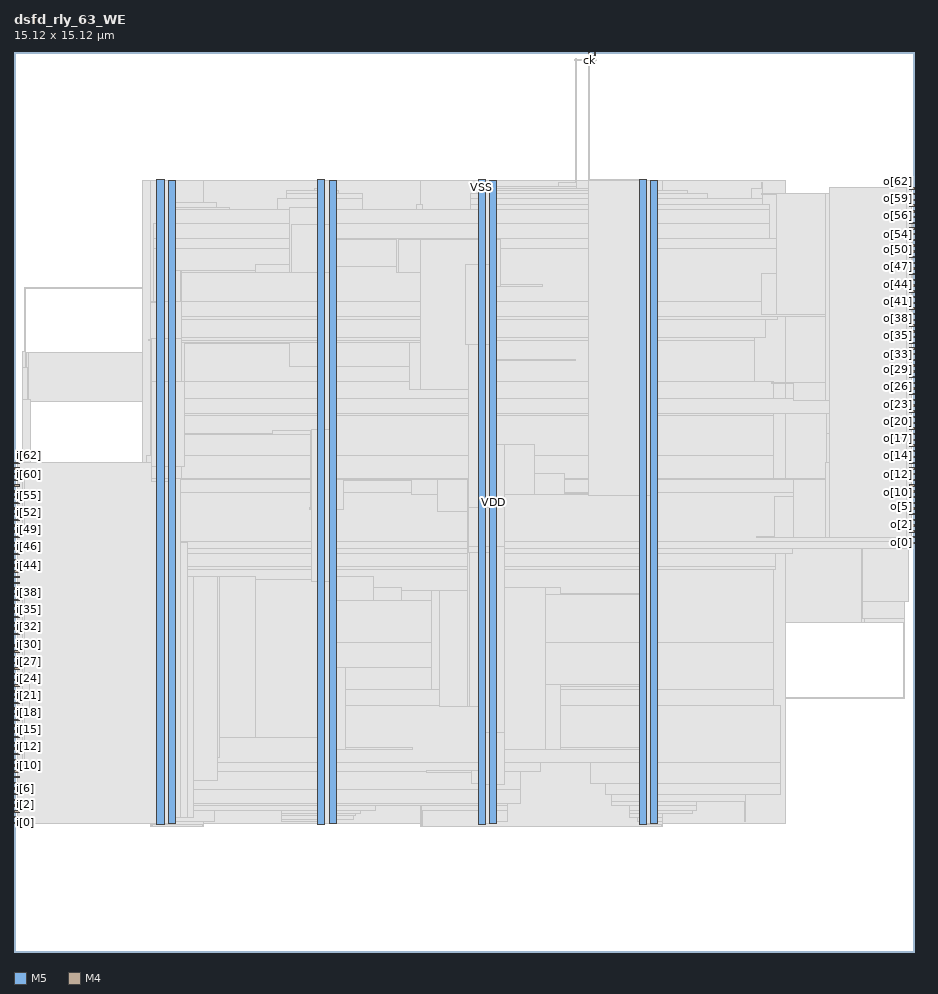
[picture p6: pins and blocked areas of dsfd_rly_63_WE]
MACRO dsfd_rly_63_WE
  FOREIGN dsfd_rly_63_WE 0 0 ;
  CLASS BLOCK ;
  SIZE 15.12 BY 15.12 ;
  PIN ck
    DIRECTION INPUT ;
    USE SIGNAL ;
    PORT
      LAYER M5 ;
        RECT  9.648 15.036 9.672 15.12 ;
    END
  END ck
  PIN i[0]
    DIRECTION INPUT ;
    USE SIGNAL ;
    PORT
      LAYER M4 ;
        RECT  0 2.16 0.084 2.184 ;
    END
  END i[0]
  PIN i[10]
    DIRECTION INPUT ;
    USE SIGNAL ;
    PORT
      LAYER M4 ;
        RECT  0 3.12 0.084 3.144 ;
    END
  END i[10]
  PIN i[11]
    DIRECTION INPUT ;
    USE SIGNAL ;
    PORT
      LAYER M4 ;
        RECT  0 3.216 0.084 3.24 ;
    END
  END i[11]
  PIN i[12]
    DIRECTION INPUT ;
    USE SIGNAL ;
    PORT
      LAYER M4 ;
        RECT  0 3.312 0.084 3.336 ;
    END
  END i[12]
  PIN i[13]
    DIRECTION INPUT ;
    USE SIGNAL ;
    PORT
      LAYER M4 ;
        RECT  0 3.408 0.084 3.432 ;
    END
  END i[13]
  PIN i[14]
    DIRECTION INPUT ;
    USE SIGNAL ;
    PORT
      LAYER M4 ;
        RECT  0 3.504 0.084 3.528 ;
    END
  END i[14]
  PIN i[15]
    DIRECTION INPUT ;
    USE SIGNAL ;
    PORT
      LAYER M4 ;
        RECT  0 3.6 0.084 3.624 ;
    END
  END i[15]
  PIN i[16]
    DIRECTION INPUT ;
    USE SIGNAL ;
    PORT
      LAYER M4 ;
        RECT  0 3.696 0.084 3.72 ;
    END
  END i[16]
  PIN i[17]
    DIRECTION INPUT ;
    USE SIGNAL ;
    PORT
      LAYER M4 ;
        RECT  0 3.792 0.084 3.816 ;
    END
  END i[17]
  PIN i[18]
    DIRECTION INPUT ;
    USE SIGNAL ;
    PORT
      LAYER M4 ;
        RECT  0 3.888 0.084 3.912 ;
    END
  END i[18]
  PIN i[19]
    DIRECTION INPUT ;
    USE SIGNAL ;
    PORT
      LAYER M4 ;
        RECT  0 3.984 0.084 4.008 ;
    END
  END i[19]
  PIN i[1]
    DIRECTION INPUT ;
    USE SIGNAL ;
    PORT
      LAYER M4 ;
        RECT  0 2.256 0.084 2.28 ;
    END
  END i[1]
  PIN i[20]
    DIRECTION INPUT ;
    USE SIGNAL ;
    PORT
      LAYER M4 ;
        RECT  0 4.08 0.084 4.104 ;
    END
  END i[20]
  PIN i[21]
    DIRECTION INPUT ;
    USE SIGNAL ;
    PORT
      LAYER M4 ;
        RECT  0 4.176 0.084 4.2 ;
    END
  END i[21]
  PIN i[22]
    DIRECTION INPUT ;
    USE SIGNAL ;
    PORT
      LAYER M4 ;
        RECT  0 4.272 0.084 4.296 ;
    END
  END i[22]
  PIN i[23]
    DIRECTION INPUT ;
    USE SIGNAL ;
    PORT
      LAYER M4 ;
        RECT  0 4.368 0.084 4.392 ;
    END
  END i[23]
  PIN i[24]
    DIRECTION INPUT ;
    USE SIGNAL ;
    PORT
      LAYER M4 ;
        RECT  0 4.464 0.084 4.488 ;
    END
  END i[24]
  PIN i[25]
    DIRECTION INPUT ;
    USE SIGNAL ;
    PORT
      LAYER M4 ;
        RECT  0 4.56 0.084 4.584 ;
    END
  END i[25]
  PIN i[26]
    DIRECTION INPUT ;
    USE SIGNAL ;
    PORT
      LAYER M4 ;
        RECT  0 4.656 0.084 4.68 ;
    END
  END i[26]
  PIN i[27]
    DIRECTION INPUT ;
    USE SIGNAL ;
    PORT
      LAYER M4 ;
        RECT  0 4.752 0.084 4.776 ;
    END
  END i[27]
  PIN i[28]
    DIRECTION INPUT ;
    USE SIGNAL ;
    PORT
      LAYER M4 ;
        RECT  0 4.848 0.084 4.872 ;
    END
  END i[28]
  PIN i[29]
    DIRECTION INPUT ;
    USE SIGNAL ;
    PORT
      LAYER M4 ;
        RECT  0 4.944 0.084 4.968 ;
    END
  END i[29]
  PIN i[2]
    DIRECTION INPUT ;
    USE SIGNAL ;
    PORT
      LAYER M4 ;
        RECT  0 2.352 0.084 2.376 ;
    END
  END i[2]
  PIN i[30]
    DIRECTION INPUT ;
    USE SIGNAL ;
    PORT
      LAYER M4 ;
        RECT  0 5.04 0.084 5.064 ;
    END
  END i[30]
  PIN i[31]
    DIRECTION INPUT ;
    USE SIGNAL ;
    PORT
      LAYER M4 ;
        RECT  0 5.136 0.084 5.16 ;
    END
  END i[31]
  PIN i[32]
    DIRECTION INPUT ;
    USE SIGNAL ;
    PORT
      LAYER M4 ;
        RECT  0 5.328 0.084 5.352 ;
    END
  END i[32]
  PIN i[33]
    DIRECTION INPUT ;
    USE SIGNAL ;
    PORT
      LAYER M4 ;
        RECT  0 5.424 0.084 5.448 ;
    END
  END i[33]
  PIN i[34]
    DIRECTION INPUT ;
    USE SIGNAL ;
    PORT
      LAYER M4 ;
        RECT  0 5.52 0.084 5.544 ;
    END
  END i[34]
  PIN i[35]
    DIRECTION INPUT ;
    USE SIGNAL ;
    PORT
      LAYER M4 ;
        RECT  0 5.616 0.084 5.64 ;
    END
  END i[35]
  PIN i[36]
    DIRECTION INPUT ;
    USE SIGNAL ;
    PORT
      LAYER M4 ;
        RECT  0 5.712 0.084 5.736 ;
    END
  END i[36]
  PIN i[37]
    DIRECTION INPUT ;
    USE SIGNAL ;
    PORT
      LAYER M4 ;
        RECT  0 5.808 0.084 5.832 ;
    END
  END i[37]
  PIN i[38]
    DIRECTION INPUT ;
    USE SIGNAL ;
    PORT
      LAYER M4 ;
        RECT  0 5.904 0.084 5.928 ;
    END
  END i[38]
  PIN i[39]
    DIRECTION INPUT ;
    USE SIGNAL ;
    PORT
      LAYER M4 ;
        RECT  0 6 0.084 6.024 ;
    END
  END i[39]
  PIN i[3]
    DIRECTION INPUT ;
    USE SIGNAL ;
    PORT
      LAYER M4 ;
        RECT  0 2.448 0.084 2.472 ;
    END
  END i[3]
  PIN i[40]
    DIRECTION INPUT ;
    USE SIGNAL ;
    PORT
      LAYER M4 ;
        RECT  0 6.096 0.084 6.12 ;
    END
  END i[40]
  PIN i[41]
    DIRECTION INPUT ;
    USE SIGNAL ;
    PORT
      LAYER M4 ;
        RECT  0 6.192 0.084 6.216 ;
    END
  END i[41]
  PIN i[42]
    DIRECTION INPUT ;
    USE SIGNAL ;
    PORT
      LAYER M4 ;
        RECT  0 6.288 0.084 6.312 ;
    END
  END i[42]
  PIN i[43]
    DIRECTION INPUT ;
    USE SIGNAL ;
    PORT
      LAYER M4 ;
        RECT  0 6.384 0.084 6.408 ;
    END
  END i[43]
  PIN i[44]
    DIRECTION INPUT ;
    USE SIGNAL ;
    PORT
      LAYER M4 ;
        RECT  0 6.48 0.084 6.504 ;
    END
  END i[44]
  PIN i[45]
    DIRECTION INPUT ;
    USE SIGNAL ;
    PORT
      LAYER M4 ;
        RECT  0 6.576 0.084 6.6 ;
    END
  END i[45]
  PIN i[46]
    DIRECTION INPUT ;
    USE SIGNAL ;
    PORT
      LAYER M4 ;
        RECT  0 6.672 0.084 6.696 ;
    END
  END i[46]
  PIN i[47]
    DIRECTION INPUT ;
    USE SIGNAL ;
    PORT
      LAYER M4 ;
        RECT  0 6.768 0.084 6.792 ;
    END
  END i[47]
  PIN i[48]
    DIRECTION INPUT ;
    USE SIGNAL ;
    PORT
      LAYER M4 ;
        RECT  0 6.864 0.084 6.888 ;
    END
  END i[48]
  PIN i[49]
    DIRECTION INPUT ;
    USE SIGNAL ;
    PORT
      LAYER M4 ;
        RECT  0 6.96 0.084 6.984 ;
    END
  END i[49]
  PIN i[4]
    DIRECTION INPUT ;
    USE SIGNAL ;
    PORT
      LAYER M4 ;
        RECT  0 2.544 0.084 2.568 ;
    END
  END i[4]
  PIN i[50]
    DIRECTION INPUT ;
    USE SIGNAL ;
    PORT
      LAYER M4 ;
        RECT  0 7.056 0.084 7.08 ;
    END
  END i[50]
  PIN i[51]
    DIRECTION INPUT ;
    USE SIGNAL ;
    PORT
      LAYER M4 ;
        RECT  0 7.152 0.084 7.176 ;
    END
  END i[51]
  PIN i[52]
    DIRECTION INPUT ;
    USE SIGNAL ;
    PORT
      LAYER M4 ;
        RECT  0 7.248 0.084 7.272 ;
    END
  END i[52]
  PIN i[53]
    DIRECTION INPUT ;
    USE SIGNAL ;
    PORT
      LAYER M4 ;
        RECT  0 7.344 0.084 7.368 ;
    END
  END i[53]
  PIN i[54]
    DIRECTION INPUT ;
    USE SIGNAL ;
    PORT
      LAYER M4 ;
        RECT  0 7.44 0.084 7.464 ;
    END
  END i[54]
  PIN i[55]
    DIRECTION INPUT ;
    USE SIGNAL ;
    PORT
      LAYER M4 ;
        RECT  0 7.536 0.084 7.56 ;
    END
  END i[55]
  PIN i[56]
    DIRECTION INPUT ;
    USE SIGNAL ;
    PORT
      LAYER M4 ;
        RECT  0 7.632 0.084 7.656 ;
    END
  END i[56]
  PIN i[57]
    DIRECTION INPUT ;
    USE SIGNAL ;
    PORT
      LAYER M4 ;
        RECT  0 7.728 0.084 7.752 ;
    END
  END i[57]
  PIN i[58]
    DIRECTION INPUT ;
    USE SIGNAL ;
    PORT
      LAYER M4 ;
        RECT  0 7.824 0.084 7.848 ;
    END
  END i[58]
  PIN i[59]
    DIRECTION INPUT ;
    USE SIGNAL ;
    PORT
      LAYER M4 ;
        RECT  0 7.92 0.084 7.944 ;
    END
  END i[59]
  PIN i[5]
    DIRECTION INPUT ;
    USE SIGNAL ;
    PORT
      LAYER M4 ;
        RECT  0 2.64 0.084 2.664 ;
    END
  END i[5]
  PIN i[60]
    DIRECTION INPUT ;
    USE SIGNAL ;
    PORT
      LAYER M4 ;
        RECT  0 8.016 0.084 8.04 ;
    END
  END i[60]
  PIN i[61]
    DIRECTION INPUT ;
    USE SIGNAL ;
    PORT
      LAYER M4 ;
        RECT  0 8.112 0.084 8.136 ;
    END
  END i[61]
  PIN i[62]
    DIRECTION INPUT ;
    USE SIGNAL ;
    PORT
      LAYER M4 ;
        RECT  0 8.208 0.084 8.232 ;
    END
  END i[62]
  PIN i[6]
    DIRECTION INPUT ;
    USE SIGNAL ;
    PORT
      LAYER M4 ;
        RECT  0 2.736 0.084 2.76 ;
    END
  END i[6]
  PIN i[7]
    DIRECTION INPUT ;
    USE SIGNAL ;
    PORT
      LAYER M4 ;
        RECT  0 2.832 0.084 2.856 ;
    END
  END i[7]
  PIN i[8]
    DIRECTION INPUT ;
    USE SIGNAL ;
    PORT
      LAYER M4 ;
        RECT  0 2.928 0.084 2.952 ;
    END
  END i[8]
  PIN i[9]
    DIRECTION INPUT ;
    USE SIGNAL ;
    PORT
      LAYER M4 ;
        RECT  0 3.024 0.084 3.048 ;
    END
  END i[9]
  PIN o[0]
    DIRECTION OUTPUT ;
    USE SIGNAL ;
    PORT
      LAYER M4 ;
        RECT  15.036 6.864 15.12 6.888 ;
    END
  END o[0]
  PIN o[10]
    DIRECTION OUTPUT ;
    USE SIGNAL ;
    PORT
      LAYER M4 ;
        RECT  15.036 7.824 15.12 7.848 ;
    END
  END o[10]
  PIN o[11]
    DIRECTION OUTPUT ;
    USE SIGNAL ;
    PORT
      LAYER M4 ;
        RECT  15.036 7.92 15.12 7.944 ;
    END
  END o[11]
  PIN o[12]
    DIRECTION OUTPUT ;
    USE SIGNAL ;
    PORT
      LAYER M4 ;
        RECT  15.036 8.016 15.12 8.04 ;
    END
  END o[12]
  PIN o[13]
    DIRECTION OUTPUT ;
    USE SIGNAL ;
    PORT
      LAYER M4 ;
        RECT  15.036 8.112 15.12 8.136 ;
    END
  END o[13]
  PIN o[14]
    DIRECTION OUTPUT ;
    USE SIGNAL ;
    PORT
      LAYER M4 ;
        RECT  15.036 8.208 15.12 8.232 ;
    END
  END o[14]
  PIN o[15]
    DIRECTION OUTPUT ;
    USE SIGNAL ;
    PORT
      LAYER M4 ;
        RECT  15.036 8.304 15.12 8.328 ;
    END
  END o[15]
  PIN o[16]
    DIRECTION OUTPUT ;
    USE SIGNAL ;
    PORT
      LAYER M4 ;
        RECT  15.036 8.4 15.12 8.424 ;
    END
  END o[16]
  PIN o[17]
    DIRECTION OUTPUT ;
    USE SIGNAL ;
    PORT
      LAYER M4 ;
        RECT  15.036 8.496 15.12 8.52 ;
    END
  END o[17]
  PIN o[18]
    DIRECTION OUTPUT ;
    USE SIGNAL ;
    PORT
      LAYER M4 ;
        RECT  15.036 8.592 15.12 8.616 ;
    END
  END o[18]
  PIN o[19]
    DIRECTION OUTPUT ;
    USE SIGNAL ;
    PORT
      LAYER M4 ;
        RECT  15.036 8.688 15.12 8.712 ;
    END
  END o[19]
  PIN o[1]
    DIRECTION OUTPUT ;
    USE SIGNAL ;
    PORT
      LAYER M4 ;
        RECT  15.036 6.96 15.12 6.984 ;
    END
  END o[1]
  PIN o[20]
    DIRECTION OUTPUT ;
    USE SIGNAL ;
    PORT
      LAYER M4 ;
        RECT  15.036 8.784 15.12 8.808 ;
    END
  END o[20]
  PIN o[21]
    DIRECTION OUTPUT ;
    USE SIGNAL ;
    PORT
      LAYER M4 ;
        RECT  15.036 8.88 15.12 8.904 ;
    END
  END o[21]
  PIN o[22]
    DIRECTION OUTPUT ;
    USE SIGNAL ;
    PORT
      LAYER M4 ;
        RECT  15.036 8.976 15.12 9 ;
    END
  END o[22]
  PIN o[23]
    DIRECTION OUTPUT ;
    USE SIGNAL ;
    PORT
      LAYER M4 ;
        RECT  15.036 9.072 15.12 9.096 ;
    END
  END o[23]
  PIN o[24]
    DIRECTION OUTPUT ;
    USE SIGNAL ;
    PORT
      LAYER M4 ;
        RECT  15.036 9.168 15.12 9.192 ;
    END
  END o[24]
  PIN o[25]
    DIRECTION OUTPUT ;
    USE SIGNAL ;
    PORT
      LAYER M4 ;
        RECT  15.036 9.264 15.12 9.288 ;
    END
  END o[25]
  PIN o[26]
    DIRECTION OUTPUT ;
    USE SIGNAL ;
    PORT
      LAYER M4 ;
        RECT  15.036 9.36 15.12 9.384 ;
    END
  END o[26]
  PIN o[27]
    DIRECTION OUTPUT ;
    USE SIGNAL ;
    PORT
      LAYER M4 ;
        RECT  15.036 9.456 15.12 9.48 ;
    END
  END o[27]
  PIN o[28]
    DIRECTION OUTPUT ;
    USE SIGNAL ;
    PORT
      LAYER M4 ;
        RECT  15.036 9.552 15.12 9.576 ;
    END
  END o[28]
  PIN o[29]
    DIRECTION OUTPUT ;
    USE SIGNAL ;
    PORT
      LAYER M4 ;
        RECT  15.036 9.648 15.12 9.672 ;
    END
  END o[29]
  PIN o[2]
    DIRECTION OUTPUT ;
    USE SIGNAL ;
    PORT
      LAYER M4 ;
        RECT  15.036 7.056 15.12 7.08 ;
    END
  END o[2]
  PIN o[30]
    DIRECTION OUTPUT ;
    USE SIGNAL ;
    PORT
      LAYER M4 ;
        RECT  15.036 9.744 15.12 9.768 ;
    END
  END o[30]
  PIN o[31]
    DIRECTION OUTPUT ;
    USE SIGNAL ;
    PORT
      LAYER M4 ;
        RECT  15.036 9.84 15.12 9.864 ;
    END
  END o[31]
  PIN o[32]
    DIRECTION OUTPUT ;
    USE SIGNAL ;
    PORT
      LAYER M4 ;
        RECT  15.036 9.936 15.12 9.96 ;
    END
  END o[32]
  PIN o[33]
    DIRECTION OUTPUT ;
    USE SIGNAL ;
    PORT
      LAYER M4 ;
        RECT  15.036 10.032 15.12 10.056 ;
    END
  END o[33]
  PIN o[34]
    DIRECTION OUTPUT ;
    USE SIGNAL ;
    PORT
      LAYER M4 ;
        RECT  15.036 10.128 15.12 10.152 ;
    END
  END o[34]
  PIN o[35]
    DIRECTION OUTPUT ;
    USE SIGNAL ;
    PORT
      LAYER M4 ;
        RECT  15.036 10.224 15.12 10.248 ;
    END
  END o[35]
  PIN o[36]
    DIRECTION OUTPUT ;
    USE SIGNAL ;
    PORT
      LAYER M4 ;
        RECT  15.036 10.32 15.12 10.344 ;
    END
  END o[36]
  PIN o[37]
    DIRECTION OUTPUT ;
    USE SIGNAL ;
    PORT
      LAYER M4 ;
        RECT  15.036 10.416 15.12 10.44 ;
    END
  END o[37]
  PIN o[38]
    DIRECTION OUTPUT ;
    USE SIGNAL ;
    PORT
      LAYER M4 ;
        RECT  15.036 10.512 15.12 10.536 ;
    END
  END o[38]
  PIN o[39]
    DIRECTION OUTPUT ;
    USE SIGNAL ;
    PORT
      LAYER M4 ;
        RECT  15.036 10.608 15.12 10.632 ;
    END
  END o[39]
  PIN o[3]
    DIRECTION OUTPUT ;
    USE SIGNAL ;
    PORT
      LAYER M4 ;
        RECT  15.036 7.152 15.12 7.176 ;
    END
  END o[3]
  PIN o[40]
    DIRECTION OUTPUT ;
    USE SIGNAL ;
    PORT
      LAYER M4 ;
        RECT  15.036 10.704 15.12 10.728 ;
    END
  END o[40]
  PIN o[41]
    DIRECTION OUTPUT ;
    USE SIGNAL ;
    PORT
      LAYER M4 ;
        RECT  15.036 10.8 15.12 10.824 ;
    END
  END o[41]
  PIN o[42]
    DIRECTION OUTPUT ;
    USE SIGNAL ;
    PORT
      LAYER M4 ;
        RECT  15.036 10.896 15.12 10.92 ;
    END
  END o[42]
  PIN o[43]
    DIRECTION OUTPUT ;
    USE SIGNAL ;
    PORT
      LAYER M4 ;
        RECT  15.036 10.992 15.12 11.016 ;
    END
  END o[43]
  PIN o[44]
    DIRECTION OUTPUT ;
    USE SIGNAL ;
    PORT
      LAYER M4 ;
        RECT  15.036 11.088 15.12 11.112 ;
    END
  END o[44]
  PIN o[45]
    DIRECTION OUTPUT ;
    USE SIGNAL ;
    PORT
      LAYER M4 ;
        RECT  15.036 11.184 15.12 11.208 ;
    END
  END o[45]
  PIN o[46]
    DIRECTION OUTPUT ;
    USE SIGNAL ;
    PORT
      LAYER M4 ;
        RECT  15.036 11.28 15.12 11.304 ;
    END
  END o[46]
  PIN o[47]
    DIRECTION OUTPUT ;
    USE SIGNAL ;
    PORT
      LAYER M4 ;
        RECT  15.036 11.376 15.12 11.4 ;
    END
  END o[47]
  PIN o[48]
    DIRECTION OUTPUT ;
    USE SIGNAL ;
    PORT
      LAYER M4 ;
        RECT  15.036 11.472 15.12 11.496 ;
    END
  END o[48]
  PIN o[49]
    DIRECTION OUTPUT ;
    USE SIGNAL ;
    PORT
      LAYER M4 ;
        RECT  15.036 11.568 15.12 11.592 ;
    END
  END o[49]
  PIN o[4]
    DIRECTION OUTPUT ;
    USE SIGNAL ;
    PORT
      LAYER M4 ;
        RECT  15.036 7.248 15.12 7.272 ;
    END
  END o[4]
  PIN o[50]
    DIRECTION OUTPUT ;
    USE SIGNAL ;
    PORT
      LAYER M4 ;
        RECT  15.036 11.664 15.12 11.688 ;
    END
  END o[50]
  PIN o[51]
    DIRECTION OUTPUT ;
    USE SIGNAL ;
    PORT
      LAYER M4 ;
        RECT  15.036 11.76 15.12 11.784 ;
    END
  END o[51]
  PIN o[52]
    DIRECTION OUTPUT ;
    USE SIGNAL ;
    PORT
      LAYER M4 ;
        RECT  15.036 11.856 15.12 11.88 ;
    END
  END o[52]
  PIN o[53]
    DIRECTION OUTPUT ;
    USE SIGNAL ;
    PORT
      LAYER M4 ;
        RECT  15.036 11.952 15.12 11.976 ;
    END
  END o[53]
  PIN o[54]
    DIRECTION OUTPUT ;
    USE SIGNAL ;
    PORT
      LAYER M4 ;
        RECT  15.036 12.048 15.12 12.072 ;
    END
  END o[54]
  PIN o[55]
    DIRECTION OUTPUT ;
    USE SIGNAL ;
    PORT
      LAYER M4 ;
        RECT  15.036 12.144 15.12 12.168 ;
    END
  END o[55]
  PIN o[56]
    DIRECTION OUTPUT ;
    USE SIGNAL ;
    PORT
      LAYER M4 ;
        RECT  15.036 12.24 15.12 12.264 ;
    END
  END o[56]
  PIN o[57]
    DIRECTION OUTPUT ;
    USE SIGNAL ;
    PORT
      LAYER M4 ;
        RECT  15.036 12.336 15.12 12.36 ;
    END
  END o[57]
  PIN o[58]
    DIRECTION OUTPUT ;
    USE SIGNAL ;
    PORT
      LAYER M4 ;
        RECT  15.036 12.432 15.12 12.456 ;
    END
  END o[58]
  PIN o[59]
    DIRECTION OUTPUT ;
    USE SIGNAL ;
    PORT
      LAYER M4 ;
        RECT  15.036 12.528 15.12 12.552 ;
    END
  END o[59]
  PIN o[5]
    DIRECTION OUTPUT ;
    USE SIGNAL ;
    PORT
      LAYER M4 ;
        RECT  15.036 7.344 15.12 7.368 ;
    END
  END o[5]
  PIN o[60]
    DIRECTION OUTPUT ;
    USE SIGNAL ;
    PORT
      LAYER M4 ;
        RECT  15.036 12.624 15.12 12.648 ;
    END
  END o[60]
  PIN o[61]
    DIRECTION OUTPUT ;
    USE SIGNAL ;
    PORT
      LAYER M4 ;
        RECT  15.036 12.72 15.12 12.744 ;
    END
  END o[61]
  PIN o[62]
    DIRECTION OUTPUT ;
    USE SIGNAL ;
    PORT
      LAYER M4 ;
        RECT  15.036 12.816 15.12 12.84 ;
    END
  END o[62]
  PIN o[6]
    DIRECTION OUTPUT ;
    USE SIGNAL ;
    PORT
      LAYER M4 ;
        RECT  15.036 7.44 15.12 7.464 ;
    END
  END o[6]
  PIN o[7]
    DIRECTION OUTPUT ;
    USE SIGNAL ;
    PORT
      LAYER M4 ;
        RECT  15.036 7.536 15.12 7.56 ;
    END
  END o[7]
  PIN o[8]
    DIRECTION OUTPUT ;
    USE SIGNAL ;
    PORT
      LAYER M4 ;
        RECT  15.036 7.632 15.12 7.656 ;
    END
  END o[8]
  PIN o[9]
    DIRECTION OUTPUT ;
    USE SIGNAL ;
    PORT
      LAYER M4 ;
        RECT  15.036 7.728 15.12 7.752 ;
    END
  END o[9]
  PIN rs
    DIRECTION INPUT ;
    USE SIGNAL ;
    PORT
      LAYER M5 ;
        RECT  9.744 15.036 9.768 15.12 ;
    END
  END rs
  PIN VDD
    DIRECTION INOUT ;
    USE POWER ;
    PORT
      LAYER M5 ;
        RECT  10.692 2.151 10.812 12.969 ;
        RECT  7.992 2.151 8.112 12.969 ;
        RECT  5.292 2.151 5.412 12.969 ;
        RECT  2.592 2.151 2.712 12.969 ;
    END
  END VDD
  PIN VSS
    DIRECTION INOUT ;
    USE GROUND ;
    PORT
      LAYER M5 ;
        RECT  10.5 2.137 10.62 12.983 ;
        RECT  7.8 2.137 7.92 12.983 ;
        RECT  5.1 2.137 5.22 12.983 ;
        RECT  2.4 2.137 2.52 12.983 ;
    END
  END VSS
  OBS
    LAYER RVTN ;
     RECT  2.16 2.16 12.96 2.295 ;
     RECT  2.16 2.565 12.96 2.835 ;
     RECT  2.16 3.105 12.96 3.375 ;
     RECT  2.16 3.645 12.96 3.915 ;
     RECT  2.16 4.185 12.96 4.455 ;
     RECT  2.16 4.725 12.96 4.995 ;
     RECT  2.16 5.265 12.96 5.535 ;
     RECT  2.16 5.805 12.96 6.075 ;
     RECT  2.16 6.345 12.96 6.615 ;
     RECT  2.16 6.885 12.96 7.155 ;
     RECT  2.16 7.425 12.96 7.695 ;
     RECT  2.16 7.965 12.96 8.235 ;
     RECT  2.16 8.505 12.96 8.775 ;
     RECT  2.16 9.045 12.96 9.315 ;
     RECT  2.16 9.585 12.96 9.855 ;
     RECT  2.16 10.125 12.96 10.395 ;
     RECT  2.16 10.665 12.96 10.935 ;
     RECT  2.16 11.205 12.96 11.475 ;
     RECT  2.16 11.745 12.96 12.015 ;
     RECT  2.16 12.285 12.96 12.555 ;
     RECT  2.16 12.825 12.96 12.96 ;
    LAYER RVTP ;
     RECT  2.16 2.295 12.96 2.565 ;
     RECT  2.16 2.835 12.96 3.105 ;
     RECT  2.16 3.375 12.96 3.645 ;
     RECT  2.16 3.915 12.96 4.185 ;
     RECT  2.16 4.455 12.96 4.725 ;
     RECT  2.16 4.995 12.96 5.265 ;
     RECT  2.16 5.535 12.96 5.805 ;
     RECT  2.16 6.075 12.96 6.345 ;
     RECT  2.16 6.615 12.96 6.885 ;
     RECT  2.16 7.155 12.96 7.425 ;
     RECT  2.16 7.695 12.96 7.965 ;
     RECT  2.16 8.235 12.96 8.505 ;
     RECT  2.16 8.775 12.96 9.045 ;
     RECT  2.16 9.315 12.96 9.585 ;
     RECT  2.16 9.855 12.96 10.125 ;
     RECT  2.16 10.395 12.96 10.665 ;
     RECT  2.16 10.935 12.96 11.205 ;
     RECT  2.16 11.475 12.96 11.745 ;
     RECT  2.16 12.015 12.96 12.285 ;
     RECT  2.16 12.555 12.96 12.825 ;
    LAYER M1 ;
     RECT  2.16 2.151 12.96 12.969 ;
    LAYER M2 ;
     RECT  0.103 2.268 0.139 2.286 ;
     RECT  0.139 10.062 0.211 10.08 ;
     RECT  0.211 9.792 0.247 10.08 ;
     RECT  0.139 4.662 0.275 4.68 ;
     RECT  0.103 7.938 0.311 7.956 ;
     RECT  0.139 2.268 2.16 2.556 ;
     RECT  0.103 3.312 2.16 3.708 ;
     RECT  2.047 7.704 2.16 7.722 ;
     RECT  0.247 9.252 2.16 10.08 ;
     RECT  0.175 11.142 2.16 11.16 ;
     RECT  2.16 2.151 2.299 12.969 ;
     RECT  2.299 2.106 3.191 12.969 ;
     RECT  3.191 2.151 6.835 12.969 ;
     RECT  6.835 2.106 10.895 12.969 ;
     RECT  10.895 2.151 12.96 12.969 ;
     RECT  12.96 5.544 14.243 12.744 ;
     RECT  14.243 9.396 14.279 11.394 ;
     RECT  14.243 5.544 14.315 8.604 ;
     RECT  14.315 5.886 14.351 8.532 ;
     RECT  14.351 7.398 14.387 8.532 ;
     RECT  14.387 7.434 14.459 8.532 ;
     RECT  14.351 5.886 14.855 6.264 ;
     RECT  12.96 4.266 14.963 4.284 ;
     RECT  14.855 5.886 14.999 6.174 ;
     RECT  14.459 7.821 14.999 8.532 ;
     RECT  14.279 9.396 14.999 10.584 ;
     RECT  14.999 5.886 15.035 5.904 ;
     RECT  14.999 7.938 15.035 8.532 ;
     RECT  14.999 10.476 15.035 10.584 ;
     RECT  14.279 11.376 15.035 11.394 ;
     RECT  15.035 10.566 15.107 10.584 ;
     RECT  15.007 12.222 15.107 12.24 ;
    LAYER M3 ;
     RECT  2.304 2.101 2.322 2.143 ;
     RECT  3.168 2.101 3.186 2.143 ;
     RECT  10.872 2.101 10.89 2.143 ;
     RECT  2.304 2.143 3.186 2.191 ;
     RECT  5.115 2.143 5.205 2.191 ;
     RECT  7.815 2.143 7.905 2.191 ;
     RECT  10.515 2.143 10.89 2.191 ;
     RECT  4.5 2.191 5.205 2.227 ;
     RECT  10.476 2.191 10.89 2.263 ;
     RECT  4.5 2.227 5.706 2.299 ;
     RECT  4.5 2.299 5.742 2.335 ;
     RECT  10.332 2.263 10.89 2.335 ;
     RECT  2.304 2.191 3.366 2.371 ;
     RECT  4.5 2.335 5.814 2.371 ;
     RECT  6.84 2.101 6.858 2.371 ;
     RECT  7.815 2.191 8.298 2.371 ;
     RECT  10.332 2.335 11.394 2.371 ;
     RECT  2.304 2.371 6.066 2.461 ;
     RECT  6.84 2.371 8.298 2.461 ;
     RECT  10.332 2.371 11.466 2.461 ;
     RECT  2.304 2.461 8.298 2.497 ;
     RECT  0.108 2.263 0.126 2.533 ;
     RECT  10.044 2.461 11.466 2.533 ;
     RECT  12.276 2.191 12.294 2.533 ;
     RECT  10.044 2.533 12.294 2.641 ;
     RECT  2.304 2.497 8.514 2.731 ;
     RECT  9.936 2.641 12.87 2.839 ;
     RECT  2.268 2.731 8.514 3.037 ;
     RECT  2.268 3.037 8.838 3.181 ;
     RECT  9.684 2.839 12.87 3.181 ;
     RECT  0.108 2.533 0.162 3.211 ;
     RECT  0.108 3.211 0.342 3.341 ;
     RECT  0.108 3.341 0.198 3.869 ;
     RECT  0.108 3.869 0.126 4.013 ;
     RECT  2.268 3.181 12.87 4.145 ;
     RECT  2.268 4.145 12.762 4.415 ;
     RECT  0.144 4.648 0.162 4.657 ;
     RECT  0.144 4.657 0.27 4.843 ;
     RECT  0.144 4.843 0.342 4.973 ;
     RECT  0.144 4.973 0.162 5.117 ;
     RECT  2.304 4.415 12.762 5.197 ;
     RECT  14.94 4.261 14.958 5.539 ;
     RECT  14.292 5.539 14.958 5.611 ;
     RECT  14.256 5.611 14.958 5.881 ;
     RECT  0.324 5.899 0.342 6.029 ;
     RECT  2.268 5.197 12.762 6.421 ;
     RECT  2.268 6.421 12.798 6.475 ;
     RECT  2.052 6.475 12.798 6.691 ;
     RECT  2.052 6.691 13.086 6.781 ;
     RECT  14.256 5.881 15.03 6.781 ;
     RECT  2.052 6.781 15.03 6.893 ;
     RECT  0.324 7.051 0.342 7.243 ;
     RECT  0.252 7.243 0.342 7.435 ;
     RECT  0.252 7.435 0.378 7.627 ;
     RECT  2.052 6.893 14.994 7.727 ;
     RECT  0.216 7.627 0.378 7.757 ;
     RECT  0.216 7.757 0.306 7.819 ;
     RECT  0.144 7.819 0.306 7.915 ;
     RECT  2.232 7.727 14.994 7.933 ;
     RECT  2.232 7.933 15.03 7.949 ;
     RECT  0.108 7.915 0.306 7.961 ;
     RECT  2.232 7.949 12.762 8.339 ;
     RECT  13.644 7.949 15.03 8.717 ;
     RECT  2.304 8.339 12.762 9.005 ;
     RECT  2.376 9.005 12.762 9.049 ;
     RECT  13.644 8.717 14.994 9.049 ;
     RECT  0.144 7.961 0.27 9.275 ;
     RECT  2.376 9.049 14.994 9.293 ;
     RECT  2.376 9.293 12.762 9.581 ;
     RECT  13.644 9.293 14.994 9.739 ;
     RECT  0.144 9.275 0.234 9.815 ;
     RECT  0.144 9.815 0.198 10.085 ;
     RECT  2.376 9.581 12.438 10.267 ;
     RECT  2.304 10.267 12.438 10.327 ;
     RECT  13.644 9.739 15.03 10.561 ;
     RECT  2.304 10.327 12.618 10.633 ;
     RECT  13.644 10.561 15.102 10.637 ;
     RECT  2.304 10.633 12.834 10.669 ;
     RECT  13.644 10.637 14.274 10.669 ;
     RECT  2.304 10.669 14.274 10.925 ;
     RECT  13.68 10.925 14.274 11.117 ;
     RECT  0.18 10.085 0.198 11.165 ;
     RECT  15.084 10.637 15.102 11.371 ;
     RECT  2.34 10.925 12.834 11.821 ;
     RECT  13.68 11.117 14.238 11.821 ;
     RECT  2.34 11.821 14.238 11.981 ;
     RECT  2.34 11.981 12.69 12.245 ;
     RECT  15.012 11.371 15.102 12.245 ;
     RECT  15.012 12.245 15.03 12.269 ;
     RECT  2.415 12.245 12.69 12.479 ;
     RECT  2.415 12.479 3.618 12.515 ;
     RECT  6.768 12.479 6.858 12.551 ;
     RECT  7.668 12.479 12.69 12.551 ;
     RECT  13.68 11.981 14.238 12.557 ;
     RECT  2.415 12.515 3.402 12.587 ;
     RECT  4.428 12.479 5.85 12.659 ;
     RECT  7.668 12.551 12.582 12.659 ;
     RECT  2.415 12.587 2.697 12.707 ;
     RECT  4.572 12.659 5.85 12.749 ;
     RECT  7.668 12.659 11.646 12.749 ;
     RECT  13.716 12.557 14.238 12.749 ;
     RECT  4.572 12.749 5.454 12.785 ;
     RECT  7.815 12.749 11.322 12.785 ;
     RECT  5.04 12.785 5.205 12.821 ;
     RECT  7.815 12.785 10.605 12.821 ;
     RECT  12.384 12.659 12.582 12.821 ;
     RECT  13.716 12.749 13.734 12.845 ;
     RECT  7.815 12.821 9.45 12.857 ;
     RECT  9.144 12.857 9.45 12.929 ;
     RECT  12.564 12.821 12.582 12.929 ;
     RECT  2.415 12.707 2.505 12.977 ;
     RECT  5.115 12.821 5.205 12.977 ;
     RECT  7.815 12.857 7.905 12.977 ;
     RECT  10.515 12.821 10.605 12.977 ;
     RECT  9.432 12.929 9.45 15.005 ;
    LAYER M4 ;
     RECT  2.252 10.272 2.293 10.296 ;
     RECT  0.06 2.16 2.408 8.232 ;
     RECT  2.293 10.272 2.408 10.92 ;
     RECT  2.408 2.148 2.512 12.972 ;
     RECT  2.512 2.256 2.704 12.702 ;
     RECT  2.704 2.256 2.801 11.448 ;
     RECT  2.801 7.968 2.819 11.448 ;
     RECT  2.819 8.16 2.867 10.248 ;
     RECT  2.801 2.256 2.909 6.888 ;
     RECT  2.909 2.256 3.017 6.312 ;
     RECT  3.017 2.88 3.413 6.312 ;
     RECT  3.413 3.264 3.449 6.312 ;
     RECT  2.819 11.424 4.057 11.448 ;
     RECT  3.449 3.6 4.061 6.312 ;
     RECT  2.867 8.688 4.345 8.712 ;
     RECT  2.867 10.224 4.633 10.248 ;
     RECT  4.057 11.424 4.633 11.544 ;
     RECT  4.957 7.44 4.981 7.464 ;
     RECT  4.345 8.688 4.981 8.76 ;
     RECT  4.061 3.6 5.108 6.264 ;
     RECT  4.981 7.44 5.108 8.76 ;
     RECT  4.633 9.84 5.108 10.248 ;
     RECT  4.633 11.424 5.108 12.504 ;
     RECT  5.108 2.148 5.212 12.972 ;
     RECT  5.212 2.418 5.404 12.702 ;
     RECT  5.404 7.44 5.537 7.944 ;
     RECT  5.404 3.408 5.573 4.776 ;
     RECT  5.404 5.904 6.041 6.312 ;
     RECT  5.404 11.52 6.421 11.976 ;
     RECT  6.041 5.904 6.509 6.12 ;
     RECT  5.404 9.84 6.649 10.248 ;
     RECT  5.537 7.92 6.685 7.944 ;
     RECT  5.573 3.408 6.689 3.432 ;
     RECT  6.649 9.456 6.829 10.248 ;
     RECT  6.421 11.424 6.829 11.976 ;
     RECT  5.573 4.416 7.009 4.776 ;
     RECT  6.509 5.904 7.009 6.072 ;
     RECT  6.685 7.68 7.117 7.944 ;
     RECT  7.009 4.416 7.153 6.072 ;
     RECT  7.153 4.128 7.621 6.072 ;
     RECT  7.117 7.392 7.621 7.944 ;
     RECT  7.621 4.128 7.657 7.944 ;
     RECT  6.937 3.024 7.693 3.048 ;
     RECT  7.693 2.832 7.808 3.048 ;
     RECT  7.657 4.128 7.808 8.04 ;
     RECT  6.829 9.456 7.808 11.976 ;
     RECT  7.808 2.148 7.912 12.972 ;
     RECT  7.912 2.418 8.104 12.702 ;
     RECT  8.104 11.184 8.165 11.976 ;
     RECT  8.104 2.832 8.243 8.52 ;
     RECT  8.243 7.68 8.741 8.52 ;
     RECT  8.165 11.184 8.885 11.208 ;
     RECT  8.243 3.408 8.921 6.12 ;
     RECT  8.921 3.408 9.173 4.488 ;
     RECT  8.921 6 9.173 6.12 ;
     RECT  8.741 7.68 9.245 8.04 ;
     RECT  8.104 9.936 9.425 9.96 ;
     RECT  9.421 14.976 9.779 15 ;
     RECT  9.245 7.68 10.316 7.704 ;
     RECT  10.316 7.68 10.357 7.8 ;
     RECT  9.173 3.408 10.508 3.432 ;
     RECT  9.173 4.464 10.508 4.488 ;
     RECT  9.173 6 10.508 6.024 ;
     RECT  10.357 7.68 10.508 9.048 ;
     RECT  10.357 10.56 10.508 10.584 ;
     RECT  10.508 2.148 10.612 12.972 ;
     RECT  10.612 2.418 10.804 12.702 ;
     RECT  12.481 6.96 12.769 6.984 ;
     RECT  12.553 10.704 12.805 11.4 ;
     RECT  12.553 12.72 12.805 12.744 ;
     RECT  12.769 6.96 13.093 7.656 ;
     RECT  12.733 9.552 13.093 9.576 ;
     RECT  13.093 6.96 13.633 7.944 ;
     RECT  13.093 9.264 13.633 9.576 ;
     RECT  12.805 10.704 13.633 12.744 ;
     RECT  13.633 6.96 13.705 8.232 ;
     RECT  13.633 9.264 13.705 12.744 ;
     RECT  13.705 6.96 15.001 12.84 ;
     RECT  15.001 6.864 15.084 12.84 ;
    LAYER M5 ;
     RECT  2.4 2.137 2.52 2.151 ;
     RECT  5.1 2.137 5.22 2.151 ;
     RECT  7.8 2.137 7.92 2.151 ;
     RECT  10.5 2.137 10.62 2.151 ;
     RECT  7.8 2.151 8.112 2.821 ;
     RECT  7.8 2.821 8.232 3.683 ;
     RECT  0.144 3.061 0.168 4.069 ;
     RECT  0.144 4.069 0.264 4.691 ;
     RECT  0.144 4.691 0.168 6.035 ;
     RECT  5.1 2.151 5.412 6.229 ;
     RECT  7.8 3.683 8.112 6.709 ;
     RECT  7.632 6.709 8.112 6.805 ;
     RECT  7.632 6.805 8.232 7.475 ;
     RECT  10.5 2.151 10.812 7.669 ;
     RECT  2.4 2.151 2.712 7.909 ;
     RECT  2.304 7.909 2.712 7.957 ;
     RECT  0.144 7.141 0.168 8.003 ;
     RECT  2.304 7.957 2.808 8.149 ;
     RECT  4.992 6.229 5.412 8.771 ;
     RECT  2.304 8.149 2.856 9.587 ;
     RECT  7.632 7.475 8.112 10.213 ;
     RECT  2.304 9.587 2.808 10.307 ;
     RECT  2.4 10.307 2.808 10.931 ;
     RECT  5.1 8.771 5.412 11.413 ;
     RECT  7.584 10.213 8.112 11.555 ;
     RECT  6.432 11.413 6.456 11.987 ;
     RECT  4.656 11.413 5.412 12.227 ;
     RECT  2.4 10.931 2.712 12.969 ;
     RECT  5.1 12.227 5.412 12.969 ;
     RECT  7.8 11.555 8.112 12.969 ;
     RECT  9.648 7.669 10.812 12.969 ;
     RECT  2.4 12.969 2.52 12.983 ;
     RECT  5.1 12.969 5.22 12.983 ;
     RECT  7.8 12.969 7.92 12.983 ;
     RECT  9.648 12.969 10.62 12.983 ;
     RECT  9.648 12.983 9.672 14.965 ;
     RECT  9.648 14.965 9.768 15.056 ;
  END
END dsfd_rly_63_WE

VERSION 5.8 ;
BUSBITCHARS "[]" ;
DIVIDERCHAR "/" ;
UNITS
    DATABASE MICRONS 1000 ;
END UNITS

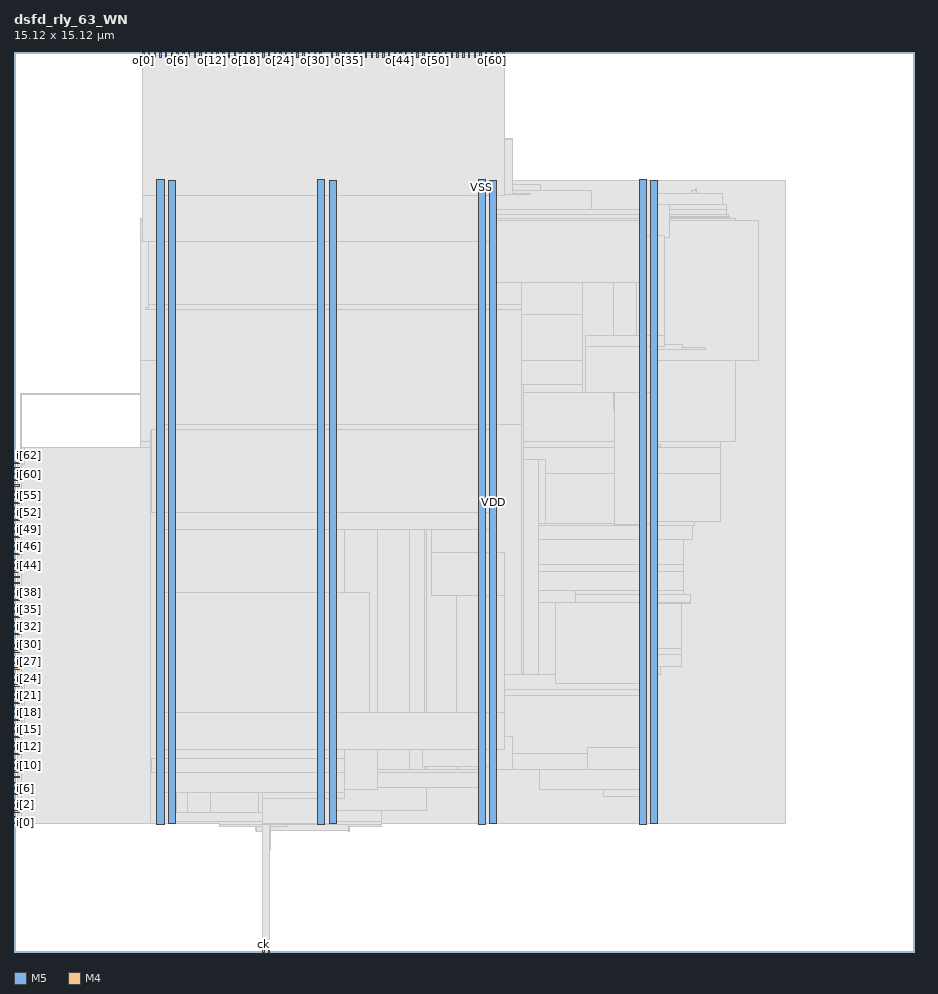
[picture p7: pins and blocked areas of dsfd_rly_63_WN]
MACRO dsfd_rly_63_WN
  FOREIGN dsfd_rly_63_WN 0 0 ;
  CLASS BLOCK ;
  SIZE 15.12 BY 15.12 ;
  PIN ck
    DIRECTION INPUT ;
    USE SIGNAL ;
    PORT
      LAYER M5 ;
        RECT  4.176 0 4.2 0.084 ;
    END
  END ck
  PIN i[0]
    DIRECTION INPUT ;
    USE SIGNAL ;
    PORT
      LAYER M4 ;
        RECT  0 2.16 0.084 2.184 ;
    END
  END i[0]
  PIN i[10]
    DIRECTION INPUT ;
    USE SIGNAL ;
    PORT
      LAYER M4 ;
        RECT  0 3.12 0.084 3.144 ;
    END
  END i[10]
  PIN i[11]
    DIRECTION INPUT ;
    USE SIGNAL ;
    PORT
      LAYER M4 ;
        RECT  0 3.216 0.084 3.24 ;
    END
  END i[11]
  PIN i[12]
    DIRECTION INPUT ;
    USE SIGNAL ;
    PORT
      LAYER M4 ;
        RECT  0 3.312 0.084 3.336 ;
    END
  END i[12]
  PIN i[13]
    DIRECTION INPUT ;
    USE SIGNAL ;
    PORT
      LAYER M4 ;
        RECT  0 3.408 0.084 3.432 ;
    END
  END i[13]
  PIN i[14]
    DIRECTION INPUT ;
    USE SIGNAL ;
    PORT
      LAYER M4 ;
        RECT  0 3.504 0.084 3.528 ;
    END
  END i[14]
  PIN i[15]
    DIRECTION INPUT ;
    USE SIGNAL ;
    PORT
      LAYER M4 ;
        RECT  0 3.6 0.084 3.624 ;
    END
  END i[15]
  PIN i[16]
    DIRECTION INPUT ;
    USE SIGNAL ;
    PORT
      LAYER M4 ;
        RECT  0 3.696 0.084 3.72 ;
    END
  END i[16]
  PIN i[17]
    DIRECTION INPUT ;
    USE SIGNAL ;
    PORT
      LAYER M4 ;
        RECT  0 3.792 0.084 3.816 ;
    END
  END i[17]
  PIN i[18]
    DIRECTION INPUT ;
    USE SIGNAL ;
    PORT
      LAYER M4 ;
        RECT  0 3.888 0.084 3.912 ;
    END
  END i[18]
  PIN i[19]
    DIRECTION INPUT ;
    USE SIGNAL ;
    PORT
      LAYER M4 ;
        RECT  0 3.984 0.084 4.008 ;
    END
  END i[19]
  PIN i[1]
    DIRECTION INPUT ;
    USE SIGNAL ;
    PORT
      LAYER M4 ;
        RECT  0 2.256 0.084 2.28 ;
    END
  END i[1]
  PIN i[20]
    DIRECTION INPUT ;
    USE SIGNAL ;
    PORT
      LAYER M4 ;
        RECT  0 4.08 0.084 4.104 ;
    END
  END i[20]
  PIN i[21]
    DIRECTION INPUT ;
    USE SIGNAL ;
    PORT
      LAYER M4 ;
        RECT  0 4.176 0.084 4.2 ;
    END
  END i[21]
  PIN i[22]
    DIRECTION INPUT ;
    USE SIGNAL ;
    PORT
      LAYER M4 ;
        RECT  0 4.272 0.084 4.296 ;
    END
  END i[22]
  PIN i[23]
    DIRECTION INPUT ;
    USE SIGNAL ;
    PORT
      LAYER M4 ;
        RECT  0 4.368 0.084 4.392 ;
    END
  END i[23]
  PIN i[24]
    DIRECTION INPUT ;
    USE SIGNAL ;
    PORT
      LAYER M4 ;
        RECT  0 4.464 0.084 4.488 ;
    END
  END i[24]
  PIN i[25]
    DIRECTION INPUT ;
    USE SIGNAL ;
    PORT
      LAYER M4 ;
        RECT  0 4.56 0.084 4.584 ;
    END
  END i[25]
  PIN i[26]
    DIRECTION INPUT ;
    USE SIGNAL ;
    PORT
      LAYER M4 ;
        RECT  0 4.656 0.084 4.68 ;
    END
  END i[26]
  PIN i[27]
    DIRECTION INPUT ;
    USE SIGNAL ;
    PORT
      LAYER M4 ;
        RECT  0 4.752 0.084 4.776 ;
    END
  END i[27]
  PIN i[28]
    DIRECTION INPUT ;
    USE SIGNAL ;
    PORT
      LAYER M4 ;
        RECT  0 4.848 0.084 4.872 ;
    END
  END i[28]
  PIN i[29]
    DIRECTION INPUT ;
    USE SIGNAL ;
    PORT
      LAYER M4 ;
        RECT  0 4.944 0.084 4.968 ;
    END
  END i[29]
  PIN i[2]
    DIRECTION INPUT ;
    USE SIGNAL ;
    PORT
      LAYER M4 ;
        RECT  0 2.352 0.084 2.376 ;
    END
  END i[2]
  PIN i[30]
    DIRECTION INPUT ;
    USE SIGNAL ;
    PORT
      LAYER M4 ;
        RECT  0 5.04 0.084 5.064 ;
    END
  END i[30]
  PIN i[31]
    DIRECTION INPUT ;
    USE SIGNAL ;
    PORT
      LAYER M4 ;
        RECT  0 5.136 0.084 5.16 ;
    END
  END i[31]
  PIN i[32]
    DIRECTION INPUT ;
    USE SIGNAL ;
    PORT
      LAYER M4 ;
        RECT  0 5.328 0.084 5.352 ;
    END
  END i[32]
  PIN i[33]
    DIRECTION INPUT ;
    USE SIGNAL ;
    PORT
      LAYER M4 ;
        RECT  0 5.424 0.084 5.448 ;
    END
  END i[33]
  PIN i[34]
    DIRECTION INPUT ;
    USE SIGNAL ;
    PORT
      LAYER M4 ;
        RECT  0 5.52 0.084 5.544 ;
    END
  END i[34]
  PIN i[35]
    DIRECTION INPUT ;
    USE SIGNAL ;
    PORT
      LAYER M4 ;
        RECT  0 5.616 0.084 5.64 ;
    END
  END i[35]
  PIN i[36]
    DIRECTION INPUT ;
    USE SIGNAL ;
    PORT
      LAYER M4 ;
        RECT  0 5.712 0.084 5.736 ;
    END
  END i[36]
  PIN i[37]
    DIRECTION INPUT ;
    USE SIGNAL ;
    PORT
      LAYER M4 ;
        RECT  0 5.808 0.084 5.832 ;
    END
  END i[37]
  PIN i[38]
    DIRECTION INPUT ;
    USE SIGNAL ;
    PORT
      LAYER M4 ;
        RECT  0 5.904 0.084 5.928 ;
    END
  END i[38]
  PIN i[39]
    DIRECTION INPUT ;
    USE SIGNAL ;
    PORT
      LAYER M4 ;
        RECT  0 6 0.084 6.024 ;
    END
  END i[39]
  PIN i[3]
    DIRECTION INPUT ;
    USE SIGNAL ;
    PORT
      LAYER M4 ;
        RECT  0 2.448 0.084 2.472 ;
    END
  END i[3]
  PIN i[40]
    DIRECTION INPUT ;
    USE SIGNAL ;
    PORT
      LAYER M4 ;
        RECT  0 6.096 0.084 6.12 ;
    END
  END i[40]
  PIN i[41]
    DIRECTION INPUT ;
    USE SIGNAL ;
    PORT
      LAYER M4 ;
        RECT  0 6.192 0.084 6.216 ;
    END
  END i[41]
  PIN i[42]
    DIRECTION INPUT ;
    USE SIGNAL ;
    PORT
      LAYER M4 ;
        RECT  0 6.288 0.084 6.312 ;
    END
  END i[42]
  PIN i[43]
    DIRECTION INPUT ;
    USE SIGNAL ;
    PORT
      LAYER M4 ;
        RECT  0 6.384 0.084 6.408 ;
    END
  END i[43]
  PIN i[44]
    DIRECTION INPUT ;
    USE SIGNAL ;
    PORT
      LAYER M4 ;
        RECT  0 6.48 0.084 6.504 ;
    END
  END i[44]
  PIN i[45]
    DIRECTION INPUT ;
    USE SIGNAL ;
    PORT
      LAYER M4 ;
        RECT  0 6.576 0.084 6.6 ;
    END
  END i[45]
  PIN i[46]
    DIRECTION INPUT ;
    USE SIGNAL ;
    PORT
      LAYER M4 ;
        RECT  0 6.672 0.084 6.696 ;
    END
  END i[46]
  PIN i[47]
    DIRECTION INPUT ;
    USE SIGNAL ;
    PORT
      LAYER M4 ;
        RECT  0 6.768 0.084 6.792 ;
    END
  END i[47]
  PIN i[48]
    DIRECTION INPUT ;
    USE SIGNAL ;
    PORT
      LAYER M4 ;
        RECT  0 6.864 0.084 6.888 ;
    END
  END i[48]
  PIN i[49]
    DIRECTION INPUT ;
    USE SIGNAL ;
    PORT
      LAYER M4 ;
        RECT  0 6.96 0.084 6.984 ;
    END
  END i[49]
  PIN i[4]
    DIRECTION INPUT ;
    USE SIGNAL ;
    PORT
      LAYER M4 ;
        RECT  0 2.544 0.084 2.568 ;
    END
  END i[4]
  PIN i[50]
    DIRECTION INPUT ;
    USE SIGNAL ;
    PORT
      LAYER M4 ;
        RECT  0 7.056 0.084 7.08 ;
    END
  END i[50]
  PIN i[51]
    DIRECTION INPUT ;
    USE SIGNAL ;
    PORT
      LAYER M4 ;
        RECT  0 7.152 0.084 7.176 ;
    END
  END i[51]
  PIN i[52]
    DIRECTION INPUT ;
    USE SIGNAL ;
    PORT
      LAYER M4 ;
        RECT  0 7.248 0.084 7.272 ;
    END
  END i[52]
  PIN i[53]
    DIRECTION INPUT ;
    USE SIGNAL ;
    PORT
      LAYER M4 ;
        RECT  0 7.344 0.084 7.368 ;
    END
  END i[53]
  PIN i[54]
    DIRECTION INPUT ;
    USE SIGNAL ;
    PORT
      LAYER M4 ;
        RECT  0 7.44 0.084 7.464 ;
    END
  END i[54]
  PIN i[55]
    DIRECTION INPUT ;
    USE SIGNAL ;
    PORT
      LAYER M4 ;
        RECT  0 7.536 0.084 7.56 ;
    END
  END i[55]
  PIN i[56]
    DIRECTION INPUT ;
    USE SIGNAL ;
    PORT
      LAYER M4 ;
        RECT  0 7.632 0.084 7.656 ;
    END
  END i[56]
  PIN i[57]
    DIRECTION INPUT ;
    USE SIGNAL ;
    PORT
      LAYER M4 ;
        RECT  0 7.728 0.084 7.752 ;
    END
  END i[57]
  PIN i[58]
    DIRECTION INPUT ;
    USE SIGNAL ;
    PORT
      LAYER M4 ;
        RECT  0 7.824 0.084 7.848 ;
    END
  END i[58]
  PIN i[59]
    DIRECTION INPUT ;
    USE SIGNAL ;
    PORT
      LAYER M4 ;
        RECT  0 7.92 0.084 7.944 ;
    END
  END i[59]
  PIN i[5]
    DIRECTION INPUT ;
    USE SIGNAL ;
    PORT
      LAYER M4 ;
        RECT  0 2.64 0.084 2.664 ;
    END
  END i[5]
  PIN i[60]
    DIRECTION INPUT ;
    USE SIGNAL ;
    PORT
      LAYER M4 ;
        RECT  0 8.016 0.084 8.04 ;
    END
  END i[60]
  PIN i[61]
    DIRECTION INPUT ;
    USE SIGNAL ;
    PORT
      LAYER M4 ;
        RECT  0 8.112 0.084 8.136 ;
    END
  END i[61]
  PIN i[62]
    DIRECTION INPUT ;
    USE SIGNAL ;
    PORT
      LAYER M4 ;
        RECT  0 8.208 0.084 8.232 ;
    END
  END i[62]
  PIN i[6]
    DIRECTION INPUT ;
    USE SIGNAL ;
    PORT
      LAYER M4 ;
        RECT  0 2.736 0.084 2.76 ;
    END
  END i[6]
  PIN i[7]
    DIRECTION INPUT ;
    USE SIGNAL ;
    PORT
      LAYER M4 ;
        RECT  0 2.832 0.084 2.856 ;
    END
  END i[7]
  PIN i[8]
    DIRECTION INPUT ;
    USE SIGNAL ;
    PORT
      LAYER M4 ;
        RECT  0 2.928 0.084 2.952 ;
    END
  END i[8]
  PIN i[9]
    DIRECTION INPUT ;
    USE SIGNAL ;
    PORT
      LAYER M4 ;
        RECT  0 3.024 0.084 3.048 ;
    END
  END i[9]
  PIN o[0]
    DIRECTION OUTPUT ;
    USE SIGNAL ;
    PORT
      LAYER M5 ;
        RECT  2.16 15.036 2.184 15.12 ;
    END
  END o[0]
  PIN o[10]
    DIRECTION OUTPUT ;
    USE SIGNAL ;
    PORT
      LAYER M5 ;
        RECT  3.12 15.036 3.144 15.12 ;
    END
  END o[10]
  PIN o[11]
    DIRECTION OUTPUT ;
    USE SIGNAL ;
    PORT
      LAYER M5 ;
        RECT  3.216 15.036 3.24 15.12 ;
    END
  END o[11]
  PIN o[12]
    DIRECTION OUTPUT ;
    USE SIGNAL ;
    PORT
      LAYER M5 ;
        RECT  3.312 15.036 3.336 15.12 ;
    END
  END o[12]
  PIN o[13]
    DIRECTION OUTPUT ;
    USE SIGNAL ;
    PORT
      LAYER M5 ;
        RECT  3.408 15.036 3.432 15.12 ;
    END
  END o[13]
  PIN o[14]
    DIRECTION OUTPUT ;
    USE SIGNAL ;
    PORT
      LAYER M5 ;
        RECT  3.504 15.036 3.528 15.12 ;
    END
  END o[14]
  PIN o[15]
    DIRECTION OUTPUT ;
    USE SIGNAL ;
    PORT
      LAYER M5 ;
        RECT  3.6 15.036 3.624 15.12 ;
    END
  END o[15]
  PIN o[16]
    DIRECTION OUTPUT ;
    USE SIGNAL ;
    PORT
      LAYER M5 ;
        RECT  3.696 15.036 3.72 15.12 ;
    END
  END o[16]
  PIN o[17]
    DIRECTION OUTPUT ;
    USE SIGNAL ;
    PORT
      LAYER M5 ;
        RECT  3.792 15.036 3.816 15.12 ;
    END
  END o[17]
  PIN o[18]
    DIRECTION OUTPUT ;
    USE SIGNAL ;
    PORT
      LAYER M5 ;
        RECT  3.888 15.036 3.912 15.12 ;
    END
  END o[18]
  PIN o[19]
    DIRECTION OUTPUT ;
    USE SIGNAL ;
    PORT
      LAYER M5 ;
        RECT  3.984 15.036 4.008 15.12 ;
    END
  END o[19]
  PIN o[1]
    DIRECTION OUTPUT ;
    USE SIGNAL ;
    PORT
      LAYER M5 ;
        RECT  2.256 15.036 2.28 15.12 ;
    END
  END o[1]
  PIN o[20]
    DIRECTION OUTPUT ;
    USE SIGNAL ;
    PORT
      LAYER M5 ;
        RECT  4.08 15.036 4.104 15.12 ;
    END
  END o[20]
  PIN o[21]
    DIRECTION OUTPUT ;
    USE SIGNAL ;
    PORT
      LAYER M5 ;
        RECT  4.176 15.036 4.2 15.12 ;
    END
  END o[21]
  PIN o[22]
    DIRECTION OUTPUT ;
    USE SIGNAL ;
    PORT
      LAYER M5 ;
        RECT  4.272 15.036 4.296 15.12 ;
    END
  END o[22]
  PIN o[23]
    DIRECTION OUTPUT ;
    USE SIGNAL ;
    PORT
      LAYER M5 ;
        RECT  4.368 15.036 4.392 15.12 ;
    END
  END o[23]
  PIN o[24]
    DIRECTION OUTPUT ;
    USE SIGNAL ;
    PORT
      LAYER M5 ;
        RECT  4.464 15.036 4.488 15.12 ;
    END
  END o[24]
  PIN o[25]
    DIRECTION OUTPUT ;
    USE SIGNAL ;
    PORT
      LAYER M5 ;
        RECT  4.56 15.036 4.584 15.12 ;
    END
  END o[25]
  PIN o[26]
    DIRECTION OUTPUT ;
    USE SIGNAL ;
    PORT
      LAYER M5 ;
        RECT  4.656 15.036 4.68 15.12 ;
    END
  END o[26]
  PIN o[27]
    DIRECTION OUTPUT ;
    USE SIGNAL ;
    PORT
      LAYER M5 ;
        RECT  4.752 15.036 4.776 15.12 ;
    END
  END o[27]
  PIN o[28]
    DIRECTION OUTPUT ;
    USE SIGNAL ;
    PORT
      LAYER M5 ;
        RECT  4.848 15.036 4.872 15.12 ;
    END
  END o[28]
  PIN o[29]
    DIRECTION OUTPUT ;
    USE SIGNAL ;
    PORT
      LAYER M5 ;
        RECT  4.944 15.036 4.968 15.12 ;
    END
  END o[29]
  PIN o[2]
    DIRECTION OUTPUT ;
    USE SIGNAL ;
    PORT
      LAYER M5 ;
        RECT  2.352 15.036 2.376 15.12 ;
    END
  END o[2]
  PIN o[30]
    DIRECTION OUTPUT ;
    USE SIGNAL ;
    PORT
      LAYER M5 ;
        RECT  5.04 15.036 5.064 15.12 ;
    END
  END o[30]
  PIN o[31]
    DIRECTION OUTPUT ;
    USE SIGNAL ;
    PORT
      LAYER M5 ;
        RECT  5.136 15.036 5.16 15.12 ;
    END
  END o[31]
  PIN o[32]
    DIRECTION OUTPUT ;
    USE SIGNAL ;
    PORT
      LAYER M5 ;
        RECT  5.328 15.036 5.352 15.12 ;
    END
  END o[32]
  PIN o[33]
    DIRECTION OUTPUT ;
    USE SIGNAL ;
    PORT
      LAYER M5 ;
        RECT  5.424 15.036 5.448 15.12 ;
    END
  END o[33]
  PIN o[34]
    DIRECTION OUTPUT ;
    USE SIGNAL ;
    PORT
      LAYER M5 ;
        RECT  5.52 15.036 5.544 15.12 ;
    END
  END o[34]
  PIN o[35]
    DIRECTION OUTPUT ;
    USE SIGNAL ;
    PORT
      LAYER M5 ;
        RECT  5.616 15.036 5.64 15.12 ;
    END
  END o[35]
  PIN o[36]
    DIRECTION OUTPUT ;
    USE SIGNAL ;
    PORT
      LAYER M5 ;
        RECT  5.712 15.036 5.736 15.12 ;
    END
  END o[36]
  PIN o[37]
    DIRECTION OUTPUT ;
    USE SIGNAL ;
    PORT
      LAYER M5 ;
        RECT  5.808 15.036 5.832 15.12 ;
    END
  END o[37]
  PIN o[38]
    DIRECTION OUTPUT ;
    USE SIGNAL ;
    PORT
      LAYER M5 ;
        RECT  5.904 15.036 5.928 15.12 ;
    END
  END o[38]
  PIN o[39]
    DIRECTION OUTPUT ;
    USE SIGNAL ;
    PORT
      LAYER M5 ;
        RECT  6 15.036 6.024 15.12 ;
    END
  END o[39]
  PIN o[3]
    DIRECTION OUTPUT ;
    USE SIGNAL ;
    PORT
      LAYER M5 ;
        RECT  2.448 15.036 2.472 15.12 ;
    END
  END o[3]
  PIN o[40]
    DIRECTION OUTPUT ;
    USE SIGNAL ;
    PORT
      LAYER M5 ;
        RECT  6.096 15.036 6.12 15.12 ;
    END
  END o[40]
  PIN o[41]
    DIRECTION OUTPUT ;
    USE SIGNAL ;
    PORT
      LAYER M5 ;
        RECT  6.192 15.036 6.216 15.12 ;
    END
  END o[41]
  PIN o[42]
    DIRECTION OUTPUT ;
    USE SIGNAL ;
    PORT
      LAYER M5 ;
        RECT  6.288 15.036 6.312 15.12 ;
    END
  END o[42]
  PIN o[43]
    DIRECTION OUTPUT ;
    USE SIGNAL ;
    PORT
      LAYER M5 ;
        RECT  6.384 15.036 6.408 15.12 ;
    END
  END o[43]
  PIN o[44]
    DIRECTION OUTPUT ;
    USE SIGNAL ;
    PORT
      LAYER M5 ;
        RECT  6.48 15.036 6.504 15.12 ;
    END
  END o[44]
  PIN o[45]
    DIRECTION OUTPUT ;
    USE SIGNAL ;
    PORT
      LAYER M5 ;
        RECT  6.576 15.036 6.6 15.12 ;
    END
  END o[45]
  PIN o[46]
    DIRECTION OUTPUT ;
    USE SIGNAL ;
    PORT
      LAYER M5 ;
        RECT  6.672 15.036 6.696 15.12 ;
    END
  END o[46]
  PIN o[47]
    DIRECTION OUTPUT ;
    USE SIGNAL ;
    PORT
      LAYER M5 ;
        RECT  6.768 15.036 6.792 15.12 ;
    END
  END o[47]
  PIN o[48]
    DIRECTION OUTPUT ;
    USE SIGNAL ;
    PORT
      LAYER M5 ;
        RECT  6.864 15.036 6.888 15.12 ;
    END
  END o[48]
  PIN o[49]
    DIRECTION OUTPUT ;
    USE SIGNAL ;
    PORT
      LAYER M5 ;
        RECT  6.96 15.036 6.984 15.12 ;
    END
  END o[49]
  PIN o[4]
    DIRECTION OUTPUT ;
    USE SIGNAL ;
    PORT
      LAYER M5 ;
        RECT  2.544 15.036 2.568 15.12 ;
    END
  END o[4]
  PIN o[50]
    DIRECTION OUTPUT ;
    USE SIGNAL ;
    PORT
      LAYER M5 ;
        RECT  7.056 15.036 7.08 15.12 ;
    END
  END o[50]
  PIN o[51]
    DIRECTION OUTPUT ;
    USE SIGNAL ;
    PORT
      LAYER M5 ;
        RECT  7.152 15.036 7.176 15.12 ;
    END
  END o[51]
  PIN o[52]
    DIRECTION OUTPUT ;
    USE SIGNAL ;
    PORT
      LAYER M5 ;
        RECT  7.248 15.036 7.272 15.12 ;
    END
  END o[52]
  PIN o[53]
    DIRECTION OUTPUT ;
    USE SIGNAL ;
    PORT
      LAYER M5 ;
        RECT  7.344 15.036 7.368 15.12 ;
    END
  END o[53]
  PIN o[54]
    DIRECTION OUTPUT ;
    USE SIGNAL ;
    PORT
      LAYER M5 ;
        RECT  7.44 15.036 7.464 15.12 ;
    END
  END o[54]
  PIN o[55]
    DIRECTION OUTPUT ;
    USE SIGNAL ;
    PORT
      LAYER M5 ;
        RECT  7.536 15.036 7.56 15.12 ;
    END
  END o[55]
  PIN o[56]
    DIRECTION OUTPUT ;
    USE SIGNAL ;
    PORT
      LAYER M5 ;
        RECT  7.632 15.036 7.656 15.12 ;
    END
  END o[56]
  PIN o[57]
    DIRECTION OUTPUT ;
    USE SIGNAL ;
    PORT
      LAYER M5 ;
        RECT  7.728 15.036 7.752 15.12 ;
    END
  END o[57]
  PIN o[58]
    DIRECTION OUTPUT ;
    USE SIGNAL ;
    PORT
      LAYER M5 ;
        RECT  7.824 15.036 7.848 15.12 ;
    END
  END o[58]
  PIN o[59]
    DIRECTION OUTPUT ;
    USE SIGNAL ;
    PORT
      LAYER M5 ;
        RECT  7.92 15.036 7.944 15.12 ;
    END
  END o[59]
  PIN o[5]
    DIRECTION OUTPUT ;
    USE SIGNAL ;
    PORT
      LAYER M5 ;
        RECT  2.64 15.036 2.664 15.12 ;
    END
  END o[5]
  PIN o[60]
    DIRECTION OUTPUT ;
    USE SIGNAL ;
    PORT
      LAYER M5 ;
        RECT  8.016 15.036 8.04 15.12 ;
    END
  END o[60]
  PIN o[61]
    DIRECTION OUTPUT ;
    USE SIGNAL ;
    PORT
      LAYER M5 ;
        RECT  8.112 15.036 8.136 15.12 ;
    END
  END o[61]
  PIN o[62]
    DIRECTION OUTPUT ;
    USE SIGNAL ;
    PORT
      LAYER M5 ;
        RECT  8.208 15.036 8.232 15.12 ;
    END
  END o[62]
  PIN o[6]
    DIRECTION OUTPUT ;
    USE SIGNAL ;
    PORT
      LAYER M5 ;
        RECT  2.736 15.036 2.76 15.12 ;
    END
  END o[6]
  PIN o[7]
    DIRECTION OUTPUT ;
    USE SIGNAL ;
    PORT
      LAYER M5 ;
        RECT  2.832 15.036 2.856 15.12 ;
    END
  END o[7]
  PIN o[8]
    DIRECTION OUTPUT ;
    USE SIGNAL ;
    PORT
      LAYER M5 ;
        RECT  2.928 15.036 2.952 15.12 ;
    END
  END o[8]
  PIN o[9]
    DIRECTION OUTPUT ;
    USE SIGNAL ;
    PORT
      LAYER M5 ;
        RECT  3.024 15.036 3.048 15.12 ;
    END
  END o[9]
  PIN rs
    DIRECTION INPUT ;
    USE SIGNAL ;
    PORT
      LAYER M5 ;
        RECT  4.272 0 4.296 0.084 ;
    END
  END rs
  PIN VDD
    DIRECTION INOUT ;
    USE POWER ;
    PORT
      LAYER M5 ;
        RECT  10.692 2.151 10.812 12.969 ;
        RECT  7.992 2.151 8.112 12.969 ;
        RECT  5.292 2.151 5.412 12.969 ;
        RECT  2.592 2.151 2.712 12.969 ;
    END
  END VDD
  PIN VSS
    DIRECTION INOUT ;
    USE GROUND ;
    PORT
      LAYER M5 ;
        RECT  10.5 2.137 10.62 12.983 ;
        RECT  7.8 2.137 7.92 12.983 ;
        RECT  5.1 2.137 5.22 12.983 ;
        RECT  2.4 2.137 2.52 12.983 ;
    END
  END VSS
  OBS
    LAYER RVTN ;
     RECT  2.16 2.16 12.96 2.295 ;
     RECT  2.16 2.565 12.96 2.835 ;
     RECT  2.16 3.105 12.96 3.375 ;
     RECT  2.16 3.645 12.96 3.915 ;
     RECT  2.16 4.185 12.96 4.455 ;
     RECT  2.16 4.725 12.96 4.995 ;
     RECT  2.16 5.265 12.96 5.535 ;
     RECT  2.16 5.805 12.96 6.075 ;
     RECT  2.16 6.345 12.96 6.615 ;
     RECT  2.16 6.885 12.96 7.155 ;
     RECT  2.16 7.425 12.96 7.695 ;
     RECT  2.16 7.965 12.96 8.235 ;
     RECT  2.16 8.505 12.96 8.775 ;
     RECT  2.16 9.045 12.96 9.315 ;
     RECT  2.16 9.585 12.96 9.855 ;
     RECT  2.16 10.125 12.96 10.395 ;
     RECT  2.16 10.665 12.96 10.935 ;
     RECT  2.16 11.205 12.96 11.475 ;
     RECT  2.16 11.745 12.96 12.015 ;
     RECT  2.16 12.285 12.96 12.555 ;
     RECT  2.16 12.825 12.96 12.96 ;
    LAYER RVTP ;
     RECT  2.16 2.295 12.96 2.565 ;
     RECT  2.16 2.835 12.96 3.105 ;
     RECT  2.16 3.375 12.96 3.645 ;
     RECT  2.16 3.915 12.96 4.185 ;
     RECT  2.16 4.455 12.96 4.725 ;
     RECT  2.16 4.995 12.96 5.265 ;
     RECT  2.16 5.535 12.96 5.805 ;
     RECT  2.16 6.075 12.96 6.345 ;
     RECT  2.16 6.615 12.96 6.885 ;
     RECT  2.16 7.155 12.96 7.425 ;
     RECT  2.16 7.695 12.96 7.965 ;
     RECT  2.16 8.235 12.96 8.505 ;
     RECT  2.16 8.775 12.96 9.045 ;
     RECT  2.16 9.315 12.96 9.585 ;
     RECT  2.16 9.855 12.96 10.125 ;
     RECT  2.16 10.395 12.96 10.665 ;
     RECT  2.16 10.935 12.96 11.205 ;
     RECT  2.16 11.475 12.96 11.745 ;
     RECT  2.16 12.015 12.96 12.285 ;
     RECT  2.16 12.555 12.96 12.825 ;
    LAYER M1 ;
     RECT  2.16 2.151 12.96 12.969 ;
    LAYER M2 ;
     RECT  0.103 3.69 0.175 3.708 ;
     RECT  0.175 3.618 0.499 3.708 ;
     RECT  2.119 8.478 2.155 8.496 ;
     RECT  2.119 12.294 2.155 12.312 ;
     RECT  0.499 3.114 2.16 3.708 ;
     RECT  0.103 4.464 2.16 4.482 ;
     RECT  0.535 5.58 2.16 5.598 ;
     RECT  0.535 6.696 2.16 6.714 ;
     RECT  2.155 8.046 2.16 8.496 ;
     RECT  0.103 9.36 2.16 9.378 ;
     RECT  2.155 12.294 2.16 12.384 ;
     RECT  2.16 2.151 3.451 12.969 ;
     RECT  3.451 2.106 4.063 12.969 ;
     RECT  4.063 2.034 5.639 12.969 ;
     RECT  5.639 2.106 6.179 12.969 ;
     RECT  6.179 2.151 12.96 12.969 ;
    LAYER M3 ;
     RECT  4.284 1.723 4.302 2.029 ;
     RECT  4.068 2.029 4.302 2.101 ;
     RECT  5.616 2.029 5.634 2.101 ;
     RECT  3.456 2.101 4.59 2.143 ;
     RECT  5.616 2.101 6.174 2.143 ;
     RECT  2.415 2.143 2.505 2.155 ;
     RECT  2.304 2.155 2.505 2.191 ;
     RECT  3.456 2.143 6.174 2.191 ;
     RECT  2.304 2.191 6.174 2.371 ;
     RECT  7.815 2.143 7.905 2.413 ;
     RECT  10.515 2.143 10.605 2.413 ;
     RECT  10.515 2.413 10.797 2.605 ;
     RECT  9.9 2.605 10.797 2.731 ;
     RECT  2.304 2.371 6.93 2.767 ;
     RECT  7.815 2.413 8.097 2.767 ;
     RECT  2.304 2.767 8.097 3.019 ;
     RECT  2.196 3.019 8.097 3.109 ;
     RECT  8.82 2.731 10.797 3.109 ;
     RECT  2.196 3.109 10.797 3.173 ;
     RECT  0.504 3.109 0.522 3.379 ;
     RECT  0.504 3.379 0.558 3.533 ;
     RECT  0.504 3.533 0.522 3.613 ;
     RECT  0.18 3.613 0.522 3.685 ;
     RECT  2.304 3.173 10.797 4.315 ;
     RECT  2.268 4.315 10.797 4.415 ;
     RECT  0.108 3.685 0.522 4.589 ;
     RECT  2.304 4.415 10.797 4.657 ;
     RECT  0.108 4.589 0.198 4.685 ;
     RECT  2.304 4.657 10.854 4.801 ;
     RECT  2.304 4.801 11.214 4.991 ;
     RECT  9.288 4.991 11.214 5.099 ;
     RECT  2.304 4.991 8.55 5.323 ;
     RECT  2.268 5.323 8.55 5.563 ;
     RECT  0.144 4.685 0.198 5.575 ;
     RECT  2.196 5.563 8.55 5.603 ;
     RECT  0.144 5.575 0.558 5.851 ;
     RECT  9.432 5.099 11.214 5.851 ;
     RECT  9.432 5.851 11.358 5.999 ;
     RECT  0.144 5.851 1.17 6.077 ;
     RECT  2.304 5.603 8.55 6.079 ;
     RECT  9.432 5.999 11.25 6.079 ;
     RECT  0.18 6.077 1.17 6.221 ;
     RECT  2.304 6.079 11.25 6.385 ;
     RECT  2.268 6.385 11.25 6.509 ;
     RECT  2.304 6.509 11.25 6.925 ;
     RECT  0.18 6.221 0.558 6.955 ;
     RECT  0.18 6.955 1.17 7.085 ;
     RECT  2.304 6.925 11.394 7.159 ;
     RECT  0.18 7.085 0.198 7.195 ;
     RECT  2.304 7.159 11.43 7.231 ;
     RECT  1.152 7.085 1.17 7.373 ;
     RECT  0.144 7.195 0.198 7.819 ;
     RECT  2.304 7.231 11.862 8.041 ;
     RECT  0.108 7.819 0.198 8.107 ;
     RECT  0.108 8.107 0.342 8.237 ;
     RECT  2.16 8.041 11.862 8.473 ;
     RECT  2.124 8.473 11.862 8.581 ;
     RECT  0.108 8.237 0.126 9.383 ;
     RECT  2.124 8.581 12.114 9.931 ;
     RECT  2.124 9.931 12.51 12.281 ;
     RECT  2.124 12.281 12.114 12.317 ;
     RECT  2.16 12.317 12.006 12.389 ;
     RECT  2.376 12.389 11.97 12.479 ;
     RECT  10.515 12.479 11.97 12.551 ;
     RECT  10.515 12.551 11.898 12.749 ;
     RECT  2.376 12.479 9.702 12.785 ;
     RECT  10.515 12.749 10.638 12.785 ;
     RECT  11.376 12.749 11.466 12.785 ;
     RECT  11.448 12.785 11.466 12.821 ;
     RECT  2.376 12.785 8.838 12.893 ;
     RECT  10.515 12.785 10.605 12.977 ;
     RECT  2.376 12.893 8.37 13.661 ;
     RECT  2.376 13.661 4.194 14.237 ;
     RECT  5.4 13.661 7.362 14.237 ;
     RECT  4.176 14.237 4.194 14.285 ;
     RECT  2.556 14.237 3.294 14.957 ;
     RECT  2.628 14.957 3.294 15.005 ;
     RECT  5.58 14.237 5.598 15.005 ;
     RECT  7.344 14.237 7.362 15.005 ;
    LAYER M4 ;
     RECT  0.06 2.16 0.133 8.232 ;
     RECT  0.133 2.16 2.293 8.472 ;
     RECT  2.341 14.976 2.365 15 ;
     RECT  2.293 2.16 2.408 8.76 ;
     RECT  2.213 10.8 2.408 10.824 ;
     RECT  2.149 11.952 2.408 11.976 ;
     RECT  2.408 2.148 2.512 12.972 ;
     RECT  2.512 2.352 2.725 12.972 ;
     RECT  2.725 2.352 2.917 13.08 ;
     RECT  2.365 14.208 2.917 15 ;
     RECT  2.917 2.352 3.305 15 ;
     RECT  3.305 2.352 4.115 14.28 ;
     RECT  4.115 10.272 4.211 14.28 ;
     RECT  4.115 2.352 4.229 9.288 ;
     RECT  4.229 1.728 4.313 9.288 ;
     RECT  4.313 2.148 5.108 9.288 ;
     RECT  4.211 10.272 5.108 13.656 ;
     RECT  5.108 2.148 5.212 13.656 ;
     RECT  5.212 2.418 5.317 13.656 ;
     RECT  4.885 14.928 5.317 14.952 ;
     RECT  5.317 2.418 5.404 14.952 ;
     RECT  5.404 10.944 5.509 14.952 ;
     RECT  5.509 10.944 5.537 15 ;
     RECT  5.404 2.592 5.555 8.424 ;
     RECT  5.537 11.424 5.609 15 ;
     RECT  5.555 2.736 6.113 8.424 ;
     RECT  5.609 11.424 6.373 14.232 ;
     RECT  6.113 3.072 6.649 8.424 ;
     RECT  6.373 11.424 6.721 11.448 ;
     RECT  6.373 12.528 6.833 14.232 ;
     RECT  6.649 3.072 6.901 8.856 ;
     RECT  6.901 3.072 6.937 8.904 ;
     RECT  6.833 13.056 7.157 14.232 ;
     RECT  6.721 10.8 7.333 11.448 ;
     RECT  7.237 14.976 7.373 15 ;
     RECT  6.937 3.072 7.441 9.096 ;
     RECT  7.333 10.464 7.441 11.448 ;
     RECT  7.441 3.072 7.808 11.448 ;
     RECT  7.157 13.056 7.808 13.656 ;
     RECT  7.808 2.148 7.912 13.656 ;
     RECT  7.912 2.418 8.104 13.656 ;
     RECT  8.104 3.072 8.381 3.624 ;
     RECT  8.104 12.72 8.381 13.656 ;
     RECT  8.104 4.656 8.531 11.256 ;
     RECT  8.531 4.656 8.561 9.528 ;
     RECT  8.381 12.72 8.669 12.744 ;
     RECT  8.561 4.656 8.813 8.28 ;
     RECT  8.813 7.2 8.921 8.28 ;
     RECT  8.813 4.656 9.097 5.88 ;
     RECT  8.561 9.408 9.548 9.528 ;
     RECT  8.531 10.704 9.548 11.256 ;
     RECT  8.381 3.072 9.637 3.336 ;
     RECT  9.548 9.408 10.069 11.256 ;
     RECT  8.921 7.2 10.465 8.04 ;
     RECT  10.069 9.12 10.465 11.256 ;
     RECT  9.637 3.072 10.508 3.432 ;
     RECT  9.097 4.512 10.508 5.88 ;
     RECT  10.465 7.2 10.508 11.256 ;
     RECT  10.508 2.148 10.612 12.972 ;
     RECT  10.612 2.418 10.804 12.702 ;
     RECT  10.804 8.496 10.865 8.52 ;
     RECT  10.804 12 11.009 12.552 ;
     RECT  10.804 10.128 11.225 10.2 ;
     RECT  10.804 5.856 11.369 5.88 ;
     RECT  11.225 10.128 11.621 10.152 ;
     RECT  11.009 12.336 12.017 12.36 ;
    LAYER M5 ;
     RECT  4.176 0.016 4.296 2.137 ;
     RECT  2.4 2.137 2.52 2.151 ;
     RECT  4.176 2.137 5.22 2.151 ;
     RECT  7.8 2.137 7.92 2.151 ;
     RECT  10.5 2.137 10.62 2.151 ;
     RECT  4.176 2.151 5.412 2.581 ;
     RECT  2.4 2.151 2.712 2.677 ;
     RECT  4.176 2.581 5.544 2.677 ;
     RECT  2.4 2.677 5.544 3.013 ;
     RECT  7.8 2.151 8.112 3.109 ;
     RECT  2.304 3.013 5.544 3.251 ;
     RECT  2.4 3.251 5.544 3.397 ;
     RECT  6.864 3.109 8.112 3.397 ;
     RECT  2.4 3.397 8.232 4.019 ;
     RECT  0.144 3.637 0.168 4.499 ;
     RECT  7.8 4.019 8.232 5.989 ;
     RECT  2.4 4.019 5.976 6.035 ;
     RECT  7.008 5.989 8.232 6.707 ;
     RECT  2.4 6.035 5.544 7.093 ;
     RECT  7.008 6.707 8.112 7.093 ;
     RECT  10.5 2.151 10.812 7.189 ;
     RECT  2.4 7.093 8.112 7.381 ;
     RECT  0.144 8.197 0.168 8.483 ;
     RECT  2.304 7.381 8.112 8.771 ;
     RECT  2.4 8.771 8.112 8.869 ;
     RECT  10.08 7.189 10.812 9.397 ;
     RECT  9.6 9.397 10.812 10.165 ;
     RECT  9.6 10.165 10.92 10.355 ;
     RECT  2.4 8.869 8.52 10.789 ;
     RECT  2.256 10.789 8.52 10.883 ;
     RECT  2.256 10.883 8.112 11.941 ;
     RECT  10.5 10.355 10.92 12.035 ;
     RECT  2.16 11.941 8.112 12.709 ;
     RECT  10.5 12.035 10.812 12.969 ;
     RECT  10.5 12.969 10.62 12.983 ;
     RECT  2.16 12.709 8.232 15.056 ;
  END
END dsfd_rly_63_WN

VERSION 5.8 ;
BUSBITCHARS "[]" ;
DIVIDERCHAR "/" ;
UNITS
    DATABASE MICRONS 1000 ;
END UNITS

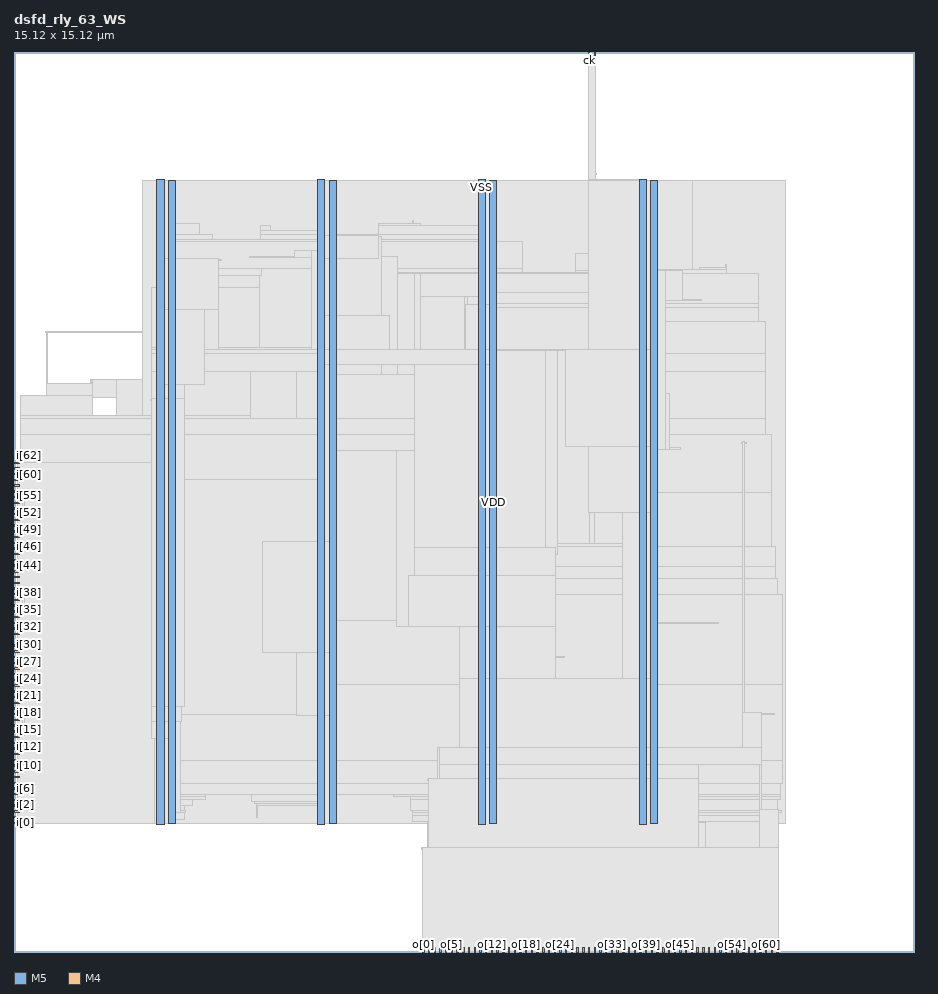
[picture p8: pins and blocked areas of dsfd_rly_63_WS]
MACRO dsfd_rly_63_WS
  FOREIGN dsfd_rly_63_WS 0 0 ;
  CLASS BLOCK ;
  SIZE 15.12 BY 15.12 ;
  PIN ck
    DIRECTION INPUT ;
    USE SIGNAL ;
    PORT
      LAYER M5 ;
        RECT  9.648 15.036 9.672 15.12 ;
    END
  END ck
  PIN i[0]
    DIRECTION INPUT ;
    USE SIGNAL ;
    PORT
      LAYER M4 ;
        RECT  0 2.16 0.084 2.184 ;
    END
  END i[0]
  PIN i[10]
    DIRECTION INPUT ;
    USE SIGNAL ;
    PORT
      LAYER M4 ;
        RECT  0 3.12 0.084 3.144 ;
    END
  END i[10]
  PIN i[11]
    DIRECTION INPUT ;
    USE SIGNAL ;
    PORT
      LAYER M4 ;
        RECT  0 3.216 0.084 3.24 ;
    END
  END i[11]
  PIN i[12]
    DIRECTION INPUT ;
    USE SIGNAL ;
    PORT
      LAYER M4 ;
        RECT  0 3.312 0.084 3.336 ;
    END
  END i[12]
  PIN i[13]
    DIRECTION INPUT ;
    USE SIGNAL ;
    PORT
      LAYER M4 ;
        RECT  0 3.408 0.084 3.432 ;
    END
  END i[13]
  PIN i[14]
    DIRECTION INPUT ;
    USE SIGNAL ;
    PORT
      LAYER M4 ;
        RECT  0 3.504 0.084 3.528 ;
    END
  END i[14]
  PIN i[15]
    DIRECTION INPUT ;
    USE SIGNAL ;
    PORT
      LAYER M4 ;
        RECT  0 3.6 0.084 3.624 ;
    END
  END i[15]
  PIN i[16]
    DIRECTION INPUT ;
    USE SIGNAL ;
    PORT
      LAYER M4 ;
        RECT  0 3.696 0.084 3.72 ;
    END
  END i[16]
  PIN i[17]
    DIRECTION INPUT ;
    USE SIGNAL ;
    PORT
      LAYER M4 ;
        RECT  0 3.792 0.084 3.816 ;
    END
  END i[17]
  PIN i[18]
    DIRECTION INPUT ;
    USE SIGNAL ;
    PORT
      LAYER M4 ;
        RECT  0 3.888 0.084 3.912 ;
    END
  END i[18]
  PIN i[19]
    DIRECTION INPUT ;
    USE SIGNAL ;
    PORT
      LAYER M4 ;
        RECT  0 3.984 0.084 4.008 ;
    END
  END i[19]
  PIN i[1]
    DIRECTION INPUT ;
    USE SIGNAL ;
    PORT
      LAYER M4 ;
        RECT  0 2.256 0.084 2.28 ;
    END
  END i[1]
  PIN i[20]
    DIRECTION INPUT ;
    USE SIGNAL ;
    PORT
      LAYER M4 ;
        RECT  0 4.08 0.084 4.104 ;
    END
  END i[20]
  PIN i[21]
    DIRECTION INPUT ;
    USE SIGNAL ;
    PORT
      LAYER M4 ;
        RECT  0 4.176 0.084 4.2 ;
    END
  END i[21]
  PIN i[22]
    DIRECTION INPUT ;
    USE SIGNAL ;
    PORT
      LAYER M4 ;
        RECT  0 4.272 0.084 4.296 ;
    END
  END i[22]
  PIN i[23]
    DIRECTION INPUT ;
    USE SIGNAL ;
    PORT
      LAYER M4 ;
        RECT  0 4.368 0.084 4.392 ;
    END
  END i[23]
  PIN i[24]
    DIRECTION INPUT ;
    USE SIGNAL ;
    PORT
      LAYER M4 ;
        RECT  0 4.464 0.084 4.488 ;
    END
  END i[24]
  PIN i[25]
    DIRECTION INPUT ;
    USE SIGNAL ;
    PORT
      LAYER M4 ;
        RECT  0 4.56 0.084 4.584 ;
    END
  END i[25]
  PIN i[26]
    DIRECTION INPUT ;
    USE SIGNAL ;
    PORT
      LAYER M4 ;
        RECT  0 4.656 0.084 4.68 ;
    END
  END i[26]
  PIN i[27]
    DIRECTION INPUT ;
    USE SIGNAL ;
    PORT
      LAYER M4 ;
        RECT  0 4.752 0.084 4.776 ;
    END
  END i[27]
  PIN i[28]
    DIRECTION INPUT ;
    USE SIGNAL ;
    PORT
      LAYER M4 ;
        RECT  0 4.848 0.084 4.872 ;
    END
  END i[28]
  PIN i[29]
    DIRECTION INPUT ;
    USE SIGNAL ;
    PORT
      LAYER M4 ;
        RECT  0 4.944 0.084 4.968 ;
    END
  END i[29]
  PIN i[2]
    DIRECTION INPUT ;
    USE SIGNAL ;
    PORT
      LAYER M4 ;
        RECT  0 2.352 0.084 2.376 ;
    END
  END i[2]
  PIN i[30]
    DIRECTION INPUT ;
    USE SIGNAL ;
    PORT
      LAYER M4 ;
        RECT  0 5.04 0.084 5.064 ;
    END
  END i[30]
  PIN i[31]
    DIRECTION INPUT ;
    USE SIGNAL ;
    PORT
      LAYER M4 ;
        RECT  0 5.136 0.084 5.16 ;
    END
  END i[31]
  PIN i[32]
    DIRECTION INPUT ;
    USE SIGNAL ;
    PORT
      LAYER M4 ;
        RECT  0 5.328 0.084 5.352 ;
    END
  END i[32]
  PIN i[33]
    DIRECTION INPUT ;
    USE SIGNAL ;
    PORT
      LAYER M4 ;
        RECT  0 5.424 0.084 5.448 ;
    END
  END i[33]
  PIN i[34]
    DIRECTION INPUT ;
    USE SIGNAL ;
    PORT
      LAYER M4 ;
        RECT  0 5.52 0.084 5.544 ;
    END
  END i[34]
  PIN i[35]
    DIRECTION INPUT ;
    USE SIGNAL ;
    PORT
      LAYER M4 ;
        RECT  0 5.616 0.084 5.64 ;
    END
  END i[35]
  PIN i[36]
    DIRECTION INPUT ;
    USE SIGNAL ;
    PORT
      LAYER M4 ;
        RECT  0 5.712 0.084 5.736 ;
    END
  END i[36]
  PIN i[37]
    DIRECTION INPUT ;
    USE SIGNAL ;
    PORT
      LAYER M4 ;
        RECT  0 5.808 0.084 5.832 ;
    END
  END i[37]
  PIN i[38]
    DIRECTION INPUT ;
    USE SIGNAL ;
    PORT
      LAYER M4 ;
        RECT  0 5.904 0.084 5.928 ;
    END
  END i[38]
  PIN i[39]
    DIRECTION INPUT ;
    USE SIGNAL ;
    PORT
      LAYER M4 ;
        RECT  0 6 0.084 6.024 ;
    END
  END i[39]
  PIN i[3]
    DIRECTION INPUT ;
    USE SIGNAL ;
    PORT
      LAYER M4 ;
        RECT  0 2.448 0.084 2.472 ;
    END
  END i[3]
  PIN i[40]
    DIRECTION INPUT ;
    USE SIGNAL ;
    PORT
      LAYER M4 ;
        RECT  0 6.096 0.084 6.12 ;
    END
  END i[40]
  PIN i[41]
    DIRECTION INPUT ;
    USE SIGNAL ;
    PORT
      LAYER M4 ;
        RECT  0 6.192 0.084 6.216 ;
    END
  END i[41]
  PIN i[42]
    DIRECTION INPUT ;
    USE SIGNAL ;
    PORT
      LAYER M4 ;
        RECT  0 6.288 0.084 6.312 ;
    END
  END i[42]
  PIN i[43]
    DIRECTION INPUT ;
    USE SIGNAL ;
    PORT
      LAYER M4 ;
        RECT  0 6.384 0.084 6.408 ;
    END
  END i[43]
  PIN i[44]
    DIRECTION INPUT ;
    USE SIGNAL ;
    PORT
      LAYER M4 ;
        RECT  0 6.48 0.084 6.504 ;
    END
  END i[44]
  PIN i[45]
    DIRECTION INPUT ;
    USE SIGNAL ;
    PORT
      LAYER M4 ;
        RECT  0 6.576 0.084 6.6 ;
    END
  END i[45]
  PIN i[46]
    DIRECTION INPUT ;
    USE SIGNAL ;
    PORT
      LAYER M4 ;
        RECT  0 6.672 0.084 6.696 ;
    END
  END i[46]
  PIN i[47]
    DIRECTION INPUT ;
    USE SIGNAL ;
    PORT
      LAYER M4 ;
        RECT  0 6.768 0.084 6.792 ;
    END
  END i[47]
  PIN i[48]
    DIRECTION INPUT ;
    USE SIGNAL ;
    PORT
      LAYER M4 ;
        RECT  0 6.864 0.084 6.888 ;
    END
  END i[48]
  PIN i[49]
    DIRECTION INPUT ;
    USE SIGNAL ;
    PORT
      LAYER M4 ;
        RECT  0 6.96 0.084 6.984 ;
    END
  END i[49]
  PIN i[4]
    DIRECTION INPUT ;
    USE SIGNAL ;
    PORT
      LAYER M4 ;
        RECT  0 2.544 0.084 2.568 ;
    END
  END i[4]
  PIN i[50]
    DIRECTION INPUT ;
    USE SIGNAL ;
    PORT
      LAYER M4 ;
        RECT  0 7.056 0.084 7.08 ;
    END
  END i[50]
  PIN i[51]
    DIRECTION INPUT ;
    USE SIGNAL ;
    PORT
      LAYER M4 ;
        RECT  0 7.152 0.084 7.176 ;
    END
  END i[51]
  PIN i[52]
    DIRECTION INPUT ;
    USE SIGNAL ;
    PORT
      LAYER M4 ;
        RECT  0 7.248 0.084 7.272 ;
    END
  END i[52]
  PIN i[53]
    DIRECTION INPUT ;
    USE SIGNAL ;
    PORT
      LAYER M4 ;
        RECT  0 7.344 0.084 7.368 ;
    END
  END i[53]
  PIN i[54]
    DIRECTION INPUT ;
    USE SIGNAL ;
    PORT
      LAYER M4 ;
        RECT  0 7.44 0.084 7.464 ;
    END
  END i[54]
  PIN i[55]
    DIRECTION INPUT ;
    USE SIGNAL ;
    PORT
      LAYER M4 ;
        RECT  0 7.536 0.084 7.56 ;
    END
  END i[55]
  PIN i[56]
    DIRECTION INPUT ;
    USE SIGNAL ;
    PORT
      LAYER M4 ;
        RECT  0 7.632 0.084 7.656 ;
    END
  END i[56]
  PIN i[57]
    DIRECTION INPUT ;
    USE SIGNAL ;
    PORT
      LAYER M4 ;
        RECT  0 7.728 0.084 7.752 ;
    END
  END i[57]
  PIN i[58]
    DIRECTION INPUT ;
    USE SIGNAL ;
    PORT
      LAYER M4 ;
        RECT  0 7.824 0.084 7.848 ;
    END
  END i[58]
  PIN i[59]
    DIRECTION INPUT ;
    USE SIGNAL ;
    PORT
      LAYER M4 ;
        RECT  0 7.92 0.084 7.944 ;
    END
  END i[59]
  PIN i[5]
    DIRECTION INPUT ;
    USE SIGNAL ;
    PORT
      LAYER M4 ;
        RECT  0 2.64 0.084 2.664 ;
    END
  END i[5]
  PIN i[60]
    DIRECTION INPUT ;
    USE SIGNAL ;
    PORT
      LAYER M4 ;
        RECT  0 8.016 0.084 8.04 ;
    END
  END i[60]
  PIN i[61]
    DIRECTION INPUT ;
    USE SIGNAL ;
    PORT
      LAYER M4 ;
        RECT  0 8.112 0.084 8.136 ;
    END
  END i[61]
  PIN i[62]
    DIRECTION INPUT ;
    USE SIGNAL ;
    PORT
      LAYER M4 ;
        RECT  0 8.208 0.084 8.232 ;
    END
  END i[62]
  PIN i[6]
    DIRECTION INPUT ;
    USE SIGNAL ;
    PORT
      LAYER M4 ;
        RECT  0 2.736 0.084 2.76 ;
    END
  END i[6]
  PIN i[7]
    DIRECTION INPUT ;
    USE SIGNAL ;
    PORT
      LAYER M4 ;
        RECT  0 2.832 0.084 2.856 ;
    END
  END i[7]
  PIN i[8]
    DIRECTION INPUT ;
    USE SIGNAL ;
    PORT
      LAYER M4 ;
        RECT  0 2.928 0.084 2.952 ;
    END
  END i[8]
  PIN i[9]
    DIRECTION INPUT ;
    USE SIGNAL ;
    PORT
      LAYER M4 ;
        RECT  0 3.024 0.084 3.048 ;
    END
  END i[9]
  PIN o[0]
    DIRECTION OUTPUT ;
    USE SIGNAL ;
    PORT
      LAYER M5 ;
        RECT  6.864 0 6.888 0.084 ;
    END
  END o[0]
  PIN o[10]
    DIRECTION OUTPUT ;
    USE SIGNAL ;
    PORT
      LAYER M5 ;
        RECT  7.824 0 7.848 0.084 ;
    END
  END o[10]
  PIN o[11]
    DIRECTION OUTPUT ;
    USE SIGNAL ;
    PORT
      LAYER M5 ;
        RECT  7.92 0 7.944 0.084 ;
    END
  END o[11]
  PIN o[12]
    DIRECTION OUTPUT ;
    USE SIGNAL ;
    PORT
      LAYER M5 ;
        RECT  8.016 0 8.04 0.084 ;
    END
  END o[12]
  PIN o[13]
    DIRECTION OUTPUT ;
    USE SIGNAL ;
    PORT
      LAYER M5 ;
        RECT  8.112 0 8.136 0.084 ;
    END
  END o[13]
  PIN o[14]
    DIRECTION OUTPUT ;
    USE SIGNAL ;
    PORT
      LAYER M5 ;
        RECT  8.208 0 8.232 0.084 ;
    END
  END o[14]
  PIN o[15]
    DIRECTION OUTPUT ;
    USE SIGNAL ;
    PORT
      LAYER M5 ;
        RECT  8.304 0 8.328 0.084 ;
    END
  END o[15]
  PIN o[16]
    DIRECTION OUTPUT ;
    USE SIGNAL ;
    PORT
      LAYER M5 ;
        RECT  8.4 0 8.424 0.084 ;
    END
  END o[16]
  PIN o[17]
    DIRECTION OUTPUT ;
    USE SIGNAL ;
    PORT
      LAYER M5 ;
        RECT  8.496 0 8.52 0.084 ;
    END
  END o[17]
  PIN o[18]
    DIRECTION OUTPUT ;
    USE SIGNAL ;
    PORT
      LAYER M5 ;
        RECT  8.592 0 8.616 0.084 ;
    END
  END o[18]
  PIN o[19]
    DIRECTION OUTPUT ;
    USE SIGNAL ;
    PORT
      LAYER M5 ;
        RECT  8.688 0 8.712 0.084 ;
    END
  END o[19]
  PIN o[1]
    DIRECTION OUTPUT ;
    USE SIGNAL ;
    PORT
      LAYER M5 ;
        RECT  6.96 0 6.984 0.084 ;
    END
  END o[1]
  PIN o[20]
    DIRECTION OUTPUT ;
    USE SIGNAL ;
    PORT
      LAYER M5 ;
        RECT  8.784 0 8.808 0.084 ;
    END
  END o[20]
  PIN o[21]
    DIRECTION OUTPUT ;
    USE SIGNAL ;
    PORT
      LAYER M5 ;
        RECT  8.88 0 8.904 0.084 ;
    END
  END o[21]
  PIN o[22]
    DIRECTION OUTPUT ;
    USE SIGNAL ;
    PORT
      LAYER M5 ;
        RECT  8.976 0 9 0.084 ;
    END
  END o[22]
  PIN o[23]
    DIRECTION OUTPUT ;
    USE SIGNAL ;
    PORT
      LAYER M5 ;
        RECT  9.072 0 9.096 0.084 ;
    END
  END o[23]
  PIN o[24]
    DIRECTION OUTPUT ;
    USE SIGNAL ;
    PORT
      LAYER M5 ;
        RECT  9.168 0 9.192 0.084 ;
    END
  END o[24]
  PIN o[25]
    DIRECTION OUTPUT ;
    USE SIGNAL ;
    PORT
      LAYER M5 ;
        RECT  9.264 0 9.288 0.084 ;
    END
  END o[25]
  PIN o[26]
    DIRECTION OUTPUT ;
    USE SIGNAL ;
    PORT
      LAYER M5 ;
        RECT  9.36 0 9.384 0.084 ;
    END
  END o[26]
  PIN o[27]
    DIRECTION OUTPUT ;
    USE SIGNAL ;
    PORT
      LAYER M5 ;
        RECT  9.456 0 9.48 0.084 ;
    END
  END o[27]
  PIN o[28]
    DIRECTION OUTPUT ;
    USE SIGNAL ;
    PORT
      LAYER M5 ;
        RECT  9.552 0 9.576 0.084 ;
    END
  END o[28]
  PIN o[29]
    DIRECTION OUTPUT ;
    USE SIGNAL ;
    PORT
      LAYER M5 ;
        RECT  9.648 0 9.672 0.084 ;
    END
  END o[29]
  PIN o[2]
    DIRECTION OUTPUT ;
    USE SIGNAL ;
    PORT
      LAYER M5 ;
        RECT  7.056 0 7.08 0.084 ;
    END
  END o[2]
  PIN o[30]
    DIRECTION OUTPUT ;
    USE SIGNAL ;
    PORT
      LAYER M5 ;
        RECT  9.744 0 9.768 0.084 ;
    END
  END o[30]
  PIN o[31]
    DIRECTION OUTPUT ;
    USE SIGNAL ;
    PORT
      LAYER M5 ;
        RECT  9.84 0 9.864 0.084 ;
    END
  END o[31]
  PIN o[32]
    DIRECTION OUTPUT ;
    USE SIGNAL ;
    PORT
      LAYER M5 ;
        RECT  9.936 0 9.96 0.084 ;
    END
  END o[32]
  PIN o[33]
    DIRECTION OUTPUT ;
    USE SIGNAL ;
    PORT
      LAYER M5 ;
        RECT  10.032 0 10.056 0.084 ;
    END
  END o[33]
  PIN o[34]
    DIRECTION OUTPUT ;
    USE SIGNAL ;
    PORT
      LAYER M5 ;
        RECT  10.128 0 10.152 0.084 ;
    END
  END o[34]
  PIN o[35]
    DIRECTION OUTPUT ;
    USE SIGNAL ;
    PORT
      LAYER M5 ;
        RECT  10.224 0 10.248 0.084 ;
    END
  END o[35]
  PIN o[36]
    DIRECTION OUTPUT ;
    USE SIGNAL ;
    PORT
      LAYER M5 ;
        RECT  10.32 0 10.344 0.084 ;
    END
  END o[36]
  PIN o[37]
    DIRECTION OUTPUT ;
    USE SIGNAL ;
    PORT
      LAYER M5 ;
        RECT  10.416 0 10.44 0.084 ;
    END
  END o[37]
  PIN o[38]
    DIRECTION OUTPUT ;
    USE SIGNAL ;
    PORT
      LAYER M5 ;
        RECT  10.512 0 10.536 0.084 ;
    END
  END o[38]
  PIN o[39]
    DIRECTION OUTPUT ;
    USE SIGNAL ;
    PORT
      LAYER M5 ;
        RECT  10.608 0 10.632 0.084 ;
    END
  END o[39]
  PIN o[3]
    DIRECTION OUTPUT ;
    USE SIGNAL ;
    PORT
      LAYER M5 ;
        RECT  7.152 0 7.176 0.084 ;
    END
  END o[3]
  PIN o[40]
    DIRECTION OUTPUT ;
    USE SIGNAL ;
    PORT
      LAYER M5 ;
        RECT  10.704 0 10.728 0.084 ;
    END
  END o[40]
  PIN o[41]
    DIRECTION OUTPUT ;
    USE SIGNAL ;
    PORT
      LAYER M5 ;
        RECT  10.8 0 10.824 0.084 ;
    END
  END o[41]
  PIN o[42]
    DIRECTION OUTPUT ;
    USE SIGNAL ;
    PORT
      LAYER M5 ;
        RECT  10.896 0 10.92 0.084 ;
    END
  END o[42]
  PIN o[43]
    DIRECTION OUTPUT ;
    USE SIGNAL ;
    PORT
      LAYER M5 ;
        RECT  10.992 0 11.016 0.084 ;
    END
  END o[43]
  PIN o[44]
    DIRECTION OUTPUT ;
    USE SIGNAL ;
    PORT
      LAYER M5 ;
        RECT  11.088 0 11.112 0.084 ;
    END
  END o[44]
  PIN o[45]
    DIRECTION OUTPUT ;
    USE SIGNAL ;
    PORT
      LAYER M5 ;
        RECT  11.184 0 11.208 0.084 ;
    END
  END o[45]
  PIN o[46]
    DIRECTION OUTPUT ;
    USE SIGNAL ;
    PORT
      LAYER M5 ;
        RECT  11.28 0 11.304 0.084 ;
    END
  END o[46]
  PIN o[47]
    DIRECTION OUTPUT ;
    USE SIGNAL ;
    PORT
      LAYER M5 ;
        RECT  11.376 0 11.4 0.084 ;
    END
  END o[47]
  PIN o[48]
    DIRECTION OUTPUT ;
    USE SIGNAL ;
    PORT
      LAYER M5 ;
        RECT  11.472 0 11.496 0.084 ;
    END
  END o[48]
  PIN o[49]
    DIRECTION OUTPUT ;
    USE SIGNAL ;
    PORT
      LAYER M5 ;
        RECT  11.568 0 11.592 0.084 ;
    END
  END o[49]
  PIN o[4]
    DIRECTION OUTPUT ;
    USE SIGNAL ;
    PORT
      LAYER M5 ;
        RECT  7.248 0 7.272 0.084 ;
    END
  END o[4]
  PIN o[50]
    DIRECTION OUTPUT ;
    USE SIGNAL ;
    PORT
      LAYER M5 ;
        RECT  11.664 0 11.688 0.084 ;
    END
  END o[50]
  PIN o[51]
    DIRECTION OUTPUT ;
    USE SIGNAL ;
    PORT
      LAYER M5 ;
        RECT  11.76 0 11.784 0.084 ;
    END
  END o[51]
  PIN o[52]
    DIRECTION OUTPUT ;
    USE SIGNAL ;
    PORT
      LAYER M5 ;
        RECT  11.856 0 11.88 0.084 ;
    END
  END o[52]
  PIN o[53]
    DIRECTION OUTPUT ;
    USE SIGNAL ;
    PORT
      LAYER M5 ;
        RECT  11.952 0 11.976 0.084 ;
    END
  END o[53]
  PIN o[54]
    DIRECTION OUTPUT ;
    USE SIGNAL ;
    PORT
      LAYER M5 ;
        RECT  12.048 0 12.072 0.084 ;
    END
  END o[54]
  PIN o[55]
    DIRECTION OUTPUT ;
    USE SIGNAL ;
    PORT
      LAYER M5 ;
        RECT  12.144 0 12.168 0.084 ;
    END
  END o[55]
  PIN o[56]
    DIRECTION OUTPUT ;
    USE SIGNAL ;
    PORT
      LAYER M5 ;
        RECT  12.24 0 12.264 0.084 ;
    END
  END o[56]
  PIN o[57]
    DIRECTION OUTPUT ;
    USE SIGNAL ;
    PORT
      LAYER M5 ;
        RECT  12.336 0 12.36 0.084 ;
    END
  END o[57]
  PIN o[58]
    DIRECTION OUTPUT ;
    USE SIGNAL ;
    PORT
      LAYER M5 ;
        RECT  12.432 0 12.456 0.084 ;
    END
  END o[58]
  PIN o[59]
    DIRECTION OUTPUT ;
    USE SIGNAL ;
    PORT
      LAYER M5 ;
        RECT  12.528 0 12.552 0.084 ;
    END
  END o[59]
  PIN o[5]
    DIRECTION OUTPUT ;
    USE SIGNAL ;
    PORT
      LAYER M5 ;
        RECT  7.344 0 7.368 0.084 ;
    END
  END o[5]
  PIN o[60]
    DIRECTION OUTPUT ;
    USE SIGNAL ;
    PORT
      LAYER M5 ;
        RECT  12.624 0 12.648 0.084 ;
    END
  END o[60]
  PIN o[61]
    DIRECTION OUTPUT ;
    USE SIGNAL ;
    PORT
      LAYER M5 ;
        RECT  12.72 0 12.744 0.084 ;
    END
  END o[61]
  PIN o[62]
    DIRECTION OUTPUT ;
    USE SIGNAL ;
    PORT
      LAYER M5 ;
        RECT  12.816 0 12.84 0.084 ;
    END
  END o[62]
  PIN o[6]
    DIRECTION OUTPUT ;
    USE SIGNAL ;
    PORT
      LAYER M5 ;
        RECT  7.44 0 7.464 0.084 ;
    END
  END o[6]
  PIN o[7]
    DIRECTION OUTPUT ;
    USE SIGNAL ;
    PORT
      LAYER M5 ;
        RECT  7.536 0 7.56 0.084 ;
    END
  END o[7]
  PIN o[8]
    DIRECTION OUTPUT ;
    USE SIGNAL ;
    PORT
      LAYER M5 ;
        RECT  7.632 0 7.656 0.084 ;
    END
  END o[8]
  PIN o[9]
    DIRECTION OUTPUT ;
    USE SIGNAL ;
    PORT
      LAYER M5 ;
        RECT  7.728 0 7.752 0.084 ;
    END
  END o[9]
  PIN rs
    DIRECTION INPUT ;
    USE SIGNAL ;
    PORT
      LAYER M5 ;
        RECT  9.744 15.036 9.768 15.12 ;
    END
  END rs
  PIN VDD
    DIRECTION INOUT ;
    USE POWER ;
    PORT
      LAYER M5 ;
        RECT  10.692 2.151 10.812 12.969 ;
        RECT  7.992 2.151 8.112 12.969 ;
        RECT  5.292 2.151 5.412 12.969 ;
        RECT  2.592 2.151 2.712 12.969 ;
    END
  END VDD
  PIN VSS
    DIRECTION INOUT ;
    USE GROUND ;
    PORT
      LAYER M5 ;
        RECT  10.5 2.137 10.62 12.983 ;
        RECT  7.8 2.137 7.92 12.983 ;
        RECT  5.1 2.137 5.22 12.983 ;
        RECT  2.4 2.137 2.52 12.983 ;
    END
  END VSS
  OBS
    LAYER RVTN ;
     RECT  2.16 2.16 12.96 2.295 ;
     RECT  2.16 2.565 12.96 2.835 ;
     RECT  2.16 3.105 12.96 3.375 ;
     RECT  2.16 3.645 12.96 3.915 ;
     RECT  2.16 4.185 12.96 4.455 ;
     RECT  2.16 4.725 12.96 4.995 ;
     RECT  2.16 5.265 12.96 5.535 ;
     RECT  2.16 5.805 12.96 6.075 ;
     RECT  2.16 6.345 12.96 6.615 ;
     RECT  2.16 6.885 12.96 7.155 ;
     RECT  2.16 7.425 12.96 7.695 ;
     RECT  2.16 7.965 12.96 8.235 ;
     RECT  2.16 8.505 12.96 8.775 ;
     RECT  2.16 9.045 12.96 9.315 ;
     RECT  2.16 9.585 12.96 9.855 ;
     RECT  2.16 10.125 12.96 10.395 ;
     RECT  2.16 10.665 12.96 10.935 ;
     RECT  2.16 11.205 12.96 11.475 ;
     RECT  2.16 11.745 12.96 12.015 ;
     RECT  2.16 12.285 12.96 12.555 ;
     RECT  2.16 12.825 12.96 12.96 ;
    LAYER RVTP ;
     RECT  2.16 2.295 12.96 2.565 ;
     RECT  2.16 2.835 12.96 3.105 ;
     RECT  2.16 3.375 12.96 3.645 ;
     RECT  2.16 3.915 12.96 4.185 ;
     RECT  2.16 4.455 12.96 4.725 ;
     RECT  2.16 4.995 12.96 5.265 ;
     RECT  2.16 5.535 12.96 5.805 ;
     RECT  2.16 6.075 12.96 6.345 ;
     RECT  2.16 6.615 12.96 6.885 ;
     RECT  2.16 7.155 12.96 7.425 ;
     RECT  2.16 7.695 12.96 7.965 ;
     RECT  2.16 8.235 12.96 8.505 ;
     RECT  2.16 8.775 12.96 9.045 ;
     RECT  2.16 9.315 12.96 9.585 ;
     RECT  2.16 9.855 12.96 10.125 ;
     RECT  2.16 10.395 12.96 10.665 ;
     RECT  2.16 10.935 12.96 11.205 ;
     RECT  2.16 11.475 12.96 11.745 ;
     RECT  2.16 12.015 12.96 12.285 ;
     RECT  2.16 12.555 12.96 12.825 ;
    LAYER M1 ;
     RECT  2.16 2.151 12.96 12.969 ;
    LAYER M2 ;
     RECT  0.175 8.442 0.211 8.46 ;
     RECT  0.139 6.12 0.319 6.678 ;
     RECT  0.247 5.238 0.535 5.256 ;
     RECT  0.319 6.12 0.563 7.254 ;
     RECT  0.211 3.96 0.823 3.978 ;
     RECT  0.103 9.324 1.147 9.342 ;
     RECT  1.147 9.324 1.291 9.54 ;
     RECT  0.211 8.01 1.723 8.46 ;
     RECT  1.291 9.324 1.723 9.612 ;
     RECT  0.823 3.96 2.119 4.446 ;
     RECT  2.119 3.96 2.16 4.482 ;
     RECT  0.535 5.238 2.16 5.328 ;
     RECT  0.563 6.12 2.16 6.408 ;
     RECT  0.563 7.236 2.16 7.254 ;
     RECT  1.723 8.01 2.16 9.612 ;
     RECT  0.535 10.404 2.16 10.422 ;
     RECT  2.16 2.151 10.723 12.969 ;
     RECT  10.723 2.106 11.399 12.969 ;
     RECT  11.399 2.151 12.96 12.969 ;
    LAYER M3 ;
     RECT  10.872 0.091 11.682 0.139 ;
     RECT  12.672 0.091 12.69 0.139 ;
     RECT  7.488 0.091 7.506 0.571 ;
     RECT  8.352 0.091 8.658 0.571 ;
     RECT  9.612 0.091 9.63 0.571 ;
     RECT  10.872 0.139 12.69 0.571 ;
     RECT  9.612 0.571 12.69 0.619 ;
     RECT  7.488 0.571 8.658 1.147 ;
     RECT  7.128 1.147 8.658 1.723 ;
     RECT  9.432 0.619 12.69 1.723 ;
     RECT  2.415 2.143 2.505 2.155 ;
     RECT  2.304 2.155 2.505 2.191 ;
     RECT  6.948 1.723 12.69 2.191 ;
     RECT  2.304 2.191 2.61 2.227 ;
     RECT  6.696 2.191 12.69 2.299 ;
     RECT  6.696 2.299 12.762 2.347 ;
     RECT  6.696 2.347 12.834 2.371 ;
     RECT  5.115 2.143 5.205 2.413 ;
     RECT  2.304 2.227 2.862 2.461 ;
     RECT  4.068 2.263 4.086 2.461 ;
     RECT  5.115 2.413 5.397 2.461 ;
     RECT  4.068 2.461 5.397 2.497 ;
     RECT  4.032 2.497 5.397 2.533 ;
     RECT  2.304 2.461 3.006 2.569 ;
     RECT  6.66 2.371 12.834 2.569 ;
     RECT  2.304 2.569 3.222 2.605 ;
     RECT  6.66 2.569 12.87 2.605 ;
     RECT  2.268 2.605 3.222 2.641 ;
     RECT  3.996 2.533 5.397 2.641 ;
     RECT  6.372 2.605 12.87 2.641 ;
     RECT  2.268 2.641 12.87 2.839 ;
     RECT  2.268 2.839 12.906 3.211 ;
     RECT  0.828 2.827 0.846 3.787 ;
     RECT  0.324 3.787 0.846 3.955 ;
     RECT  0.216 3.955 0.846 3.979 ;
     RECT  0.144 3.979 0.846 4.451 ;
     RECT  2.124 3.211 12.906 4.487 ;
     RECT  0.144 4.451 0.198 4.939 ;
     RECT  0.108 4.939 0.198 5.233 ;
     RECT  0.108 5.233 0.27 5.305 ;
     RECT  2.232 4.487 12.906 5.999 ;
     RECT  0.108 5.305 0.558 6.091 ;
     RECT  0.108 6.091 1.17 6.221 ;
     RECT  2.232 5.999 12.834 6.269 ;
     RECT  2.232 6.269 12.798 6.475 ;
     RECT  2.196 6.475 12.798 6.809 ;
     RECT  0.108 6.221 0.558 7.243 ;
     RECT  1.296 6.955 1.314 7.243 ;
     RECT  0.108 7.243 1.314 7.723 ;
     RECT  2.196 6.809 12.726 7.723 ;
     RECT  0.108 7.723 12.726 8.699 ;
     RECT  0.108 8.699 12.618 8.969 ;
     RECT  0.108 8.969 3.978 9.005 ;
     RECT  0.108 9.005 1.314 9.347 ;
     RECT  0.54 9.347 1.314 9.545 ;
     RECT  1.296 9.545 1.314 9.617 ;
     RECT  2.304 9.005 3.978 9.751 ;
     RECT  4.752 8.969 12.618 9.751 ;
     RECT  2.304 9.751 12.618 10.049 ;
     RECT  2.304 10.049 9.774 10.121 ;
     RECT  2.304 10.121 4.194 10.163 ;
     RECT  0.54 9.545 0.558 10.427 ;
     RECT  10.515 10.049 12.618 10.589 ;
     RECT  5.115 10.121 9.774 10.831 ;
     RECT  10.515 10.589 12.51 10.831 ;
     RECT  5.115 10.831 12.51 10.891 ;
     RECT  2.304 10.163 4.122 11.165 ;
     RECT  2.415 11.165 4.122 11.371 ;
     RECT  5.004 10.891 12.51 11.399 ;
     RECT  5.004 11.399 9.774 11.408 ;
     RECT  9.432 11.408 9.774 11.453 ;
     RECT  10.515 11.399 11.97 11.471 ;
     RECT  2.415 11.371 4.158 11.479 ;
     RECT  5.004 11.408 8.55 11.479 ;
     RECT  11.52 11.471 11.97 11.507 ;
     RECT  11.952 11.507 11.97 11.543 ;
     RECT  9.432 11.453 9.666 11.741 ;
     RECT  2.415 11.479 8.55 11.939 ;
     RECT  2.415 11.939 8.097 11.975 ;
     RECT  2.415 11.975 3.33 12.047 ;
     RECT  4.14 11.975 8.097 12.047 ;
     RECT  4.14 12.047 5.397 12.119 ;
     RECT  4.14 12.119 4.302 12.209 ;
     RECT  6.12 12.047 8.097 12.209 ;
     RECT  2.415 12.047 3.114 12.245 ;
     RECT  6.12 12.209 6.822 12.245 ;
     RECT  6.696 12.245 6.714 12.281 ;
     RECT  9.648 11.741 9.666 12.325 ;
     RECT  10.515 11.471 10.797 12.325 ;
     RECT  9.648 12.325 10.797 12.389 ;
     RECT  2.415 12.245 2.697 12.707 ;
     RECT  5.115 12.119 5.397 12.707 ;
     RECT  7.815 12.209 8.097 12.707 ;
     RECT  9.756 12.389 10.797 12.707 ;
     RECT  9.756 12.707 10.605 12.749 ;
     RECT  2.415 12.707 2.505 12.977 ;
     RECT  5.115 12.707 5.205 12.977 ;
     RECT  7.815 12.707 7.905 12.977 ;
     RECT  10.515 12.749 10.605 12.977 ;
     RECT  9.756 12.749 9.774 13.085 ;
    LAYER M4 ;
     RECT  0.06 2.16 2.365 8.232 ;
     RECT  2.293 9.264 2.365 9.288 ;
     RECT  2.365 2.16 2.408 9.288 ;
     RECT  2.408 2.148 2.512 12.972 ;
     RECT  2.512 2.256 2.585 12.702 ;
     RECT  2.585 2.352 2.704 12.702 ;
     RECT  2.704 2.352 2.801 7.944 ;
     RECT  2.801 3.888 2.819 7.944 ;
     RECT  2.704 9.12 2.867 11.64 ;
     RECT  2.801 2.352 2.873 2.376 ;
     RECT  2.867 9.552 3.203 11.64 ;
     RECT  3.203 10.128 3.443 11.64 ;
     RECT  3.443 11.616 3.485 11.64 ;
     RECT  3.949 11.664 4.705 11.688 ;
     RECT  3.443 10.128 4.993 10.152 ;
     RECT  4.705 11.664 4.993 11.784 ;
     RECT  2.819 3.984 5.108 7.944 ;
     RECT  4.993 10.128 5.108 11.784 ;
     RECT  5.108 2.148 5.212 12.972 ;
     RECT  5.212 2.418 5.404 12.702 ;
     RECT  5.404 9.696 6.172 12.024 ;
     RECT  5.404 5.568 6.433 8.424 ;
     RECT  6.172 9.696 6.437 11.688 ;
     RECT  6.433 5.472 6.721 8.424 ;
     RECT  6.437 9.696 6.721 11.4 ;
     RECT  6.721 5.472 6.833 11.4 ;
     RECT  6.853 1.728 7.045 1.752 ;
     RECT  6.949 2.88 7.109 2.904 ;
     RECT  7.045 1.152 7.3 1.752 ;
     RECT  7.109 2.88 7.477 3.432 ;
     RECT  7.3 1.152 7.525 1.8 ;
     RECT  7.477 2.832 7.525 3.432 ;
     RECT  6.833 5.472 7.573 11.016 ;
     RECT  7.573 4.944 7.621 11.016 ;
     RECT  7.525 1.152 7.808 3.432 ;
     RECT  7.621 4.56 7.808 11.016 ;
     RECT  7.808 1.152 7.912 12.972 ;
     RECT  7.429 0.096 8.101 0.12 ;
     RECT  7.912 1.152 8.101 12.702 ;
     RECT  8.101 0.096 8.104 12.702 ;
     RECT  8.104 0.096 8.165 1.752 ;
     RECT  8.104 2.784 8.749 2.904 ;
     RECT  8.104 4.944 8.921 10.104 ;
     RECT  8.921 4.944 9.065 5.496 ;
     RECT  8.921 6.672 9.137 10.104 ;
     RECT  9.065 4.944 9.245 4.968 ;
     RECT  8.165 0.096 9.349 0.6 ;
     RECT  8.165 1.728 9.565 1.752 ;
     RECT  9.349 0.096 9.641 0.648 ;
     RECT  9.641 0.144 9.673 0.648 ;
     RECT  9.565 1.728 9.673 2.28 ;
     RECT  9.137 6.864 9.673 10.104 ;
     RECT  8.104 11.088 9.673 11.4 ;
     RECT  9.673 6.864 9.745 11.4 ;
     RECT  9.673 0.144 9.779 2.28 ;
     RECT  9.701 13.056 9.785 13.08 ;
     RECT  9.845 4.56 10.097 4.584 ;
     RECT  9.779 1.728 10.172 2.28 ;
     RECT  9.779 0.144 10.181 0.6 ;
     RECT  9.745 6.864 10.249 11.448 ;
     RECT  10.249 6.048 10.261 11.448 ;
     RECT  10.097 3.984 10.268 4.584 ;
     RECT  10.261 5.76 10.268 11.448 ;
     RECT  10.181 0.144 10.403 0.264 ;
     RECT  10.172 1.728 10.508 2.664 ;
     RECT  10.268 3.984 10.508 11.448 ;
     RECT  10.508 1.728 10.612 12.972 ;
     RECT  10.403 0.144 10.693 0.168 ;
     RECT  10.612 1.728 10.804 12.702 ;
     RECT  10.804 8.448 10.937 11.448 ;
     RECT  10.937 8.448 11.009 9.384 ;
     RECT  11.009 8.448 11.189 8.472 ;
     RECT  10.937 10.944 11.225 11.448 ;
     RECT  10.804 1.728 11.411 2.28 ;
     RECT  11.225 10.944 11.549 10.968 ;
     RECT  11.411 1.728 11.621 2.184 ;
     RECT  10.693 0.096 11.689 0.168 ;
     RECT  10.804 3.408 11.833 3.432 ;
     RECT  10.804 5.52 11.837 5.544 ;
     RECT  11.689 0.096 12.005 0.552 ;
     RECT  11.621 1.728 12.092 1.752 ;
     RECT  11.833 3.168 12.275 3.432 ;
     RECT  12.221 8.544 12.305 8.568 ;
     RECT  12.005 0.096 12.449 0.6 ;
     RECT  12.092 1.68 12.485 1.752 ;
     RECT  12.572 1.104 12.659 1.128 ;
     RECT  12.449 0.096 12.701 0.12 ;
     RECT  12.689 2.304 12.773 2.376 ;
     RECT  12.517 3.984 12.773 4.008 ;
     RECT  12.773 2.352 12.889 2.376 ;
    LAYER M5 ;
     RECT  6.864 0.016 12.84 1.763 ;
     RECT  2.4 2.137 2.52 2.151 ;
     RECT  5.1 2.137 5.22 2.151 ;
     RECT  12.528 1.763 12.84 2.387 ;
     RECT  6.96 1.763 11.496 2.915 ;
     RECT  7.152 2.915 11.496 3.157 ;
     RECT  12.528 2.387 12.552 3.157 ;
     RECT  7.152 3.157 12.552 3.443 ;
     RECT  2.4 2.151 2.712 3.589 ;
     RECT  2.304 3.589 2.712 3.877 ;
     RECT  0.144 3.637 0.168 3.923 ;
     RECT  5.1 2.151 5.412 3.973 ;
     RECT  12.24 3.443 12.552 4.019 ;
     RECT  2.304 3.877 2.808 4.117 ;
     RECT  7.488 3.443 10.812 4.595 ;
     RECT  4.752 3.973 5.412 5.029 ;
     RECT  7.488 4.595 9.096 5.461 ;
     RECT  0.144 5.845 0.168 6.035 ;
     RECT  6.624 5.461 9.096 6.323 ;
     RECT  6.72 6.323 9.096 6.803 ;
     RECT  4.176 5.029 5.412 6.899 ;
     RECT  10.224 4.595 10.812 7.381 ;
     RECT  0.144 7.477 0.168 7.667 ;
     RECT  9.648 7.381 10.812 8.485 ;
     RECT  12.24 4.019 12.264 8.579 ;
     RECT  2.304 4.117 2.856 9.299 ;
     RECT  2.4 9.299 2.856 9.541 ;
     RECT  5.1 6.899 5.412 9.877 ;
     RECT  6.72 6.803 8.112 9.877 ;
     RECT  5.1 9.877 8.112 10.115 ;
     RECT  9.264 8.485 10.812 10.115 ;
     RECT  5.1 10.115 6.312 10.691 ;
     RECT  2.4 9.541 3.192 10.789 ;
     RECT  7.584 10.115 8.112 10.883 ;
     RECT  2.4 10.789 3.432 11.651 ;
     RECT  5.1 10.691 5.412 11.653 ;
     RECT  5.1 11.653 6.12 12.035 ;
     RECT  2.4 11.651 2.712 12.969 ;
     RECT  5.1 12.035 5.412 12.969 ;
     RECT  7.8 10.883 8.112 12.969 ;
     RECT  9.648 10.115 10.812 12.969 ;
     RECT  2.4 12.969 2.52 12.983 ;
     RECT  5.1 12.969 5.22 12.983 ;
     RECT  7.8 12.969 7.92 12.983 ;
     RECT  9.648 12.969 10.62 12.983 ;
     RECT  9.648 12.983 9.768 15.056 ;
  END
END dsfd_rly_63_WS

VERSION 5.8 ;
BUSBITCHARS "[]" ;
DIVIDERCHAR "/" ;
UNITS
    DATABASE MICRONS 1000 ;
END UNITS

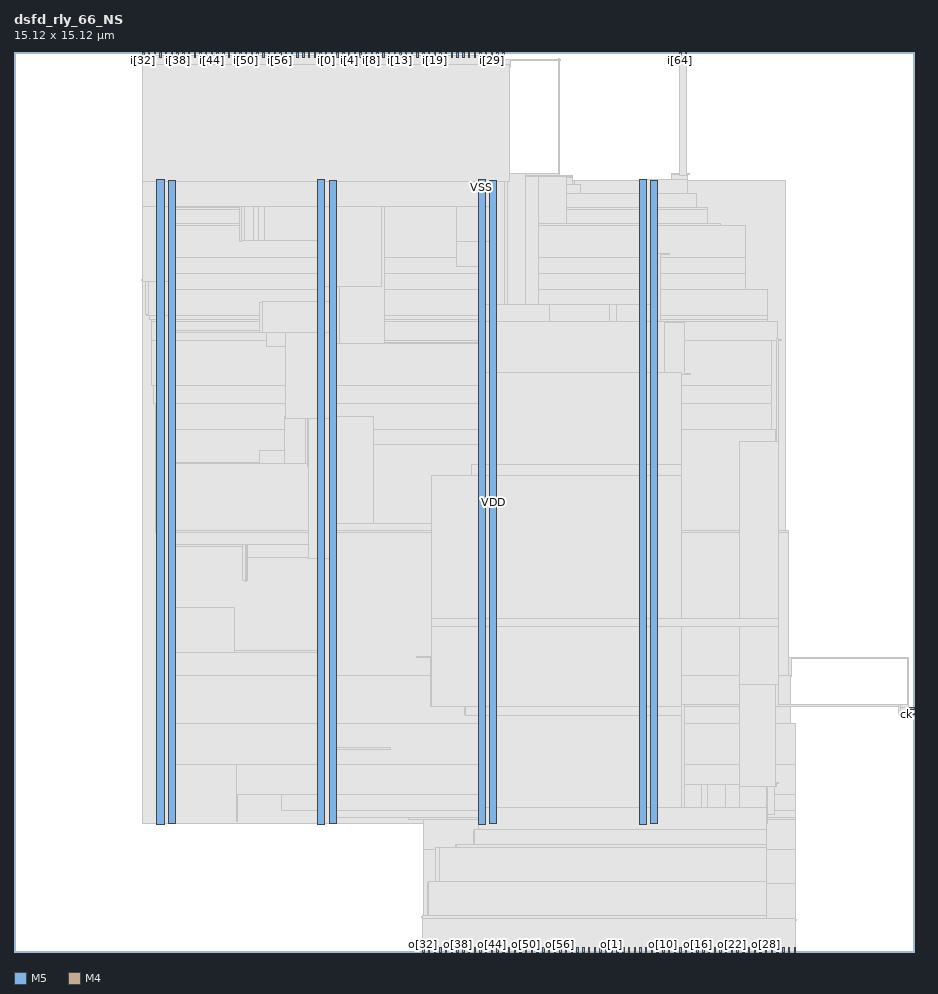
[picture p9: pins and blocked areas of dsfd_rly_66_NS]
MACRO dsfd_rly_66_NS
  FOREIGN dsfd_rly_66_NS 0 0 ;
  CLASS BLOCK ;
  SIZE 15.12 BY 15.12 ;
  PIN ck
    DIRECTION INPUT ;
    USE SIGNAL ;
    PORT
      LAYER M4 ;
        RECT  15.036 3.984 15.12 4.008 ;
    END
  END ck
  PIN i[0]
    DIRECTION INPUT ;
    USE SIGNAL ;
    PORT
      LAYER M5 ;
        RECT  5.232 15.036 5.256 15.12 ;
    END
  END i[0]
  PIN i[10]
    DIRECTION INPUT ;
    USE SIGNAL ;
    PORT
      LAYER M5 ;
        RECT  6.192 15.036 6.216 15.12 ;
    END
  END i[10]
  PIN i[11]
    DIRECTION INPUT ;
    USE SIGNAL ;
    PORT
      LAYER M5 ;
        RECT  6.288 15.036 6.312 15.12 ;
    END
  END i[11]
  PIN i[12]
    DIRECTION INPUT ;
    USE SIGNAL ;
    PORT
      LAYER M5 ;
        RECT  6.384 15.036 6.408 15.12 ;
    END
  END i[12]
  PIN i[13]
    DIRECTION INPUT ;
    USE SIGNAL ;
    PORT
      LAYER M5 ;
        RECT  6.48 15.036 6.504 15.12 ;
    END
  END i[13]
  PIN i[14]
    DIRECTION INPUT ;
    USE SIGNAL ;
    PORT
      LAYER M5 ;
        RECT  6.576 15.036 6.6 15.12 ;
    END
  END i[14]
  PIN i[15]
    DIRECTION INPUT ;
    USE SIGNAL ;
    PORT
      LAYER M5 ;
        RECT  6.672 15.036 6.696 15.12 ;
    END
  END i[15]
  PIN i[16]
    DIRECTION INPUT ;
    USE SIGNAL ;
    PORT
      LAYER M5 ;
        RECT  6.768 15.036 6.792 15.12 ;
    END
  END i[16]
  PIN i[17]
    DIRECTION INPUT ;
    USE SIGNAL ;
    PORT
      LAYER M5 ;
        RECT  6.864 15.036 6.888 15.12 ;
    END
  END i[17]
  PIN i[18]
    DIRECTION INPUT ;
    USE SIGNAL ;
    PORT
      LAYER M5 ;
        RECT  6.96 15.036 6.984 15.12 ;
    END
  END i[18]
  PIN i[19]
    DIRECTION INPUT ;
    USE SIGNAL ;
    PORT
      LAYER M5 ;
        RECT  7.056 15.036 7.08 15.12 ;
    END
  END i[19]
  PIN i[1]
    DIRECTION INPUT ;
    USE SIGNAL ;
    PORT
      LAYER M5 ;
        RECT  5.328 15.036 5.352 15.12 ;
    END
  END i[1]
  PIN i[20]
    DIRECTION INPUT ;
    USE SIGNAL ;
    PORT
      LAYER M5 ;
        RECT  7.152 15.036 7.176 15.12 ;
    END
  END i[20]
  PIN i[21]
    DIRECTION INPUT ;
    USE SIGNAL ;
    PORT
      LAYER M5 ;
        RECT  7.248 15.036 7.272 15.12 ;
    END
  END i[21]
  PIN i[22]
    DIRECTION INPUT ;
    USE SIGNAL ;
    PORT
      LAYER M5 ;
        RECT  7.344 15.036 7.368 15.12 ;
    END
  END i[22]
  PIN i[23]
    DIRECTION INPUT ;
    USE SIGNAL ;
    PORT
      LAYER M5 ;
        RECT  7.44 15.036 7.464 15.12 ;
    END
  END i[23]
  PIN i[24]
    DIRECTION INPUT ;
    USE SIGNAL ;
    PORT
      LAYER M5 ;
        RECT  7.536 15.036 7.56 15.12 ;
    END
  END i[24]
  PIN i[25]
    DIRECTION INPUT ;
    USE SIGNAL ;
    PORT
      LAYER M5 ;
        RECT  7.632 15.036 7.656 15.12 ;
    END
  END i[25]
  PIN i[26]
    DIRECTION INPUT ;
    USE SIGNAL ;
    PORT
      LAYER M5 ;
        RECT  7.728 15.036 7.752 15.12 ;
    END
  END i[26]
  PIN i[27]
    DIRECTION INPUT ;
    USE SIGNAL ;
    PORT
      LAYER M5 ;
        RECT  7.824 15.036 7.848 15.12 ;
    END
  END i[27]
  PIN i[28]
    DIRECTION INPUT ;
    USE SIGNAL ;
    PORT
      LAYER M5 ;
        RECT  7.92 15.036 7.944 15.12 ;
    END
  END i[28]
  PIN i[29]
    DIRECTION INPUT ;
    USE SIGNAL ;
    PORT
      LAYER M5 ;
        RECT  8.016 15.036 8.04 15.12 ;
    END
  END i[29]
  PIN i[2]
    DIRECTION INPUT ;
    USE SIGNAL ;
    PORT
      LAYER M5 ;
        RECT  5.424 15.036 5.448 15.12 ;
    END
  END i[2]
  PIN i[30]
    DIRECTION INPUT ;
    USE SIGNAL ;
    PORT
      LAYER M5 ;
        RECT  8.112 15.036 8.136 15.12 ;
    END
  END i[30]
  PIN i[31]
    DIRECTION INPUT ;
    USE SIGNAL ;
    PORT
      LAYER M5 ;
        RECT  8.208 15.036 8.232 15.12 ;
    END
  END i[31]
  PIN i[32]
    DIRECTION INPUT ;
    USE SIGNAL ;
    PORT
      LAYER M5 ;
        RECT  2.16 15.036 2.184 15.12 ;
    END
  END i[32]
  PIN i[33]
    DIRECTION INPUT ;
    USE SIGNAL ;
    PORT
      LAYER M5 ;
        RECT  2.256 15.036 2.28 15.12 ;
    END
  END i[33]
  PIN i[34]
    DIRECTION INPUT ;
    USE SIGNAL ;
    PORT
      LAYER M5 ;
        RECT  2.352 15.036 2.376 15.12 ;
    END
  END i[34]
  PIN i[35]
    DIRECTION INPUT ;
    USE SIGNAL ;
    PORT
      LAYER M5 ;
        RECT  2.448 15.036 2.472 15.12 ;
    END
  END i[35]
  PIN i[36]
    DIRECTION INPUT ;
    USE SIGNAL ;
    PORT
      LAYER M5 ;
        RECT  2.544 15.036 2.568 15.12 ;
    END
  END i[36]
  PIN i[37]
    DIRECTION INPUT ;
    USE SIGNAL ;
    PORT
      LAYER M5 ;
        RECT  2.64 15.036 2.664 15.12 ;
    END
  END i[37]
  PIN i[38]
    DIRECTION INPUT ;
    USE SIGNAL ;
    PORT
      LAYER M5 ;
        RECT  2.736 15.036 2.76 15.12 ;
    END
  END i[38]
  PIN i[39]
    DIRECTION INPUT ;
    USE SIGNAL ;
    PORT
      LAYER M5 ;
        RECT  2.832 15.036 2.856 15.12 ;
    END
  END i[39]
  PIN i[3]
    DIRECTION INPUT ;
    USE SIGNAL ;
    PORT
      LAYER M5 ;
        RECT  5.52 15.036 5.544 15.12 ;
    END
  END i[3]
  PIN i[40]
    DIRECTION INPUT ;
    USE SIGNAL ;
    PORT
      LAYER M5 ;
        RECT  2.928 15.036 2.952 15.12 ;
    END
  END i[40]
  PIN i[41]
    DIRECTION INPUT ;
    USE SIGNAL ;
    PORT
      LAYER M5 ;
        RECT  3.024 15.036 3.048 15.12 ;
    END
  END i[41]
  PIN i[42]
    DIRECTION INPUT ;
    USE SIGNAL ;
    PORT
      LAYER M5 ;
        RECT  3.12 15.036 3.144 15.12 ;
    END
  END i[42]
  PIN i[43]
    DIRECTION INPUT ;
    USE SIGNAL ;
    PORT
      LAYER M5 ;
        RECT  3.216 15.036 3.24 15.12 ;
    END
  END i[43]
  PIN i[44]
    DIRECTION INPUT ;
    USE SIGNAL ;
    PORT
      LAYER M5 ;
        RECT  3.312 15.036 3.336 15.12 ;
    END
  END i[44]
  PIN i[45]
    DIRECTION INPUT ;
    USE SIGNAL ;
    PORT
      LAYER M5 ;
        RECT  3.408 15.036 3.432 15.12 ;
    END
  END i[45]
  PIN i[46]
    DIRECTION INPUT ;
    USE SIGNAL ;
    PORT
      LAYER M5 ;
        RECT  3.504 15.036 3.528 15.12 ;
    END
  END i[46]
  PIN i[47]
    DIRECTION INPUT ;
    USE SIGNAL ;
    PORT
      LAYER M5 ;
        RECT  3.6 15.036 3.624 15.12 ;
    END
  END i[47]
  PIN i[48]
    DIRECTION INPUT ;
    USE SIGNAL ;
    PORT
      LAYER M5 ;
        RECT  3.696 15.036 3.72 15.12 ;
    END
  END i[48]
  PIN i[49]
    DIRECTION INPUT ;
    USE SIGNAL ;
    PORT
      LAYER M5 ;
        RECT  3.792 15.036 3.816 15.12 ;
    END
  END i[49]
  PIN i[4]
    DIRECTION INPUT ;
    USE SIGNAL ;
    PORT
      LAYER M5 ;
        RECT  5.616 15.036 5.64 15.12 ;
    END
  END i[4]
  PIN i[50]
    DIRECTION INPUT ;
    USE SIGNAL ;
    PORT
      LAYER M5 ;
        RECT  3.888 15.036 3.912 15.12 ;
    END
  END i[50]
  PIN i[51]
    DIRECTION INPUT ;
    USE SIGNAL ;
    PORT
      LAYER M5 ;
        RECT  3.984 15.036 4.008 15.12 ;
    END
  END i[51]
  PIN i[52]
    DIRECTION INPUT ;
    USE SIGNAL ;
    PORT
      LAYER M5 ;
        RECT  4.08 15.036 4.104 15.12 ;
    END
  END i[52]
  PIN i[53]
    DIRECTION INPUT ;
    USE SIGNAL ;
    PORT
      LAYER M5 ;
        RECT  4.176 15.036 4.2 15.12 ;
    END
  END i[53]
  PIN i[54]
    DIRECTION INPUT ;
    USE SIGNAL ;
    PORT
      LAYER M5 ;
        RECT  4.272 15.036 4.296 15.12 ;
    END
  END i[54]
  PIN i[55]
    DIRECTION INPUT ;
    USE SIGNAL ;
    PORT
      LAYER M5 ;
        RECT  4.368 15.036 4.392 15.12 ;
    END
  END i[55]
  PIN i[56]
    DIRECTION INPUT ;
    USE SIGNAL ;
    PORT
      LAYER M5 ;
        RECT  4.464 15.036 4.488 15.12 ;
    END
  END i[56]
  PIN i[57]
    DIRECTION INPUT ;
    USE SIGNAL ;
    PORT
      LAYER M5 ;
        RECT  4.56 15.036 4.584 15.12 ;
    END
  END i[57]
  PIN i[58]
    DIRECTION INPUT ;
    USE SIGNAL ;
    PORT
      LAYER M5 ;
        RECT  4.656 15.036 4.68 15.12 ;
    END
  END i[58]
  PIN i[59]
    DIRECTION INPUT ;
    USE SIGNAL ;
    PORT
      LAYER M5 ;
        RECT  4.752 15.036 4.776 15.12 ;
    END
  END i[59]
  PIN i[5]
    DIRECTION INPUT ;
    USE SIGNAL ;
    PORT
      LAYER M5 ;
        RECT  5.712 15.036 5.736 15.12 ;
    END
  END i[5]
  PIN i[60]
    DIRECTION INPUT ;
    USE SIGNAL ;
    PORT
      LAYER M5 ;
        RECT  4.848 15.036 4.872 15.12 ;
    END
  END i[60]
  PIN i[61]
    DIRECTION INPUT ;
    USE SIGNAL ;
    PORT
      LAYER M5 ;
        RECT  4.944 15.036 4.968 15.12 ;
    END
  END i[61]
  PIN i[62]
    DIRECTION INPUT ;
    USE SIGNAL ;
    PORT
      LAYER M5 ;
        RECT  5.04 15.036 5.064 15.12 ;
    END
  END i[62]
  PIN i[63]
    DIRECTION INPUT ;
    USE SIGNAL ;
    PORT
      LAYER M5 ;
        RECT  5.136 15.036 5.16 15.12 ;
    END
  END i[63]
  PIN i[64]
    DIRECTION INPUT ;
    USE SIGNAL ;
    PORT
      LAYER M5 ;
        RECT  11.184 15.036 11.208 15.12 ;
    END
  END i[64]
  PIN i[65]
    DIRECTION INPUT ;
    USE SIGNAL ;
    PORT
      LAYER M5 ;
        RECT  11.28 15.036 11.304 15.12 ;
    END
  END i[65]
  PIN i[6]
    DIRECTION INPUT ;
    USE SIGNAL ;
    PORT
      LAYER M5 ;
        RECT  5.808 15.036 5.832 15.12 ;
    END
  END i[6]
  PIN i[7]
    DIRECTION INPUT ;
    USE SIGNAL ;
    PORT
      LAYER M5 ;
        RECT  5.904 15.036 5.928 15.12 ;
    END
  END i[7]
  PIN i[8]
    DIRECTION INPUT ;
    USE SIGNAL ;
    PORT
      LAYER M5 ;
        RECT  6 15.036 6.024 15.12 ;
    END
  END i[8]
  PIN i[9]
    DIRECTION INPUT ;
    USE SIGNAL ;
    PORT
      LAYER M5 ;
        RECT  6.096 15.036 6.12 15.12 ;
    END
  END i[9]
  PIN o[0]
    DIRECTION OUTPUT ;
    USE SIGNAL ;
    PORT
      LAYER M5 ;
        RECT  9.936 0 9.96 0.084 ;
    END
  END o[0]
  PIN o[10]
    DIRECTION OUTPUT ;
    USE SIGNAL ;
    PORT
      LAYER M5 ;
        RECT  10.896 0 10.92 0.084 ;
    END
  END o[10]
  PIN o[11]
    DIRECTION OUTPUT ;
    USE SIGNAL ;
    PORT
      LAYER M5 ;
        RECT  10.992 0 11.016 0.084 ;
    END
  END o[11]
  PIN o[12]
    DIRECTION OUTPUT ;
    USE SIGNAL ;
    PORT
      LAYER M5 ;
        RECT  11.088 0 11.112 0.084 ;
    END
  END o[12]
  PIN o[13]
    DIRECTION OUTPUT ;
    USE SIGNAL ;
    PORT
      LAYER M5 ;
        RECT  11.184 0 11.208 0.084 ;
    END
  END o[13]
  PIN o[14]
    DIRECTION OUTPUT ;
    USE SIGNAL ;
    PORT
      LAYER M5 ;
        RECT  11.28 0 11.304 0.084 ;
    END
  END o[14]
  PIN o[15]
    DIRECTION OUTPUT ;
    USE SIGNAL ;
    PORT
      LAYER M5 ;
        RECT  11.376 0 11.4 0.084 ;
    END
  END o[15]
  PIN o[16]
    DIRECTION OUTPUT ;
    USE SIGNAL ;
    PORT
      LAYER M5 ;
        RECT  11.472 0 11.496 0.084 ;
    END
  END o[16]
  PIN o[17]
    DIRECTION OUTPUT ;
    USE SIGNAL ;
    PORT
      LAYER M5 ;
        RECT  11.568 0 11.592 0.084 ;
    END
  END o[17]
  PIN o[18]
    DIRECTION OUTPUT ;
    USE SIGNAL ;
    PORT
      LAYER M5 ;
        RECT  11.664 0 11.688 0.084 ;
    END
  END o[18]
  PIN o[19]
    DIRECTION OUTPUT ;
    USE SIGNAL ;
    PORT
      LAYER M5 ;
        RECT  11.76 0 11.784 0.084 ;
    END
  END o[19]
  PIN o[1]
    DIRECTION OUTPUT ;
    USE SIGNAL ;
    PORT
      LAYER M5 ;
        RECT  10.032 0 10.056 0.084 ;
    END
  END o[1]
  PIN o[20]
    DIRECTION OUTPUT ;
    USE SIGNAL ;
    PORT
      LAYER M5 ;
        RECT  11.856 0 11.88 0.084 ;
    END
  END o[20]
  PIN o[21]
    DIRECTION OUTPUT ;
    USE SIGNAL ;
    PORT
      LAYER M5 ;
        RECT  11.952 0 11.976 0.084 ;
    END
  END o[21]
  PIN o[22]
    DIRECTION OUTPUT ;
    USE SIGNAL ;
    PORT
      LAYER M5 ;
        RECT  12.048 0 12.072 0.084 ;
    END
  END o[22]
  PIN o[23]
    DIRECTION OUTPUT ;
    USE SIGNAL ;
    PORT
      LAYER M5 ;
        RECT  12.144 0 12.168 0.084 ;
    END
  END o[23]
  PIN o[24]
    DIRECTION OUTPUT ;
    USE SIGNAL ;
    PORT
      LAYER M5 ;
        RECT  12.24 0 12.264 0.084 ;
    END
  END o[24]
  PIN o[25]
    DIRECTION OUTPUT ;
    USE SIGNAL ;
    PORT
      LAYER M5 ;
        RECT  12.336 0 12.36 0.084 ;
    END
  END o[25]
  PIN o[26]
    DIRECTION OUTPUT ;
    USE SIGNAL ;
    PORT
      LAYER M5 ;
        RECT  12.432 0 12.456 0.084 ;
    END
  END o[26]
  PIN o[27]
    DIRECTION OUTPUT ;
    USE SIGNAL ;
    PORT
      LAYER M5 ;
        RECT  12.528 0 12.552 0.084 ;
    END
  END o[27]
  PIN o[28]
    DIRECTION OUTPUT ;
    USE SIGNAL ;
    PORT
      LAYER M5 ;
        RECT  12.624 0 12.648 0.084 ;
    END
  END o[28]
  PIN o[29]
    DIRECTION OUTPUT ;
    USE SIGNAL ;
    PORT
      LAYER M5 ;
        RECT  12.72 0 12.744 0.084 ;
    END
  END o[29]
  PIN o[2]
    DIRECTION OUTPUT ;
    USE SIGNAL ;
    PORT
      LAYER M5 ;
        RECT  10.128 0 10.152 0.084 ;
    END
  END o[2]
  PIN o[30]
    DIRECTION OUTPUT ;
    USE SIGNAL ;
    PORT
      LAYER M5 ;
        RECT  12.816 0 12.84 0.084 ;
    END
  END o[30]
  PIN o[31]
    DIRECTION OUTPUT ;
    USE SIGNAL ;
    PORT
      LAYER M5 ;
        RECT  12.912 0 12.936 0.084 ;
    END
  END o[31]
  PIN o[32]
    DIRECTION OUTPUT ;
    USE SIGNAL ;
    PORT
      LAYER M5 ;
        RECT  6.864 0 6.888 0.084 ;
    END
  END o[32]
  PIN o[33]
    DIRECTION OUTPUT ;
    USE SIGNAL ;
    PORT
      LAYER M5 ;
        RECT  6.96 0 6.984 0.084 ;
    END
  END o[33]
  PIN o[34]
    DIRECTION OUTPUT ;
    USE SIGNAL ;
    PORT
      LAYER M5 ;
        RECT  7.056 0 7.08 0.084 ;
    END
  END o[34]
  PIN o[35]
    DIRECTION OUTPUT ;
    USE SIGNAL ;
    PORT
      LAYER M5 ;
        RECT  7.152 0 7.176 0.084 ;
    END
  END o[35]
  PIN o[36]
    DIRECTION OUTPUT ;
    USE SIGNAL ;
    PORT
      LAYER M5 ;
        RECT  7.248 0 7.272 0.084 ;
    END
  END o[36]
  PIN o[37]
    DIRECTION OUTPUT ;
    USE SIGNAL ;
    PORT
      LAYER M5 ;
        RECT  7.344 0 7.368 0.084 ;
    END
  END o[37]
  PIN o[38]
    DIRECTION OUTPUT ;
    USE SIGNAL ;
    PORT
      LAYER M5 ;
        RECT  7.44 0 7.464 0.084 ;
    END
  END o[38]
  PIN o[39]
    DIRECTION OUTPUT ;
    USE SIGNAL ;
    PORT
      LAYER M5 ;
        RECT  7.536 0 7.56 0.084 ;
    END
  END o[39]
  PIN o[3]
    DIRECTION OUTPUT ;
    USE SIGNAL ;
    PORT
      LAYER M5 ;
        RECT  10.224 0 10.248 0.084 ;
    END
  END o[3]
  PIN o[40]
    DIRECTION OUTPUT ;
    USE SIGNAL ;
    PORT
      LAYER M5 ;
        RECT  7.632 0 7.656 0.084 ;
    END
  END o[40]
  PIN o[41]
    DIRECTION OUTPUT ;
    USE SIGNAL ;
    PORT
      LAYER M5 ;
        RECT  7.728 0 7.752 0.084 ;
    END
  END o[41]
  PIN o[42]
    DIRECTION OUTPUT ;
    USE SIGNAL ;
    PORT
      LAYER M5 ;
        RECT  7.824 0 7.848 0.084 ;
    END
  END o[42]
  PIN o[43]
    DIRECTION OUTPUT ;
    USE SIGNAL ;
    PORT
      LAYER M5 ;
        RECT  7.92 0 7.944 0.084 ;
    END
  END o[43]
  PIN o[44]
    DIRECTION OUTPUT ;
    USE SIGNAL ;
    PORT
      LAYER M5 ;
        RECT  8.016 0 8.04 0.084 ;
    END
  END o[44]
  PIN o[45]
    DIRECTION OUTPUT ;
    USE SIGNAL ;
    PORT
      LAYER M5 ;
        RECT  8.112 0 8.136 0.084 ;
    END
  END o[45]
  PIN o[46]
    DIRECTION OUTPUT ;
    USE SIGNAL ;
    PORT
      LAYER M5 ;
        RECT  8.208 0 8.232 0.084 ;
    END
  END o[46]
  PIN o[47]
    DIRECTION OUTPUT ;
    USE SIGNAL ;
    PORT
      LAYER M5 ;
        RECT  8.304 0 8.328 0.084 ;
    END
  END o[47]
  PIN o[48]
    DIRECTION OUTPUT ;
    USE SIGNAL ;
    PORT
      LAYER M5 ;
        RECT  8.4 0 8.424 0.084 ;
    END
  END o[48]
  PIN o[49]
    DIRECTION OUTPUT ;
    USE SIGNAL ;
    PORT
      LAYER M5 ;
        RECT  8.496 0 8.52 0.084 ;
    END
  END o[49]
  PIN o[4]
    DIRECTION OUTPUT ;
    USE SIGNAL ;
    PORT
      LAYER M5 ;
        RECT  10.32 0 10.344 0.084 ;
    END
  END o[4]
  PIN o[50]
    DIRECTION OUTPUT ;
    USE SIGNAL ;
    PORT
      LAYER M5 ;
        RECT  8.592 0 8.616 0.084 ;
    END
  END o[50]
  PIN o[51]
    DIRECTION OUTPUT ;
    USE SIGNAL ;
    PORT
      LAYER M5 ;
        RECT  8.688 0 8.712 0.084 ;
    END
  END o[51]
  PIN o[52]
    DIRECTION OUTPUT ;
    USE SIGNAL ;
    PORT
      LAYER M5 ;
        RECT  8.784 0 8.808 0.084 ;
    END
  END o[52]
  PIN o[53]
    DIRECTION OUTPUT ;
    USE SIGNAL ;
    PORT
      LAYER M5 ;
        RECT  8.88 0 8.904 0.084 ;
    END
  END o[53]
  PIN o[54]
    DIRECTION OUTPUT ;
    USE SIGNAL ;
    PORT
      LAYER M5 ;
        RECT  8.976 0 9 0.084 ;
    END
  END o[54]
  PIN o[55]
    DIRECTION OUTPUT ;
    USE SIGNAL ;
    PORT
      LAYER M5 ;
        RECT  9.072 0 9.096 0.084 ;
    END
  END o[55]
  PIN o[56]
    DIRECTION OUTPUT ;
    USE SIGNAL ;
    PORT
      LAYER M5 ;
        RECT  9.168 0 9.192 0.084 ;
    END
  END o[56]
  PIN o[57]
    DIRECTION OUTPUT ;
    USE SIGNAL ;
    PORT
      LAYER M5 ;
        RECT  9.264 0 9.288 0.084 ;
    END
  END o[57]
  PIN o[58]
    DIRECTION OUTPUT ;
    USE SIGNAL ;
    PORT
      LAYER M5 ;
        RECT  9.36 0 9.384 0.084 ;
    END
  END o[58]
  PIN o[59]
    DIRECTION OUTPUT ;
    USE SIGNAL ;
    PORT
      LAYER M5 ;
        RECT  9.456 0 9.48 0.084 ;
    END
  END o[59]
  PIN o[5]
    DIRECTION OUTPUT ;
    USE SIGNAL ;
    PORT
      LAYER M5 ;
        RECT  10.416 0 10.44 0.084 ;
    END
  END o[5]
  PIN o[60]
    DIRECTION OUTPUT ;
    USE SIGNAL ;
    PORT
      LAYER M5 ;
        RECT  9.552 0 9.576 0.084 ;
    END
  END o[60]
  PIN o[61]
    DIRECTION OUTPUT ;
    USE SIGNAL ;
    PORT
      LAYER M5 ;
        RECT  9.648 0 9.672 0.084 ;
    END
  END o[61]
  PIN o[62]
    DIRECTION OUTPUT ;
    USE SIGNAL ;
    PORT
      LAYER M5 ;
        RECT  9.744 0 9.768 0.084 ;
    END
  END o[62]
  PIN o[63]
    DIRECTION OUTPUT ;
    USE SIGNAL ;
    PORT
      LAYER M5 ;
        RECT  9.84 0 9.864 0.084 ;
    END
  END o[63]
  PIN o[64]
    DIRECTION OUTPUT ;
    USE SIGNAL ;
    PORT
      LAYER M5 ;
        RECT  13.008 0 13.032 0.084 ;
    END
  END o[64]
  PIN o[65]
    DIRECTION OUTPUT ;
    USE SIGNAL ;
    PORT
      LAYER M5 ;
        RECT  13.104 0 13.128 0.084 ;
    END
  END o[65]
  PIN o[6]
    DIRECTION OUTPUT ;
    USE SIGNAL ;
    PORT
      LAYER M5 ;
        RECT  10.512 0 10.536 0.084 ;
    END
  END o[6]
  PIN o[7]
    DIRECTION OUTPUT ;
    USE SIGNAL ;
    PORT
      LAYER M5 ;
        RECT  10.608 0 10.632 0.084 ;
    END
  END o[7]
  PIN o[8]
    DIRECTION OUTPUT ;
    USE SIGNAL ;
    PORT
      LAYER M5 ;
        RECT  10.704 0 10.728 0.084 ;
    END
  END o[8]
  PIN o[9]
    DIRECTION OUTPUT ;
    USE SIGNAL ;
    PORT
      LAYER M5 ;
        RECT  10.8 0 10.824 0.084 ;
    END
  END o[9]
  PIN rs
    DIRECTION INPUT ;
    USE SIGNAL ;
    PORT
      LAYER M4 ;
        RECT  15.036 4.08 15.12 4.104 ;
    END
  END rs
  PIN VDD
    DIRECTION INOUT ;
    USE POWER ;
    PORT
      LAYER M5 ;
        RECT  10.692 2.151 10.812 12.969 ;
        RECT  7.992 2.151 8.112 12.969 ;
        RECT  5.292 2.151 5.412 12.969 ;
        RECT  2.592 2.151 2.712 12.969 ;
    END
  END VDD
  PIN VSS
    DIRECTION INOUT ;
    USE GROUND ;
    PORT
      LAYER M5 ;
        RECT  10.5 2.137 10.62 12.983 ;
        RECT  7.8 2.137 7.92 12.983 ;
        RECT  5.1 2.137 5.22 12.983 ;
        RECT  2.4 2.137 2.52 12.983 ;
    END
  END VSS
  OBS
    LAYER RVTN ;
     RECT  2.16 2.16 12.96 2.295 ;
     RECT  2.16 2.565 12.96 2.835 ;
     RECT  2.16 3.105 12.96 3.375 ;
     RECT  2.16 3.645 12.96 3.915 ;
     RECT  2.16 4.185 12.96 4.455 ;
     RECT  2.16 4.725 12.96 4.995 ;
     RECT  2.16 5.265 12.96 5.535 ;
     RECT  2.16 5.805 12.96 6.075 ;
     RECT  2.16 6.345 12.96 6.615 ;
     RECT  2.16 6.885 12.96 7.155 ;
     RECT  2.16 7.425 12.96 7.695 ;
     RECT  2.16 7.965 12.96 8.235 ;
     RECT  2.16 8.505 12.96 8.775 ;
     RECT  2.16 9.045 12.96 9.315 ;
     RECT  2.16 9.585 12.96 9.855 ;
     RECT  2.16 10.125 12.96 10.395 ;
     RECT  2.16 10.665 12.96 10.935 ;
     RECT  2.16 11.205 12.96 11.475 ;
     RECT  2.16 11.745 12.96 12.015 ;
     RECT  2.16 12.285 12.96 12.555 ;
     RECT  2.16 12.825 12.96 12.96 ;
    LAYER RVTP ;
     RECT  2.16 2.295 12.96 2.565 ;
     RECT  2.16 2.835 12.96 3.105 ;
     RECT  2.16 3.375 12.96 3.645 ;
     RECT  2.16 3.915 12.96 4.185 ;
     RECT  2.16 4.455 12.96 4.725 ;
     RECT  2.16 4.995 12.96 5.265 ;
     RECT  2.16 5.535 12.96 5.805 ;
     RECT  2.16 6.075 12.96 6.345 ;
     RECT  2.16 6.615 12.96 6.885 ;
     RECT  2.16 7.155 12.96 7.425 ;
     RECT  2.16 7.695 12.96 7.965 ;
     RECT  2.16 8.235 12.96 8.505 ;
     RECT  2.16 8.775 12.96 9.045 ;
     RECT  2.16 9.315 12.96 9.585 ;
     RECT  2.16 9.855 12.96 10.125 ;
     RECT  2.16 10.395 12.96 10.665 ;
     RECT  2.16 10.935 12.96 11.205 ;
     RECT  2.16 11.475 12.96 11.745 ;
     RECT  2.16 12.015 12.96 12.285 ;
     RECT  2.16 12.555 12.96 12.825 ;
    LAYER M1 ;
     RECT  2.16 2.151 12.96 12.969 ;
    LAYER M2 ;
     RECT  2.16 2.151 8.815 12.969 ;
     RECT  8.815 2.106 9.419 12.969 ;
     RECT  9.419 2.151 12.96 12.969 ;
     RECT  12.96 2.61 13.019 2.628 ;
     RECT  12.96 7.056 13.019 7.074 ;
     RECT  12.96 4.626 13.055 4.95 ;
     RECT  12.96 3.816 13.127 3.834 ;
     RECT  13.055 4.932 15.035 4.95 ;
    LAYER M3 ;
     RECT  12.132 0.091 13.05 0.139 ;
     RECT  9.828 0.091 9.846 0.235 ;
     RECT  10.656 0.091 10.674 0.475 ;
     RECT  12.024 0.139 13.05 0.523 ;
     RECT  7.056 0.523 7.506 0.571 ;
     RECT  9.828 0.235 9.882 0.571 ;
     RECT  10.656 0.475 10.998 0.571 ;
     RECT  9.18 0.571 10.998 1.147 ;
     RECT  11.988 0.523 13.122 1.147 ;
     RECT  6.876 0.571 7.506 1.723 ;
     RECT  8.316 0.571 8.334 1.723 ;
     RECT  9.18 1.147 13.122 1.723 ;
     RECT  6.876 1.723 13.122 2.227 ;
     RECT  5.115 2.143 5.205 2.263 ;
     RECT  6.624 2.227 13.122 2.263 ;
     RECT  5.115 2.263 13.122 2.371 ;
     RECT  2.415 2.143 2.505 2.413 ;
     RECT  3.744 2.191 3.762 2.641 ;
     RECT  4.5 2.371 13.122 2.641 ;
     RECT  2.415 2.413 2.697 3.145 ;
     RECT  3.744 2.641 13.122 3.145 ;
     RECT  2.415 3.145 13.122 3.839 ;
     RECT  14.868 3.979 14.886 4.075 ;
     RECT  14.868 4.075 15.03 4.157 ;
     RECT  2.415 3.839 13.05 4.649 ;
     RECT  15.012 4.157 15.03 4.955 ;
     RECT  2.415 4.649 13.014 7.051 ;
     RECT  2.376 7.051 13.014 7.079 ;
     RECT  2.376 7.079 12.798 8.771 ;
     RECT  2.376 8.771 12.726 9.211 ;
     RECT  2.34 9.211 12.726 9.517 ;
     RECT  2.304 9.517 12.726 10.267 ;
     RECT  2.304 10.267 12.834 10.589 ;
     RECT  2.304 10.589 12.654 10.633 ;
     RECT  2.268 10.633 12.654 10.699 ;
     RECT  2.232 10.699 12.654 11.129 ;
     RECT  2.232 11.129 12.294 11.399 ;
     RECT  2.268 11.399 12.294 11.669 ;
     RECT  2.304 11.669 12.294 12.209 ;
     RECT  2.304 12.209 11.862 12.245 ;
     RECT  2.304 12.245 11.646 12.479 ;
     RECT  2.34 12.479 11.646 12.515 ;
     RECT  2.34 12.515 11.466 12.749 ;
     RECT  2.34 12.749 9.522 12.893 ;
     RECT  10.515 12.749 11.322 12.977 ;
     RECT  2.34 12.893 9.378 13.037 ;
     RECT  2.34 13.037 9.162 13.085 ;
     RECT  11.052 12.977 11.322 13.085 ;
     RECT  5.004 13.085 5.454 13.133 ;
     RECT  7.956 13.085 8.226 13.133 ;
     RECT  8.208 13.133 8.226 13.181 ;
     RECT  2.34 13.085 2.826 13.229 ;
     RECT  2.808 13.229 2.826 13.709 ;
     RECT  3.744 13.085 3.906 13.709 ;
     RECT  3.816 13.709 3.906 14.237 ;
     RECT  3.888 14.237 3.906 14.717 ;
     RECT  5.076 13.133 5.094 14.765 ;
     RECT  9.144 13.085 9.162 15.005 ;
    LAYER M4 ;
     RECT  2.149 11.28 2.204 11.304 ;
     RECT  2.321 13.104 2.329 13.128 ;
     RECT  2.204 10.704 2.408 11.304 ;
     RECT  2.329 13.104 2.408 13.224 ;
     RECT  2.408 2.148 2.512 13.224 ;
     RECT  2.512 2.418 2.704 13.224 ;
     RECT  2.704 12.528 2.78 13.224 ;
     RECT  2.704 5.04 3.701 5.784 ;
     RECT  2.78 12.528 3.781 13.704 ;
     RECT  3.781 11.952 3.805 13.704 ;
     RECT  2.704 6.816 3.836 6.84 ;
     RECT  3.805 11.952 3.877 14.232 ;
     RECT  3.836 6.24 3.923 6.84 ;
     RECT  3.877 11.952 4.019 14.712 ;
     RECT  4.019 11.952 4.115 14.232 ;
     RECT  2.704 10.416 4.124 10.44 ;
     RECT  2.704 8.208 4.129 8.232 ;
     RECT  4.115 11.952 4.211 13.704 ;
     RECT  4.124 10.416 4.237 10.92 ;
     RECT  4.129 8.208 4.549 8.424 ;
     RECT  4.549 8.208 4.892 9 ;
     RECT  4.237 10.176 4.892 10.92 ;
     RECT  4.892 8.208 4.933 10.92 ;
     RECT  3.701 5.04 5.108 5.064 ;
     RECT  3.923 6.624 5.108 6.84 ;
     RECT  4.933 8.16 5.108 10.92 ;
     RECT  4.211 11.952 5.108 13.128 ;
     RECT  5.065 14.736 5.171 14.76 ;
     RECT  5.108 2.148 5.212 13.128 ;
     RECT  5.212 2.418 5.404 13.128 ;
     RECT  5.404 10.224 5.465 13.128 ;
     RECT  5.404 7.2 6.041 9 ;
     RECT  5.465 10.224 6.221 13.08 ;
     RECT  5.404 3.408 6.329 3.432 ;
     RECT  6.853 0.576 6.949 0.6 ;
     RECT  6.757 4.944 6.997 4.968 ;
     RECT  6.949 0.576 7.004 1.176 ;
     RECT  7.004 0.528 7.081 1.176 ;
     RECT  7.081 0.528 7.309 1.752 ;
     RECT  6.997 4.128 7.405 4.968 ;
     RECT  7.309 1.728 7.416 1.752 ;
     RECT  6.221 11.664 7.441 13.08 ;
     RECT  7.309 0.528 7.571 0.6 ;
     RECT  7.405 4.128 7.573 5.832 ;
     RECT  7.416 1.728 7.717 1.8 ;
     RECT  7.717 1.728 7.808 2.04 ;
     RECT  7.573 3.984 7.808 5.832 ;
     RECT  6.041 7.2 7.808 8.52 ;
     RECT  6.221 10.224 7.808 10.248 ;
     RECT  7.441 11.52 7.808 13.08 ;
     RECT  7.808 1.728 7.813 13.08 ;
     RECT  7.573 14.928 7.909 14.952 ;
     RECT  7.813 1.728 7.984 13.128 ;
     RECT  7.909 14.928 8.101 15 ;
     RECT  7.984 1.728 8.237 13.176 ;
     RECT  8.237 1.728 8.243 13.08 ;
     RECT  8.101 14.784 8.243 15 ;
     RECT  8.243 5.136 8.291 13.08 ;
     RECT  8.243 14.88 8.339 15 ;
     RECT  8.291 7.2 8.597 13.08 ;
     RECT  8.597 7.2 8.813 13.032 ;
     RECT  8.813 7.2 8.849 10.872 ;
     RECT  7.571 0.576 8.965 0.6 ;
     RECT  8.339 14.976 9.173 15 ;
     RECT  8.813 12.24 9.281 13.032 ;
     RECT  8.965 0.144 9.349 0.6 ;
     RECT  9.281 13.008 9.389 13.032 ;
     RECT  8.291 5.136 9.413 6.12 ;
     RECT  8.849 7.2 9.413 7.224 ;
     RECT  8.243 1.728 9.457 4.152 ;
     RECT  9.413 5.136 9.457 7.224 ;
     RECT  9.349 0.096 9.733 0.6 ;
     RECT  9.457 1.728 9.733 7.224 ;
     RECT  8.849 8.544 9.997 10.872 ;
     RECT  9.733 0.096 10.181 7.224 ;
     RECT  10.181 0.096 10.505 0.6 ;
     RECT  10.181 1.728 10.508 7.224 ;
     RECT  9.997 8.208 10.508 10.872 ;
     RECT  10.505 0.096 10.685 0.552 ;
     RECT  10.508 1.728 10.804 12.972 ;
     RECT  10.804 9.648 10.865 11.736 ;
     RECT  10.865 9.648 10.931 10.584 ;
     RECT  10.804 1.728 11.009 7.224 ;
     RECT  10.865 11.712 11.009 11.736 ;
     RECT  11.009 1.728 11.081 6.312 ;
     RECT  11.081 1.728 11.171 5.592 ;
     RECT  11.171 1.728 11.26 4.152 ;
     RECT  10.931 9.696 11.261 10.584 ;
     RECT  11.041 13.056 11.356 13.08 ;
     RECT  11.171 5.472 11.363 5.592 ;
     RECT  11.261 9.696 11.369 9.72 ;
     RECT  11.363 5.472 11.405 5.496 ;
     RECT  10.685 0.144 11.545 0.552 ;
     RECT  11.26 1.728 11.545 2.808 ;
     RECT  11.545 0.144 11.653 2.808 ;
     RECT  11.653 0.096 11.945 2.808 ;
     RECT  12.181 8.544 12.341 8.568 ;
     RECT  11.945 0.096 12.371 1.176 ;
     RECT  11.26 4.128 12.445 4.152 ;
     RECT  11.945 2.16 12.469 2.808 ;
     RECT  12.469 2.16 12.517 2.856 ;
     RECT  12.445 4.128 12.517 4.536 ;
     RECT  12.517 2.16 12.601 4.536 ;
     RECT  12.601 2.16 12.665 2.856 ;
     RECT  12.665 2.304 12.773 2.856 ;
     RECT  12.773 2.784 12.803 2.856 ;
     RECT  12.445 7.968 12.817 7.992 ;
     RECT  12.803 2.832 12.845 2.856 ;
     RECT  12.601 4.128 12.851 4.536 ;
     RECT  12.805 10.272 12.889 10.296 ;
     RECT  12.371 0.096 13.061 0.552 ;
     RECT  13.061 0.528 13.139 0.552 ;
     RECT  12.851 4.128 14.857 4.152 ;
     RECT  14.857 3.984 14.897 4.152 ;
     RECT  14.897 3.984 15.084 4.104 ;
    LAYER M5 ;
     RECT  6.864 0.016 13.128 0.563 ;
     RECT  6.864 0.563 12.648 0.611 ;
     RECT  6.96 0.611 12.648 1.187 ;
     RECT  7.152 1.187 12.648 1.763 ;
     RECT  7.44 1.763 12.648 1.811 ;
     RECT  7.728 1.811 12.648 2.051 ;
     RECT  2.4 2.137 2.52 2.151 ;
     RECT  5.1 2.137 5.22 2.151 ;
     RECT  7.8 2.051 12.648 2.435 ;
     RECT  12.192 2.435 12.648 2.773 ;
     RECT  7.8 2.435 11.208 3.973 ;
     RECT  7.584 3.973 11.208 4.117 ;
     RECT  12.192 2.773 12.792 4.501 ;
     RECT  7.008 4.117 11.208 5.461 ;
     RECT  12.192 4.501 12.84 5.461 ;
     RECT  7.008 5.461 12.84 5.603 ;
     RECT  5.1 2.151 5.412 6.613 ;
     RECT  3.888 6.229 3.912 6.851 ;
     RECT  7.008 5.603 11.208 8.003 ;
     RECT  7.68 8.003 11.208 8.195 ;
     RECT  12.192 5.603 12.84 8.579 ;
     RECT  4.944 6.613 5.412 8.965 ;
     RECT  7.8 8.195 11.208 9.731 ;
     RECT  12.816 8.579 12.84 10.307 ;
     RECT  4.56 8.965 5.412 10.405 ;
     RECT  7.8 9.731 10.92 10.595 ;
     RECT  2.4 2.151 2.712 10.693 ;
     RECT  7.8 10.595 9 10.883 ;
     RECT  10.128 10.595 10.812 10.883 ;
     RECT  4.176 10.405 5.412 10.931 ;
     RECT  5.1 10.931 5.412 11.173 ;
     RECT  2.256 10.693 2.712 11.269 ;
     RECT  7.8 10.883 8.112 11.941 ;
     RECT  2.16 11.269 2.712 12.517 ;
     RECT  3.792 11.941 3.816 12.517 ;
     RECT  5.1 11.173 6.168 12.517 ;
     RECT  7.44 11.941 8.112 12.517 ;
     RECT  2.16 12.517 8.112 12.949 ;
     RECT  10.5 10.883 10.812 12.983 ;
     RECT  2.16 12.949 8.328 14.915 ;
     RECT  2.16 14.915 8.232 15.056 ;
     RECT  11.184 13.045 11.304 15.056 ;
  END
END dsfd_rly_66_NS

VERSION 5.8 ;
BUSBITCHARS "[]" ;
DIVIDERCHAR "/" ;
UNITS
    DATABASE MICRONS 1000 ;
END UNITS

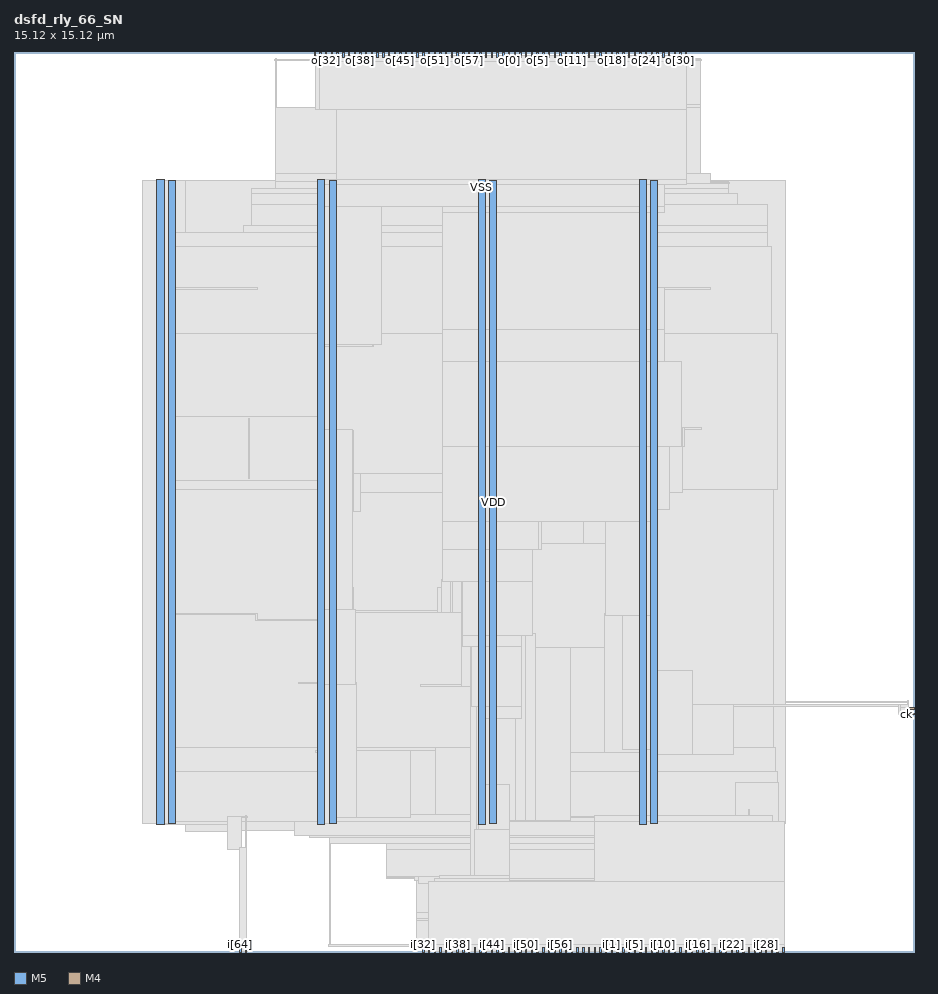
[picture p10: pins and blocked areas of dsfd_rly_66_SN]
MACRO dsfd_rly_66_SN
  FOREIGN dsfd_rly_66_SN 0 0 ;
  CLASS BLOCK ;
  SIZE 15.12 BY 15.12 ;
  PIN ck
    DIRECTION INPUT ;
    USE SIGNAL ;
    PORT
      LAYER M4 ;
        RECT  15.036 3.984 15.12 4.008 ;
    END
  END ck
  PIN i[0]
    DIRECTION INPUT ;
    USE SIGNAL ;
    PORT
      LAYER M5 ;
        RECT  9.936 0 9.96 0.084 ;
    END
  END i[0]
  PIN i[10]
    DIRECTION INPUT ;
    USE SIGNAL ;
    PORT
      LAYER M5 ;
        RECT  10.896 0 10.92 0.084 ;
    END
  END i[10]
  PIN i[11]
    DIRECTION INPUT ;
    USE SIGNAL ;
    PORT
      LAYER M5 ;
        RECT  10.992 0 11.016 0.084 ;
    END
  END i[11]
  PIN i[12]
    DIRECTION INPUT ;
    USE SIGNAL ;
    PORT
      LAYER M5 ;
        RECT  11.088 0 11.112 0.084 ;
    END
  END i[12]
  PIN i[13]
    DIRECTION INPUT ;
    USE SIGNAL ;
    PORT
      LAYER M5 ;
        RECT  11.184 0 11.208 0.084 ;
    END
  END i[13]
  PIN i[14]
    DIRECTION INPUT ;
    USE SIGNAL ;
    PORT
      LAYER M5 ;
        RECT  11.28 0 11.304 0.084 ;
    END
  END i[14]
  PIN i[15]
    DIRECTION INPUT ;
    USE SIGNAL ;
    PORT
      LAYER M5 ;
        RECT  11.376 0 11.4 0.084 ;
    END
  END i[15]
  PIN i[16]
    DIRECTION INPUT ;
    USE SIGNAL ;
    PORT
      LAYER M5 ;
        RECT  11.472 0 11.496 0.084 ;
    END
  END i[16]
  PIN i[17]
    DIRECTION INPUT ;
    USE SIGNAL ;
    PORT
      LAYER M5 ;
        RECT  11.568 0 11.592 0.084 ;
    END
  END i[17]
  PIN i[18]
    DIRECTION INPUT ;
    USE SIGNAL ;
    PORT
      LAYER M5 ;
        RECT  11.664 0 11.688 0.084 ;
    END
  END i[18]
  PIN i[19]
    DIRECTION INPUT ;
    USE SIGNAL ;
    PORT
      LAYER M5 ;
        RECT  11.76 0 11.784 0.084 ;
    END
  END i[19]
  PIN i[1]
    DIRECTION INPUT ;
    USE SIGNAL ;
    PORT
      LAYER M5 ;
        RECT  10.032 0 10.056 0.084 ;
    END
  END i[1]
  PIN i[20]
    DIRECTION INPUT ;
    USE SIGNAL ;
    PORT
      LAYER M5 ;
        RECT  11.856 0 11.88 0.084 ;
    END
  END i[20]
  PIN i[21]
    DIRECTION INPUT ;
    USE SIGNAL ;
    PORT
      LAYER M5 ;
        RECT  11.952 0 11.976 0.084 ;
    END
  END i[21]
  PIN i[22]
    DIRECTION INPUT ;
    USE SIGNAL ;
    PORT
      LAYER M5 ;
        RECT  12.048 0 12.072 0.084 ;
    END
  END i[22]
  PIN i[23]
    DIRECTION INPUT ;
    USE SIGNAL ;
    PORT
      LAYER M5 ;
        RECT  12.144 0 12.168 0.084 ;
    END
  END i[23]
  PIN i[24]
    DIRECTION INPUT ;
    USE SIGNAL ;
    PORT
      LAYER M5 ;
        RECT  12.24 0 12.264 0.084 ;
    END
  END i[24]
  PIN i[25]
    DIRECTION INPUT ;
    USE SIGNAL ;
    PORT
      LAYER M5 ;
        RECT  12.336 0 12.36 0.084 ;
    END
  END i[25]
  PIN i[26]
    DIRECTION INPUT ;
    USE SIGNAL ;
    PORT
      LAYER M5 ;
        RECT  12.432 0 12.456 0.084 ;
    END
  END i[26]
  PIN i[27]
    DIRECTION INPUT ;
    USE SIGNAL ;
    PORT
      LAYER M5 ;
        RECT  12.528 0 12.552 0.084 ;
    END
  END i[27]
  PIN i[28]
    DIRECTION INPUT ;
    USE SIGNAL ;
    PORT
      LAYER M5 ;
        RECT  12.624 0 12.648 0.084 ;
    END
  END i[28]
  PIN i[29]
    DIRECTION INPUT ;
    USE SIGNAL ;
    PORT
      LAYER M5 ;
        RECT  12.72 0 12.744 0.084 ;
    END
  END i[29]
  PIN i[2]
    DIRECTION INPUT ;
    USE SIGNAL ;
    PORT
      LAYER M5 ;
        RECT  10.128 0 10.152 0.084 ;
    END
  END i[2]
  PIN i[30]
    DIRECTION INPUT ;
    USE SIGNAL ;
    PORT
      LAYER M5 ;
        RECT  12.816 0 12.84 0.084 ;
    END
  END i[30]
  PIN i[31]
    DIRECTION INPUT ;
    USE SIGNAL ;
    PORT
      LAYER M5 ;
        RECT  12.912 0 12.936 0.084 ;
    END
  END i[31]
  PIN i[32]
    DIRECTION INPUT ;
    USE SIGNAL ;
    PORT
      LAYER M5 ;
        RECT  6.864 0 6.888 0.084 ;
    END
  END i[32]
  PIN i[33]
    DIRECTION INPUT ;
    USE SIGNAL ;
    PORT
      LAYER M5 ;
        RECT  6.96 0 6.984 0.084 ;
    END
  END i[33]
  PIN i[34]
    DIRECTION INPUT ;
    USE SIGNAL ;
    PORT
      LAYER M5 ;
        RECT  7.056 0 7.08 0.084 ;
    END
  END i[34]
  PIN i[35]
    DIRECTION INPUT ;
    USE SIGNAL ;
    PORT
      LAYER M5 ;
        RECT  7.152 0 7.176 0.084 ;
    END
  END i[35]
  PIN i[36]
    DIRECTION INPUT ;
    USE SIGNAL ;
    PORT
      LAYER M5 ;
        RECT  7.248 0 7.272 0.084 ;
    END
  END i[36]
  PIN i[37]
    DIRECTION INPUT ;
    USE SIGNAL ;
    PORT
      LAYER M5 ;
        RECT  7.344 0 7.368 0.084 ;
    END
  END i[37]
  PIN i[38]
    DIRECTION INPUT ;
    USE SIGNAL ;
    PORT
      LAYER M5 ;
        RECT  7.44 0 7.464 0.084 ;
    END
  END i[38]
  PIN i[39]
    DIRECTION INPUT ;
    USE SIGNAL ;
    PORT
      LAYER M5 ;
        RECT  7.536 0 7.56 0.084 ;
    END
  END i[39]
  PIN i[3]
    DIRECTION INPUT ;
    USE SIGNAL ;
    PORT
      LAYER M5 ;
        RECT  10.224 0 10.248 0.084 ;
    END
  END i[3]
  PIN i[40]
    DIRECTION INPUT ;
    USE SIGNAL ;
    PORT
      LAYER M5 ;
        RECT  7.632 0 7.656 0.084 ;
    END
  END i[40]
  PIN i[41]
    DIRECTION INPUT ;
    USE SIGNAL ;
    PORT
      LAYER M5 ;
        RECT  7.728 0 7.752 0.084 ;
    END
  END i[41]
  PIN i[42]
    DIRECTION INPUT ;
    USE SIGNAL ;
    PORT
      LAYER M5 ;
        RECT  7.824 0 7.848 0.084 ;
    END
  END i[42]
  PIN i[43]
    DIRECTION INPUT ;
    USE SIGNAL ;
    PORT
      LAYER M5 ;
        RECT  7.92 0 7.944 0.084 ;
    END
  END i[43]
  PIN i[44]
    DIRECTION INPUT ;
    USE SIGNAL ;
    PORT
      LAYER M5 ;
        RECT  8.016 0 8.04 0.084 ;
    END
  END i[44]
  PIN i[45]
    DIRECTION INPUT ;
    USE SIGNAL ;
    PORT
      LAYER M5 ;
        RECT  8.112 0 8.136 0.084 ;
    END
  END i[45]
  PIN i[46]
    DIRECTION INPUT ;
    USE SIGNAL ;
    PORT
      LAYER M5 ;
        RECT  8.208 0 8.232 0.084 ;
    END
  END i[46]
  PIN i[47]
    DIRECTION INPUT ;
    USE SIGNAL ;
    PORT
      LAYER M5 ;
        RECT  8.304 0 8.328 0.084 ;
    END
  END i[47]
  PIN i[48]
    DIRECTION INPUT ;
    USE SIGNAL ;
    PORT
      LAYER M5 ;
        RECT  8.4 0 8.424 0.084 ;
    END
  END i[48]
  PIN i[49]
    DIRECTION INPUT ;
    USE SIGNAL ;
    PORT
      LAYER M5 ;
        RECT  8.496 0 8.52 0.084 ;
    END
  END i[49]
  PIN i[4]
    DIRECTION INPUT ;
    USE SIGNAL ;
    PORT
      LAYER M5 ;
        RECT  10.32 0 10.344 0.084 ;
    END
  END i[4]
  PIN i[50]
    DIRECTION INPUT ;
    USE SIGNAL ;
    PORT
      LAYER M5 ;
        RECT  8.592 0 8.616 0.084 ;
    END
  END i[50]
  PIN i[51]
    DIRECTION INPUT ;
    USE SIGNAL ;
    PORT
      LAYER M5 ;
        RECT  8.688 0 8.712 0.084 ;
    END
  END i[51]
  PIN i[52]
    DIRECTION INPUT ;
    USE SIGNAL ;
    PORT
      LAYER M5 ;
        RECT  8.784 0 8.808 0.084 ;
    END
  END i[52]
  PIN i[53]
    DIRECTION INPUT ;
    USE SIGNAL ;
    PORT
      LAYER M5 ;
        RECT  8.88 0 8.904 0.084 ;
    END
  END i[53]
  PIN i[54]
    DIRECTION INPUT ;
    USE SIGNAL ;
    PORT
      LAYER M5 ;
        RECT  8.976 0 9 0.084 ;
    END
  END i[54]
  PIN i[55]
    DIRECTION INPUT ;
    USE SIGNAL ;
    PORT
      LAYER M5 ;
        RECT  9.072 0 9.096 0.084 ;
    END
  END i[55]
  PIN i[56]
    DIRECTION INPUT ;
    USE SIGNAL ;
    PORT
      LAYER M5 ;
        RECT  9.168 0 9.192 0.084 ;
    END
  END i[56]
  PIN i[57]
    DIRECTION INPUT ;
    USE SIGNAL ;
    PORT
      LAYER M5 ;
        RECT  9.264 0 9.288 0.084 ;
    END
  END i[57]
  PIN i[58]
    DIRECTION INPUT ;
    USE SIGNAL ;
    PORT
      LAYER M5 ;
        RECT  9.36 0 9.384 0.084 ;
    END
  END i[58]
  PIN i[59]
    DIRECTION INPUT ;
    USE SIGNAL ;
    PORT
      LAYER M5 ;
        RECT  9.456 0 9.48 0.084 ;
    END
  END i[59]
  PIN i[5]
    DIRECTION INPUT ;
    USE SIGNAL ;
    PORT
      LAYER M5 ;
        RECT  10.416 0 10.44 0.084 ;
    END
  END i[5]
  PIN i[60]
    DIRECTION INPUT ;
    USE SIGNAL ;
    PORT
      LAYER M5 ;
        RECT  9.552 0 9.576 0.084 ;
    END
  END i[60]
  PIN i[61]
    DIRECTION INPUT ;
    USE SIGNAL ;
    PORT
      LAYER M5 ;
        RECT  9.648 0 9.672 0.084 ;
    END
  END i[61]
  PIN i[62]
    DIRECTION INPUT ;
    USE SIGNAL ;
    PORT
      LAYER M5 ;
        RECT  9.744 0 9.768 0.084 ;
    END
  END i[62]
  PIN i[63]
    DIRECTION INPUT ;
    USE SIGNAL ;
    PORT
      LAYER M5 ;
        RECT  9.84 0 9.864 0.084 ;
    END
  END i[63]
  PIN i[64]
    DIRECTION INPUT ;
    USE SIGNAL ;
    PORT
      LAYER M5 ;
        RECT  3.792 0 3.816 0.084 ;
    END
  END i[64]
  PIN i[65]
    DIRECTION INPUT ;
    USE SIGNAL ;
    PORT
      LAYER M5 ;
        RECT  3.888 0 3.912 0.084 ;
    END
  END i[65]
  PIN i[6]
    DIRECTION INPUT ;
    USE SIGNAL ;
    PORT
      LAYER M5 ;
        RECT  10.512 0 10.536 0.084 ;
    END
  END i[6]
  PIN i[7]
    DIRECTION INPUT ;
    USE SIGNAL ;
    PORT
      LAYER M5 ;
        RECT  10.608 0 10.632 0.084 ;
    END
  END i[7]
  PIN i[8]
    DIRECTION INPUT ;
    USE SIGNAL ;
    PORT
      LAYER M5 ;
        RECT  10.704 0 10.728 0.084 ;
    END
  END i[8]
  PIN i[9]
    DIRECTION INPUT ;
    USE SIGNAL ;
    PORT
      LAYER M5 ;
        RECT  10.8 0 10.824 0.084 ;
    END
  END i[9]
  PIN o[0]
    DIRECTION OUTPUT ;
    USE SIGNAL ;
    PORT
      LAYER M5 ;
        RECT  8.304 15.036 8.328 15.12 ;
    END
  END o[0]
  PIN o[10]
    DIRECTION OUTPUT ;
    USE SIGNAL ;
    PORT
      LAYER M5 ;
        RECT  9.264 15.036 9.288 15.12 ;
    END
  END o[10]
  PIN o[11]
    DIRECTION OUTPUT ;
    USE SIGNAL ;
    PORT
      LAYER M5 ;
        RECT  9.36 15.036 9.384 15.12 ;
    END
  END o[11]
  PIN o[12]
    DIRECTION OUTPUT ;
    USE SIGNAL ;
    PORT
      LAYER M5 ;
        RECT  9.456 15.036 9.48 15.12 ;
    END
  END o[12]
  PIN o[13]
    DIRECTION OUTPUT ;
    USE SIGNAL ;
    PORT
      LAYER M5 ;
        RECT  9.552 15.036 9.576 15.12 ;
    END
  END o[13]
  PIN o[14]
    DIRECTION OUTPUT ;
    USE SIGNAL ;
    PORT
      LAYER M5 ;
        RECT  9.648 15.036 9.672 15.12 ;
    END
  END o[14]
  PIN o[15]
    DIRECTION OUTPUT ;
    USE SIGNAL ;
    PORT
      LAYER M5 ;
        RECT  9.744 15.036 9.768 15.12 ;
    END
  END o[15]
  PIN o[16]
    DIRECTION OUTPUT ;
    USE SIGNAL ;
    PORT
      LAYER M5 ;
        RECT  9.84 15.036 9.864 15.12 ;
    END
  END o[16]
  PIN o[17]
    DIRECTION OUTPUT ;
    USE SIGNAL ;
    PORT
      LAYER M5 ;
        RECT  9.936 15.036 9.96 15.12 ;
    END
  END o[17]
  PIN o[18]
    DIRECTION OUTPUT ;
    USE SIGNAL ;
    PORT
      LAYER M5 ;
        RECT  10.032 15.036 10.056 15.12 ;
    END
  END o[18]
  PIN o[19]
    DIRECTION OUTPUT ;
    USE SIGNAL ;
    PORT
      LAYER M5 ;
        RECT  10.128 15.036 10.152 15.12 ;
    END
  END o[19]
  PIN o[1]
    DIRECTION OUTPUT ;
    USE SIGNAL ;
    PORT
      LAYER M5 ;
        RECT  8.4 15.036 8.424 15.12 ;
    END
  END o[1]
  PIN o[20]
    DIRECTION OUTPUT ;
    USE SIGNAL ;
    PORT
      LAYER M5 ;
        RECT  10.224 15.036 10.248 15.12 ;
    END
  END o[20]
  PIN o[21]
    DIRECTION OUTPUT ;
    USE SIGNAL ;
    PORT
      LAYER M5 ;
        RECT  10.32 15.036 10.344 15.12 ;
    END
  END o[21]
  PIN o[22]
    DIRECTION OUTPUT ;
    USE SIGNAL ;
    PORT
      LAYER M5 ;
        RECT  10.416 15.036 10.44 15.12 ;
    END
  END o[22]
  PIN o[23]
    DIRECTION OUTPUT ;
    USE SIGNAL ;
    PORT
      LAYER M5 ;
        RECT  10.512 15.036 10.536 15.12 ;
    END
  END o[23]
  PIN o[24]
    DIRECTION OUTPUT ;
    USE SIGNAL ;
    PORT
      LAYER M5 ;
        RECT  10.608 15.036 10.632 15.12 ;
    END
  END o[24]
  PIN o[25]
    DIRECTION OUTPUT ;
    USE SIGNAL ;
    PORT
      LAYER M5 ;
        RECT  10.704 15.036 10.728 15.12 ;
    END
  END o[25]
  PIN o[26]
    DIRECTION OUTPUT ;
    USE SIGNAL ;
    PORT
      LAYER M5 ;
        RECT  10.8 15.036 10.824 15.12 ;
    END
  END o[26]
  PIN o[27]
    DIRECTION OUTPUT ;
    USE SIGNAL ;
    PORT
      LAYER M5 ;
        RECT  10.896 15.036 10.92 15.12 ;
    END
  END o[27]
  PIN o[28]
    DIRECTION OUTPUT ;
    USE SIGNAL ;
    PORT
      LAYER M5 ;
        RECT  10.992 15.036 11.016 15.12 ;
    END
  END o[28]
  PIN o[29]
    DIRECTION OUTPUT ;
    USE SIGNAL ;
    PORT
      LAYER M5 ;
        RECT  11.088 15.036 11.112 15.12 ;
    END
  END o[29]
  PIN o[2]
    DIRECTION OUTPUT ;
    USE SIGNAL ;
    PORT
      LAYER M5 ;
        RECT  8.496 15.036 8.52 15.12 ;
    END
  END o[2]
  PIN o[30]
    DIRECTION OUTPUT ;
    USE SIGNAL ;
    PORT
      LAYER M5 ;
        RECT  11.184 15.036 11.208 15.12 ;
    END
  END o[30]
  PIN o[31]
    DIRECTION OUTPUT ;
    USE SIGNAL ;
    PORT
      LAYER M5 ;
        RECT  11.28 15.036 11.304 15.12 ;
    END
  END o[31]
  PIN o[32]
    DIRECTION OUTPUT ;
    USE SIGNAL ;
    PORT
      LAYER M5 ;
        RECT  5.232 15.036 5.256 15.12 ;
    END
  END o[32]
  PIN o[33]
    DIRECTION OUTPUT ;
    USE SIGNAL ;
    PORT
      LAYER M5 ;
        RECT  5.328 15.036 5.352 15.12 ;
    END
  END o[33]
  PIN o[34]
    DIRECTION OUTPUT ;
    USE SIGNAL ;
    PORT
      LAYER M5 ;
        RECT  5.424 15.036 5.448 15.12 ;
    END
  END o[34]
  PIN o[35]
    DIRECTION OUTPUT ;
    USE SIGNAL ;
    PORT
      LAYER M5 ;
        RECT  5.52 15.036 5.544 15.12 ;
    END
  END o[35]
  PIN o[36]
    DIRECTION OUTPUT ;
    USE SIGNAL ;
    PORT
      LAYER M5 ;
        RECT  5.616 15.036 5.64 15.12 ;
    END
  END o[36]
  PIN o[37]
    DIRECTION OUTPUT ;
    USE SIGNAL ;
    PORT
      LAYER M5 ;
        RECT  5.712 15.036 5.736 15.12 ;
    END
  END o[37]
  PIN o[38]
    DIRECTION OUTPUT ;
    USE SIGNAL ;
    PORT
      LAYER M5 ;
        RECT  5.808 15.036 5.832 15.12 ;
    END
  END o[38]
  PIN o[39]
    DIRECTION OUTPUT ;
    USE SIGNAL ;
    PORT
      LAYER M5 ;
        RECT  5.904 15.036 5.928 15.12 ;
    END
  END o[39]
  PIN o[3]
    DIRECTION OUTPUT ;
    USE SIGNAL ;
    PORT
      LAYER M5 ;
        RECT  8.592 15.036 8.616 15.12 ;
    END
  END o[3]
  PIN o[40]
    DIRECTION OUTPUT ;
    USE SIGNAL ;
    PORT
      LAYER M5 ;
        RECT  6 15.036 6.024 15.12 ;
    END
  END o[40]
  PIN o[41]
    DIRECTION OUTPUT ;
    USE SIGNAL ;
    PORT
      LAYER M5 ;
        RECT  6.096 15.036 6.12 15.12 ;
    END
  END o[41]
  PIN o[42]
    DIRECTION OUTPUT ;
    USE SIGNAL ;
    PORT
      LAYER M5 ;
        RECT  6.192 15.036 6.216 15.12 ;
    END
  END o[42]
  PIN o[43]
    DIRECTION OUTPUT ;
    USE SIGNAL ;
    PORT
      LAYER M5 ;
        RECT  6.288 15.036 6.312 15.12 ;
    END
  END o[43]
  PIN o[44]
    DIRECTION OUTPUT ;
    USE SIGNAL ;
    PORT
      LAYER M5 ;
        RECT  6.384 15.036 6.408 15.12 ;
    END
  END o[44]
  PIN o[45]
    DIRECTION OUTPUT ;
    USE SIGNAL ;
    PORT
      LAYER M5 ;
        RECT  6.48 15.036 6.504 15.12 ;
    END
  END o[45]
  PIN o[46]
    DIRECTION OUTPUT ;
    USE SIGNAL ;
    PORT
      LAYER M5 ;
        RECT  6.576 15.036 6.6 15.12 ;
    END
  END o[46]
  PIN o[47]
    DIRECTION OUTPUT ;
    USE SIGNAL ;
    PORT
      LAYER M5 ;
        RECT  6.672 15.036 6.696 15.12 ;
    END
  END o[47]
  PIN o[48]
    DIRECTION OUTPUT ;
    USE SIGNAL ;
    PORT
      LAYER M5 ;
        RECT  6.768 15.036 6.792 15.12 ;
    END
  END o[48]
  PIN o[49]
    DIRECTION OUTPUT ;
    USE SIGNAL ;
    PORT
      LAYER M5 ;
        RECT  6.864 15.036 6.888 15.12 ;
    END
  END o[49]
  PIN o[4]
    DIRECTION OUTPUT ;
    USE SIGNAL ;
    PORT
      LAYER M5 ;
        RECT  8.688 15.036 8.712 15.12 ;
    END
  END o[4]
  PIN o[50]
    DIRECTION OUTPUT ;
    USE SIGNAL ;
    PORT
      LAYER M5 ;
        RECT  6.96 15.036 6.984 15.12 ;
    END
  END o[50]
  PIN o[51]
    DIRECTION OUTPUT ;
    USE SIGNAL ;
    PORT
      LAYER M5 ;
        RECT  7.056 15.036 7.08 15.12 ;
    END
  END o[51]
  PIN o[52]
    DIRECTION OUTPUT ;
    USE SIGNAL ;
    PORT
      LAYER M5 ;
        RECT  7.152 15.036 7.176 15.12 ;
    END
  END o[52]
  PIN o[53]
    DIRECTION OUTPUT ;
    USE SIGNAL ;
    PORT
      LAYER M5 ;
        RECT  7.248 15.036 7.272 15.12 ;
    END
  END o[53]
  PIN o[54]
    DIRECTION OUTPUT ;
    USE SIGNAL ;
    PORT
      LAYER M5 ;
        RECT  7.344 15.036 7.368 15.12 ;
    END
  END o[54]
  PIN o[55]
    DIRECTION OUTPUT ;
    USE SIGNAL ;
    PORT
      LAYER M5 ;
        RECT  7.44 15.036 7.464 15.12 ;
    END
  END o[55]
  PIN o[56]
    DIRECTION OUTPUT ;
    USE SIGNAL ;
    PORT
      LAYER M5 ;
        RECT  7.536 15.036 7.56 15.12 ;
    END
  END o[56]
  PIN o[57]
    DIRECTION OUTPUT ;
    USE SIGNAL ;
    PORT
      LAYER M5 ;
        RECT  7.632 15.036 7.656 15.12 ;
    END
  END o[57]
  PIN o[58]
    DIRECTION OUTPUT ;
    USE SIGNAL ;
    PORT
      LAYER M5 ;
        RECT  7.728 15.036 7.752 15.12 ;
    END
  END o[58]
  PIN o[59]
    DIRECTION OUTPUT ;
    USE SIGNAL ;
    PORT
      LAYER M5 ;
        RECT  7.824 15.036 7.848 15.12 ;
    END
  END o[59]
  PIN o[5]
    DIRECTION OUTPUT ;
    USE SIGNAL ;
    PORT
      LAYER M5 ;
        RECT  8.784 15.036 8.808 15.12 ;
    END
  END o[5]
  PIN o[60]
    DIRECTION OUTPUT ;
    USE SIGNAL ;
    PORT
      LAYER M5 ;
        RECT  7.92 15.036 7.944 15.12 ;
    END
  END o[60]
  PIN o[61]
    DIRECTION OUTPUT ;
    USE SIGNAL ;
    PORT
      LAYER M5 ;
        RECT  8.016 15.036 8.04 15.12 ;
    END
  END o[61]
  PIN o[62]
    DIRECTION OUTPUT ;
    USE SIGNAL ;
    PORT
      LAYER M5 ;
        RECT  8.112 15.036 8.136 15.12 ;
    END
  END o[62]
  PIN o[63]
    DIRECTION OUTPUT ;
    USE SIGNAL ;
    PORT
      LAYER M5 ;
        RECT  8.208 15.036 8.232 15.12 ;
    END
  END o[63]
  PIN o[64]
    DIRECTION OUTPUT ;
    USE SIGNAL ;
    PORT
      LAYER M5 ;
        RECT  5.04 15.036 5.064 15.12 ;
    END
  END o[64]
  PIN o[65]
    DIRECTION OUTPUT ;
    USE SIGNAL ;
    PORT
      LAYER M5 ;
        RECT  5.136 15.036 5.16 15.12 ;
    END
  END o[65]
  PIN o[6]
    DIRECTION OUTPUT ;
    USE SIGNAL ;
    PORT
      LAYER M5 ;
        RECT  8.88 15.036 8.904 15.12 ;
    END
  END o[6]
  PIN o[7]
    DIRECTION OUTPUT ;
    USE SIGNAL ;
    PORT
      LAYER M5 ;
        RECT  8.976 15.036 9 15.12 ;
    END
  END o[7]
  PIN o[8]
    DIRECTION OUTPUT ;
    USE SIGNAL ;
    PORT
      LAYER M5 ;
        RECT  9.072 15.036 9.096 15.12 ;
    END
  END o[8]
  PIN o[9]
    DIRECTION OUTPUT ;
    USE SIGNAL ;
    PORT
      LAYER M5 ;
        RECT  9.168 15.036 9.192 15.12 ;
    END
  END o[9]
  PIN rs
    DIRECTION INPUT ;
    USE SIGNAL ;
    PORT
      LAYER M4 ;
        RECT  15.036 4.08 15.12 4.104 ;
    END
  END rs
  PIN VDD
    DIRECTION INOUT ;
    USE POWER ;
    PORT
      LAYER M5 ;
        RECT  10.692 2.151 10.812 12.969 ;
        RECT  7.992 2.151 8.112 12.969 ;
        RECT  5.292 2.151 5.412 12.969 ;
        RECT  2.592 2.151 2.712 12.969 ;
    END
  END VDD
  PIN VSS
    DIRECTION INOUT ;
    USE GROUND ;
    PORT
      LAYER M5 ;
        RECT  10.5 2.137 10.62 12.983 ;
        RECT  7.8 2.137 7.92 12.983 ;
        RECT  5.1 2.137 5.22 12.983 ;
        RECT  2.4 2.137 2.52 12.983 ;
    END
  END VSS
  OBS
    LAYER RVTN ;
     RECT  2.16 2.16 12.96 2.295 ;
     RECT  2.16 2.565 12.96 2.835 ;
     RECT  2.16 3.105 12.96 3.375 ;
     RECT  2.16 3.645 12.96 3.915 ;
     RECT  2.16 4.185 12.96 4.455 ;
     RECT  2.16 4.725 12.96 4.995 ;
     RECT  2.16 5.265 12.96 5.535 ;
     RECT  2.16 5.805 12.96 6.075 ;
     RECT  2.16 6.345 12.96 6.615 ;
     RECT  2.16 6.885 12.96 7.155 ;
     RECT  2.16 7.425 12.96 7.695 ;
     RECT  2.16 7.965 12.96 8.235 ;
     RECT  2.16 8.505 12.96 8.775 ;
     RECT  2.16 9.045 12.96 9.315 ;
     RECT  2.16 9.585 12.96 9.855 ;
     RECT  2.16 10.125 12.96 10.395 ;
     RECT  2.16 10.665 12.96 10.935 ;
     RECT  2.16 11.205 12.96 11.475 ;
     RECT  2.16 11.745 12.96 12.015 ;
     RECT  2.16 12.285 12.96 12.555 ;
     RECT  2.16 12.825 12.96 12.96 ;
    LAYER RVTP ;
     RECT  2.16 2.295 12.96 2.565 ;
     RECT  2.16 2.835 12.96 3.105 ;
     RECT  2.16 3.375 12.96 3.645 ;
     RECT  2.16 3.915 12.96 4.185 ;
     RECT  2.16 4.455 12.96 4.725 ;
     RECT  2.16 4.995 12.96 5.265 ;
     RECT  2.16 5.535 12.96 5.805 ;
     RECT  2.16 6.075 12.96 6.345 ;
     RECT  2.16 6.615 12.96 6.885 ;
     RECT  2.16 7.155 12.96 7.425 ;
     RECT  2.16 7.695 12.96 7.965 ;
     RECT  2.16 8.235 12.96 8.505 ;
     RECT  2.16 8.775 12.96 9.045 ;
     RECT  2.16 9.315 12.96 9.585 ;
     RECT  2.16 9.855 12.96 10.125 ;
     RECT  2.16 10.395 12.96 10.665 ;
     RECT  2.16 10.935 12.96 11.205 ;
     RECT  2.16 11.475 12.96 11.745 ;
     RECT  2.16 12.015 12.96 12.285 ;
     RECT  2.16 12.555 12.96 12.825 ;
    LAYER M1 ;
     RECT  2.16 2.151 12.96 12.969 ;
    LAYER M2 ;
     RECT  2.16 2.151 2.875 12.969 ;
     RECT  2.875 2.034 4.711 12.969 ;
     RECT  4.711 1.962 4.963 12.969 ;
     RECT  4.963 1.926 5.647 12.969 ;
     RECT  5.647 1.836 6.835 12.969 ;
     RECT  6.835 1.764 8.411 12.969 ;
     RECT  8.411 1.881 9.059 12.969 ;
     RECT  9.059 1.962 9.347 12.969 ;
     RECT  9.347 2.034 11.471 12.969 ;
     RECT  11.471 2.151 12.96 12.969 ;
     RECT  12.96 4.194 15.035 4.212 ;
    LAYER M3 ;
     RECT  7.38 0.091 7.398 0.139 ;
     RECT  10.476 0.091 10.494 0.475 ;
     RECT  6.768 0.139 7.398 0.523 ;
     RECT  8.136 0.091 9.378 0.523 ;
     RECT  10.26 0.475 10.854 0.523 ;
     RECT  6.768 0.523 10.854 0.571 ;
     RECT  11.916 0.091 11.934 0.571 ;
     RECT  6.768 0.571 12.15 0.667 ;
     RECT  6.768 0.667 12.582 1.195 ;
     RECT  6.732 1.195 12.582 1.243 ;
     RECT  6.264 1.243 12.582 1.723 ;
     RECT  5.292 0.091 5.31 1.831 ;
     RECT  6.264 1.723 12.834 1.831 ;
     RECT  5.292 1.831 12.834 1.921 ;
     RECT  4.968 1.921 12.834 1.957 ;
     RECT  3.6 1.723 3.618 2.029 ;
     RECT  2.88 2.029 3.618 2.143 ;
     RECT  2.415 2.143 3.618 2.191 ;
     RECT  4.716 1.957 12.834 2.191 ;
     RECT  2.415 2.191 12.834 3.029 ;
     RECT  2.415 3.029 12.798 3.443 ;
     RECT  14.868 3.979 14.886 4.075 ;
     RECT  14.868 4.075 15.03 4.157 ;
     RECT  15.012 4.157 15.03 4.217 ;
     RECT  2.415 3.443 12.762 7.771 ;
     RECT  2.415 7.771 12.834 10.391 ;
     RECT  2.415 10.391 12.726 11.849 ;
     RECT  2.415 11.849 12.654 12.083 ;
     RECT  3.852 12.083 12.654 12.209 ;
     RECT  3.996 12.209 12.654 12.551 ;
     RECT  2.415 12.083 2.697 12.707 ;
     RECT  3.996 12.551 12.15 12.749 ;
     RECT  3.996 12.749 12.006 12.821 ;
     RECT  4.392 12.821 12.006 12.941 ;
     RECT  2.415 12.707 2.505 12.977 ;
     RECT  4.392 12.941 11.682 13.085 ;
     RECT  4.392 13.085 11.538 14.189 ;
     RECT  5.256 14.189 11.538 14.237 ;
     RECT  5.436 14.237 5.886 14.285 ;
     RECT  4.392 14.189 4.41 15.005 ;
     RECT  5.868 14.285 5.886 15.005 ;
     RECT  6.876 14.237 10.134 15.005 ;
     RECT  10.872 14.237 11.538 15.005 ;
    LAYER M4 ;
     RECT  2.408 2.148 2.512 12.972 ;
     RECT  2.512 2.418 2.704 12.702 ;
     RECT  3.589 1.728 3.827 2.28 ;
     RECT  3.827 2.256 3.923 2.28 ;
     RECT  2.704 5.664 4.057 5.688 ;
     RECT  4.057 5.568 4.097 5.688 ;
     RECT  2.704 11.136 4.097 11.16 ;
     RECT  4.381 14.976 5.065 15 ;
     RECT  5.065 3.36 5.101 3.384 ;
     RECT  5.101 2.88 5.108 3.384 ;
     RECT  4.777 4.512 5.108 4.536 ;
     RECT  4.097 5.568 5.108 5.592 ;
     RECT  2.704 7.92 5.108 9 ;
     RECT  5.108 2.148 5.212 12.972 ;
     RECT  5.212 2.256 5.404 12.972 ;
     RECT  5.404 12 5.413 12.972 ;
     RECT  5.065 14.16 5.413 15 ;
     RECT  5.404 5.568 5.465 6.12 ;
     RECT  5.413 12 5.645 15 ;
     RECT  5.465 5.712 5.699 6.12 ;
     RECT  5.404 7.392 5.699 8.76 ;
     RECT  5.404 2.256 5.753 4.536 ;
     RECT  5.645 12.48 5.753 15 ;
     RECT  5.699 7.392 5.825 8.04 ;
     RECT  5.404 10.176 6.041 10.248 ;
     RECT  6.041 10.224 6.179 10.248 ;
     RECT  5.753 12.528 6.545 15 ;
     RECT  5.753 2.256 6.653 3.384 ;
     RECT  6.253 1.248 6.721 1.272 ;
     RECT  5.281 0.096 6.757 0.12 ;
     RECT  6.721 1.2 6.793 1.272 ;
     RECT  6.653 2.304 7.081 3.384 ;
     RECT  5.699 5.712 7.117 5.736 ;
     RECT  7.117 5.712 7.189 6.12 ;
     RECT  6.545 12.528 7.261 12.552 ;
     RECT  6.757 0.096 7.333 0.168 ;
     RECT  6.793 1.152 7.333 1.272 ;
     RECT  7.189 5.712 7.333 6.264 ;
     RECT  7.333 5.712 7.361 6.696 ;
     RECT  5.825 7.728 7.361 8.04 ;
     RECT  7.237 9.936 7.477 9.96 ;
     RECT  7.477 9.936 7.513 10.872 ;
     RECT  6.829 4.464 7.525 4.488 ;
     RECT  7.361 5.712 7.525 8.04 ;
     RECT  7.081 2.304 7.669 3.432 ;
     RECT  7.525 4.464 7.669 8.04 ;
     RECT  7.333 0.096 7.676 1.272 ;
     RECT  7.669 2.304 7.676 8.04 ;
     RECT  7.676 0.096 7.763 8.04 ;
     RECT  7.763 2.148 7.808 8.04 ;
     RECT  7.513 9.552 7.808 10.872 ;
     RECT  7.261 12 7.808 12.552 ;
     RECT  6.545 13.536 7.808 15 ;
     RECT  7.808 2.148 7.912 15 ;
     RECT  7.912 2.208 8.104 15 ;
     RECT  8.104 2.208 8.417 9.144 ;
     RECT  8.104 12 8.417 15 ;
     RECT  8.417 2.208 8.597 9.096 ;
     RECT  8.597 2.208 8.764 5.352 ;
     RECT  8.597 6.768 8.857 9.096 ;
     RECT  8.104 10.848 9.029 10.872 ;
     RECT  8.417 12.528 9.137 15 ;
     RECT  8.764 2.208 9.353 5.112 ;
     RECT  8.857 6.864 9.565 9.096 ;
     RECT  9.137 13.632 9.605 15 ;
     RECT  9.137 12.528 9.673 12.648 ;
     RECT  9.673 12 9.817 12.648 ;
     RECT  9.353 3.36 9.917 5.112 ;
     RECT  9.565 6.864 9.961 9.672 ;
     RECT  9.817 11.376 10.117 12.648 ;
     RECT  7.763 0.096 10.451 1.176 ;
     RECT  9.353 2.256 10.508 2.28 ;
     RECT  9.917 3.36 10.508 5.688 ;
     RECT  9.961 6.72 10.508 9.672 ;
     RECT  10.117 11.376 10.508 13.128 ;
     RECT  10.451 0.096 10.549 0.648 ;
     RECT  10.508 2.148 10.645 13.128 ;
     RECT  10.645 1.728 10.804 13.128 ;
     RECT  10.804 12.432 10.835 13.128 ;
     RECT  10.804 9.888 10.931 11.16 ;
     RECT  10.835 12.432 10.931 13.08 ;
     RECT  10.804 7.44 11.009 8.808 ;
     RECT  9.605 14.208 11.045 15 ;
     RECT  10.931 9.888 11.219 9.912 ;
     RECT  11.009 7.728 11.225 8.808 ;
     RECT  11.225 8.496 11.26 8.808 ;
     RECT  10.549 0.48 11.315 0.648 ;
     RECT  10.804 3.312 11.405 4.728 ;
     RECT  11.26 8.784 11.549 8.808 ;
     RECT  11.045 14.976 11.549 15 ;
     RECT  10.931 11.136 11.693 11.16 ;
     RECT  10.931 12.912 11.693 13.08 ;
     RECT  11.315 0.48 11.905 0.6 ;
     RECT  11.693 12.912 12.017 12.936 ;
     RECT  11.405 3.312 12.089 4.152 ;
     RECT  10.804 1.728 12.121 2.28 ;
     RECT  11.905 0.096 12.275 0.6 ;
     RECT  12.509 0.672 12.593 0.696 ;
     RECT  12.121 1.728 12.845 2.856 ;
     RECT  12.845 1.728 12.889 2.184 ;
     RECT  12.889 2.16 12.947 2.184 ;
     RECT  12.089 4.128 14.857 4.152 ;
     RECT  14.857 3.984 14.897 4.152 ;
     RECT  14.897 3.984 15.084 4.104 ;
    LAYER M5 ;
     RECT  6.864 0.016 12.936 0.131 ;
     RECT  6.96 0.131 12.936 1.187 ;
     RECT  7.056 1.187 8.328 1.235 ;
     RECT  7.152 1.235 8.328 1.283 ;
     RECT  3.792 0.016 3.912 1.763 ;
     RECT  7.728 1.283 8.328 2.051 ;
     RECT  2.4 2.137 2.52 2.151 ;
     RECT  5.1 2.137 5.22 2.151 ;
     RECT  9.744 1.187 12.936 2.195 ;
     RECT  3.888 1.763 3.912 2.291 ;
     RECT  9.744 2.195 12.744 2.291 ;
     RECT  12.336 2.291 12.36 2.387 ;
     RECT  7.8 2.051 8.328 2.819 ;
     RECT  10.5 2.291 10.812 3.397 ;
     RECT  7.8 2.819 8.112 3.925 ;
     RECT  7.8 3.925 8.52 4.117 ;
     RECT  5.1 2.151 5.412 4.501 ;
     RECT  7.68 4.117 8.52 5.125 ;
     RECT  7.536 5.125 8.52 5.317 ;
     RECT  10.224 3.397 10.812 5.653 ;
     RECT  5.1 4.501 5.736 5.747 ;
     RECT  7.536 5.317 8.712 6.229 ;
     RECT  7.2 6.229 8.712 6.757 ;
     RECT  7.2 6.757 8.808 7.237 ;
     RECT  9.936 5.653 10.812 7.237 ;
     RECT  7.2 7.237 10.812 8.485 ;
     RECT  5.1 5.747 5.688 8.771 ;
     RECT  3.936 7.957 3.96 8.963 ;
     RECT  7.2 8.485 11.208 9.923 ;
     RECT  5.1 8.771 5.412 10.165 ;
     RECT  5.1 10.165 6.024 10.213 ;
     RECT  7.2 9.923 10.92 10.451 ;
     RECT  7.2 10.451 10.812 12.421 ;
     RECT  5.1 10.213 6.168 12.517 ;
     RECT  7.2 12.421 10.92 12.517 ;
     RECT  5.1 12.517 10.92 12.901 ;
     RECT  2.4 2.151 2.712 12.969 ;
     RECT  2.4 12.969 2.52 12.983 ;
     RECT  5.1 12.901 11.304 12.983 ;
     RECT  5.424 12.983 11.304 14.149 ;
     RECT  5.136 14.149 11.304 14.965 ;
     RECT  5.04 14.965 11.304 15.056 ;
  END
END dsfd_rly_66_SN

VERSION 5.8 ;
BUSBITCHARS "[]" ;
DIVIDERCHAR "/" ;
UNITS
    DATABASE MICRONS 1000 ;
END UNITS

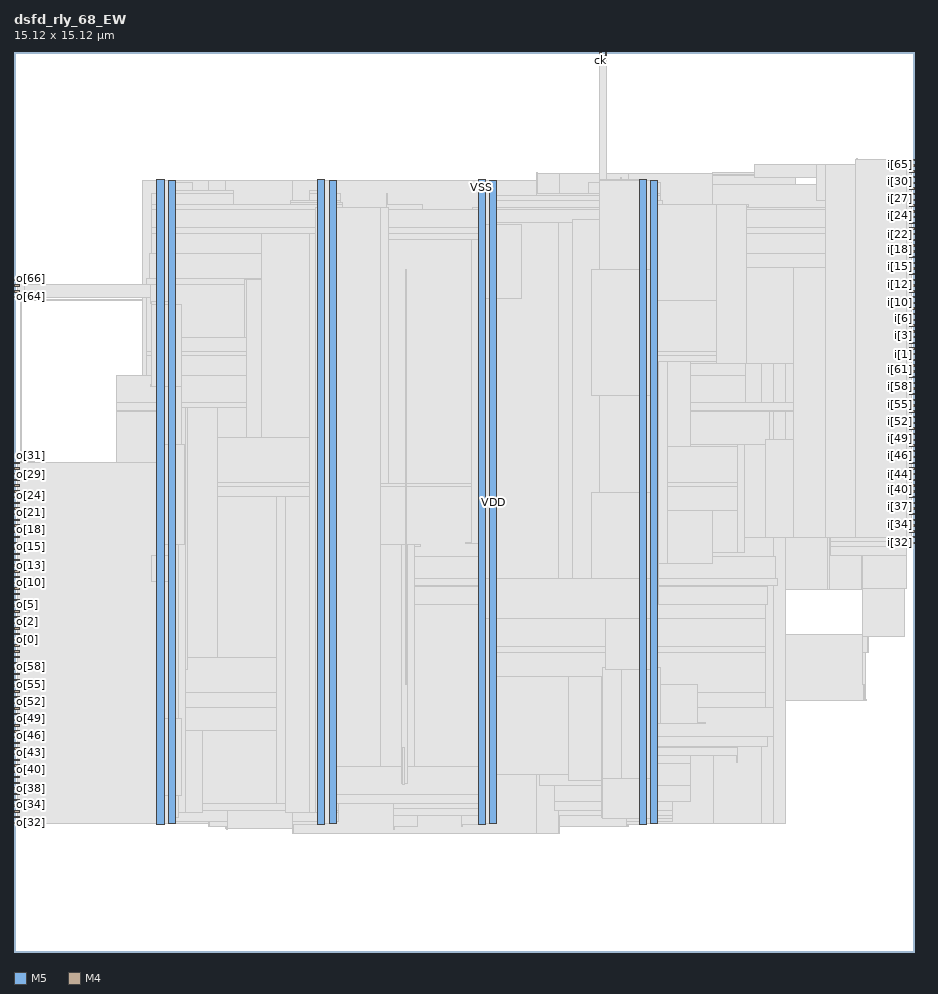
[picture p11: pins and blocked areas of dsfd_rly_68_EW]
MACRO dsfd_rly_68_EW
  FOREIGN dsfd_rly_68_EW 0 0 ;
  CLASS BLOCK ;
  SIZE 15.12 BY 15.12 ;
  PIN ck
    DIRECTION INPUT ;
    USE SIGNAL ;
    PORT
      LAYER M5 ;
        RECT  9.84 15.036 9.864 15.12 ;
    END
  END ck
  PIN i[0]
    DIRECTION INPUT ;
    USE SIGNAL ;
    PORT
      LAYER M4 ;
        RECT  15.036 9.936 15.12 9.96 ;
    END
  END i[0]
  PIN i[10]
    DIRECTION INPUT ;
    USE SIGNAL ;
    PORT
      LAYER M4 ;
        RECT  15.036 10.896 15.12 10.92 ;
    END
  END i[10]
  PIN i[11]
    DIRECTION INPUT ;
    USE SIGNAL ;
    PORT
      LAYER M4 ;
        RECT  15.036 10.992 15.12 11.016 ;
    END
  END i[11]
  PIN i[12]
    DIRECTION INPUT ;
    USE SIGNAL ;
    PORT
      LAYER M4 ;
        RECT  15.036 11.088 15.12 11.112 ;
    END
  END i[12]
  PIN i[13]
    DIRECTION INPUT ;
    USE SIGNAL ;
    PORT
      LAYER M4 ;
        RECT  15.036 11.184 15.12 11.208 ;
    END
  END i[13]
  PIN i[14]
    DIRECTION INPUT ;
    USE SIGNAL ;
    PORT
      LAYER M4 ;
        RECT  15.036 11.28 15.12 11.304 ;
    END
  END i[14]
  PIN i[15]
    DIRECTION INPUT ;
    USE SIGNAL ;
    PORT
      LAYER M4 ;
        RECT  15.036 11.376 15.12 11.4 ;
    END
  END i[15]
  PIN i[16]
    DIRECTION INPUT ;
    USE SIGNAL ;
    PORT
      LAYER M4 ;
        RECT  15.036 11.472 15.12 11.496 ;
    END
  END i[16]
  PIN i[17]
    DIRECTION INPUT ;
    USE SIGNAL ;
    PORT
      LAYER M4 ;
        RECT  15.036 11.568 15.12 11.592 ;
    END
  END i[17]
  PIN i[18]
    DIRECTION INPUT ;
    USE SIGNAL ;
    PORT
      LAYER M4 ;
        RECT  15.036 11.664 15.12 11.688 ;
    END
  END i[18]
  PIN i[19]
    DIRECTION INPUT ;
    USE SIGNAL ;
    PORT
      LAYER M4 ;
        RECT  15.036 11.76 15.12 11.784 ;
    END
  END i[19]
  PIN i[1]
    DIRECTION INPUT ;
    USE SIGNAL ;
    PORT
      LAYER M4 ;
        RECT  15.036 10.032 15.12 10.056 ;
    END
  END i[1]
  PIN i[20]
    DIRECTION INPUT ;
    USE SIGNAL ;
    PORT
      LAYER M4 ;
        RECT  15.036 11.856 15.12 11.88 ;
    END
  END i[20]
  PIN i[21]
    DIRECTION INPUT ;
    USE SIGNAL ;
    PORT
      LAYER M4 ;
        RECT  15.036 11.952 15.12 11.976 ;
    END
  END i[21]
  PIN i[22]
    DIRECTION INPUT ;
    USE SIGNAL ;
    PORT
      LAYER M4 ;
        RECT  15.036 12.048 15.12 12.072 ;
    END
  END i[22]
  PIN i[23]
    DIRECTION INPUT ;
    USE SIGNAL ;
    PORT
      LAYER M4 ;
        RECT  15.036 12.144 15.12 12.168 ;
    END
  END i[23]
  PIN i[24]
    DIRECTION INPUT ;
    USE SIGNAL ;
    PORT
      LAYER M4 ;
        RECT  15.036 12.24 15.12 12.264 ;
    END
  END i[24]
  PIN i[25]
    DIRECTION INPUT ;
    USE SIGNAL ;
    PORT
      LAYER M4 ;
        RECT  15.036 12.336 15.12 12.36 ;
    END
  END i[25]
  PIN i[26]
    DIRECTION INPUT ;
    USE SIGNAL ;
    PORT
      LAYER M4 ;
        RECT  15.036 12.432 15.12 12.456 ;
    END
  END i[26]
  PIN i[27]
    DIRECTION INPUT ;
    USE SIGNAL ;
    PORT
      LAYER M4 ;
        RECT  15.036 12.528 15.12 12.552 ;
    END
  END i[27]
  PIN i[28]
    DIRECTION INPUT ;
    USE SIGNAL ;
    PORT
      LAYER M4 ;
        RECT  15.036 12.624 15.12 12.648 ;
    END
  END i[28]
  PIN i[29]
    DIRECTION INPUT ;
    USE SIGNAL ;
    PORT
      LAYER M4 ;
        RECT  15.036 12.72 15.12 12.744 ;
    END
  END i[29]
  PIN i[2]
    DIRECTION INPUT ;
    USE SIGNAL ;
    PORT
      LAYER M4 ;
        RECT  15.036 10.128 15.12 10.152 ;
    END
  END i[2]
  PIN i[30]
    DIRECTION INPUT ;
    USE SIGNAL ;
    PORT
      LAYER M4 ;
        RECT  15.036 12.816 15.12 12.84 ;
    END
  END i[30]
  PIN i[31]
    DIRECTION INPUT ;
    USE SIGNAL ;
    PORT
      LAYER M4 ;
        RECT  15.036 12.912 15.12 12.936 ;
    END
  END i[31]
  PIN i[32]
    DIRECTION INPUT ;
    USE SIGNAL ;
    PORT
      LAYER M4 ;
        RECT  15.036 6.864 15.12 6.888 ;
    END
  END i[32]
  PIN i[33]
    DIRECTION INPUT ;
    USE SIGNAL ;
    PORT
      LAYER M4 ;
        RECT  15.036 6.96 15.12 6.984 ;
    END
  END i[33]
  PIN i[34]
    DIRECTION INPUT ;
    USE SIGNAL ;
    PORT
      LAYER M4 ;
        RECT  15.036 7.056 15.12 7.08 ;
    END
  END i[34]
  PIN i[35]
    DIRECTION INPUT ;
    USE SIGNAL ;
    PORT
      LAYER M4 ;
        RECT  15.036 7.152 15.12 7.176 ;
    END
  END i[35]
  PIN i[36]
    DIRECTION INPUT ;
    USE SIGNAL ;
    PORT
      LAYER M4 ;
        RECT  15.036 7.248 15.12 7.272 ;
    END
  END i[36]
  PIN i[37]
    DIRECTION INPUT ;
    USE SIGNAL ;
    PORT
      LAYER M4 ;
        RECT  15.036 7.344 15.12 7.368 ;
    END
  END i[37]
  PIN i[38]
    DIRECTION INPUT ;
    USE SIGNAL ;
    PORT
      LAYER M4 ;
        RECT  15.036 7.44 15.12 7.464 ;
    END
  END i[38]
  PIN i[39]
    DIRECTION INPUT ;
    USE SIGNAL ;
    PORT
      LAYER M4 ;
        RECT  15.036 7.536 15.12 7.56 ;
    END
  END i[39]
  PIN i[3]
    DIRECTION INPUT ;
    USE SIGNAL ;
    PORT
      LAYER M4 ;
        RECT  15.036 10.224 15.12 10.248 ;
    END
  END i[3]
  PIN i[40]
    DIRECTION INPUT ;
    USE SIGNAL ;
    PORT
      LAYER M4 ;
        RECT  15.036 7.632 15.12 7.656 ;
    END
  END i[40]
  PIN i[41]
    DIRECTION INPUT ;
    USE SIGNAL ;
    PORT
      LAYER M4 ;
        RECT  15.036 7.728 15.12 7.752 ;
    END
  END i[41]
  PIN i[42]
    DIRECTION INPUT ;
    USE SIGNAL ;
    PORT
      LAYER M4 ;
        RECT  15.036 7.824 15.12 7.848 ;
    END
  END i[42]
  PIN i[43]
    DIRECTION INPUT ;
    USE SIGNAL ;
    PORT
      LAYER M4 ;
        RECT  15.036 7.92 15.12 7.944 ;
    END
  END i[43]
  PIN i[44]
    DIRECTION INPUT ;
    USE SIGNAL ;
    PORT
      LAYER M4 ;
        RECT  15.036 8.016 15.12 8.04 ;
    END
  END i[44]
  PIN i[45]
    DIRECTION INPUT ;
    USE SIGNAL ;
    PORT
      LAYER M4 ;
        RECT  15.036 8.112 15.12 8.136 ;
    END
  END i[45]
  PIN i[46]
    DIRECTION INPUT ;
    USE SIGNAL ;
    PORT
      LAYER M4 ;
        RECT  15.036 8.208 15.12 8.232 ;
    END
  END i[46]
  PIN i[47]
    DIRECTION INPUT ;
    USE SIGNAL ;
    PORT
      LAYER M4 ;
        RECT  15.036 8.304 15.12 8.328 ;
    END
  END i[47]
  PIN i[48]
    DIRECTION INPUT ;
    USE SIGNAL ;
    PORT
      LAYER M4 ;
        RECT  15.036 8.4 15.12 8.424 ;
    END
  END i[48]
  PIN i[49]
    DIRECTION INPUT ;
    USE SIGNAL ;
    PORT
      LAYER M4 ;
        RECT  15.036 8.496 15.12 8.52 ;
    END
  END i[49]
  PIN i[4]
    DIRECTION INPUT ;
    USE SIGNAL ;
    PORT
      LAYER M4 ;
        RECT  15.036 10.32 15.12 10.344 ;
    END
  END i[4]
  PIN i[50]
    DIRECTION INPUT ;
    USE SIGNAL ;
    PORT
      LAYER M4 ;
        RECT  15.036 8.592 15.12 8.616 ;
    END
  END i[50]
  PIN i[51]
    DIRECTION INPUT ;
    USE SIGNAL ;
    PORT
      LAYER M4 ;
        RECT  15.036 8.688 15.12 8.712 ;
    END
  END i[51]
  PIN i[52]
    DIRECTION INPUT ;
    USE SIGNAL ;
    PORT
      LAYER M4 ;
        RECT  15.036 8.784 15.12 8.808 ;
    END
  END i[52]
  PIN i[53]
    DIRECTION INPUT ;
    USE SIGNAL ;
    PORT
      LAYER M4 ;
        RECT  15.036 8.88 15.12 8.904 ;
    END
  END i[53]
  PIN i[54]
    DIRECTION INPUT ;
    USE SIGNAL ;
    PORT
      LAYER M4 ;
        RECT  15.036 8.976 15.12 9 ;
    END
  END i[54]
  PIN i[55]
    DIRECTION INPUT ;
    USE SIGNAL ;
    PORT
      LAYER M4 ;
        RECT  15.036 9.072 15.12 9.096 ;
    END
  END i[55]
  PIN i[56]
    DIRECTION INPUT ;
    USE SIGNAL ;
    PORT
      LAYER M4 ;
        RECT  15.036 9.168 15.12 9.192 ;
    END
  END i[56]
  PIN i[57]
    DIRECTION INPUT ;
    USE SIGNAL ;
    PORT
      LAYER M4 ;
        RECT  15.036 9.264 15.12 9.288 ;
    END
  END i[57]
  PIN i[58]
    DIRECTION INPUT ;
    USE SIGNAL ;
    PORT
      LAYER M4 ;
        RECT  15.036 9.36 15.12 9.384 ;
    END
  END i[58]
  PIN i[59]
    DIRECTION INPUT ;
    USE SIGNAL ;
    PORT
      LAYER M4 ;
        RECT  15.036 9.456 15.12 9.48 ;
    END
  END i[59]
  PIN i[5]
    DIRECTION INPUT ;
    USE SIGNAL ;
    PORT
      LAYER M4 ;
        RECT  15.036 10.416 15.12 10.44 ;
    END
  END i[5]
  PIN i[60]
    DIRECTION INPUT ;
    USE SIGNAL ;
    PORT
      LAYER M4 ;
        RECT  15.036 9.552 15.12 9.576 ;
    END
  END i[60]
  PIN i[61]
    DIRECTION INPUT ;
    USE SIGNAL ;
    PORT
      LAYER M4 ;
        RECT  15.036 9.648 15.12 9.672 ;
    END
  END i[61]
  PIN i[62]
    DIRECTION INPUT ;
    USE SIGNAL ;
    PORT
      LAYER M4 ;
        RECT  15.036 9.744 15.12 9.768 ;
    END
  END i[62]
  PIN i[63]
    DIRECTION INPUT ;
    USE SIGNAL ;
    PORT
      LAYER M4 ;
        RECT  15.036 9.84 15.12 9.864 ;
    END
  END i[63]
  PIN i[64]
    DIRECTION INPUT ;
    USE SIGNAL ;
    PORT
      LAYER M4 ;
        RECT  15.036 13.008 15.12 13.032 ;
    END
  END i[64]
  PIN i[65]
    DIRECTION INPUT ;
    USE SIGNAL ;
    PORT
      LAYER M4 ;
        RECT  15.036 13.104 15.12 13.128 ;
    END
  END i[65]
  PIN i[66]
    DIRECTION INPUT ;
    USE SIGNAL ;
    PORT
      LAYER M4 ;
        RECT  15.036 13.2 15.12 13.224 ;
    END
  END i[66]
  PIN i[67]
    DIRECTION INPUT ;
    USE SIGNAL ;
    PORT
      LAYER M4 ;
        RECT  15.036 13.296 15.12 13.32 ;
    END
  END i[67]
  PIN i[6]
    DIRECTION INPUT ;
    USE SIGNAL ;
    PORT
      LAYER M4 ;
        RECT  15.036 10.512 15.12 10.536 ;
    END
  END i[6]
  PIN i[7]
    DIRECTION INPUT ;
    USE SIGNAL ;
    PORT
      LAYER M4 ;
        RECT  15.036 10.608 15.12 10.632 ;
    END
  END i[7]
  PIN i[8]
    DIRECTION INPUT ;
    USE SIGNAL ;
    PORT
      LAYER M4 ;
        RECT  15.036 10.704 15.12 10.728 ;
    END
  END i[8]
  PIN i[9]
    DIRECTION INPUT ;
    USE SIGNAL ;
    PORT
      LAYER M4 ;
        RECT  15.036 10.8 15.12 10.824 ;
    END
  END i[9]
  PIN o[0]
    DIRECTION OUTPUT ;
    USE SIGNAL ;
    PORT
      LAYER M4 ;
        RECT  0 5.232 0.084 5.256 ;
    END
  END o[0]
  PIN o[10]
    DIRECTION OUTPUT ;
    USE SIGNAL ;
    PORT
      LAYER M4 ;
        RECT  0 6.192 0.084 6.216 ;
    END
  END o[10]
  PIN o[11]
    DIRECTION OUTPUT ;
    USE SIGNAL ;
    PORT
      LAYER M4 ;
        RECT  0 6.288 0.084 6.312 ;
    END
  END o[11]
  PIN o[12]
    DIRECTION OUTPUT ;
    USE SIGNAL ;
    PORT
      LAYER M4 ;
        RECT  0 6.384 0.084 6.408 ;
    END
  END o[12]
  PIN o[13]
    DIRECTION OUTPUT ;
    USE SIGNAL ;
    PORT
      LAYER M4 ;
        RECT  0 6.48 0.084 6.504 ;
    END
  END o[13]
  PIN o[14]
    DIRECTION OUTPUT ;
    USE SIGNAL ;
    PORT
      LAYER M4 ;
        RECT  0 6.576 0.084 6.6 ;
    END
  END o[14]
  PIN o[15]
    DIRECTION OUTPUT ;
    USE SIGNAL ;
    PORT
      LAYER M4 ;
        RECT  0 6.672 0.084 6.696 ;
    END
  END o[15]
  PIN o[16]
    DIRECTION OUTPUT ;
    USE SIGNAL ;
    PORT
      LAYER M4 ;
        RECT  0 6.768 0.084 6.792 ;
    END
  END o[16]
  PIN o[17]
    DIRECTION OUTPUT ;
    USE SIGNAL ;
    PORT
      LAYER M4 ;
        RECT  0 6.864 0.084 6.888 ;
    END
  END o[17]
  PIN o[18]
    DIRECTION OUTPUT ;
    USE SIGNAL ;
    PORT
      LAYER M4 ;
        RECT  0 6.96 0.084 6.984 ;
    END
  END o[18]
  PIN o[19]
    DIRECTION OUTPUT ;
    USE SIGNAL ;
    PORT
      LAYER M4 ;
        RECT  0 7.056 0.084 7.08 ;
    END
  END o[19]
  PIN o[1]
    DIRECTION OUTPUT ;
    USE SIGNAL ;
    PORT
      LAYER M4 ;
        RECT  0 5.328 0.084 5.352 ;
    END
  END o[1]
  PIN o[20]
    DIRECTION OUTPUT ;
    USE SIGNAL ;
    PORT
      LAYER M4 ;
        RECT  0 7.152 0.084 7.176 ;
    END
  END o[20]
  PIN o[21]
    DIRECTION OUTPUT ;
    USE SIGNAL ;
    PORT
      LAYER M4 ;
        RECT  0 7.248 0.084 7.272 ;
    END
  END o[21]
  PIN o[22]
    DIRECTION OUTPUT ;
    USE SIGNAL ;
    PORT
      LAYER M4 ;
        RECT  0 7.344 0.084 7.368 ;
    END
  END o[22]
  PIN o[23]
    DIRECTION OUTPUT ;
    USE SIGNAL ;
    PORT
      LAYER M4 ;
        RECT  0 7.44 0.084 7.464 ;
    END
  END o[23]
  PIN o[24]
    DIRECTION OUTPUT ;
    USE SIGNAL ;
    PORT
      LAYER M4 ;
        RECT  0 7.536 0.084 7.56 ;
    END
  END o[24]
  PIN o[25]
    DIRECTION OUTPUT ;
    USE SIGNAL ;
    PORT
      LAYER M4 ;
        RECT  0 7.632 0.084 7.656 ;
    END
  END o[25]
  PIN o[26]
    DIRECTION OUTPUT ;
    USE SIGNAL ;
    PORT
      LAYER M4 ;
        RECT  0 7.728 0.084 7.752 ;
    END
  END o[26]
  PIN o[27]
    DIRECTION OUTPUT ;
    USE SIGNAL ;
    PORT
      LAYER M4 ;
        RECT  0 7.824 0.084 7.848 ;
    END
  END o[27]
  PIN o[28]
    DIRECTION OUTPUT ;
    USE SIGNAL ;
    PORT
      LAYER M4 ;
        RECT  0 7.92 0.084 7.944 ;
    END
  END o[28]
  PIN o[29]
    DIRECTION OUTPUT ;
    USE SIGNAL ;
    PORT
      LAYER M4 ;
        RECT  0 8.016 0.084 8.04 ;
    END
  END o[29]
  PIN o[2]
    DIRECTION OUTPUT ;
    USE SIGNAL ;
    PORT
      LAYER M4 ;
        RECT  0 5.424 0.084 5.448 ;
    END
  END o[2]
  PIN o[30]
    DIRECTION OUTPUT ;
    USE SIGNAL ;
    PORT
      LAYER M4 ;
        RECT  0 8.112 0.084 8.136 ;
    END
  END o[30]
  PIN o[31]
    DIRECTION OUTPUT ;
    USE SIGNAL ;
    PORT
      LAYER M4 ;
        RECT  0 8.208 0.084 8.232 ;
    END
  END o[31]
  PIN o[32]
    DIRECTION OUTPUT ;
    USE SIGNAL ;
    PORT
      LAYER M4 ;
        RECT  0 2.16 0.084 2.184 ;
    END
  END o[32]
  PIN o[33]
    DIRECTION OUTPUT ;
    USE SIGNAL ;
    PORT
      LAYER M4 ;
        RECT  0 2.256 0.084 2.28 ;
    END
  END o[33]
  PIN o[34]
    DIRECTION OUTPUT ;
    USE SIGNAL ;
    PORT
      LAYER M4 ;
        RECT  0 2.352 0.084 2.376 ;
    END
  END o[34]
  PIN o[35]
    DIRECTION OUTPUT ;
    USE SIGNAL ;
    PORT
      LAYER M4 ;
        RECT  0 2.448 0.084 2.472 ;
    END
  END o[35]
  PIN o[36]
    DIRECTION OUTPUT ;
    USE SIGNAL ;
    PORT
      LAYER M4 ;
        RECT  0 2.544 0.084 2.568 ;
    END
  END o[36]
  PIN o[37]
    DIRECTION OUTPUT ;
    USE SIGNAL ;
    PORT
      LAYER M4 ;
        RECT  0 2.64 0.084 2.664 ;
    END
  END o[37]
  PIN o[38]
    DIRECTION OUTPUT ;
    USE SIGNAL ;
    PORT
      LAYER M4 ;
        RECT  0 2.736 0.084 2.76 ;
    END
  END o[38]
  PIN o[39]
    DIRECTION OUTPUT ;
    USE SIGNAL ;
    PORT
      LAYER M4 ;
        RECT  0 2.832 0.084 2.856 ;
    END
  END o[39]
  PIN o[3]
    DIRECTION OUTPUT ;
    USE SIGNAL ;
    PORT
      LAYER M4 ;
        RECT  0 5.52 0.084 5.544 ;
    END
  END o[3]
  PIN o[40]
    DIRECTION OUTPUT ;
    USE SIGNAL ;
    PORT
      LAYER M4 ;
        RECT  0 2.928 0.084 2.952 ;
    END
  END o[40]
  PIN o[41]
    DIRECTION OUTPUT ;
    USE SIGNAL ;
    PORT
      LAYER M4 ;
        RECT  0 3.024 0.084 3.048 ;
    END
  END o[41]
  PIN o[42]
    DIRECTION OUTPUT ;
    USE SIGNAL ;
    PORT
      LAYER M4 ;
        RECT  0 3.12 0.084 3.144 ;
    END
  END o[42]
  PIN o[43]
    DIRECTION OUTPUT ;
    USE SIGNAL ;
    PORT
      LAYER M4 ;
        RECT  0 3.216 0.084 3.24 ;
    END
  END o[43]
  PIN o[44]
    DIRECTION OUTPUT ;
    USE SIGNAL ;
    PORT
      LAYER M4 ;
        RECT  0 3.312 0.084 3.336 ;
    END
  END o[44]
  PIN o[45]
    DIRECTION OUTPUT ;
    USE SIGNAL ;
    PORT
      LAYER M4 ;
        RECT  0 3.408 0.084 3.432 ;
    END
  END o[45]
  PIN o[46]
    DIRECTION OUTPUT ;
    USE SIGNAL ;
    PORT
      LAYER M4 ;
        RECT  0 3.504 0.084 3.528 ;
    END
  END o[46]
  PIN o[47]
    DIRECTION OUTPUT ;
    USE SIGNAL ;
    PORT
      LAYER M4 ;
        RECT  0 3.6 0.084 3.624 ;
    END
  END o[47]
  PIN o[48]
    DIRECTION OUTPUT ;
    USE SIGNAL ;
    PORT
      LAYER M4 ;
        RECT  0 3.696 0.084 3.72 ;
    END
  END o[48]
  PIN o[49]
    DIRECTION OUTPUT ;
    USE SIGNAL ;
    PORT
      LAYER M4 ;
        RECT  0 3.792 0.084 3.816 ;
    END
  END o[49]
  PIN o[4]
    DIRECTION OUTPUT ;
    USE SIGNAL ;
    PORT
      LAYER M4 ;
        RECT  0 5.616 0.084 5.64 ;
    END
  END o[4]
  PIN o[50]
    DIRECTION OUTPUT ;
    USE SIGNAL ;
    PORT
      LAYER M4 ;
        RECT  0 3.888 0.084 3.912 ;
    END
  END o[50]
  PIN o[51]
    DIRECTION OUTPUT ;
    USE SIGNAL ;
    PORT
      LAYER M4 ;
        RECT  0 3.984 0.084 4.008 ;
    END
  END o[51]
  PIN o[52]
    DIRECTION OUTPUT ;
    USE SIGNAL ;
    PORT
      LAYER M4 ;
        RECT  0 4.08 0.084 4.104 ;
    END
  END o[52]
  PIN o[53]
    DIRECTION OUTPUT ;
    USE SIGNAL ;
    PORT
      LAYER M4 ;
        RECT  0 4.176 0.084 4.2 ;
    END
  END o[53]
  PIN o[54]
    DIRECTION OUTPUT ;
    USE SIGNAL ;
    PORT
      LAYER M4 ;
        RECT  0 4.272 0.084 4.296 ;
    END
  END o[54]
  PIN o[55]
    DIRECTION OUTPUT ;
    USE SIGNAL ;
    PORT
      LAYER M4 ;
        RECT  0 4.368 0.084 4.392 ;
    END
  END o[55]
  PIN o[56]
    DIRECTION OUTPUT ;
    USE SIGNAL ;
    PORT
      LAYER M4 ;
        RECT  0 4.464 0.084 4.488 ;
    END
  END o[56]
  PIN o[57]
    DIRECTION OUTPUT ;
    USE SIGNAL ;
    PORT
      LAYER M4 ;
        RECT  0 4.56 0.084 4.584 ;
    END
  END o[57]
  PIN o[58]
    DIRECTION OUTPUT ;
    USE SIGNAL ;
    PORT
      LAYER M4 ;
        RECT  0 4.656 0.084 4.68 ;
    END
  END o[58]
  PIN o[59]
    DIRECTION OUTPUT ;
    USE SIGNAL ;
    PORT
      LAYER M4 ;
        RECT  0 4.752 0.084 4.776 ;
    END
  END o[59]
  PIN o[5]
    DIRECTION OUTPUT ;
    USE SIGNAL ;
    PORT
      LAYER M4 ;
        RECT  0 5.712 0.084 5.736 ;
    END
  END o[5]
  PIN o[60]
    DIRECTION OUTPUT ;
    USE SIGNAL ;
    PORT
      LAYER M4 ;
        RECT  0 4.848 0.084 4.872 ;
    END
  END o[60]
  PIN o[61]
    DIRECTION OUTPUT ;
    USE SIGNAL ;
    PORT
      LAYER M4 ;
        RECT  0 4.944 0.084 4.968 ;
    END
  END o[61]
  PIN o[62]
    DIRECTION OUTPUT ;
    USE SIGNAL ;
    PORT
      LAYER M4 ;
        RECT  0 5.04 0.084 5.064 ;
    END
  END o[62]
  PIN o[63]
    DIRECTION OUTPUT ;
    USE SIGNAL ;
    PORT
      LAYER M4 ;
        RECT  0 5.136 0.084 5.16 ;
    END
  END o[63]
  PIN o[64]
    DIRECTION OUTPUT ;
    USE SIGNAL ;
    PORT
      LAYER M4 ;
        RECT  0 10.992 0.084 11.016 ;
    END
  END o[64]
  PIN o[65]
    DIRECTION OUTPUT ;
    USE SIGNAL ;
    PORT
      LAYER M4 ;
        RECT  0 11.088 0.084 11.112 ;
    END
  END o[65]
  PIN o[66]
    DIRECTION OUTPUT ;
    USE SIGNAL ;
    PORT
      LAYER M4 ;
        RECT  0 11.184 0.084 11.208 ;
    END
  END o[66]
  PIN o[67]
    DIRECTION OUTPUT ;
    USE SIGNAL ;
    PORT
      LAYER M4 ;
        RECT  0 11.28 0.084 11.304 ;
    END
  END o[67]
  PIN o[6]
    DIRECTION OUTPUT ;
    USE SIGNAL ;
    PORT
      LAYER M4 ;
        RECT  0 5.808 0.084 5.832 ;
    END
  END o[6]
  PIN o[7]
    DIRECTION OUTPUT ;
    USE SIGNAL ;
    PORT
      LAYER M4 ;
        RECT  0 5.904 0.084 5.928 ;
    END
  END o[7]
  PIN o[8]
    DIRECTION OUTPUT ;
    USE SIGNAL ;
    PORT
      LAYER M4 ;
        RECT  0 6 0.084 6.024 ;
    END
  END o[8]
  PIN o[9]
    DIRECTION OUTPUT ;
    USE SIGNAL ;
    PORT
      LAYER M4 ;
        RECT  0 6.096 0.084 6.12 ;
    END
  END o[9]
  PIN rs
    DIRECTION INPUT ;
    USE SIGNAL ;
    PORT
      LAYER M5 ;
        RECT  9.936 15.036 9.96 15.12 ;
    END
  END rs
  PIN VDD
    DIRECTION INOUT ;
    USE POWER ;
    PORT
      LAYER M5 ;
        RECT  10.692 2.151 10.812 12.969 ;
        RECT  7.992 2.151 8.112 12.969 ;
        RECT  5.292 2.151 5.412 12.969 ;
        RECT  2.592 2.151 2.712 12.969 ;
    END
  END VDD
  PIN VSS
    DIRECTION INOUT ;
    USE GROUND ;
    PORT
      LAYER M5 ;
        RECT  10.5 2.137 10.62 12.983 ;
        RECT  7.8 2.137 7.92 12.983 ;
        RECT  5.1 2.137 5.22 12.983 ;
        RECT  2.4 2.137 2.52 12.983 ;
    END
  END VSS
  OBS
    LAYER RVTN ;
     RECT  2.16 2.16 12.96 2.295 ;
     RECT  2.16 2.565 12.96 2.835 ;
     RECT  2.16 3.105 12.96 3.375 ;
     RECT  2.16 3.645 12.96 3.915 ;
     RECT  2.16 4.185 12.96 4.455 ;
     RECT  2.16 4.725 12.96 4.995 ;
     RECT  2.16 5.265 12.96 5.535 ;
     RECT  2.16 5.805 12.96 6.075 ;
     RECT  2.16 6.345 12.96 6.615 ;
     RECT  2.16 6.885 12.96 7.155 ;
     RECT  2.16 7.425 12.96 7.695 ;
     RECT  2.16 7.965 12.96 8.235 ;
     RECT  2.16 8.505 12.96 8.775 ;
     RECT  2.16 9.045 12.96 9.315 ;
     RECT  2.16 9.585 12.96 9.855 ;
     RECT  2.16 10.125 12.96 10.395 ;
     RECT  2.16 10.665 12.96 10.935 ;
     RECT  2.16 11.205 12.96 11.475 ;
     RECT  2.16 11.745 12.96 12.015 ;
     RECT  2.16 12.285 12.96 12.555 ;
     RECT  2.16 12.825 12.96 12.96 ;
    LAYER RVTP ;
     RECT  2.16 2.295 12.96 2.565 ;
     RECT  2.16 2.835 12.96 3.105 ;
     RECT  2.16 3.375 12.96 3.645 ;
     RECT  2.16 3.915 12.96 4.185 ;
     RECT  2.16 4.455 12.96 4.725 ;
     RECT  2.16 4.995 12.96 5.265 ;
     RECT  2.16 5.535 12.96 5.805 ;
     RECT  2.16 6.075 12.96 6.345 ;
     RECT  2.16 6.615 12.96 6.885 ;
     RECT  2.16 7.155 12.96 7.425 ;
     RECT  2.16 7.695 12.96 7.965 ;
     RECT  2.16 8.235 12.96 8.505 ;
     RECT  2.16 8.775 12.96 9.045 ;
     RECT  2.16 9.315 12.96 9.585 ;
     RECT  2.16 9.855 12.96 10.125 ;
     RECT  2.16 10.395 12.96 10.665 ;
     RECT  2.16 10.935 12.96 11.205 ;
     RECT  2.16 11.475 12.96 11.745 ;
     RECT  2.16 12.015 12.96 12.285 ;
     RECT  2.16 12.555 12.96 12.825 ;
    LAYER M1 ;
     RECT  2.16 2.151 12.96 12.969 ;
    LAYER M2 ;
     RECT  0.103 3.276 0.139 3.294 ;
     RECT  0.139 3.276 0.175 3.672 ;
     RECT  0.103 6.786 0.175 7.344 ;
     RECT  0.175 3.114 0.211 3.672 ;
     RECT  0.175 6.156 0.211 7.344 ;
     RECT  0.211 6.156 0.347 7.839 ;
     RECT  0.211 2.574 0.823 3.672 ;
     RECT  0.347 6.156 1.723 7.344 ;
     RECT  1.723 6.12 2.155 7.344 ;
     RECT  0.823 2.574 2.16 4.284 ;
     RECT  2.155 6.012 2.16 7.614 ;
     RECT  1.723 9.666 2.16 9.684 ;
     RECT  0.103 10.944 2.16 10.962 ;
     RECT  2.16 2.151 3.271 12.969 ;
     RECT  3.271 2.106 3.559 12.969 ;
     RECT  3.559 2.07 4.675 12.969 ;
     RECT  4.675 1.998 8.779 12.969 ;
     RECT  8.779 1.998 9.167 13.086 ;
     RECT  9.167 2.106 10.319 13.086 ;
     RECT  10.319 2.151 11.759 13.086 ;
     RECT  11.759 2.151 12.551 13.05 ;
     RECT  12.551 2.151 12.767 13.014 ;
     RECT  12.767 2.151 12.96 12.969 ;
     RECT  12.96 6.084 13.667 12.888 ;
     RECT  13.667 6.084 13.703 12.816 ;
     RECT  13.703 6.084 14.243 7.146 ;
     RECT  13.703 8.046 14.243 12.816 ;
     RECT  12.96 4.23 14.279 5.328 ;
     RECT  14.243 12.798 14.279 12.816 ;
     RECT  14.279 4.23 14.315 4.248 ;
     RECT  14.243 8.046 14.315 9.882 ;
     RECT  14.279 5.04 14.351 5.328 ;
     RECT  14.315 8.046 14.351 8.532 ;
     RECT  14.315 9.36 14.387 9.882 ;
     RECT  14.243 6.084 14.927 6.84 ;
     RECT  14.351 5.31 14.963 5.328 ;
     RECT  14.927 6.12 14.999 6.84 ;
     RECT  14.351 8.478 14.999 8.532 ;
     RECT  14.387 9.63 14.999 9.882 ;
     RECT  14.999 6.822 15.035 6.84 ;
     RECT  14.999 8.514 15.035 8.532 ;
     RECT  14.999 9.63 15.035 9.648 ;
     RECT  14.243 10.836 15.035 11.97 ;
    LAYER M3 ;
     RECT  3.564 2.065 3.582 2.101 ;
     RECT  6.372 2.065 6.39 2.101 ;
     RECT  4.68 1.993 4.698 2.143 ;
     RECT  7.524 2.101 7.542 2.143 ;
     RECT  10.296 2.101 10.314 2.143 ;
     RECT  2.415 2.143 2.505 2.155 ;
     RECT  2.304 2.155 2.505 2.191 ;
     RECT  3.276 2.101 3.582 2.191 ;
     RECT  4.68 2.143 5.205 2.191 ;
     RECT  10.296 2.143 10.605 2.191 ;
     RECT  10.296 2.191 11.07 2.251 ;
     RECT  6.372 2.101 6.786 2.299 ;
     RECT  7.524 2.143 7.905 2.299 ;
     RECT  9.144 1.993 9.162 2.299 ;
     RECT  9.9 2.251 11.07 2.299 ;
     RECT  4.68 2.191 5.454 2.347 ;
     RECT  2.304 2.191 3.582 2.371 ;
     RECT  4.572 2.347 5.454 2.371 ;
     RECT  9.144 2.299 11.07 2.371 ;
     RECT  6.372 2.299 7.905 2.413 ;
     RECT  2.304 2.371 5.454 2.497 ;
     RECT  6.372 2.413 8.097 2.497 ;
     RECT  9.072 2.371 11.07 2.533 ;
     RECT  1.26 2.443 1.278 2.539 ;
     RECT  1.152 2.539 1.278 2.573 ;
     RECT  0.216 2.569 0.234 2.635 ;
     RECT  1.152 2.573 1.17 2.635 ;
     RECT  2.304 2.497 8.097 2.641 ;
     RECT  9.072 2.533 11.358 2.803 ;
     RECT  0.216 2.635 1.17 2.813 ;
     RECT  0.216 2.813 0.846 2.923 ;
     RECT  2.268 2.641 8.097 3.163 ;
     RECT  8.82 2.803 11.358 3.163 ;
     RECT  0.144 2.923 0.846 3.271 ;
     RECT  2.268 3.163 11.358 3.307 ;
     RECT  12.132 3.181 12.15 3.307 ;
     RECT  2.268 3.307 12.15 3.443 ;
     RECT  2.304 3.443 12.15 3.451 ;
     RECT  2.304 3.451 12.654 3.613 ;
     RECT  0.108 3.271 0.846 3.629 ;
     RECT  0.144 3.629 0.846 3.649 ;
     RECT  0.144 3.649 1.17 3.749 ;
     RECT  0.144 3.749 0.846 4.109 ;
     RECT  2.304 3.613 12.762 4.109 ;
     RECT  0.828 4.109 0.846 4.289 ;
     RECT  2.304 4.109 12.618 4.363 ;
     RECT  14.292 4.225 14.31 4.495 ;
     RECT  2.268 4.363 12.618 5.035 ;
     RECT  14.256 4.495 14.31 5.035 ;
     RECT  1.728 5.035 12.618 5.131 ;
     RECT  14.256 5.035 14.346 5.305 ;
     RECT  0.144 5.323 0.162 5.501 ;
     RECT  1.152 5.131 12.618 5.597 ;
     RECT  1.728 5.597 12.618 5.845 ;
     RECT  14.256 5.305 14.958 6.115 ;
     RECT  1.728 5.845 12.654 6.143 ;
     RECT  1.764 6.143 12.654 6.151 ;
     RECT  1.764 6.151 12.834 6.269 ;
     RECT  0.18 6.151 0.198 6.331 ;
     RECT  1.764 6.269 12.798 6.647 ;
     RECT  14.256 6.115 14.994 6.655 ;
     RECT  0.144 6.331 0.198 6.781 ;
     RECT  13.716 6.655 14.994 6.817 ;
     RECT  13.716 6.817 15.03 6.893 ;
     RECT  13.716 6.893 14.994 7.195 ;
     RECT  0.108 6.781 0.198 7.469 ;
     RECT  0.144 7.469 0.198 7.627 ;
     RECT  13.68 7.195 14.994 7.627 ;
     RECT  13.644 7.627 14.994 7.799 ;
     RECT  1.764 6.647 12.762 7.819 ;
     RECT  1.728 7.819 12.762 7.889 ;
     RECT  0.144 7.627 0.342 8.203 ;
     RECT  0.108 8.203 0.342 8.237 ;
     RECT  13.68 7.799 14.994 8.509 ;
     RECT  13.68 8.509 15.03 8.815 ;
     RECT  1.728 7.889 12.69 9.085 ;
     RECT  13.644 8.815 15.03 9.085 ;
     RECT  1.728 9.085 15.03 9.101 ;
     RECT  1.728 9.101 13.122 9.239 ;
     RECT  1.728 9.239 12.294 9.689 ;
     RECT  2.232 9.689 12.294 10.021 ;
     RECT  13.104 9.239 13.122 10.021 ;
     RECT  2.232 10.021 13.122 10.093 ;
     RECT  14.22 9.101 15.03 10.093 ;
     RECT  0.108 8.237 0.126 10.967 ;
     RECT  0.144 11.131 0.162 11.309 ;
     RECT  2.232 10.093 15.03 11.309 ;
     RECT  2.268 11.309 15.03 11.741 ;
     RECT  2.304 11.741 15.03 12.077 ;
     RECT  2.304 12.077 14.346 12.173 ;
     RECT  2.304 12.173 14.274 12.479 ;
     RECT  7.704 12.479 14.274 12.515 ;
     RECT  2.304 12.479 5.526 12.551 ;
     RECT  6.264 12.479 6.858 12.551 ;
     RECT  4.644 12.551 5.526 12.587 ;
     RECT  4.644 12.587 5.49 12.623 ;
     RECT  7.815 12.515 10.89 12.623 ;
     RECT  7.815 12.623 10.854 12.707 ;
     RECT  2.304 12.551 3.69 12.749 ;
     RECT  4.968 12.623 5.49 12.749 ;
     RECT  6.264 12.551 6.282 12.749 ;
     RECT  8.784 12.707 10.854 12.749 ;
     RECT  2.415 12.749 3.69 12.785 ;
     RECT  4.968 12.749 5.205 12.785 ;
     RECT  11.736 12.515 14.274 12.893 ;
     RECT  2.415 12.785 3.006 12.929 ;
     RECT  9.648 12.749 10.854 12.929 ;
     RECT  9.9 12.929 10.605 12.941 ;
     RECT  2.415 12.929 2.505 12.977 ;
     RECT  5.115 12.785 5.205 12.977 ;
     RECT  7.815 12.707 7.905 12.977 ;
     RECT  10.188 12.941 10.605 12.977 ;
     RECT  10.188 12.977 10.206 13.019 ;
     RECT  11.736 12.893 13.122 13.037 ;
     RECT  11.736 13.037 12.546 13.055 ;
     RECT  8.784 12.749 8.802 13.091 ;
     RECT  11.736 13.055 12.474 13.091 ;
     RECT  14.148 12.893 14.274 13.133 ;
     RECT  12.456 13.091 12.474 13.229 ;
     RECT  14.148 13.133 14.166 13.325 ;
    LAYER M4 ;
     RECT  0.06 10.992 0.173 11.304 ;
     RECT  0.173 10.992 2.293 11.208 ;
     RECT  0.06 2.16 2.408 8.232 ;
     RECT  2.293 9.504 2.408 9.528 ;
     RECT  2.293 10.896 2.408 11.208 ;
     RECT  2.408 2.148 2.512 12.972 ;
     RECT  2.512 2.256 2.704 12.702 ;
     RECT  2.704 2.256 2.765 9.144 ;
     RECT  2.765 2.352 2.873 9.144 ;
     RECT  2.873 4.752 2.909 9.144 ;
     RECT  2.873 2.352 3.161 3.72 ;
     RECT  2.909 4.944 3.413 9.144 ;
     RECT  2.704 10.32 3.877 11.208 ;
     RECT  3.413 8.64 3.913 9.144 ;
     RECT  3.877 10.32 3.913 11.304 ;
     RECT  3.913 8.64 4.165 11.304 ;
     RECT  3.161 2.496 4.417 3.72 ;
     RECT  3.413 4.944 4.417 7.656 ;
     RECT  4.417 2.496 4.561 7.656 ;
     RECT  4.561 2.352 4.957 7.656 ;
     RECT  4.165 8.64 4.957 12.072 ;
     RECT  4.957 2.352 5.065 12.072 ;
     RECT  5.065 2.352 5.108 12.504 ;
     RECT  5.108 2.148 5.212 12.972 ;
     RECT  5.212 2.418 5.404 12.702 ;
     RECT  5.404 3.12 6.149 12.504 ;
     RECT  6.149 7.872 6.293 12.504 ;
     RECT  6.149 3.12 6.517 6.84 ;
     RECT  6.517 2.832 6.604 6.84 ;
     RECT  6.604 3.12 6.725 6.84 ;
     RECT  6.725 6.816 6.833 6.84 ;
     RECT  7.585 6.864 7.693 6.888 ;
     RECT  6.293 7.872 7.693 11.976 ;
     RECT  6.725 3.12 7.808 5.832 ;
     RECT  7.693 6.864 7.808 11.976 ;
     RECT  7.808 2.148 7.912 12.972 ;
     RECT  7.912 2.418 8.104 12.702 ;
     RECT  8.104 5.616 9.148 12.264 ;
     RECT  8.104 2.976 9.313 4.632 ;
     RECT  9.148 5.76 9.385 12.264 ;
     RECT  9.313 2.88 9.877 4.632 ;
     RECT  9.877 2.256 9.884 4.632 ;
     RECT  9.385 5.76 9.884 12.312 ;
     RECT  9.884 2.256 10.213 4.776 ;
     RECT  9.884 5.76 10.213 12.936 ;
     RECT  10.213 2.256 10.508 12.936 ;
     RECT  10.508 2.148 10.612 12.972 ;
     RECT  10.612 2.418 10.804 12.702 ;
     RECT  10.804 5.856 10.829 9.912 ;
     RECT  10.804 3.84 10.865 4.776 ;
     RECT  10.829 6.528 10.973 9.912 ;
     RECT  10.973 8.496 11.369 9.912 ;
     RECT  10.865 3.84 11.477 4.488 ;
     RECT  11.477 3.84 11.621 3.864 ;
     RECT  10.973 6.528 11.729 7.416 ;
     RECT  11.369 9.888 11.797 9.912 ;
     RECT  10.804 10.944 11.797 12.552 ;
     RECT  11.729 6.72 12.157 7.416 ;
     RECT  11.369 8.496 12.157 8.52 ;
     RECT  12.157 6.72 12.269 8.52 ;
     RECT  11.797 9.888 12.305 12.552 ;
     RECT  12.305 12.528 12.341 12.552 ;
     RECT  12.269 6.96 12.625 8.52 ;
     RECT  12.625 6.96 13.093 8.616 ;
     RECT  12.305 9.888 13.093 11.496 ;
     RECT  12.445 13.008 13.489 13.224 ;
     RECT  13.093 6.96 13.633 11.496 ;
     RECT  13.489 12.624 13.633 13.224 ;
     RECT  13.633 6.96 14.137 13.224 ;
     RECT  14.137 6.96 15.001 13.32 ;
     RECT  15.001 6.864 15.084 13.32 ;
    LAYER M5 ;
     RECT  2.4 2.137 2.52 2.151 ;
     RECT  5.1 2.137 5.22 2.151 ;
     RECT  7.8 2.137 7.92 2.151 ;
     RECT  10.5 2.137 10.62 2.151 ;
     RECT  10.5 2.151 10.812 2.245 ;
     RECT  2.4 2.151 2.712 2.629 ;
     RECT  9.888 2.245 10.812 2.915 ;
     RECT  6.528 2.821 6.552 3.443 ;
     RECT  2.4 2.629 2.808 3.923 ;
     RECT  10.5 2.915 10.812 4.741 ;
     RECT  7.8 2.151 8.112 5.605 ;
     RECT  9.936 4.741 10.812 5.605 ;
     RECT  2.4 3.923 2.712 6.229 ;
     RECT  7.8 5.605 10.812 6.275 ;
     RECT  2.304 6.229 2.712 6.659 ;
     RECT  2.4 6.659 2.712 6.853 ;
     RECT  9.696 6.275 10.812 7.715 ;
     RECT  2.4 6.853 2.856 8.531 ;
     RECT  9.84 7.715 10.812 9.349 ;
     RECT  2.4 8.531 2.808 9.493 ;
     RECT  2.304 9.493 2.808 10.883 ;
     RECT  2.304 10.883 2.712 10.931 ;
     RECT  7.8 6.275 8.112 10.981 ;
     RECT  6.576 4.501 6.6 11.459 ;
     RECT  9.696 9.349 10.812 11.459 ;
     RECT  7.8 10.981 8.52 12.227 ;
     RECT  2.4 10.931 2.712 12.969 ;
     RECT  5.1 2.151 5.412 12.969 ;
     RECT  7.8 12.227 8.112 12.969 ;
     RECT  9.84 11.459 10.812 12.969 ;
     RECT  2.4 12.969 2.52 12.983 ;
     RECT  5.1 12.969 5.22 12.983 ;
     RECT  7.8 12.969 7.92 12.983 ;
     RECT  9.84 12.969 10.62 12.983 ;
     RECT  9.84 12.983 9.96 15.056 ;
  END
END dsfd_rly_68_EW
END LIBRARY
